VERSION 5.8 ;
BUSBITCHARS "[]" ;
DIVIDERCHAR "/" ;
UNITS
    DATABASE MICRONS 1000 ;
END UNITS

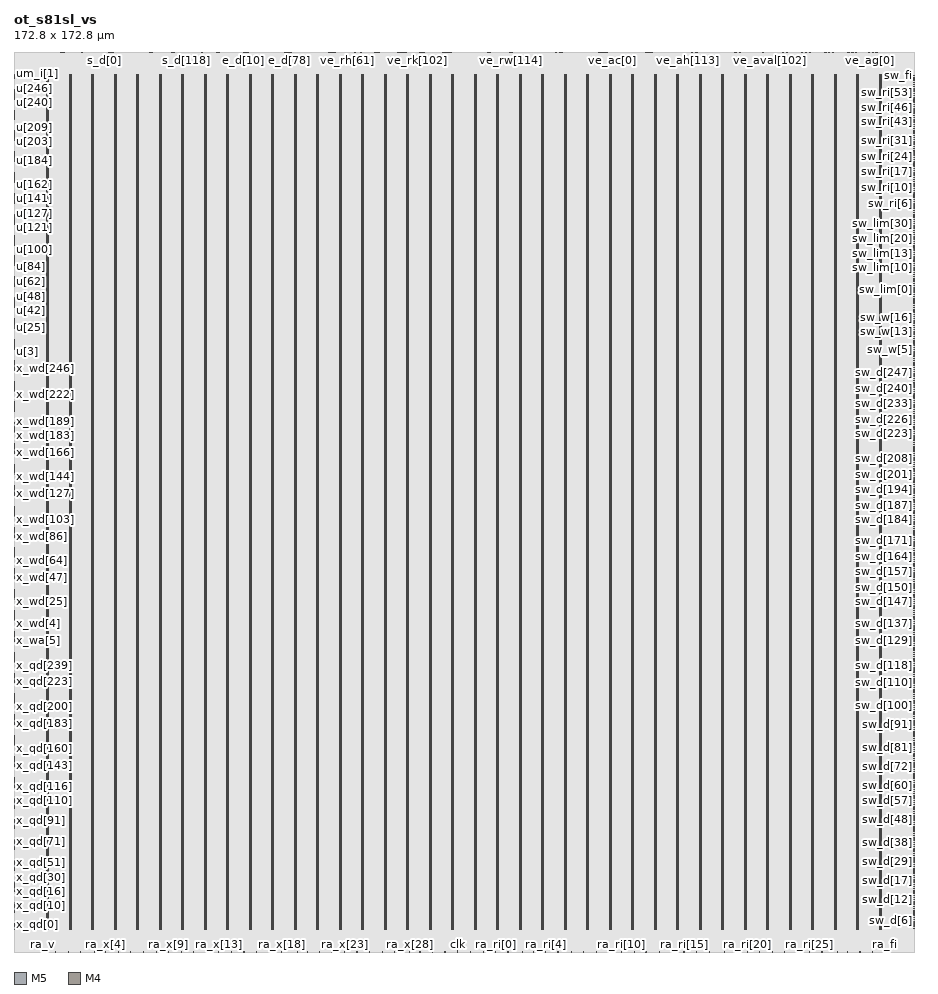
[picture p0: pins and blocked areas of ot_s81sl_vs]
MACRO ot_s81sl_vs
  FOREIGN ot_s81sl_vs 0 0 ;
  CLASS BLOCK ;
  SIZE 172.8 BY 172.8 ;
  PIN clk
    DIRECTION INPUT ;
    USE SIGNAL ;
    PORT
      LAYER M5 ;
        RECT  85.14 0 85.188 0.48 ;
    END
  END clk
  PIN e_c[0]
    DIRECTION OUTPUT ;
    USE SIGNAL ;
    PORT
      LAYER M5 ;
        RECT  42.672 172.716 42.696 172.8 ;
    END
  END e_c[0]
  PIN e_c[1]
    DIRECTION OUTPUT ;
    USE SIGNAL ;
    PORT
      LAYER M5 ;
        RECT  42.768 172.716 42.792 172.8 ;
    END
  END e_c[1]
  PIN e_d[0]
    DIRECTION OUTPUT ;
    USE SIGNAL ;
    PORT
      LAYER M5 ;
        RECT  42.864 172.716 42.888 172.8 ;
    END
  END e_d[0]
  PIN e_d[10]
    DIRECTION OUTPUT ;
    USE SIGNAL ;
    PORT
      LAYER M5 ;
        RECT  43.968 172.716 43.992 172.8 ;
    END
  END e_d[10]
  PIN e_d[11]
    DIRECTION OUTPUT ;
    USE SIGNAL ;
    PORT
      LAYER M5 ;
        RECT  44.16 172.716 44.184 172.8 ;
    END
  END e_d[11]
  PIN e_d[12]
    DIRECTION OUTPUT ;
    USE SIGNAL ;
    PORT
      LAYER M5 ;
        RECT  44.256 172.716 44.28 172.8 ;
    END
  END e_d[12]
  PIN e_d[13]
    DIRECTION OUTPUT ;
    USE SIGNAL ;
    PORT
      LAYER M5 ;
        RECT  44.448 172.716 44.472 172.8 ;
    END
  END e_d[13]
  PIN e_d[14]
    DIRECTION OUTPUT ;
    USE SIGNAL ;
    PORT
      LAYER M5 ;
        RECT  44.544 172.716 44.568 172.8 ;
    END
  END e_d[14]
  PIN e_d[15]
    DIRECTION OUTPUT ;
    USE SIGNAL ;
    PORT
      LAYER M5 ;
        RECT  44.64 172.716 44.664 172.8 ;
    END
  END e_d[15]
  PIN e_d[16]
    DIRECTION OUTPUT ;
    USE SIGNAL ;
    PORT
      LAYER M5 ;
        RECT  44.736 172.716 44.76 172.8 ;
    END
  END e_d[16]
  PIN e_d[17]
    DIRECTION OUTPUT ;
    USE SIGNAL ;
    PORT
      LAYER M5 ;
        RECT  44.928 172.716 44.952 172.8 ;
    END
  END e_d[17]
  PIN e_d[18]
    DIRECTION OUTPUT ;
    USE SIGNAL ;
    PORT
      LAYER M5 ;
        RECT  45.024 172.716 45.048 172.8 ;
    END
  END e_d[18]
  PIN e_d[19]
    DIRECTION OUTPUT ;
    USE SIGNAL ;
    PORT
      LAYER M5 ;
        RECT  45.744 172.716 45.768 172.8 ;
    END
  END e_d[19]
  PIN e_d[1]
    DIRECTION OUTPUT ;
    USE SIGNAL ;
    PORT
      LAYER M5 ;
        RECT  42.96 172.716 42.984 172.8 ;
    END
  END e_d[1]
  PIN e_d[20]
    DIRECTION OUTPUT ;
    USE SIGNAL ;
    PORT
      LAYER M5 ;
        RECT  45.84 172.716 45.864 172.8 ;
    END
  END e_d[20]
  PIN e_d[21]
    DIRECTION OUTPUT ;
    USE SIGNAL ;
    PORT
      LAYER M5 ;
        RECT  45.936 172.716 45.96 172.8 ;
    END
  END e_d[21]
  PIN e_d[22]
    DIRECTION OUTPUT ;
    USE SIGNAL ;
    PORT
      LAYER M5 ;
        RECT  46.032 172.716 46.056 172.8 ;
    END
  END e_d[22]
  PIN e_d[23]
    DIRECTION OUTPUT ;
    USE SIGNAL ;
    PORT
      LAYER M5 ;
        RECT  46.128 172.716 46.152 172.8 ;
    END
  END e_d[23]
  PIN e_d[24]
    DIRECTION OUTPUT ;
    USE SIGNAL ;
    PORT
      LAYER M5 ;
        RECT  46.224 172.716 46.248 172.8 ;
    END
  END e_d[24]
  PIN e_d[25]
    DIRECTION OUTPUT ;
    USE SIGNAL ;
    PORT
      LAYER M5 ;
        RECT  46.32 172.716 46.344 172.8 ;
    END
  END e_d[25]
  PIN e_d[26]
    DIRECTION OUTPUT ;
    USE SIGNAL ;
    PORT
      LAYER M5 ;
        RECT  46.416 172.716 46.44 172.8 ;
    END
  END e_d[26]
  PIN e_d[27]
    DIRECTION OUTPUT ;
    USE SIGNAL ;
    PORT
      LAYER M5 ;
        RECT  46.512 172.716 46.536 172.8 ;
    END
  END e_d[27]
  PIN e_d[28]
    DIRECTION OUTPUT ;
    USE SIGNAL ;
    PORT
      LAYER M5 ;
        RECT  46.608 172.716 46.632 172.8 ;
    END
  END e_d[28]
  PIN e_d[29]
    DIRECTION OUTPUT ;
    USE SIGNAL ;
    PORT
      LAYER M5 ;
        RECT  46.704 172.716 46.728 172.8 ;
    END
  END e_d[29]
  PIN e_d[2]
    DIRECTION OUTPUT ;
    USE SIGNAL ;
    PORT
      LAYER M5 ;
        RECT  43.056 172.716 43.08 172.8 ;
    END
  END e_d[2]
  PIN e_d[30]
    DIRECTION OUTPUT ;
    USE SIGNAL ;
    PORT
      LAYER M5 ;
        RECT  46.8 172.716 46.824 172.8 ;
    END
  END e_d[30]
  PIN e_d[31]
    DIRECTION OUTPUT ;
    USE SIGNAL ;
    PORT
      LAYER M5 ;
        RECT  46.896 172.716 46.92 172.8 ;
    END
  END e_d[31]
  PIN e_d[32]
    DIRECTION OUTPUT ;
    USE SIGNAL ;
    PORT
      LAYER M5 ;
        RECT  46.992 172.716 47.016 172.8 ;
    END
  END e_d[32]
  PIN e_d[33]
    DIRECTION OUTPUT ;
    USE SIGNAL ;
    PORT
      LAYER M5 ;
        RECT  47.088 172.716 47.112 172.8 ;
    END
  END e_d[33]
  PIN e_d[34]
    DIRECTION OUTPUT ;
    USE SIGNAL ;
    PORT
      LAYER M5 ;
        RECT  47.184 172.716 47.208 172.8 ;
    END
  END e_d[34]
  PIN e_d[35]
    DIRECTION OUTPUT ;
    USE SIGNAL ;
    PORT
      LAYER M5 ;
        RECT  47.28 172.716 47.304 172.8 ;
    END
  END e_d[35]
  PIN e_d[36]
    DIRECTION OUTPUT ;
    USE SIGNAL ;
    PORT
      LAYER M5 ;
        RECT  47.376 172.716 47.4 172.8 ;
    END
  END e_d[36]
  PIN e_d[37]
    DIRECTION OUTPUT ;
    USE SIGNAL ;
    PORT
      LAYER M5 ;
        RECT  47.52 172.716 47.544 172.8 ;
    END
  END e_d[37]
  PIN e_d[38]
    DIRECTION OUTPUT ;
    USE SIGNAL ;
    PORT
      LAYER M5 ;
        RECT  47.616 172.716 47.64 172.8 ;
    END
  END e_d[38]
  PIN e_d[39]
    DIRECTION OUTPUT ;
    USE SIGNAL ;
    PORT
      LAYER M5 ;
        RECT  47.808 172.716 47.832 172.8 ;
    END
  END e_d[39]
  PIN e_d[3]
    DIRECTION OUTPUT ;
    USE SIGNAL ;
    PORT
      LAYER M5 ;
        RECT  43.152 172.716 43.176 172.8 ;
    END
  END e_d[3]
  PIN e_d[40]
    DIRECTION OUTPUT ;
    USE SIGNAL ;
    PORT
      LAYER M5 ;
        RECT  47.904 172.716 47.928 172.8 ;
    END
  END e_d[40]
  PIN e_d[41]
    DIRECTION OUTPUT ;
    USE SIGNAL ;
    PORT
      LAYER M5 ;
        RECT  48 172.716 48.024 172.8 ;
    END
  END e_d[41]
  PIN e_d[42]
    DIRECTION OUTPUT ;
    USE SIGNAL ;
    PORT
      LAYER M5 ;
        RECT  48.192 172.716 48.216 172.8 ;
    END
  END e_d[42]
  PIN e_d[43]
    DIRECTION OUTPUT ;
    USE SIGNAL ;
    PORT
      LAYER M5 ;
        RECT  48.288 172.716 48.312 172.8 ;
    END
  END e_d[43]
  PIN e_d[44]
    DIRECTION OUTPUT ;
    USE SIGNAL ;
    PORT
      LAYER M5 ;
        RECT  48.48 172.716 48.504 172.8 ;
    END
  END e_d[44]
  PIN e_d[45]
    DIRECTION OUTPUT ;
    USE SIGNAL ;
    PORT
      LAYER M5 ;
        RECT  48.576 172.716 48.6 172.8 ;
    END
  END e_d[45]
  PIN e_d[46]
    DIRECTION OUTPUT ;
    USE SIGNAL ;
    PORT
      LAYER M5 ;
        RECT  48.672 172.716 48.696 172.8 ;
    END
  END e_d[46]
  PIN e_d[47]
    DIRECTION OUTPUT ;
    USE SIGNAL ;
    PORT
      LAYER M5 ;
        RECT  48.768 172.716 48.792 172.8 ;
    END
  END e_d[47]
  PIN e_d[48]
    DIRECTION OUTPUT ;
    USE SIGNAL ;
    PORT
      LAYER M5 ;
        RECT  48.96 172.716 48.984 172.8 ;
    END
  END e_d[48]
  PIN e_d[49]
    DIRECTION OUTPUT ;
    USE SIGNAL ;
    PORT
      LAYER M5 ;
        RECT  49.056 172.716 49.08 172.8 ;
    END
  END e_d[49]
  PIN e_d[4]
    DIRECTION OUTPUT ;
    USE SIGNAL ;
    PORT
      LAYER M5 ;
        RECT  43.296 172.716 43.32 172.8 ;
    END
  END e_d[4]
  PIN e_d[50]
    DIRECTION OUTPUT ;
    USE SIGNAL ;
    PORT
      LAYER M5 ;
        RECT  49.152 172.716 49.176 172.8 ;
    END
  END e_d[50]
  PIN e_d[51]
    DIRECTION OUTPUT ;
    USE SIGNAL ;
    PORT
      LAYER M5 ;
        RECT  49.344 172.716 49.368 172.8 ;
    END
  END e_d[51]
  PIN e_d[52]
    DIRECTION OUTPUT ;
    USE SIGNAL ;
    PORT
      LAYER M5 ;
        RECT  50.064 172.716 50.088 172.8 ;
    END
  END e_d[52]
  PIN e_d[53]
    DIRECTION OUTPUT ;
    USE SIGNAL ;
    PORT
      LAYER M5 ;
        RECT  50.16 172.716 50.184 172.8 ;
    END
  END e_d[53]
  PIN e_d[54]
    DIRECTION OUTPUT ;
    USE SIGNAL ;
    PORT
      LAYER M5 ;
        RECT  50.256 172.716 50.28 172.8 ;
    END
  END e_d[54]
  PIN e_d[55]
    DIRECTION OUTPUT ;
    USE SIGNAL ;
    PORT
      LAYER M5 ;
        RECT  50.352 172.716 50.376 172.8 ;
    END
  END e_d[55]
  PIN e_d[56]
    DIRECTION OUTPUT ;
    USE SIGNAL ;
    PORT
      LAYER M5 ;
        RECT  50.448 172.716 50.472 172.8 ;
    END
  END e_d[56]
  PIN e_d[57]
    DIRECTION OUTPUT ;
    USE SIGNAL ;
    PORT
      LAYER M5 ;
        RECT  50.544 172.716 50.568 172.8 ;
    END
  END e_d[57]
  PIN e_d[58]
    DIRECTION OUTPUT ;
    USE SIGNAL ;
    PORT
      LAYER M5 ;
        RECT  50.64 172.716 50.664 172.8 ;
    END
  END e_d[58]
  PIN e_d[59]
    DIRECTION OUTPUT ;
    USE SIGNAL ;
    PORT
      LAYER M5 ;
        RECT  50.736 172.716 50.76 172.8 ;
    END
  END e_d[59]
  PIN e_d[5]
    DIRECTION OUTPUT ;
    USE SIGNAL ;
    PORT
      LAYER M5 ;
        RECT  43.392 172.716 43.416 172.8 ;
    END
  END e_d[5]
  PIN e_d[60]
    DIRECTION OUTPUT ;
    USE SIGNAL ;
    PORT
      LAYER M5 ;
        RECT  50.832 172.716 50.856 172.8 ;
    END
  END e_d[60]
  PIN e_d[61]
    DIRECTION OUTPUT ;
    USE SIGNAL ;
    PORT
      LAYER M5 ;
        RECT  50.928 172.716 50.952 172.8 ;
    END
  END e_d[61]
  PIN e_d[62]
    DIRECTION OUTPUT ;
    USE SIGNAL ;
    PORT
      LAYER M5 ;
        RECT  51.024 172.716 51.048 172.8 ;
    END
  END e_d[62]
  PIN e_d[63]
    DIRECTION OUTPUT ;
    USE SIGNAL ;
    PORT
      LAYER M5 ;
        RECT  51.12 172.716 51.144 172.8 ;
    END
  END e_d[63]
  PIN e_d[64]
    DIRECTION OUTPUT ;
    USE SIGNAL ;
    PORT
      LAYER M5 ;
        RECT  51.216 172.716 51.24 172.8 ;
    END
  END e_d[64]
  PIN e_d[65]
    DIRECTION OUTPUT ;
    USE SIGNAL ;
    PORT
      LAYER M5 ;
        RECT  51.312 172.716 51.336 172.8 ;
    END
  END e_d[65]
  PIN e_d[66]
    DIRECTION OUTPUT ;
    USE SIGNAL ;
    PORT
      LAYER M5 ;
        RECT  51.408 172.716 51.432 172.8 ;
    END
  END e_d[66]
  PIN e_d[67]
    DIRECTION OUTPUT ;
    USE SIGNAL ;
    PORT
      LAYER M5 ;
        RECT  51.504 172.716 51.528 172.8 ;
    END
  END e_d[67]
  PIN e_d[68]
    DIRECTION OUTPUT ;
    USE SIGNAL ;
    PORT
      LAYER M5 ;
        RECT  51.6 172.716 51.624 172.8 ;
    END
  END e_d[68]
  PIN e_d[69]
    DIRECTION OUTPUT ;
    USE SIGNAL ;
    PORT
      LAYER M5 ;
        RECT  51.696 172.716 51.72 172.8 ;
    END
  END e_d[69]
  PIN e_d[6]
    DIRECTION OUTPUT ;
    USE SIGNAL ;
    PORT
      LAYER M5 ;
        RECT  43.488 172.716 43.512 172.8 ;
    END
  END e_d[6]
  PIN e_d[70]
    DIRECTION OUTPUT ;
    USE SIGNAL ;
    PORT
      LAYER M5 ;
        RECT  51.792 172.716 51.816 172.8 ;
    END
  END e_d[70]
  PIN e_d[71]
    DIRECTION OUTPUT ;
    USE SIGNAL ;
    PORT
      LAYER M5 ;
        RECT  51.936 172.716 51.96 172.8 ;
    END
  END e_d[71]
  PIN e_d[72]
    DIRECTION OUTPUT ;
    USE SIGNAL ;
    PORT
      LAYER M5 ;
        RECT  52.032 172.716 52.056 172.8 ;
    END
  END e_d[72]
  PIN e_d[73]
    DIRECTION OUTPUT ;
    USE SIGNAL ;
    PORT
      LAYER M5 ;
        RECT  52.224 172.716 52.248 172.8 ;
    END
  END e_d[73]
  PIN e_d[74]
    DIRECTION OUTPUT ;
    USE SIGNAL ;
    PORT
      LAYER M5 ;
        RECT  52.32 172.716 52.344 172.8 ;
    END
  END e_d[74]
  PIN e_d[75]
    DIRECTION OUTPUT ;
    USE SIGNAL ;
    PORT
      LAYER M5 ;
        RECT  52.416 172.716 52.44 172.8 ;
    END
  END e_d[75]
  PIN e_d[76]
    DIRECTION OUTPUT ;
    USE SIGNAL ;
    PORT
      LAYER M5 ;
        RECT  52.512 172.716 52.536 172.8 ;
    END
  END e_d[76]
  PIN e_d[77]
    DIRECTION OUTPUT ;
    USE SIGNAL ;
    PORT
      LAYER M5 ;
        RECT  52.704 172.716 52.728 172.8 ;
    END
  END e_d[77]
  PIN e_d[78]
    DIRECTION OUTPUT ;
    USE SIGNAL ;
    PORT
      LAYER M5 ;
        RECT  52.8 172.716 52.824 172.8 ;
    END
  END e_d[78]
  PIN e_d[79]
    DIRECTION OUTPUT ;
    USE SIGNAL ;
    PORT
      LAYER M5 ;
        RECT  52.992 172.716 53.016 172.8 ;
    END
  END e_d[79]
  PIN e_d[7]
    DIRECTION OUTPUT ;
    USE SIGNAL ;
    PORT
      LAYER M5 ;
        RECT  43.584 172.716 43.608 172.8 ;
    END
  END e_d[7]
  PIN e_d[80]
    DIRECTION OUTPUT ;
    USE SIGNAL ;
    PORT
      LAYER M5 ;
        RECT  53.088 172.716 53.112 172.8 ;
    END
  END e_d[80]
  PIN e_d[81]
    DIRECTION OUTPUT ;
    USE SIGNAL ;
    PORT
      LAYER M5 ;
        RECT  53.184 172.716 53.208 172.8 ;
    END
  END e_d[81]
  PIN e_d[82]
    DIRECTION OUTPUT ;
    USE SIGNAL ;
    PORT
      LAYER M5 ;
        RECT  53.376 172.716 53.4 172.8 ;
    END
  END e_d[82]
  PIN e_d[83]
    DIRECTION OUTPUT ;
    USE SIGNAL ;
    PORT
      LAYER M5 ;
        RECT  53.472 172.716 53.496 172.8 ;
    END
  END e_d[83]
  PIN e_d[84]
    DIRECTION OUTPUT ;
    USE SIGNAL ;
    PORT
      LAYER M5 ;
        RECT  53.664 172.716 53.688 172.8 ;
    END
  END e_d[84]
  PIN e_d[85]
    DIRECTION OUTPUT ;
    USE SIGNAL ;
    PORT
      LAYER M5 ;
        RECT  54.384 172.716 54.408 172.8 ;
    END
  END e_d[85]
  PIN e_d[86]
    DIRECTION OUTPUT ;
    USE SIGNAL ;
    PORT
      LAYER M5 ;
        RECT  54.48 172.716 54.504 172.8 ;
    END
  END e_d[86]
  PIN e_d[87]
    DIRECTION OUTPUT ;
    USE SIGNAL ;
    PORT
      LAYER M5 ;
        RECT  54.576 172.716 54.6 172.8 ;
    END
  END e_d[87]
  PIN e_d[88]
    DIRECTION OUTPUT ;
    USE SIGNAL ;
    PORT
      LAYER M5 ;
        RECT  54.672 172.716 54.696 172.8 ;
    END
  END e_d[88]
  PIN e_d[89]
    DIRECTION OUTPUT ;
    USE SIGNAL ;
    PORT
      LAYER M5 ;
        RECT  54.768 172.716 54.792 172.8 ;
    END
  END e_d[89]
  PIN e_d[8]
    DIRECTION OUTPUT ;
    USE SIGNAL ;
    PORT
      LAYER M5 ;
        RECT  43.776 172.716 43.8 172.8 ;
    END
  END e_d[8]
  PIN e_d[90]
    DIRECTION OUTPUT ;
    USE SIGNAL ;
    PORT
      LAYER M5 ;
        RECT  54.864 172.716 54.888 172.8 ;
    END
  END e_d[90]
  PIN e_d[91]
    DIRECTION OUTPUT ;
    USE SIGNAL ;
    PORT
      LAYER M5 ;
        RECT  54.96 172.716 54.984 172.8 ;
    END
  END e_d[91]
  PIN e_d[92]
    DIRECTION OUTPUT ;
    USE SIGNAL ;
    PORT
      LAYER M5 ;
        RECT  55.056 172.716 55.08 172.8 ;
    END
  END e_d[92]
  PIN e_d[93]
    DIRECTION OUTPUT ;
    USE SIGNAL ;
    PORT
      LAYER M5 ;
        RECT  55.152 172.716 55.176 172.8 ;
    END
  END e_d[93]
  PIN e_d[94]
    DIRECTION OUTPUT ;
    USE SIGNAL ;
    PORT
      LAYER M5 ;
        RECT  55.248 172.716 55.272 172.8 ;
    END
  END e_d[94]
  PIN e_d[95]
    DIRECTION OUTPUT ;
    USE SIGNAL ;
    PORT
      LAYER M5 ;
        RECT  55.344 172.716 55.368 172.8 ;
    END
  END e_d[95]
  PIN e_d[9]
    DIRECTION OUTPUT ;
    USE SIGNAL ;
    PORT
      LAYER M5 ;
        RECT  43.872 172.716 43.896 172.8 ;
    END
  END e_d[9]
  PIN e_v
    DIRECTION OUTPUT ;
    USE SIGNAL ;
    PORT
      LAYER M5 ;
        RECT  42.576 172.716 42.6 172.8 ;
    END
  END e_v
  PIN fault
    DIRECTION OUTPUT ;
    USE SIGNAL ;
    PORT
      LAYER M5 ;
        RECT  55.44 172.716 55.464 172.8 ;
    END
  END fault
  PIN g_c[0]
    DIRECTION INPUT ;
    USE SIGNAL ;
    PORT
      LAYER M5 ;
        RECT  38.16 172.716 38.184 172.8 ;
    END
  END g_c[0]
  PIN g_c[1]
    DIRECTION INPUT ;
    USE SIGNAL ;
    PORT
      LAYER M5 ;
        RECT  38.256 172.716 38.28 172.8 ;
    END
  END g_c[1]
  PIN g_d[0]
    DIRECTION INPUT ;
    USE SIGNAL ;
    PORT
      LAYER M5 ;
        RECT  38.352 172.716 38.376 172.8 ;
    END
  END g_d[0]
  PIN g_d[10]
    DIRECTION INPUT ;
    USE SIGNAL ;
    PORT
      LAYER M5 ;
        RECT  39.456 172.716 39.48 172.8 ;
    END
  END g_d[10]
  PIN g_d[11]
    DIRECTION INPUT ;
    USE SIGNAL ;
    PORT
      LAYER M5 ;
        RECT  39.552 172.716 39.576 172.8 ;
    END
  END g_d[11]
  PIN g_d[12]
    DIRECTION INPUT ;
    USE SIGNAL ;
    PORT
      LAYER M5 ;
        RECT  39.744 172.716 39.768 172.8 ;
    END
  END g_d[12]
  PIN g_d[13]
    DIRECTION INPUT ;
    USE SIGNAL ;
    PORT
      LAYER M5 ;
        RECT  39.84 172.716 39.864 172.8 ;
    END
  END g_d[13]
  PIN g_d[14]
    DIRECTION INPUT ;
    USE SIGNAL ;
    PORT
      LAYER M5 ;
        RECT  40.032 172.716 40.056 172.8 ;
    END
  END g_d[14]
  PIN g_d[15]
    DIRECTION INPUT ;
    USE SIGNAL ;
    PORT
      LAYER M5 ;
        RECT  40.128 172.716 40.152 172.8 ;
    END
  END g_d[15]
  PIN g_d[16]
    DIRECTION INPUT ;
    USE SIGNAL ;
    PORT
      LAYER M5 ;
        RECT  40.224 172.716 40.248 172.8 ;
    END
  END g_d[16]
  PIN g_d[17]
    DIRECTION INPUT ;
    USE SIGNAL ;
    PORT
      LAYER M5 ;
        RECT  40.416 172.716 40.44 172.8 ;
    END
  END g_d[17]
  PIN g_d[18]
    DIRECTION INPUT ;
    USE SIGNAL ;
    PORT
      LAYER M5 ;
        RECT  40.512 172.716 40.536 172.8 ;
    END
  END g_d[18]
  PIN g_d[19]
    DIRECTION INPUT ;
    USE SIGNAL ;
    PORT
      LAYER M5 ;
        RECT  40.704 172.716 40.728 172.8 ;
    END
  END g_d[19]
  PIN g_d[1]
    DIRECTION INPUT ;
    USE SIGNAL ;
    PORT
      LAYER M5 ;
        RECT  38.448 172.716 38.472 172.8 ;
    END
  END g_d[1]
  PIN g_d[20]
    DIRECTION INPUT ;
    USE SIGNAL ;
    PORT
      LAYER M5 ;
        RECT  41.424 172.716 41.448 172.8 ;
    END
  END g_d[20]
  PIN g_d[21]
    DIRECTION INPUT ;
    USE SIGNAL ;
    PORT
      LAYER M5 ;
        RECT  41.52 172.716 41.544 172.8 ;
    END
  END g_d[21]
  PIN g_d[22]
    DIRECTION INPUT ;
    USE SIGNAL ;
    PORT
      LAYER M5 ;
        RECT  41.616 172.716 41.64 172.8 ;
    END
  END g_d[22]
  PIN g_d[23]
    DIRECTION INPUT ;
    USE SIGNAL ;
    PORT
      LAYER M5 ;
        RECT  41.712 172.716 41.736 172.8 ;
    END
  END g_d[23]
  PIN g_d[24]
    DIRECTION INPUT ;
    USE SIGNAL ;
    PORT
      LAYER M5 ;
        RECT  41.808 172.716 41.832 172.8 ;
    END
  END g_d[24]
  PIN g_d[25]
    DIRECTION INPUT ;
    USE SIGNAL ;
    PORT
      LAYER M5 ;
        RECT  41.904 172.716 41.928 172.8 ;
    END
  END g_d[25]
  PIN g_d[26]
    DIRECTION INPUT ;
    USE SIGNAL ;
    PORT
      LAYER M5 ;
        RECT  42 172.716 42.024 172.8 ;
    END
  END g_d[26]
  PIN g_d[27]
    DIRECTION INPUT ;
    USE SIGNAL ;
    PORT
      LAYER M5 ;
        RECT  42.096 172.716 42.12 172.8 ;
    END
  END g_d[27]
  PIN g_d[28]
    DIRECTION INPUT ;
    USE SIGNAL ;
    PORT
      LAYER M5 ;
        RECT  42.192 172.716 42.216 172.8 ;
    END
  END g_d[28]
  PIN g_d[29]
    DIRECTION INPUT ;
    USE SIGNAL ;
    PORT
      LAYER M5 ;
        RECT  42.288 172.716 42.312 172.8 ;
    END
  END g_d[29]
  PIN g_d[2]
    DIRECTION INPUT ;
    USE SIGNAL ;
    PORT
      LAYER M5 ;
        RECT  38.544 172.716 38.568 172.8 ;
    END
  END g_d[2]
  PIN g_d[30]
    DIRECTION INPUT ;
    USE SIGNAL ;
    PORT
      LAYER M5 ;
        RECT  42.384 172.716 42.408 172.8 ;
    END
  END g_d[30]
  PIN g_d[31]
    DIRECTION INPUT ;
    USE SIGNAL ;
    PORT
      LAYER M5 ;
        RECT  42.48 172.716 42.504 172.8 ;
    END
  END g_d[31]
  PIN g_d[3]
    DIRECTION INPUT ;
    USE SIGNAL ;
    PORT
      LAYER M5 ;
        RECT  38.64 172.716 38.664 172.8 ;
    END
  END g_d[3]
  PIN g_d[4]
    DIRECTION INPUT ;
    USE SIGNAL ;
    PORT
      LAYER M5 ;
        RECT  38.736 172.716 38.76 172.8 ;
    END
  END g_d[4]
  PIN g_d[5]
    DIRECTION INPUT ;
    USE SIGNAL ;
    PORT
      LAYER M5 ;
        RECT  38.832 172.716 38.856 172.8 ;
    END
  END g_d[5]
  PIN g_d[6]
    DIRECTION INPUT ;
    USE SIGNAL ;
    PORT
      LAYER M5 ;
        RECT  38.976 172.716 39 172.8 ;
    END
  END g_d[6]
  PIN g_d[7]
    DIRECTION INPUT ;
    USE SIGNAL ;
    PORT
      LAYER M5 ;
        RECT  39.072 172.716 39.096 172.8 ;
    END
  END g_d[7]
  PIN g_d[8]
    DIRECTION INPUT ;
    USE SIGNAL ;
    PORT
      LAYER M5 ;
        RECT  39.264 172.716 39.288 172.8 ;
    END
  END g_d[8]
  PIN g_d[9]
    DIRECTION INPUT ;
    USE SIGNAL ;
    PORT
      LAYER M5 ;
        RECT  39.36 172.716 39.384 172.8 ;
    END
  END g_d[9]
  PIN g_v
    DIRECTION INPUT ;
    USE SIGNAL ;
    PORT
      LAYER M5 ;
        RECT  38.064 172.716 38.088 172.8 ;
    END
  END g_v
  PIN ra_fi
    DIRECTION INPUT ;
    USE SIGNAL ;
    PORT
      LAYER M5 ;
        RECT  167.232 0 167.256 0.084 ;
    END
  END ra_fi
  PIN ra_ri[0]
    DIRECTION INPUT ;
    USE SIGNAL ;
    PORT
      LAYER M5 ;
        RECT  92.448 0 92.472 0.084 ;
    END
  END ra_ri[0]
  PIN ra_ri[10]
    DIRECTION INPUT ;
    USE SIGNAL ;
    PORT
      LAYER M5 ;
        RECT  116.544 0 116.568 0.084 ;
    END
  END ra_ri[10]
  PIN ra_ri[11]
    DIRECTION INPUT ;
    USE SIGNAL ;
    PORT
      LAYER M5 ;
        RECT  119.184 0 119.208 0.084 ;
    END
  END ra_ri[11]
  PIN ra_ri[12]
    DIRECTION INPUT ;
    USE SIGNAL ;
    PORT
      LAYER M5 ;
        RECT  121.344 0 121.368 0.084 ;
    END
  END ra_ri[12]
  PIN ra_ri[13]
    DIRECTION INPUT ;
    USE SIGNAL ;
    PORT
      LAYER M5 ;
        RECT  123.84 0 123.864 0.084 ;
    END
  END ra_ri[13]
  PIN ra_ri[14]
    DIRECTION INPUT ;
    USE SIGNAL ;
    PORT
      LAYER M5 ;
        RECT  126.24 0 126.264 0.084 ;
    END
  END ra_ri[14]
  PIN ra_ri[15]
    DIRECTION INPUT ;
    USE SIGNAL ;
    PORT
      LAYER M5 ;
        RECT  128.64 0 128.664 0.084 ;
    END
  END ra_ri[15]
  PIN ra_ri[16]
    DIRECTION INPUT ;
    USE SIGNAL ;
    PORT
      LAYER M5 ;
        RECT  131.04 0 131.064 0.084 ;
    END
  END ra_ri[16]
  PIN ra_ri[17]
    DIRECTION INPUT ;
    USE SIGNAL ;
    PORT
      LAYER M5 ;
        RECT  133.44 0 133.464 0.084 ;
    END
  END ra_ri[17]
  PIN ra_ri[18]
    DIRECTION INPUT ;
    USE SIGNAL ;
    PORT
      LAYER M5 ;
        RECT  136.464 0 136.488 0.084 ;
    END
  END ra_ri[18]
  PIN ra_ri[19]
    DIRECTION INPUT ;
    USE SIGNAL ;
    PORT
      LAYER M5 ;
        RECT  138.336 0 138.36 0.084 ;
    END
  END ra_ri[19]
  PIN ra_ri[1]
    DIRECTION INPUT ;
    USE SIGNAL ;
    PORT
      LAYER M5 ;
        RECT  94.848 0 94.872 0.084 ;
    END
  END ra_ri[1]
  PIN ra_ri[20]
    DIRECTION INPUT ;
    USE SIGNAL ;
    PORT
      LAYER M5 ;
        RECT  140.784 0 140.808 0.084 ;
    END
  END ra_ri[20]
  PIN ra_ri[21]
    DIRECTION INPUT ;
    USE SIGNAL ;
    PORT
      LAYER M5 ;
        RECT  143.136 0 143.16 0.084 ;
    END
  END ra_ri[21]
  PIN ra_ri[22]
    DIRECTION INPUT ;
    USE SIGNAL ;
    PORT
      LAYER M5 ;
        RECT  145.536 0 145.56 0.084 ;
    END
  END ra_ri[22]
  PIN ra_ri[23]
    DIRECTION INPUT ;
    USE SIGNAL ;
    PORT
      LAYER M5 ;
        RECT  147.936 0 147.96 0.084 ;
    END
  END ra_ri[23]
  PIN ra_ri[24]
    DIRECTION INPUT ;
    USE SIGNAL ;
    PORT
      LAYER M5 ;
        RECT  150.336 0 150.36 0.084 ;
    END
  END ra_ri[24]
  PIN ra_ri[25]
    DIRECTION INPUT ;
    USE SIGNAL ;
    PORT
      LAYER M5 ;
        RECT  152.736 0 152.76 0.084 ;
    END
  END ra_ri[25]
  PIN ra_ri[26]
    DIRECTION INPUT ;
    USE SIGNAL ;
    PORT
      LAYER M5 ;
        RECT  155.136 0 155.16 0.084 ;
    END
  END ra_ri[26]
  PIN ra_ri[27]
    DIRECTION INPUT ;
    USE SIGNAL ;
    PORT
      LAYER M5 ;
        RECT  158.064 0 158.088 0.084 ;
    END
  END ra_ri[27]
  PIN ra_ri[28]
    DIRECTION INPUT ;
    USE SIGNAL ;
    PORT
      LAYER M5 ;
        RECT  160.032 0 160.056 0.084 ;
    END
  END ra_ri[28]
  PIN ra_ri[29]
    DIRECTION INPUT ;
    USE SIGNAL ;
    PORT
      LAYER M5 ;
        RECT  162.432 0 162.456 0.084 ;
    END
  END ra_ri[29]
  PIN ra_ri[2]
    DIRECTION INPUT ;
    USE SIGNAL ;
    PORT
      LAYER M5 ;
        RECT  97.584 0 97.608 0.084 ;
    END
  END ra_ri[2]
  PIN ra_ri[30]
    DIRECTION INPUT ;
    USE SIGNAL ;
    PORT
      LAYER M5 ;
        RECT  164.832 0 164.856 0.084 ;
    END
  END ra_ri[30]
  PIN ra_ri[3]
    DIRECTION INPUT ;
    USE SIGNAL ;
    PORT
      LAYER M5 ;
        RECT  99.648 0 99.672 0.084 ;
    END
  END ra_ri[3]
  PIN ra_ri[4]
    DIRECTION INPUT ;
    USE SIGNAL ;
    PORT
      LAYER M5 ;
        RECT  102.048 0 102.072 0.084 ;
    END
  END ra_ri[4]
  PIN ra_ri[5]
    DIRECTION INPUT ;
    USE SIGNAL ;
    PORT
      LAYER M5 ;
        RECT  104.448 0 104.472 0.084 ;
    END
  END ra_ri[5]
  PIN ra_ri[6]
    DIRECTION INPUT ;
    USE SIGNAL ;
    PORT
      LAYER M5 ;
        RECT  106.944 0 106.968 0.084 ;
    END
  END ra_ri[6]
  PIN ra_ri[7]
    DIRECTION INPUT ;
    USE SIGNAL ;
    PORT
      LAYER M5 ;
        RECT  109.344 0 109.368 0.084 ;
    END
  END ra_ri[7]
  PIN ra_ri[8]
    DIRECTION INPUT ;
    USE SIGNAL ;
    PORT
      LAYER M5 ;
        RECT  111.744 0 111.768 0.084 ;
    END
  END ra_ri[8]
  PIN ra_ri[9]
    DIRECTION INPUT ;
    USE SIGNAL ;
    PORT
      LAYER M5 ;
        RECT  114.144 0 114.168 0.084 ;
    END
  END ra_ri[9]
  PIN ra_v
    DIRECTION OUTPUT ;
    USE SIGNAL ;
    PORT
      LAYER M5 ;
        RECT  5.568 0 5.592 0.084 ;
    END
  END ra_v
  PIN ra_vi
    DIRECTION INPUT ;
    USE SIGNAL ;
    PORT
      LAYER M5 ;
        RECT  90.048 0 90.072 0.084 ;
    END
  END ra_vi
  PIN ra_x[0]
    DIRECTION OUTPUT ;
    USE SIGNAL ;
    PORT
      LAYER M5 ;
        RECT  7.968 0 7.992 0.084 ;
    END
  END ra_x[0]
  PIN ra_x[10]
    DIRECTION OUTPUT ;
    USE SIGNAL ;
    PORT
      LAYER M5 ;
        RECT  32.064 0 32.088 0.084 ;
    END
  END ra_x[10]
  PIN ra_x[11]
    DIRECTION OUTPUT ;
    USE SIGNAL ;
    PORT
      LAYER M5 ;
        RECT  34.464 0 34.488 0.084 ;
    END
  END ra_x[11]
  PIN ra_x[12]
    DIRECTION OUTPUT ;
    USE SIGNAL ;
    PORT
      LAYER M5 ;
        RECT  37.104 0 37.128 0.084 ;
    END
  END ra_x[12]
  PIN ra_x[13]
    DIRECTION OUTPUT ;
    USE SIGNAL ;
    PORT
      LAYER M5 ;
        RECT  39.264 0 39.288 0.084 ;
    END
  END ra_x[13]
  PIN ra_x[14]
    DIRECTION OUTPUT ;
    USE SIGNAL ;
    PORT
      LAYER M5 ;
        RECT  41.76 0 41.784 0.084 ;
    END
  END ra_x[14]
  PIN ra_x[15]
    DIRECTION OUTPUT ;
    USE SIGNAL ;
    PORT
      LAYER M5 ;
        RECT  44.16 0 44.184 0.084 ;
    END
  END ra_x[15]
  PIN ra_x[16]
    DIRECTION OUTPUT ;
    USE SIGNAL ;
    PORT
      LAYER M5 ;
        RECT  46.56 0 46.584 0.084 ;
    END
  END ra_x[16]
  PIN ra_x[17]
    DIRECTION OUTPUT ;
    USE SIGNAL ;
    PORT
      LAYER M5 ;
        RECT  48.96 0 48.984 0.084 ;
    END
  END ra_x[17]
  PIN ra_x[18]
    DIRECTION OUTPUT ;
    USE SIGNAL ;
    PORT
      LAYER M5 ;
        RECT  51.36 0 51.384 0.084 ;
    END
  END ra_x[18]
  PIN ra_x[19]
    DIRECTION OUTPUT ;
    USE SIGNAL ;
    PORT
      LAYER M5 ;
        RECT  54.384 0 54.408 0.084 ;
    END
  END ra_x[19]
  PIN ra_x[1]
    DIRECTION OUTPUT ;
    USE SIGNAL ;
    PORT
      LAYER M5 ;
        RECT  10.368 0 10.392 0.084 ;
    END
  END ra_x[1]
  PIN ra_x[20]
    DIRECTION OUTPUT ;
    USE SIGNAL ;
    PORT
      LAYER M5 ;
        RECT  56.256 0 56.28 0.084 ;
    END
  END ra_x[20]
  PIN ra_x[21]
    DIRECTION OUTPUT ;
    USE SIGNAL ;
    PORT
      LAYER M5 ;
        RECT  58.704 0 58.728 0.084 ;
    END
  END ra_x[21]
  PIN ra_x[22]
    DIRECTION OUTPUT ;
    USE SIGNAL ;
    PORT
      LAYER M5 ;
        RECT  61.056 0 61.08 0.084 ;
    END
  END ra_x[22]
  PIN ra_x[23]
    DIRECTION OUTPUT ;
    USE SIGNAL ;
    PORT
      LAYER M5 ;
        RECT  63.456 0 63.48 0.084 ;
    END
  END ra_x[23]
  PIN ra_x[24]
    DIRECTION OUTPUT ;
    USE SIGNAL ;
    PORT
      LAYER M5 ;
        RECT  65.856 0 65.88 0.084 ;
    END
  END ra_x[24]
  PIN ra_x[25]
    DIRECTION OUTPUT ;
    USE SIGNAL ;
    PORT
      LAYER M5 ;
        RECT  68.256 0 68.28 0.084 ;
    END
  END ra_x[25]
  PIN ra_x[26]
    DIRECTION OUTPUT ;
    USE SIGNAL ;
    PORT
      LAYER M5 ;
        RECT  70.656 0 70.68 0.084 ;
    END
  END ra_x[26]
  PIN ra_x[27]
    DIRECTION OUTPUT ;
    USE SIGNAL ;
    PORT
      LAYER M5 ;
        RECT  73.056 0 73.08 0.084 ;
    END
  END ra_x[27]
  PIN ra_x[28]
    DIRECTION OUTPUT ;
    USE SIGNAL ;
    PORT
      LAYER M5 ;
        RECT  75.984 0 76.008 0.084 ;
    END
  END ra_x[28]
  PIN ra_x[29]
    DIRECTION OUTPUT ;
    USE SIGNAL ;
    PORT
      LAYER M5 ;
        RECT  77.952 0 77.976 0.084 ;
    END
  END ra_x[29]
  PIN ra_x[2]
    DIRECTION OUTPUT ;
    USE SIGNAL ;
    PORT
      LAYER M5 ;
        RECT  12.768 0 12.792 0.084 ;
    END
  END ra_x[2]
  PIN ra_x[30]
    DIRECTION OUTPUT ;
    USE SIGNAL ;
    PORT
      LAYER M5 ;
        RECT  80.352 0 80.376 0.084 ;
    END
  END ra_x[30]
  PIN ra_x[31]
    DIRECTION OUTPUT ;
    USE SIGNAL ;
    PORT
      LAYER M5 ;
        RECT  82.752 0 82.776 0.084 ;
    END
  END ra_x[31]
  PIN ra_x[3]
    DIRECTION OUTPUT ;
    USE SIGNAL ;
    PORT
      LAYER M5 ;
        RECT  15.504 0 15.528 0.084 ;
    END
  END ra_x[3]
  PIN ra_x[4]
    DIRECTION OUTPUT ;
    USE SIGNAL ;
    PORT
      LAYER M5 ;
        RECT  17.568 0 17.592 0.084 ;
    END
  END ra_x[4]
  PIN ra_x[5]
    DIRECTION OUTPUT ;
    USE SIGNAL ;
    PORT
      LAYER M5 ;
        RECT  19.968 0 19.992 0.084 ;
    END
  END ra_x[5]
  PIN ra_x[6]
    DIRECTION OUTPUT ;
    USE SIGNAL ;
    PORT
      LAYER M5 ;
        RECT  22.368 0 22.392 0.084 ;
    END
  END ra_x[6]
  PIN ra_x[7]
    DIRECTION OUTPUT ;
    USE SIGNAL ;
    PORT
      LAYER M5 ;
        RECT  24.864 0 24.888 0.084 ;
    END
  END ra_x[7]
  PIN ra_x[8]
    DIRECTION OUTPUT ;
    USE SIGNAL ;
    PORT
      LAYER M5 ;
        RECT  27.264 0 27.288 0.084 ;
    END
  END ra_x[8]
  PIN ra_x[9]
    DIRECTION OUTPUT ;
    USE SIGNAL ;
    PORT
      LAYER M5 ;
        RECT  29.664 0 29.688 0.084 ;
    END
  END ra_x[9]
  PIN rst_n
    DIRECTION INPUT ;
    USE SIGNAL ;
    PORT
      LAYER M5 ;
        RECT  87.648 0 87.672 0.084 ;
    END
  END rst_n
  PIN s_d[0]
    DIRECTION INPUT ;
    USE SIGNAL ;
    PORT
      LAYER M5 ;
        RECT  17.376 172.716 17.4 172.8 ;
    END
  END s_d[0]
  PIN s_d[100]
    DIRECTION INPUT ;
    USE SIGNAL ;
    PORT
      LAYER M5 ;
        RECT  30.336 172.716 30.36 172.8 ;
    END
  END s_d[100]
  PIN s_d[101]
    DIRECTION INPUT ;
    USE SIGNAL ;
    PORT
      LAYER M5 ;
        RECT  30.432 172.716 30.456 172.8 ;
    END
  END s_d[101]
  PIN s_d[102]
    DIRECTION INPUT ;
    USE SIGNAL ;
    PORT
      LAYER M5 ;
        RECT  30.528 172.716 30.552 172.8 ;
    END
  END s_d[102]
  PIN s_d[103]
    DIRECTION INPUT ;
    USE SIGNAL ;
    PORT
      LAYER M5 ;
        RECT  30.72 172.716 30.744 172.8 ;
    END
  END s_d[103]
  PIN s_d[104]
    DIRECTION INPUT ;
    USE SIGNAL ;
    PORT
      LAYER M5 ;
        RECT  30.816 172.716 30.84 172.8 ;
    END
  END s_d[104]
  PIN s_d[105]
    DIRECTION INPUT ;
    USE SIGNAL ;
    PORT
      LAYER M5 ;
        RECT  30.912 172.716 30.936 172.8 ;
    END
  END s_d[105]
  PIN s_d[106]
    DIRECTION INPUT ;
    USE SIGNAL ;
    PORT
      LAYER M5 ;
        RECT  31.008 172.716 31.032 172.8 ;
    END
  END s_d[106]
  PIN s_d[107]
    DIRECTION INPUT ;
    USE SIGNAL ;
    PORT
      LAYER M5 ;
        RECT  31.2 172.716 31.224 172.8 ;
    END
  END s_d[107]
  PIN s_d[108]
    DIRECTION INPUT ;
    USE SIGNAL ;
    PORT
      LAYER M5 ;
        RECT  31.296 172.716 31.32 172.8 ;
    END
  END s_d[108]
  PIN s_d[109]
    DIRECTION INPUT ;
    USE SIGNAL ;
    PORT
      LAYER M5 ;
        RECT  31.488 172.716 31.512 172.8 ;
    END
  END s_d[109]
  PIN s_d[10]
    DIRECTION INPUT ;
    USE SIGNAL ;
    PORT
      LAYER M5 ;
        RECT  18.624 172.716 18.648 172.8 ;
    END
  END s_d[10]
  PIN s_d[110]
    DIRECTION INPUT ;
    USE SIGNAL ;
    PORT
      LAYER M5 ;
        RECT  31.584 172.716 31.608 172.8 ;
    END
  END s_d[110]
  PIN s_d[111]
    DIRECTION INPUT ;
    USE SIGNAL ;
    PORT
      LAYER M5 ;
        RECT  31.68 172.716 31.704 172.8 ;
    END
  END s_d[111]
  PIN s_d[112]
    DIRECTION INPUT ;
    USE SIGNAL ;
    PORT
      LAYER M5 ;
        RECT  31.776 172.716 31.8 172.8 ;
    END
  END s_d[112]
  PIN s_d[113]
    DIRECTION INPUT ;
    USE SIGNAL ;
    PORT
      LAYER M5 ;
        RECT  31.968 172.716 31.992 172.8 ;
    END
  END s_d[113]
  PIN s_d[114]
    DIRECTION INPUT ;
    USE SIGNAL ;
    PORT
      LAYER M5 ;
        RECT  32.064 172.716 32.088 172.8 ;
    END
  END s_d[114]
  PIN s_d[115]
    DIRECTION INPUT ;
    USE SIGNAL ;
    PORT
      LAYER M5 ;
        RECT  32.784 172.716 32.808 172.8 ;
    END
  END s_d[115]
  PIN s_d[116]
    DIRECTION INPUT ;
    USE SIGNAL ;
    PORT
      LAYER M5 ;
        RECT  32.88 172.716 32.904 172.8 ;
    END
  END s_d[116]
  PIN s_d[117]
    DIRECTION INPUT ;
    USE SIGNAL ;
    PORT
      LAYER M5 ;
        RECT  32.976 172.716 33 172.8 ;
    END
  END s_d[117]
  PIN s_d[118]
    DIRECTION INPUT ;
    USE SIGNAL ;
    PORT
      LAYER M5 ;
        RECT  33.072 172.716 33.096 172.8 ;
    END
  END s_d[118]
  PIN s_d[119]
    DIRECTION INPUT ;
    USE SIGNAL ;
    PORT
      LAYER M5 ;
        RECT  33.168 172.716 33.192 172.8 ;
    END
  END s_d[119]
  PIN s_d[11]
    DIRECTION INPUT ;
    USE SIGNAL ;
    PORT
      LAYER M5 ;
        RECT  18.72 172.716 18.744 172.8 ;
    END
  END s_d[11]
  PIN s_d[120]
    DIRECTION INPUT ;
    USE SIGNAL ;
    PORT
      LAYER M5 ;
        RECT  33.264 172.716 33.288 172.8 ;
    END
  END s_d[120]
  PIN s_d[121]
    DIRECTION INPUT ;
    USE SIGNAL ;
    PORT
      LAYER M5 ;
        RECT  33.36 172.716 33.384 172.8 ;
    END
  END s_d[121]
  PIN s_d[122]
    DIRECTION INPUT ;
    USE SIGNAL ;
    PORT
      LAYER M5 ;
        RECT  33.456 172.716 33.48 172.8 ;
    END
  END s_d[122]
  PIN s_d[123]
    DIRECTION INPUT ;
    USE SIGNAL ;
    PORT
      LAYER M5 ;
        RECT  33.552 172.716 33.576 172.8 ;
    END
  END s_d[123]
  PIN s_d[124]
    DIRECTION INPUT ;
    USE SIGNAL ;
    PORT
      LAYER M5 ;
        RECT  33.648 172.716 33.672 172.8 ;
    END
  END s_d[124]
  PIN s_d[125]
    DIRECTION INPUT ;
    USE SIGNAL ;
    PORT
      LAYER M5 ;
        RECT  33.744 172.716 33.768 172.8 ;
    END
  END s_d[125]
  PIN s_d[126]
    DIRECTION INPUT ;
    USE SIGNAL ;
    PORT
      LAYER M5 ;
        RECT  33.84 172.716 33.864 172.8 ;
    END
  END s_d[126]
  PIN s_d[127]
    DIRECTION INPUT ;
    USE SIGNAL ;
    PORT
      LAYER M5 ;
        RECT  33.936 172.716 33.96 172.8 ;
    END
  END s_d[127]
  PIN s_d[128]
    DIRECTION INPUT ;
    USE SIGNAL ;
    PORT
      LAYER M5 ;
        RECT  34.032 172.716 34.056 172.8 ;
    END
  END s_d[128]
  PIN s_d[129]
    DIRECTION INPUT ;
    USE SIGNAL ;
    PORT
      LAYER M5 ;
        RECT  34.128 172.716 34.152 172.8 ;
    END
  END s_d[129]
  PIN s_d[12]
    DIRECTION INPUT ;
    USE SIGNAL ;
    PORT
      LAYER M5 ;
        RECT  18.816 172.716 18.84 172.8 ;
    END
  END s_d[12]
  PIN s_d[130]
    DIRECTION INPUT ;
    USE SIGNAL ;
    PORT
      LAYER M5 ;
        RECT  34.224 172.716 34.248 172.8 ;
    END
  END s_d[130]
  PIN s_d[131]
    DIRECTION INPUT ;
    USE SIGNAL ;
    PORT
      LAYER M5 ;
        RECT  34.32 172.716 34.344 172.8 ;
    END
  END s_d[131]
  PIN s_d[132]
    DIRECTION INPUT ;
    USE SIGNAL ;
    PORT
      LAYER M5 ;
        RECT  34.416 172.716 34.44 172.8 ;
    END
  END s_d[132]
  PIN s_d[133]
    DIRECTION INPUT ;
    USE SIGNAL ;
    PORT
      LAYER M5 ;
        RECT  34.56 172.716 34.584 172.8 ;
    END
  END s_d[133]
  PIN s_d[134]
    DIRECTION INPUT ;
    USE SIGNAL ;
    PORT
      LAYER M5 ;
        RECT  34.656 172.716 34.68 172.8 ;
    END
  END s_d[134]
  PIN s_d[135]
    DIRECTION INPUT ;
    USE SIGNAL ;
    PORT
      LAYER M5 ;
        RECT  34.848 172.716 34.872 172.8 ;
    END
  END s_d[135]
  PIN s_d[136]
    DIRECTION INPUT ;
    USE SIGNAL ;
    PORT
      LAYER M5 ;
        RECT  34.944 172.716 34.968 172.8 ;
    END
  END s_d[136]
  PIN s_d[137]
    DIRECTION INPUT ;
    USE SIGNAL ;
    PORT
      LAYER M5 ;
        RECT  35.04 172.716 35.064 172.8 ;
    END
  END s_d[137]
  PIN s_d[138]
    DIRECTION INPUT ;
    USE SIGNAL ;
    PORT
      LAYER M5 ;
        RECT  35.232 172.716 35.256 172.8 ;
    END
  END s_d[138]
  PIN s_d[139]
    DIRECTION INPUT ;
    USE SIGNAL ;
    PORT
      LAYER M5 ;
        RECT  35.328 172.716 35.352 172.8 ;
    END
  END s_d[139]
  PIN s_d[13]
    DIRECTION INPUT ;
    USE SIGNAL ;
    PORT
      LAYER M5 ;
        RECT  19.008 172.716 19.032 172.8 ;
    END
  END s_d[13]
  PIN s_d[140]
    DIRECTION INPUT ;
    USE SIGNAL ;
    PORT
      LAYER M5 ;
        RECT  35.52 172.716 35.544 172.8 ;
    END
  END s_d[140]
  PIN s_d[141]
    DIRECTION INPUT ;
    USE SIGNAL ;
    PORT
      LAYER M5 ;
        RECT  35.616 172.716 35.64 172.8 ;
    END
  END s_d[141]
  PIN s_d[142]
    DIRECTION INPUT ;
    USE SIGNAL ;
    PORT
      LAYER M5 ;
        RECT  35.712 172.716 35.736 172.8 ;
    END
  END s_d[142]
  PIN s_d[143]
    DIRECTION INPUT ;
    USE SIGNAL ;
    PORT
      LAYER M5 ;
        RECT  35.904 172.716 35.928 172.8 ;
    END
  END s_d[143]
  PIN s_d[144]
    DIRECTION INPUT ;
    USE SIGNAL ;
    PORT
      LAYER M5 ;
        RECT  36 172.716 36.024 172.8 ;
    END
  END s_d[144]
  PIN s_d[145]
    DIRECTION INPUT ;
    USE SIGNAL ;
    PORT
      LAYER M5 ;
        RECT  36.096 172.716 36.12 172.8 ;
    END
  END s_d[145]
  PIN s_d[146]
    DIRECTION INPUT ;
    USE SIGNAL ;
    PORT
      LAYER M5 ;
        RECT  36.192 172.716 36.216 172.8 ;
    END
  END s_d[146]
  PIN s_d[147]
    DIRECTION INPUT ;
    USE SIGNAL ;
    PORT
      LAYER M5 ;
        RECT  36.384 172.716 36.408 172.8 ;
    END
  END s_d[147]
  PIN s_d[148]
    DIRECTION INPUT ;
    USE SIGNAL ;
    PORT
      LAYER M5 ;
        RECT  37.104 172.716 37.128 172.8 ;
    END
  END s_d[148]
  PIN s_d[149]
    DIRECTION INPUT ;
    USE SIGNAL ;
    PORT
      LAYER M5 ;
        RECT  37.2 172.716 37.224 172.8 ;
    END
  END s_d[149]
  PIN s_d[14]
    DIRECTION INPUT ;
    USE SIGNAL ;
    PORT
      LAYER M5 ;
        RECT  19.104 172.716 19.128 172.8 ;
    END
  END s_d[14]
  PIN s_d[150]
    DIRECTION INPUT ;
    USE SIGNAL ;
    PORT
      LAYER M5 ;
        RECT  37.296 172.716 37.32 172.8 ;
    END
  END s_d[150]
  PIN s_d[151]
    DIRECTION INPUT ;
    USE SIGNAL ;
    PORT
      LAYER M5 ;
        RECT  37.392 172.716 37.416 172.8 ;
    END
  END s_d[151]
  PIN s_d[152]
    DIRECTION INPUT ;
    USE SIGNAL ;
    PORT
      LAYER M5 ;
        RECT  37.488 172.716 37.512 172.8 ;
    END
  END s_d[152]
  PIN s_d[153]
    DIRECTION INPUT ;
    USE SIGNAL ;
    PORT
      LAYER M5 ;
        RECT  37.584 172.716 37.608 172.8 ;
    END
  END s_d[153]
  PIN s_d[154]
    DIRECTION INPUT ;
    USE SIGNAL ;
    PORT
      LAYER M5 ;
        RECT  37.68 172.716 37.704 172.8 ;
    END
  END s_d[154]
  PIN s_d[155]
    DIRECTION INPUT ;
    USE SIGNAL ;
    PORT
      LAYER M5 ;
        RECT  37.776 172.716 37.8 172.8 ;
    END
  END s_d[155]
  PIN s_d[156]
    DIRECTION INPUT ;
    USE SIGNAL ;
    PORT
      LAYER M5 ;
        RECT  37.872 172.716 37.896 172.8 ;
    END
  END s_d[156]
  PIN s_d[157]
    DIRECTION INPUT ;
    USE SIGNAL ;
    PORT
      LAYER M5 ;
        RECT  37.968 172.716 37.992 172.8 ;
    END
  END s_d[157]
  PIN s_d[15]
    DIRECTION INPUT ;
    USE SIGNAL ;
    PORT
      LAYER M5 ;
        RECT  19.824 172.716 19.848 172.8 ;
    END
  END s_d[15]
  PIN s_d[16]
    DIRECTION INPUT ;
    USE SIGNAL ;
    PORT
      LAYER M5 ;
        RECT  19.92 172.716 19.944 172.8 ;
    END
  END s_d[16]
  PIN s_d[17]
    DIRECTION INPUT ;
    USE SIGNAL ;
    PORT
      LAYER M5 ;
        RECT  20.016 172.716 20.04 172.8 ;
    END
  END s_d[17]
  PIN s_d[18]
    DIRECTION INPUT ;
    USE SIGNAL ;
    PORT
      LAYER M5 ;
        RECT  20.112 172.716 20.136 172.8 ;
    END
  END s_d[18]
  PIN s_d[19]
    DIRECTION INPUT ;
    USE SIGNAL ;
    PORT
      LAYER M5 ;
        RECT  20.208 172.716 20.232 172.8 ;
    END
  END s_d[19]
  PIN s_d[1]
    DIRECTION INPUT ;
    USE SIGNAL ;
    PORT
      LAYER M5 ;
        RECT  17.472 172.716 17.496 172.8 ;
    END
  END s_d[1]
  PIN s_d[20]
    DIRECTION INPUT ;
    USE SIGNAL ;
    PORT
      LAYER M5 ;
        RECT  20.304 172.716 20.328 172.8 ;
    END
  END s_d[20]
  PIN s_d[21]
    DIRECTION INPUT ;
    USE SIGNAL ;
    PORT
      LAYER M5 ;
        RECT  20.4 172.716 20.424 172.8 ;
    END
  END s_d[21]
  PIN s_d[22]
    DIRECTION INPUT ;
    USE SIGNAL ;
    PORT
      LAYER M5 ;
        RECT  20.496 172.716 20.52 172.8 ;
    END
  END s_d[22]
  PIN s_d[23]
    DIRECTION INPUT ;
    USE SIGNAL ;
    PORT
      LAYER M5 ;
        RECT  20.592 172.716 20.616 172.8 ;
    END
  END s_d[23]
  PIN s_d[24]
    DIRECTION INPUT ;
    USE SIGNAL ;
    PORT
      LAYER M5 ;
        RECT  20.688 172.716 20.712 172.8 ;
    END
  END s_d[24]
  PIN s_d[25]
    DIRECTION INPUT ;
    USE SIGNAL ;
    PORT
      LAYER M5 ;
        RECT  20.784 172.716 20.808 172.8 ;
    END
  END s_d[25]
  PIN s_d[26]
    DIRECTION INPUT ;
    USE SIGNAL ;
    PORT
      LAYER M5 ;
        RECT  20.88 172.716 20.904 172.8 ;
    END
  END s_d[26]
  PIN s_d[27]
    DIRECTION INPUT ;
    USE SIGNAL ;
    PORT
      LAYER M5 ;
        RECT  20.976 172.716 21 172.8 ;
    END
  END s_d[27]
  PIN s_d[28]
    DIRECTION INPUT ;
    USE SIGNAL ;
    PORT
      LAYER M5 ;
        RECT  21.072 172.716 21.096 172.8 ;
    END
  END s_d[28]
  PIN s_d[29]
    DIRECTION INPUT ;
    USE SIGNAL ;
    PORT
      LAYER M5 ;
        RECT  21.168 172.716 21.192 172.8 ;
    END
  END s_d[29]
  PIN s_d[2]
    DIRECTION INPUT ;
    USE SIGNAL ;
    PORT
      LAYER M5 ;
        RECT  17.568 172.716 17.592 172.8 ;
    END
  END s_d[2]
  PIN s_d[30]
    DIRECTION INPUT ;
    USE SIGNAL ;
    PORT
      LAYER M5 ;
        RECT  21.264 172.716 21.288 172.8 ;
    END
  END s_d[30]
  PIN s_d[31]
    DIRECTION INPUT ;
    USE SIGNAL ;
    PORT
      LAYER M5 ;
        RECT  21.36 172.716 21.384 172.8 ;
    END
  END s_d[31]
  PIN s_d[32]
    DIRECTION INPUT ;
    USE SIGNAL ;
    PORT
      LAYER M5 ;
        RECT  21.456 172.716 21.48 172.8 ;
    END
  END s_d[32]
  PIN s_d[33]
    DIRECTION INPUT ;
    USE SIGNAL ;
    PORT
      LAYER M5 ;
        RECT  21.6 172.716 21.624 172.8 ;
    END
  END s_d[33]
  PIN s_d[34]
    DIRECTION INPUT ;
    USE SIGNAL ;
    PORT
      LAYER M5 ;
        RECT  21.696 172.716 21.72 172.8 ;
    END
  END s_d[34]
  PIN s_d[35]
    DIRECTION INPUT ;
    USE SIGNAL ;
    PORT
      LAYER M5 ;
        RECT  21.888 172.716 21.912 172.8 ;
    END
  END s_d[35]
  PIN s_d[36]
    DIRECTION INPUT ;
    USE SIGNAL ;
    PORT
      LAYER M5 ;
        RECT  21.984 172.716 22.008 172.8 ;
    END
  END s_d[36]
  PIN s_d[37]
    DIRECTION INPUT ;
    USE SIGNAL ;
    PORT
      LAYER M5 ;
        RECT  22.08 172.716 22.104 172.8 ;
    END
  END s_d[37]
  PIN s_d[38]
    DIRECTION INPUT ;
    USE SIGNAL ;
    PORT
      LAYER M5 ;
        RECT  22.272 172.716 22.296 172.8 ;
    END
  END s_d[38]
  PIN s_d[39]
    DIRECTION INPUT ;
    USE SIGNAL ;
    PORT
      LAYER M5 ;
        RECT  22.368 172.716 22.392 172.8 ;
    END
  END s_d[39]
  PIN s_d[3]
    DIRECTION INPUT ;
    USE SIGNAL ;
    PORT
      LAYER M5 ;
        RECT  17.76 172.716 17.784 172.8 ;
    END
  END s_d[3]
  PIN s_d[40]
    DIRECTION INPUT ;
    USE SIGNAL ;
    PORT
      LAYER M5 ;
        RECT  22.56 172.716 22.584 172.8 ;
    END
  END s_d[40]
  PIN s_d[41]
    DIRECTION INPUT ;
    USE SIGNAL ;
    PORT
      LAYER M5 ;
        RECT  22.656 172.716 22.68 172.8 ;
    END
  END s_d[41]
  PIN s_d[42]
    DIRECTION INPUT ;
    USE SIGNAL ;
    PORT
      LAYER M5 ;
        RECT  22.752 172.716 22.776 172.8 ;
    END
  END s_d[42]
  PIN s_d[43]
    DIRECTION INPUT ;
    USE SIGNAL ;
    PORT
      LAYER M5 ;
        RECT  22.944 172.716 22.968 172.8 ;
    END
  END s_d[43]
  PIN s_d[44]
    DIRECTION INPUT ;
    USE SIGNAL ;
    PORT
      LAYER M5 ;
        RECT  23.04 172.716 23.064 172.8 ;
    END
  END s_d[44]
  PIN s_d[45]
    DIRECTION INPUT ;
    USE SIGNAL ;
    PORT
      LAYER M5 ;
        RECT  23.136 172.716 23.16 172.8 ;
    END
  END s_d[45]
  PIN s_d[46]
    DIRECTION INPUT ;
    USE SIGNAL ;
    PORT
      LAYER M5 ;
        RECT  23.328 172.716 23.352 172.8 ;
    END
  END s_d[46]
  PIN s_d[47]
    DIRECTION INPUT ;
    USE SIGNAL ;
    PORT
      LAYER M5 ;
        RECT  23.424 172.716 23.448 172.8 ;
    END
  END s_d[47]
  PIN s_d[48]
    DIRECTION INPUT ;
    USE SIGNAL ;
    PORT
      LAYER M5 ;
        RECT  24.144 172.716 24.168 172.8 ;
    END
  END s_d[48]
  PIN s_d[49]
    DIRECTION INPUT ;
    USE SIGNAL ;
    PORT
      LAYER M5 ;
        RECT  24.24 172.716 24.264 172.8 ;
    END
  END s_d[49]
  PIN s_d[4]
    DIRECTION INPUT ;
    USE SIGNAL ;
    PORT
      LAYER M5 ;
        RECT  17.856 172.716 17.88 172.8 ;
    END
  END s_d[4]
  PIN s_d[50]
    DIRECTION INPUT ;
    USE SIGNAL ;
    PORT
      LAYER M5 ;
        RECT  24.336 172.716 24.36 172.8 ;
    END
  END s_d[50]
  PIN s_d[51]
    DIRECTION INPUT ;
    USE SIGNAL ;
    PORT
      LAYER M5 ;
        RECT  24.432 172.716 24.456 172.8 ;
    END
  END s_d[51]
  PIN s_d[52]
    DIRECTION INPUT ;
    USE SIGNAL ;
    PORT
      LAYER M5 ;
        RECT  24.528 172.716 24.552 172.8 ;
    END
  END s_d[52]
  PIN s_d[53]
    DIRECTION INPUT ;
    USE SIGNAL ;
    PORT
      LAYER M5 ;
        RECT  24.624 172.716 24.648 172.8 ;
    END
  END s_d[53]
  PIN s_d[54]
    DIRECTION INPUT ;
    USE SIGNAL ;
    PORT
      LAYER M5 ;
        RECT  24.72 172.716 24.744 172.8 ;
    END
  END s_d[54]
  PIN s_d[55]
    DIRECTION INPUT ;
    USE SIGNAL ;
    PORT
      LAYER M5 ;
        RECT  24.816 172.716 24.84 172.8 ;
    END
  END s_d[55]
  PIN s_d[56]
    DIRECTION INPUT ;
    USE SIGNAL ;
    PORT
      LAYER M5 ;
        RECT  24.912 172.716 24.936 172.8 ;
    END
  END s_d[56]
  PIN s_d[57]
    DIRECTION INPUT ;
    USE SIGNAL ;
    PORT
      LAYER M5 ;
        RECT  25.008 172.716 25.032 172.8 ;
    END
  END s_d[57]
  PIN s_d[58]
    DIRECTION INPUT ;
    USE SIGNAL ;
    PORT
      LAYER M5 ;
        RECT  25.104 172.716 25.128 172.8 ;
    END
  END s_d[58]
  PIN s_d[59]
    DIRECTION INPUT ;
    USE SIGNAL ;
    PORT
      LAYER M5 ;
        RECT  25.2 172.716 25.224 172.8 ;
    END
  END s_d[59]
  PIN s_d[5]
    DIRECTION INPUT ;
    USE SIGNAL ;
    PORT
      LAYER M5 ;
        RECT  17.952 172.716 17.976 172.8 ;
    END
  END s_d[5]
  PIN s_d[60]
    DIRECTION INPUT ;
    USE SIGNAL ;
    PORT
      LAYER M5 ;
        RECT  25.296 172.716 25.32 172.8 ;
    END
  END s_d[60]
  PIN s_d[61]
    DIRECTION INPUT ;
    USE SIGNAL ;
    PORT
      LAYER M5 ;
        RECT  25.392 172.716 25.416 172.8 ;
    END
  END s_d[61]
  PIN s_d[62]
    DIRECTION INPUT ;
    USE SIGNAL ;
    PORT
      LAYER M5 ;
        RECT  25.488 172.716 25.512 172.8 ;
    END
  END s_d[62]
  PIN s_d[63]
    DIRECTION INPUT ;
    USE SIGNAL ;
    PORT
      LAYER M5 ;
        RECT  25.584 172.716 25.608 172.8 ;
    END
  END s_d[63]
  PIN s_d[64]
    DIRECTION INPUT ;
    USE SIGNAL ;
    PORT
      LAYER M5 ;
        RECT  25.68 172.716 25.704 172.8 ;
    END
  END s_d[64]
  PIN s_d[65]
    DIRECTION INPUT ;
    USE SIGNAL ;
    PORT
      LAYER M5 ;
        RECT  25.776 172.716 25.8 172.8 ;
    END
  END s_d[65]
  PIN s_d[66]
    DIRECTION INPUT ;
    USE SIGNAL ;
    PORT
      LAYER M5 ;
        RECT  25.872 172.716 25.896 172.8 ;
    END
  END s_d[66]
  PIN s_d[67]
    DIRECTION INPUT ;
    USE SIGNAL ;
    PORT
      LAYER M5 ;
        RECT  26.016 172.716 26.04 172.8 ;
    END
  END s_d[67]
  PIN s_d[68]
    DIRECTION INPUT ;
    USE SIGNAL ;
    PORT
      LAYER M5 ;
        RECT  26.112 172.716 26.136 172.8 ;
    END
  END s_d[68]
  PIN s_d[69]
    DIRECTION INPUT ;
    USE SIGNAL ;
    PORT
      LAYER M5 ;
        RECT  26.304 172.716 26.328 172.8 ;
    END
  END s_d[69]
  PIN s_d[6]
    DIRECTION INPUT ;
    USE SIGNAL ;
    PORT
      LAYER M5 ;
        RECT  18.144 172.716 18.168 172.8 ;
    END
  END s_d[6]
  PIN s_d[70]
    DIRECTION INPUT ;
    USE SIGNAL ;
    PORT
      LAYER M5 ;
        RECT  26.4 172.716 26.424 172.8 ;
    END
  END s_d[70]
  PIN s_d[71]
    DIRECTION INPUT ;
    USE SIGNAL ;
    PORT
      LAYER M5 ;
        RECT  26.496 172.716 26.52 172.8 ;
    END
  END s_d[71]
  PIN s_d[72]
    DIRECTION INPUT ;
    USE SIGNAL ;
    PORT
      LAYER M5 ;
        RECT  26.592 172.716 26.616 172.8 ;
    END
  END s_d[72]
  PIN s_d[73]
    DIRECTION INPUT ;
    USE SIGNAL ;
    PORT
      LAYER M5 ;
        RECT  26.784 172.716 26.808 172.8 ;
    END
  END s_d[73]
  PIN s_d[74]
    DIRECTION INPUT ;
    USE SIGNAL ;
    PORT
      LAYER M5 ;
        RECT  26.88 172.716 26.904 172.8 ;
    END
  END s_d[74]
  PIN s_d[75]
    DIRECTION INPUT ;
    USE SIGNAL ;
    PORT
      LAYER M5 ;
        RECT  27.072 172.716 27.096 172.8 ;
    END
  END s_d[75]
  PIN s_d[76]
    DIRECTION INPUT ;
    USE SIGNAL ;
    PORT
      LAYER M5 ;
        RECT  27.168 172.716 27.192 172.8 ;
    END
  END s_d[76]
  PIN s_d[77]
    DIRECTION INPUT ;
    USE SIGNAL ;
    PORT
      LAYER M5 ;
        RECT  27.264 172.716 27.288 172.8 ;
    END
  END s_d[77]
  PIN s_d[78]
    DIRECTION INPUT ;
    USE SIGNAL ;
    PORT
      LAYER M5 ;
        RECT  27.456 172.716 27.48 172.8 ;
    END
  END s_d[78]
  PIN s_d[79]
    DIRECTION INPUT ;
    USE SIGNAL ;
    PORT
      LAYER M5 ;
        RECT  27.552 172.716 27.576 172.8 ;
    END
  END s_d[79]
  PIN s_d[7]
    DIRECTION INPUT ;
    USE SIGNAL ;
    PORT
      LAYER M5 ;
        RECT  18.24 172.716 18.264 172.8 ;
    END
  END s_d[7]
  PIN s_d[80]
    DIRECTION INPUT ;
    USE SIGNAL ;
    PORT
      LAYER M5 ;
        RECT  27.744 172.716 27.768 172.8 ;
    END
  END s_d[80]
  PIN s_d[81]
    DIRECTION INPUT ;
    USE SIGNAL ;
    PORT
      LAYER M5 ;
        RECT  28.464 172.716 28.488 172.8 ;
    END
  END s_d[81]
  PIN s_d[82]
    DIRECTION INPUT ;
    USE SIGNAL ;
    PORT
      LAYER M5 ;
        RECT  28.56 172.716 28.584 172.8 ;
    END
  END s_d[82]
  PIN s_d[83]
    DIRECTION INPUT ;
    USE SIGNAL ;
    PORT
      LAYER M5 ;
        RECT  28.656 172.716 28.68 172.8 ;
    END
  END s_d[83]
  PIN s_d[84]
    DIRECTION INPUT ;
    USE SIGNAL ;
    PORT
      LAYER M5 ;
        RECT  28.752 172.716 28.776 172.8 ;
    END
  END s_d[84]
  PIN s_d[85]
    DIRECTION INPUT ;
    USE SIGNAL ;
    PORT
      LAYER M5 ;
        RECT  28.848 172.716 28.872 172.8 ;
    END
  END s_d[85]
  PIN s_d[86]
    DIRECTION INPUT ;
    USE SIGNAL ;
    PORT
      LAYER M5 ;
        RECT  28.944 172.716 28.968 172.8 ;
    END
  END s_d[86]
  PIN s_d[87]
    DIRECTION INPUT ;
    USE SIGNAL ;
    PORT
      LAYER M5 ;
        RECT  29.04 172.716 29.064 172.8 ;
    END
  END s_d[87]
  PIN s_d[88]
    DIRECTION INPUT ;
    USE SIGNAL ;
    PORT
      LAYER M5 ;
        RECT  29.136 172.716 29.16 172.8 ;
    END
  END s_d[88]
  PIN s_d[89]
    DIRECTION INPUT ;
    USE SIGNAL ;
    PORT
      LAYER M5 ;
        RECT  29.232 172.716 29.256 172.8 ;
    END
  END s_d[89]
  PIN s_d[8]
    DIRECTION INPUT ;
    USE SIGNAL ;
    PORT
      LAYER M5 ;
        RECT  18.336 172.716 18.36 172.8 ;
    END
  END s_d[8]
  PIN s_d[90]
    DIRECTION INPUT ;
    USE SIGNAL ;
    PORT
      LAYER M5 ;
        RECT  29.328 172.716 29.352 172.8 ;
    END
  END s_d[90]
  PIN s_d[91]
    DIRECTION INPUT ;
    USE SIGNAL ;
    PORT
      LAYER M5 ;
        RECT  29.424 172.716 29.448 172.8 ;
    END
  END s_d[91]
  PIN s_d[92]
    DIRECTION INPUT ;
    USE SIGNAL ;
    PORT
      LAYER M5 ;
        RECT  29.52 172.716 29.544 172.8 ;
    END
  END s_d[92]
  PIN s_d[93]
    DIRECTION INPUT ;
    USE SIGNAL ;
    PORT
      LAYER M5 ;
        RECT  29.616 172.716 29.64 172.8 ;
    END
  END s_d[93]
  PIN s_d[94]
    DIRECTION INPUT ;
    USE SIGNAL ;
    PORT
      LAYER M5 ;
        RECT  29.712 172.716 29.736 172.8 ;
    END
  END s_d[94]
  PIN s_d[95]
    DIRECTION INPUT ;
    USE SIGNAL ;
    PORT
      LAYER M5 ;
        RECT  29.808 172.716 29.832 172.8 ;
    END
  END s_d[95]
  PIN s_d[96]
    DIRECTION INPUT ;
    USE SIGNAL ;
    PORT
      LAYER M5 ;
        RECT  29.904 172.716 29.928 172.8 ;
    END
  END s_d[96]
  PIN s_d[97]
    DIRECTION INPUT ;
    USE SIGNAL ;
    PORT
      LAYER M5 ;
        RECT  30 172.716 30.024 172.8 ;
    END
  END s_d[97]
  PIN s_d[98]
    DIRECTION INPUT ;
    USE SIGNAL ;
    PORT
      LAYER M5 ;
        RECT  30.096 172.716 30.12 172.8 ;
    END
  END s_d[98]
  PIN s_d[99]
    DIRECTION INPUT ;
    USE SIGNAL ;
    PORT
      LAYER M5 ;
        RECT  30.192 172.716 30.216 172.8 ;
    END
  END s_d[99]
  PIN s_d[9]
    DIRECTION INPUT ;
    USE SIGNAL ;
    PORT
      LAYER M5 ;
        RECT  18.528 172.716 18.552 172.8 ;
    END
  END s_d[9]
  PIN s_v
    DIRECTION INPUT ;
    USE SIGNAL ;
    PORT
      LAYER M5 ;
        RECT  17.232 172.716 17.256 172.8 ;
    END
  END s_v
  PIN sw_d[0]
    DIRECTION OUTPUT ;
    USE SIGNAL ;
    PORT
      LAYER M4 ;
        RECT  172.716 4.992 172.8 5.016 ;
    END
  END sw_d[0]
  PIN sw_d[100]
    DIRECTION OUTPUT ;
    USE SIGNAL ;
    PORT
      LAYER M4 ;
        RECT  172.716 47.328 172.8 47.352 ;
    END
  END sw_d[100]
  PIN sw_d[101]
    DIRECTION OUTPUT ;
    USE SIGNAL ;
    PORT
      LAYER M4 ;
        RECT  172.716 47.808 172.8 47.832 ;
    END
  END sw_d[101]
  PIN sw_d[102]
    DIRECTION OUTPUT ;
    USE SIGNAL ;
    PORT
      LAYER M4 ;
        RECT  172.716 48.192 172.8 48.216 ;
    END
  END sw_d[102]
  PIN sw_d[103]
    DIRECTION OUTPUT ;
    USE SIGNAL ;
    PORT
      LAYER M4 ;
        RECT  172.716 48.672 172.8 48.696 ;
    END
  END sw_d[103]
  PIN sw_d[104]
    DIRECTION OUTPUT ;
    USE SIGNAL ;
    PORT
      LAYER M4 ;
        RECT  172.716 49.056 172.8 49.08 ;
    END
  END sw_d[104]
  PIN sw_d[105]
    DIRECTION OUTPUT ;
    USE SIGNAL ;
    PORT
      LAYER M4 ;
        RECT  172.716 49.44 172.8 49.464 ;
    END
  END sw_d[105]
  PIN sw_d[106]
    DIRECTION OUTPUT ;
    USE SIGNAL ;
    PORT
      LAYER M4 ;
        RECT  172.716 49.92 172.8 49.944 ;
    END
  END sw_d[106]
  PIN sw_d[107]
    DIRECTION OUTPUT ;
    USE SIGNAL ;
    PORT
      LAYER M4 ;
        RECT  172.716 50.304 172.8 50.328 ;
    END
  END sw_d[107]
  PIN sw_d[108]
    DIRECTION OUTPUT ;
    USE SIGNAL ;
    PORT
      LAYER M4 ;
        RECT  172.716 50.784 172.8 50.808 ;
    END
  END sw_d[108]
  PIN sw_d[109]
    DIRECTION OUTPUT ;
    USE SIGNAL ;
    PORT
      LAYER M4 ;
        RECT  172.716 51.168 172.8 51.192 ;
    END
  END sw_d[109]
  PIN sw_d[10]
    DIRECTION OUTPUT ;
    USE SIGNAL ;
    PORT
      LAYER M4 ;
        RECT  172.716 9.216 172.8 9.24 ;
    END
  END sw_d[10]
  PIN sw_d[110]
    DIRECTION OUTPUT ;
    USE SIGNAL ;
    PORT
      LAYER M4 ;
        RECT  172.716 51.648 172.8 51.672 ;
    END
  END sw_d[110]
  PIN sw_d[111]
    DIRECTION OUTPUT ;
    USE SIGNAL ;
    PORT
      LAYER M4 ;
        RECT  172.716 52.032 172.8 52.056 ;
    END
  END sw_d[111]
  PIN sw_d[112]
    DIRECTION OUTPUT ;
    USE SIGNAL ;
    PORT
      LAYER M4 ;
        RECT  172.716 52.416 172.8 52.44 ;
    END
  END sw_d[112]
  PIN sw_d[113]
    DIRECTION OUTPUT ;
    USE SIGNAL ;
    PORT
      LAYER M4 ;
        RECT  172.716 52.896 172.8 52.92 ;
    END
  END sw_d[113]
  PIN sw_d[114]
    DIRECTION OUTPUT ;
    USE SIGNAL ;
    PORT
      LAYER M4 ;
        RECT  172.716 53.28 172.8 53.304 ;
    END
  END sw_d[114]
  PIN sw_d[115]
    DIRECTION OUTPUT ;
    USE SIGNAL ;
    PORT
      LAYER M4 ;
        RECT  172.716 53.76 172.8 53.784 ;
    END
  END sw_d[115]
  PIN sw_d[116]
    DIRECTION OUTPUT ;
    USE SIGNAL ;
    PORT
      LAYER M4 ;
        RECT  172.716 54.144 172.8 54.168 ;
    END
  END sw_d[116]
  PIN sw_d[117]
    DIRECTION OUTPUT ;
    USE SIGNAL ;
    PORT
      LAYER M4 ;
        RECT  172.716 54.528 172.8 54.552 ;
    END
  END sw_d[117]
  PIN sw_d[118]
    DIRECTION OUTPUT ;
    USE SIGNAL ;
    PORT
      LAYER M4 ;
        RECT  172.716 55.008 172.8 55.032 ;
    END
  END sw_d[118]
  PIN sw_d[119]
    DIRECTION OUTPUT ;
    USE SIGNAL ;
    PORT
      LAYER M4 ;
        RECT  172.716 55.392 172.8 55.416 ;
    END
  END sw_d[119]
  PIN sw_d[11]
    DIRECTION OUTPUT ;
    USE SIGNAL ;
    PORT
      LAYER M4 ;
        RECT  172.716 9.6 172.8 9.624 ;
    END
  END sw_d[11]
  PIN sw_d[120]
    DIRECTION OUTPUT ;
    USE SIGNAL ;
    PORT
      LAYER M4 ;
        RECT  172.716 55.872 172.8 55.896 ;
    END
  END sw_d[120]
  PIN sw_d[121]
    DIRECTION OUTPUT ;
    USE SIGNAL ;
    PORT
      LAYER M4 ;
        RECT  172.716 56.256 172.8 56.28 ;
    END
  END sw_d[121]
  PIN sw_d[122]
    DIRECTION OUTPUT ;
    USE SIGNAL ;
    PORT
      LAYER M4 ;
        RECT  172.716 56.736 172.8 56.76 ;
    END
  END sw_d[122]
  PIN sw_d[123]
    DIRECTION OUTPUT ;
    USE SIGNAL ;
    PORT
      LAYER M4 ;
        RECT  172.716 57.12 172.8 57.144 ;
    END
  END sw_d[123]
  PIN sw_d[124]
    DIRECTION OUTPUT ;
    USE SIGNAL ;
    PORT
      LAYER M4 ;
        RECT  172.716 57.504 172.8 57.528 ;
    END
  END sw_d[124]
  PIN sw_d[125]
    DIRECTION OUTPUT ;
    USE SIGNAL ;
    PORT
      LAYER M4 ;
        RECT  172.716 57.984 172.8 58.008 ;
    END
  END sw_d[125]
  PIN sw_d[126]
    DIRECTION OUTPUT ;
    USE SIGNAL ;
    PORT
      LAYER M4 ;
        RECT  172.716 58.368 172.8 58.392 ;
    END
  END sw_d[126]
  PIN sw_d[127]
    DIRECTION OUTPUT ;
    USE SIGNAL ;
    PORT
      LAYER M4 ;
        RECT  172.716 58.848 172.8 58.872 ;
    END
  END sw_d[127]
  PIN sw_d[128]
    DIRECTION OUTPUT ;
    USE SIGNAL ;
    PORT
      LAYER M4 ;
        RECT  172.716 59.232 172.8 59.256 ;
    END
  END sw_d[128]
  PIN sw_d[129]
    DIRECTION OUTPUT ;
    USE SIGNAL ;
    PORT
      LAYER M4 ;
        RECT  172.716 59.712 172.8 59.736 ;
    END
  END sw_d[129]
  PIN sw_d[12]
    DIRECTION OUTPUT ;
    USE SIGNAL ;
    PORT
      LAYER M4 ;
        RECT  172.716 10.08 172.8 10.104 ;
    END
  END sw_d[12]
  PIN sw_d[130]
    DIRECTION OUTPUT ;
    USE SIGNAL ;
    PORT
      LAYER M4 ;
        RECT  172.716 60.096 172.8 60.12 ;
    END
  END sw_d[130]
  PIN sw_d[131]
    DIRECTION OUTPUT ;
    USE SIGNAL ;
    PORT
      LAYER M4 ;
        RECT  172.716 60.48 172.8 60.504 ;
    END
  END sw_d[131]
  PIN sw_d[132]
    DIRECTION OUTPUT ;
    USE SIGNAL ;
    PORT
      LAYER M4 ;
        RECT  172.716 60.96 172.8 60.984 ;
    END
  END sw_d[132]
  PIN sw_d[133]
    DIRECTION OUTPUT ;
    USE SIGNAL ;
    PORT
      LAYER M4 ;
        RECT  172.716 61.344 172.8 61.368 ;
    END
  END sw_d[133]
  PIN sw_d[134]
    DIRECTION OUTPUT ;
    USE SIGNAL ;
    PORT
      LAYER M4 ;
        RECT  172.716 61.824 172.8 61.848 ;
    END
  END sw_d[134]
  PIN sw_d[135]
    DIRECTION OUTPUT ;
    USE SIGNAL ;
    PORT
      LAYER M4 ;
        RECT  172.716 62.208 172.8 62.232 ;
    END
  END sw_d[135]
  PIN sw_d[136]
    DIRECTION OUTPUT ;
    USE SIGNAL ;
    PORT
      LAYER M4 ;
        RECT  172.716 62.592 172.8 62.616 ;
    END
  END sw_d[136]
  PIN sw_d[137]
    DIRECTION OUTPUT ;
    USE SIGNAL ;
    PORT
      LAYER M4 ;
        RECT  172.716 63.072 172.8 63.096 ;
    END
  END sw_d[137]
  PIN sw_d[138]
    DIRECTION OUTPUT ;
    USE SIGNAL ;
    PORT
      LAYER M4 ;
        RECT  172.716 63.456 172.8 63.48 ;
    END
  END sw_d[138]
  PIN sw_d[139]
    DIRECTION OUTPUT ;
    USE SIGNAL ;
    PORT
      LAYER M4 ;
        RECT  172.716 63.936 172.8 63.96 ;
    END
  END sw_d[139]
  PIN sw_d[13]
    DIRECTION OUTPUT ;
    USE SIGNAL ;
    PORT
      LAYER M4 ;
        RECT  172.716 10.464 172.8 10.488 ;
    END
  END sw_d[13]
  PIN sw_d[140]
    DIRECTION OUTPUT ;
    USE SIGNAL ;
    PORT
      LAYER M4 ;
        RECT  172.716 64.32 172.8 64.344 ;
    END
  END sw_d[140]
  PIN sw_d[141]
    DIRECTION OUTPUT ;
    USE SIGNAL ;
    PORT
      LAYER M4 ;
        RECT  172.716 64.8 172.8 64.824 ;
    END
  END sw_d[141]
  PIN sw_d[142]
    DIRECTION OUTPUT ;
    USE SIGNAL ;
    PORT
      LAYER M4 ;
        RECT  172.716 65.184 172.8 65.208 ;
    END
  END sw_d[142]
  PIN sw_d[143]
    DIRECTION OUTPUT ;
    USE SIGNAL ;
    PORT
      LAYER M4 ;
        RECT  172.716 65.568 172.8 65.592 ;
    END
  END sw_d[143]
  PIN sw_d[144]
    DIRECTION OUTPUT ;
    USE SIGNAL ;
    PORT
      LAYER M4 ;
        RECT  172.716 66.048 172.8 66.072 ;
    END
  END sw_d[144]
  PIN sw_d[145]
    DIRECTION OUTPUT ;
    USE SIGNAL ;
    PORT
      LAYER M4 ;
        RECT  172.716 66.432 172.8 66.456 ;
    END
  END sw_d[145]
  PIN sw_d[146]
    DIRECTION OUTPUT ;
    USE SIGNAL ;
    PORT
      LAYER M4 ;
        RECT  172.716 66.912 172.8 66.936 ;
    END
  END sw_d[146]
  PIN sw_d[147]
    DIRECTION OUTPUT ;
    USE SIGNAL ;
    PORT
      LAYER M4 ;
        RECT  172.716 67.296 172.8 67.32 ;
    END
  END sw_d[147]
  PIN sw_d[148]
    DIRECTION OUTPUT ;
    USE SIGNAL ;
    PORT
      LAYER M4 ;
        RECT  172.716 67.68 172.8 67.704 ;
    END
  END sw_d[148]
  PIN sw_d[149]
    DIRECTION OUTPUT ;
    USE SIGNAL ;
    PORT
      LAYER M4 ;
        RECT  172.716 68.16 172.8 68.184 ;
    END
  END sw_d[149]
  PIN sw_d[14]
    DIRECTION OUTPUT ;
    USE SIGNAL ;
    PORT
      LAYER M4 ;
        RECT  172.716 10.848 172.8 10.872 ;
    END
  END sw_d[14]
  PIN sw_d[150]
    DIRECTION OUTPUT ;
    USE SIGNAL ;
    PORT
      LAYER M4 ;
        RECT  172.716 68.544 172.8 68.568 ;
    END
  END sw_d[150]
  PIN sw_d[151]
    DIRECTION OUTPUT ;
    USE SIGNAL ;
    PORT
      LAYER M4 ;
        RECT  172.716 69.024 172.8 69.048 ;
    END
  END sw_d[151]
  PIN sw_d[152]
    DIRECTION OUTPUT ;
    USE SIGNAL ;
    PORT
      LAYER M4 ;
        RECT  172.716 69.408 172.8 69.432 ;
    END
  END sw_d[152]
  PIN sw_d[153]
    DIRECTION OUTPUT ;
    USE SIGNAL ;
    PORT
      LAYER M4 ;
        RECT  172.716 69.888 172.8 69.912 ;
    END
  END sw_d[153]
  PIN sw_d[154]
    DIRECTION OUTPUT ;
    USE SIGNAL ;
    PORT
      LAYER M4 ;
        RECT  172.716 70.272 172.8 70.296 ;
    END
  END sw_d[154]
  PIN sw_d[155]
    DIRECTION OUTPUT ;
    USE SIGNAL ;
    PORT
      LAYER M4 ;
        RECT  172.716 70.656 172.8 70.68 ;
    END
  END sw_d[155]
  PIN sw_d[156]
    DIRECTION OUTPUT ;
    USE SIGNAL ;
    PORT
      LAYER M4 ;
        RECT  172.716 71.136 172.8 71.16 ;
    END
  END sw_d[156]
  PIN sw_d[157]
    DIRECTION OUTPUT ;
    USE SIGNAL ;
    PORT
      LAYER M4 ;
        RECT  172.716 71.52 172.8 71.544 ;
    END
  END sw_d[157]
  PIN sw_d[158]
    DIRECTION OUTPUT ;
    USE SIGNAL ;
    PORT
      LAYER M4 ;
        RECT  172.716 72 172.8 72.024 ;
    END
  END sw_d[158]
  PIN sw_d[159]
    DIRECTION OUTPUT ;
    USE SIGNAL ;
    PORT
      LAYER M4 ;
        RECT  172.716 72.384 172.8 72.408 ;
    END
  END sw_d[159]
  PIN sw_d[15]
    DIRECTION OUTPUT ;
    USE SIGNAL ;
    PORT
      LAYER M4 ;
        RECT  172.716 11.328 172.8 11.352 ;
    END
  END sw_d[15]
  PIN sw_d[160]
    DIRECTION OUTPUT ;
    USE SIGNAL ;
    PORT
      LAYER M4 ;
        RECT  172.716 72.768 172.8 72.792 ;
    END
  END sw_d[160]
  PIN sw_d[161]
    DIRECTION OUTPUT ;
    USE SIGNAL ;
    PORT
      LAYER M4 ;
        RECT  172.716 73.248 172.8 73.272 ;
    END
  END sw_d[161]
  PIN sw_d[162]
    DIRECTION OUTPUT ;
    USE SIGNAL ;
    PORT
      LAYER M4 ;
        RECT  172.716 73.632 172.8 73.656 ;
    END
  END sw_d[162]
  PIN sw_d[163]
    DIRECTION OUTPUT ;
    USE SIGNAL ;
    PORT
      LAYER M4 ;
        RECT  172.716 74.112 172.8 74.136 ;
    END
  END sw_d[163]
  PIN sw_d[164]
    DIRECTION OUTPUT ;
    USE SIGNAL ;
    PORT
      LAYER M4 ;
        RECT  172.716 74.496 172.8 74.52 ;
    END
  END sw_d[164]
  PIN sw_d[165]
    DIRECTION OUTPUT ;
    USE SIGNAL ;
    PORT
      LAYER M4 ;
        RECT  172.716 74.976 172.8 75 ;
    END
  END sw_d[165]
  PIN sw_d[166]
    DIRECTION OUTPUT ;
    USE SIGNAL ;
    PORT
      LAYER M4 ;
        RECT  172.716 75.36 172.8 75.384 ;
    END
  END sw_d[166]
  PIN sw_d[167]
    DIRECTION OUTPUT ;
    USE SIGNAL ;
    PORT
      LAYER M4 ;
        RECT  172.716 75.744 172.8 75.768 ;
    END
  END sw_d[167]
  PIN sw_d[168]
    DIRECTION OUTPUT ;
    USE SIGNAL ;
    PORT
      LAYER M4 ;
        RECT  172.716 76.224 172.8 76.248 ;
    END
  END sw_d[168]
  PIN sw_d[169]
    DIRECTION OUTPUT ;
    USE SIGNAL ;
    PORT
      LAYER M4 ;
        RECT  172.716 76.608 172.8 76.632 ;
    END
  END sw_d[169]
  PIN sw_d[16]
    DIRECTION OUTPUT ;
    USE SIGNAL ;
    PORT
      LAYER M4 ;
        RECT  172.716 11.712 172.8 11.736 ;
    END
  END sw_d[16]
  PIN sw_d[170]
    DIRECTION OUTPUT ;
    USE SIGNAL ;
    PORT
      LAYER M4 ;
        RECT  172.716 77.088 172.8 77.112 ;
    END
  END sw_d[170]
  PIN sw_d[171]
    DIRECTION OUTPUT ;
    USE SIGNAL ;
    PORT
      LAYER M4 ;
        RECT  172.716 77.472 172.8 77.496 ;
    END
  END sw_d[171]
  PIN sw_d[172]
    DIRECTION OUTPUT ;
    USE SIGNAL ;
    PORT
      LAYER M4 ;
        RECT  172.716 77.952 172.8 77.976 ;
    END
  END sw_d[172]
  PIN sw_d[173]
    DIRECTION OUTPUT ;
    USE SIGNAL ;
    PORT
      LAYER M4 ;
        RECT  172.716 78.336 172.8 78.36 ;
    END
  END sw_d[173]
  PIN sw_d[174]
    DIRECTION OUTPUT ;
    USE SIGNAL ;
    PORT
      LAYER M4 ;
        RECT  172.716 78.72 172.8 78.744 ;
    END
  END sw_d[174]
  PIN sw_d[175]
    DIRECTION OUTPUT ;
    USE SIGNAL ;
    PORT
      LAYER M4 ;
        RECT  172.716 79.2 172.8 79.224 ;
    END
  END sw_d[175]
  PIN sw_d[176]
    DIRECTION OUTPUT ;
    USE SIGNAL ;
    PORT
      LAYER M4 ;
        RECT  172.716 79.584 172.8 79.608 ;
    END
  END sw_d[176]
  PIN sw_d[177]
    DIRECTION OUTPUT ;
    USE SIGNAL ;
    PORT
      LAYER M4 ;
        RECT  172.716 80.064 172.8 80.088 ;
    END
  END sw_d[177]
  PIN sw_d[178]
    DIRECTION OUTPUT ;
    USE SIGNAL ;
    PORT
      LAYER M4 ;
        RECT  172.716 80.448 172.8 80.472 ;
    END
  END sw_d[178]
  PIN sw_d[179]
    DIRECTION OUTPUT ;
    USE SIGNAL ;
    PORT
      LAYER M4 ;
        RECT  172.716 80.832 172.8 80.856 ;
    END
  END sw_d[179]
  PIN sw_d[17]
    DIRECTION OUTPUT ;
    USE SIGNAL ;
    PORT
      LAYER M4 ;
        RECT  172.716 12.192 172.8 12.216 ;
    END
  END sw_d[17]
  PIN sw_d[180]
    DIRECTION OUTPUT ;
    USE SIGNAL ;
    PORT
      LAYER M4 ;
        RECT  172.716 81.312 172.8 81.336 ;
    END
  END sw_d[180]
  PIN sw_d[181]
    DIRECTION OUTPUT ;
    USE SIGNAL ;
    PORT
      LAYER M4 ;
        RECT  172.716 81.696 172.8 81.72 ;
    END
  END sw_d[181]
  PIN sw_d[182]
    DIRECTION OUTPUT ;
    USE SIGNAL ;
    PORT
      LAYER M4 ;
        RECT  172.716 82.176 172.8 82.2 ;
    END
  END sw_d[182]
  PIN sw_d[183]
    DIRECTION OUTPUT ;
    USE SIGNAL ;
    PORT
      LAYER M4 ;
        RECT  172.716 82.56 172.8 82.584 ;
    END
  END sw_d[183]
  PIN sw_d[184]
    DIRECTION OUTPUT ;
    USE SIGNAL ;
    PORT
      LAYER M4 ;
        RECT  172.716 83.04 172.8 83.064 ;
    END
  END sw_d[184]
  PIN sw_d[185]
    DIRECTION OUTPUT ;
    USE SIGNAL ;
    PORT
      LAYER M4 ;
        RECT  172.716 83.424 172.8 83.448 ;
    END
  END sw_d[185]
  PIN sw_d[186]
    DIRECTION OUTPUT ;
    USE SIGNAL ;
    PORT
      LAYER M4 ;
        RECT  172.716 83.808 172.8 83.832 ;
    END
  END sw_d[186]
  PIN sw_d[187]
    DIRECTION OUTPUT ;
    USE SIGNAL ;
    PORT
      LAYER M4 ;
        RECT  172.716 84.288 172.8 84.312 ;
    END
  END sw_d[187]
  PIN sw_d[188]
    DIRECTION OUTPUT ;
    USE SIGNAL ;
    PORT
      LAYER M4 ;
        RECT  172.716 84.672 172.8 84.696 ;
    END
  END sw_d[188]
  PIN sw_d[189]
    DIRECTION OUTPUT ;
    USE SIGNAL ;
    PORT
      LAYER M4 ;
        RECT  172.716 85.152 172.8 85.176 ;
    END
  END sw_d[189]
  PIN sw_d[18]
    DIRECTION OUTPUT ;
    USE SIGNAL ;
    PORT
      LAYER M4 ;
        RECT  172.716 12.576 172.8 12.6 ;
    END
  END sw_d[18]
  PIN sw_d[190]
    DIRECTION OUTPUT ;
    USE SIGNAL ;
    PORT
      LAYER M4 ;
        RECT  172.716 85.536 172.8 85.56 ;
    END
  END sw_d[190]
  PIN sw_d[191]
    DIRECTION OUTPUT ;
    USE SIGNAL ;
    PORT
      LAYER M4 ;
        RECT  172.716 85.92 172.8 85.944 ;
    END
  END sw_d[191]
  PIN sw_d[192]
    DIRECTION OUTPUT ;
    USE SIGNAL ;
    PORT
      LAYER M4 ;
        RECT  172.716 86.4 172.8 86.424 ;
    END
  END sw_d[192]
  PIN sw_d[193]
    DIRECTION OUTPUT ;
    USE SIGNAL ;
    PORT
      LAYER M4 ;
        RECT  172.716 86.784 172.8 86.808 ;
    END
  END sw_d[193]
  PIN sw_d[194]
    DIRECTION OUTPUT ;
    USE SIGNAL ;
    PORT
      LAYER M4 ;
        RECT  172.716 87.264 172.8 87.288 ;
    END
  END sw_d[194]
  PIN sw_d[195]
    DIRECTION OUTPUT ;
    USE SIGNAL ;
    PORT
      LAYER M4 ;
        RECT  172.716 87.648 172.8 87.672 ;
    END
  END sw_d[195]
  PIN sw_d[196]
    DIRECTION OUTPUT ;
    USE SIGNAL ;
    PORT
      LAYER M4 ;
        RECT  172.716 88.128 172.8 88.152 ;
    END
  END sw_d[196]
  PIN sw_d[197]
    DIRECTION OUTPUT ;
    USE SIGNAL ;
    PORT
      LAYER M4 ;
        RECT  172.716 88.512 172.8 88.536 ;
    END
  END sw_d[197]
  PIN sw_d[198]
    DIRECTION OUTPUT ;
    USE SIGNAL ;
    PORT
      LAYER M4 ;
        RECT  172.716 88.896 172.8 88.92 ;
    END
  END sw_d[198]
  PIN sw_d[199]
    DIRECTION OUTPUT ;
    USE SIGNAL ;
    PORT
      LAYER M4 ;
        RECT  172.716 89.376 172.8 89.4 ;
    END
  END sw_d[199]
  PIN sw_d[19]
    DIRECTION OUTPUT ;
    USE SIGNAL ;
    PORT
      LAYER M4 ;
        RECT  172.716 12.96 172.8 12.984 ;
    END
  END sw_d[19]
  PIN sw_d[1]
    DIRECTION OUTPUT ;
    USE SIGNAL ;
    PORT
      LAYER M4 ;
        RECT  172.716 5.376 172.8 5.4 ;
    END
  END sw_d[1]
  PIN sw_d[200]
    DIRECTION OUTPUT ;
    USE SIGNAL ;
    PORT
      LAYER M4 ;
        RECT  172.716 89.76 172.8 89.784 ;
    END
  END sw_d[200]
  PIN sw_d[201]
    DIRECTION OUTPUT ;
    USE SIGNAL ;
    PORT
      LAYER M4 ;
        RECT  172.716 90.24 172.8 90.264 ;
    END
  END sw_d[201]
  PIN sw_d[202]
    DIRECTION OUTPUT ;
    USE SIGNAL ;
    PORT
      LAYER M4 ;
        RECT  172.716 90.624 172.8 90.648 ;
    END
  END sw_d[202]
  PIN sw_d[203]
    DIRECTION OUTPUT ;
    USE SIGNAL ;
    PORT
      LAYER M4 ;
        RECT  172.716 91.008 172.8 91.032 ;
    END
  END sw_d[203]
  PIN sw_d[204]
    DIRECTION OUTPUT ;
    USE SIGNAL ;
    PORT
      LAYER M4 ;
        RECT  172.716 91.488 172.8 91.512 ;
    END
  END sw_d[204]
  PIN sw_d[205]
    DIRECTION OUTPUT ;
    USE SIGNAL ;
    PORT
      LAYER M4 ;
        RECT  172.716 91.872 172.8 91.896 ;
    END
  END sw_d[205]
  PIN sw_d[206]
    DIRECTION OUTPUT ;
    USE SIGNAL ;
    PORT
      LAYER M4 ;
        RECT  172.716 92.352 172.8 92.376 ;
    END
  END sw_d[206]
  PIN sw_d[207]
    DIRECTION OUTPUT ;
    USE SIGNAL ;
    PORT
      LAYER M4 ;
        RECT  172.716 92.736 172.8 92.76 ;
    END
  END sw_d[207]
  PIN sw_d[208]
    DIRECTION OUTPUT ;
    USE SIGNAL ;
    PORT
      LAYER M4 ;
        RECT  172.716 93.216 172.8 93.24 ;
    END
  END sw_d[208]
  PIN sw_d[209]
    DIRECTION OUTPUT ;
    USE SIGNAL ;
    PORT
      LAYER M4 ;
        RECT  172.716 93.6 172.8 93.624 ;
    END
  END sw_d[209]
  PIN sw_d[20]
    DIRECTION OUTPUT ;
    USE SIGNAL ;
    PORT
      LAYER M4 ;
        RECT  172.716 13.44 172.8 13.464 ;
    END
  END sw_d[20]
  PIN sw_d[210]
    DIRECTION OUTPUT ;
    USE SIGNAL ;
    PORT
      LAYER M4 ;
        RECT  172.716 93.984 172.8 94.008 ;
    END
  END sw_d[210]
  PIN sw_d[211]
    DIRECTION OUTPUT ;
    USE SIGNAL ;
    PORT
      LAYER M4 ;
        RECT  172.716 94.464 172.8 94.488 ;
    END
  END sw_d[211]
  PIN sw_d[212]
    DIRECTION OUTPUT ;
    USE SIGNAL ;
    PORT
      LAYER M4 ;
        RECT  172.716 94.848 172.8 94.872 ;
    END
  END sw_d[212]
  PIN sw_d[213]
    DIRECTION OUTPUT ;
    USE SIGNAL ;
    PORT
      LAYER M4 ;
        RECT  172.716 95.328 172.8 95.352 ;
    END
  END sw_d[213]
  PIN sw_d[214]
    DIRECTION OUTPUT ;
    USE SIGNAL ;
    PORT
      LAYER M4 ;
        RECT  172.716 95.712 172.8 95.736 ;
    END
  END sw_d[214]
  PIN sw_d[215]
    DIRECTION OUTPUT ;
    USE SIGNAL ;
    PORT
      LAYER M4 ;
        RECT  172.716 96.192 172.8 96.216 ;
    END
  END sw_d[215]
  PIN sw_d[216]
    DIRECTION OUTPUT ;
    USE SIGNAL ;
    PORT
      LAYER M4 ;
        RECT  172.716 96.576 172.8 96.6 ;
    END
  END sw_d[216]
  PIN sw_d[217]
    DIRECTION OUTPUT ;
    USE SIGNAL ;
    PORT
      LAYER M4 ;
        RECT  172.716 96.96 172.8 96.984 ;
    END
  END sw_d[217]
  PIN sw_d[218]
    DIRECTION OUTPUT ;
    USE SIGNAL ;
    PORT
      LAYER M4 ;
        RECT  172.716 97.44 172.8 97.464 ;
    END
  END sw_d[218]
  PIN sw_d[219]
    DIRECTION OUTPUT ;
    USE SIGNAL ;
    PORT
      LAYER M4 ;
        RECT  172.716 97.824 172.8 97.848 ;
    END
  END sw_d[219]
  PIN sw_d[21]
    DIRECTION OUTPUT ;
    USE SIGNAL ;
    PORT
      LAYER M4 ;
        RECT  172.716 13.824 172.8 13.848 ;
    END
  END sw_d[21]
  PIN sw_d[220]
    DIRECTION OUTPUT ;
    USE SIGNAL ;
    PORT
      LAYER M4 ;
        RECT  172.716 98.304 172.8 98.328 ;
    END
  END sw_d[220]
  PIN sw_d[221]
    DIRECTION OUTPUT ;
    USE SIGNAL ;
    PORT
      LAYER M4 ;
        RECT  172.716 98.688 172.8 98.712 ;
    END
  END sw_d[221]
  PIN sw_d[222]
    DIRECTION OUTPUT ;
    USE SIGNAL ;
    PORT
      LAYER M4 ;
        RECT  172.716 99.072 172.8 99.096 ;
    END
  END sw_d[222]
  PIN sw_d[223]
    DIRECTION OUTPUT ;
    USE SIGNAL ;
    PORT
      LAYER M4 ;
        RECT  172.716 99.552 172.8 99.576 ;
    END
  END sw_d[223]
  PIN sw_d[224]
    DIRECTION OUTPUT ;
    USE SIGNAL ;
    PORT
      LAYER M4 ;
        RECT  172.716 99.936 172.8 99.96 ;
    END
  END sw_d[224]
  PIN sw_d[225]
    DIRECTION OUTPUT ;
    USE SIGNAL ;
    PORT
      LAYER M4 ;
        RECT  172.716 100.416 172.8 100.44 ;
    END
  END sw_d[225]
  PIN sw_d[226]
    DIRECTION OUTPUT ;
    USE SIGNAL ;
    PORT
      LAYER M4 ;
        RECT  172.716 100.8 172.8 100.824 ;
    END
  END sw_d[226]
  PIN sw_d[227]
    DIRECTION OUTPUT ;
    USE SIGNAL ;
    PORT
      LAYER M4 ;
        RECT  172.716 101.28 172.8 101.304 ;
    END
  END sw_d[227]
  PIN sw_d[228]
    DIRECTION OUTPUT ;
    USE SIGNAL ;
    PORT
      LAYER M4 ;
        RECT  172.716 101.664 172.8 101.688 ;
    END
  END sw_d[228]
  PIN sw_d[229]
    DIRECTION OUTPUT ;
    USE SIGNAL ;
    PORT
      LAYER M4 ;
        RECT  172.716 102.048 172.8 102.072 ;
    END
  END sw_d[229]
  PIN sw_d[22]
    DIRECTION OUTPUT ;
    USE SIGNAL ;
    PORT
      LAYER M4 ;
        RECT  172.716 14.304 172.8 14.328 ;
    END
  END sw_d[22]
  PIN sw_d[230]
    DIRECTION OUTPUT ;
    USE SIGNAL ;
    PORT
      LAYER M4 ;
        RECT  172.716 102.528 172.8 102.552 ;
    END
  END sw_d[230]
  PIN sw_d[231]
    DIRECTION OUTPUT ;
    USE SIGNAL ;
    PORT
      LAYER M4 ;
        RECT  172.716 102.912 172.8 102.936 ;
    END
  END sw_d[231]
  PIN sw_d[232]
    DIRECTION OUTPUT ;
    USE SIGNAL ;
    PORT
      LAYER M4 ;
        RECT  172.716 103.392 172.8 103.416 ;
    END
  END sw_d[232]
  PIN sw_d[233]
    DIRECTION OUTPUT ;
    USE SIGNAL ;
    PORT
      LAYER M4 ;
        RECT  172.716 103.776 172.8 103.8 ;
    END
  END sw_d[233]
  PIN sw_d[234]
    DIRECTION OUTPUT ;
    USE SIGNAL ;
    PORT
      LAYER M4 ;
        RECT  172.716 104.16 172.8 104.184 ;
    END
  END sw_d[234]
  PIN sw_d[235]
    DIRECTION OUTPUT ;
    USE SIGNAL ;
    PORT
      LAYER M4 ;
        RECT  172.716 104.64 172.8 104.664 ;
    END
  END sw_d[235]
  PIN sw_d[236]
    DIRECTION OUTPUT ;
    USE SIGNAL ;
    PORT
      LAYER M4 ;
        RECT  172.716 105.024 172.8 105.048 ;
    END
  END sw_d[236]
  PIN sw_d[237]
    DIRECTION OUTPUT ;
    USE SIGNAL ;
    PORT
      LAYER M4 ;
        RECT  172.716 105.504 172.8 105.528 ;
    END
  END sw_d[237]
  PIN sw_d[238]
    DIRECTION OUTPUT ;
    USE SIGNAL ;
    PORT
      LAYER M4 ;
        RECT  172.716 105.888 172.8 105.912 ;
    END
  END sw_d[238]
  PIN sw_d[239]
    DIRECTION OUTPUT ;
    USE SIGNAL ;
    PORT
      LAYER M4 ;
        RECT  172.716 106.368 172.8 106.392 ;
    END
  END sw_d[239]
  PIN sw_d[23]
    DIRECTION OUTPUT ;
    USE SIGNAL ;
    PORT
      LAYER M4 ;
        RECT  172.716 14.688 172.8 14.712 ;
    END
  END sw_d[23]
  PIN sw_d[240]
    DIRECTION OUTPUT ;
    USE SIGNAL ;
    PORT
      LAYER M4 ;
        RECT  172.716 106.752 172.8 106.776 ;
    END
  END sw_d[240]
  PIN sw_d[241]
    DIRECTION OUTPUT ;
    USE SIGNAL ;
    PORT
      LAYER M4 ;
        RECT  172.716 107.136 172.8 107.16 ;
    END
  END sw_d[241]
  PIN sw_d[242]
    DIRECTION OUTPUT ;
    USE SIGNAL ;
    PORT
      LAYER M4 ;
        RECT  172.716 107.616 172.8 107.64 ;
    END
  END sw_d[242]
  PIN sw_d[243]
    DIRECTION OUTPUT ;
    USE SIGNAL ;
    PORT
      LAYER M4 ;
        RECT  172.716 108 172.8 108.024 ;
    END
  END sw_d[243]
  PIN sw_d[244]
    DIRECTION OUTPUT ;
    USE SIGNAL ;
    PORT
      LAYER M4 ;
        RECT  172.716 108.48 172.8 108.504 ;
    END
  END sw_d[244]
  PIN sw_d[245]
    DIRECTION OUTPUT ;
    USE SIGNAL ;
    PORT
      LAYER M4 ;
        RECT  172.716 108.864 172.8 108.888 ;
    END
  END sw_d[245]
  PIN sw_d[246]
    DIRECTION OUTPUT ;
    USE SIGNAL ;
    PORT
      LAYER M4 ;
        RECT  172.716 109.248 172.8 109.272 ;
    END
  END sw_d[246]
  PIN sw_d[247]
    DIRECTION OUTPUT ;
    USE SIGNAL ;
    PORT
      LAYER M4 ;
        RECT  172.716 109.728 172.8 109.752 ;
    END
  END sw_d[247]
  PIN sw_d[248]
    DIRECTION OUTPUT ;
    USE SIGNAL ;
    PORT
      LAYER M4 ;
        RECT  172.716 110.112 172.8 110.136 ;
    END
  END sw_d[248]
  PIN sw_d[249]
    DIRECTION OUTPUT ;
    USE SIGNAL ;
    PORT
      LAYER M4 ;
        RECT  172.716 110.592 172.8 110.616 ;
    END
  END sw_d[249]
  PIN sw_d[24]
    DIRECTION OUTPUT ;
    USE SIGNAL ;
    PORT
      LAYER M4 ;
        RECT  172.716 15.168 172.8 15.192 ;
    END
  END sw_d[24]
  PIN sw_d[250]
    DIRECTION OUTPUT ;
    USE SIGNAL ;
    PORT
      LAYER M4 ;
        RECT  172.716 110.976 172.8 111 ;
    END
  END sw_d[250]
  PIN sw_d[251]
    DIRECTION OUTPUT ;
    USE SIGNAL ;
    PORT
      LAYER M4 ;
        RECT  172.716 111.456 172.8 111.48 ;
    END
  END sw_d[251]
  PIN sw_d[252]
    DIRECTION OUTPUT ;
    USE SIGNAL ;
    PORT
      LAYER M4 ;
        RECT  172.716 111.84 172.8 111.864 ;
    END
  END sw_d[252]
  PIN sw_d[253]
    DIRECTION OUTPUT ;
    USE SIGNAL ;
    PORT
      LAYER M4 ;
        RECT  172.716 112.224 172.8 112.248 ;
    END
  END sw_d[253]
  PIN sw_d[254]
    DIRECTION OUTPUT ;
    USE SIGNAL ;
    PORT
      LAYER M4 ;
        RECT  172.716 112.704 172.8 112.728 ;
    END
  END sw_d[254]
  PIN sw_d[255]
    DIRECTION OUTPUT ;
    USE SIGNAL ;
    PORT
      LAYER M4 ;
        RECT  172.716 113.088 172.8 113.112 ;
    END
  END sw_d[255]
  PIN sw_d[25]
    DIRECTION OUTPUT ;
    USE SIGNAL ;
    PORT
      LAYER M4 ;
        RECT  172.716 15.552 172.8 15.576 ;
    END
  END sw_d[25]
  PIN sw_d[26]
    DIRECTION OUTPUT ;
    USE SIGNAL ;
    PORT
      LAYER M4 ;
        RECT  172.716 15.936 172.8 15.96 ;
    END
  END sw_d[26]
  PIN sw_d[27]
    DIRECTION OUTPUT ;
    USE SIGNAL ;
    PORT
      LAYER M4 ;
        RECT  172.716 16.416 172.8 16.44 ;
    END
  END sw_d[27]
  PIN sw_d[28]
    DIRECTION OUTPUT ;
    USE SIGNAL ;
    PORT
      LAYER M4 ;
        RECT  172.716 16.8 172.8 16.824 ;
    END
  END sw_d[28]
  PIN sw_d[29]
    DIRECTION OUTPUT ;
    USE SIGNAL ;
    PORT
      LAYER M4 ;
        RECT  172.716 17.28 172.8 17.304 ;
    END
  END sw_d[29]
  PIN sw_d[2]
    DIRECTION OUTPUT ;
    USE SIGNAL ;
    PORT
      LAYER M4 ;
        RECT  172.716 5.76 172.8 5.784 ;
    END
  END sw_d[2]
  PIN sw_d[30]
    DIRECTION OUTPUT ;
    USE SIGNAL ;
    PORT
      LAYER M4 ;
        RECT  172.716 17.664 172.8 17.688 ;
    END
  END sw_d[30]
  PIN sw_d[31]
    DIRECTION OUTPUT ;
    USE SIGNAL ;
    PORT
      LAYER M4 ;
        RECT  172.716 18.048 172.8 18.072 ;
    END
  END sw_d[31]
  PIN sw_d[32]
    DIRECTION OUTPUT ;
    USE SIGNAL ;
    PORT
      LAYER M4 ;
        RECT  172.716 18.528 172.8 18.552 ;
    END
  END sw_d[32]
  PIN sw_d[33]
    DIRECTION OUTPUT ;
    USE SIGNAL ;
    PORT
      LAYER M4 ;
        RECT  172.716 18.912 172.8 18.936 ;
    END
  END sw_d[33]
  PIN sw_d[34]
    DIRECTION OUTPUT ;
    USE SIGNAL ;
    PORT
      LAYER M4 ;
        RECT  172.716 19.392 172.8 19.416 ;
    END
  END sw_d[34]
  PIN sw_d[35]
    DIRECTION OUTPUT ;
    USE SIGNAL ;
    PORT
      LAYER M4 ;
        RECT  172.716 19.776 172.8 19.8 ;
    END
  END sw_d[35]
  PIN sw_d[36]
    DIRECTION OUTPUT ;
    USE SIGNAL ;
    PORT
      LAYER M4 ;
        RECT  172.716 20.256 172.8 20.28 ;
    END
  END sw_d[36]
  PIN sw_d[37]
    DIRECTION OUTPUT ;
    USE SIGNAL ;
    PORT
      LAYER M4 ;
        RECT  172.716 20.64 172.8 20.664 ;
    END
  END sw_d[37]
  PIN sw_d[38]
    DIRECTION OUTPUT ;
    USE SIGNAL ;
    PORT
      LAYER M4 ;
        RECT  172.716 21.024 172.8 21.048 ;
    END
  END sw_d[38]
  PIN sw_d[39]
    DIRECTION OUTPUT ;
    USE SIGNAL ;
    PORT
      LAYER M4 ;
        RECT  172.716 21.504 172.8 21.528 ;
    END
  END sw_d[39]
  PIN sw_d[3]
    DIRECTION OUTPUT ;
    USE SIGNAL ;
    PORT
      LAYER M4 ;
        RECT  172.716 6.24 172.8 6.264 ;
    END
  END sw_d[3]
  PIN sw_d[40]
    DIRECTION OUTPUT ;
    USE SIGNAL ;
    PORT
      LAYER M4 ;
        RECT  172.716 21.888 172.8 21.912 ;
    END
  END sw_d[40]
  PIN sw_d[41]
    DIRECTION OUTPUT ;
    USE SIGNAL ;
    PORT
      LAYER M4 ;
        RECT  172.716 22.368 172.8 22.392 ;
    END
  END sw_d[41]
  PIN sw_d[42]
    DIRECTION OUTPUT ;
    USE SIGNAL ;
    PORT
      LAYER M4 ;
        RECT  172.716 22.752 172.8 22.776 ;
    END
  END sw_d[42]
  PIN sw_d[43]
    DIRECTION OUTPUT ;
    USE SIGNAL ;
    PORT
      LAYER M4 ;
        RECT  172.716 23.232 172.8 23.256 ;
    END
  END sw_d[43]
  PIN sw_d[44]
    DIRECTION OUTPUT ;
    USE SIGNAL ;
    PORT
      LAYER M4 ;
        RECT  172.716 23.616 172.8 23.64 ;
    END
  END sw_d[44]
  PIN sw_d[45]
    DIRECTION OUTPUT ;
    USE SIGNAL ;
    PORT
      LAYER M4 ;
        RECT  172.716 24 172.8 24.024 ;
    END
  END sw_d[45]
  PIN sw_d[46]
    DIRECTION OUTPUT ;
    USE SIGNAL ;
    PORT
      LAYER M4 ;
        RECT  172.716 24.48 172.8 24.504 ;
    END
  END sw_d[46]
  PIN sw_d[47]
    DIRECTION OUTPUT ;
    USE SIGNAL ;
    PORT
      LAYER M4 ;
        RECT  172.716 24.864 172.8 24.888 ;
    END
  END sw_d[47]
  PIN sw_d[48]
    DIRECTION OUTPUT ;
    USE SIGNAL ;
    PORT
      LAYER M4 ;
        RECT  172.716 25.344 172.8 25.368 ;
    END
  END sw_d[48]
  PIN sw_d[49]
    DIRECTION OUTPUT ;
    USE SIGNAL ;
    PORT
      LAYER M4 ;
        RECT  172.716 25.728 172.8 25.752 ;
    END
  END sw_d[49]
  PIN sw_d[4]
    DIRECTION OUTPUT ;
    USE SIGNAL ;
    PORT
      LAYER M4 ;
        RECT  172.716 6.624 172.8 6.648 ;
    END
  END sw_d[4]
  PIN sw_d[50]
    DIRECTION OUTPUT ;
    USE SIGNAL ;
    PORT
      LAYER M4 ;
        RECT  172.716 26.112 172.8 26.136 ;
    END
  END sw_d[50]
  PIN sw_d[51]
    DIRECTION OUTPUT ;
    USE SIGNAL ;
    PORT
      LAYER M4 ;
        RECT  172.716 26.592 172.8 26.616 ;
    END
  END sw_d[51]
  PIN sw_d[52]
    DIRECTION OUTPUT ;
    USE SIGNAL ;
    PORT
      LAYER M4 ;
        RECT  172.716 26.976 172.8 27 ;
    END
  END sw_d[52]
  PIN sw_d[53]
    DIRECTION OUTPUT ;
    USE SIGNAL ;
    PORT
      LAYER M4 ;
        RECT  172.716 27.456 172.8 27.48 ;
    END
  END sw_d[53]
  PIN sw_d[54]
    DIRECTION OUTPUT ;
    USE SIGNAL ;
    PORT
      LAYER M4 ;
        RECT  172.716 27.84 172.8 27.864 ;
    END
  END sw_d[54]
  PIN sw_d[55]
    DIRECTION OUTPUT ;
    USE SIGNAL ;
    PORT
      LAYER M4 ;
        RECT  172.716 28.32 172.8 28.344 ;
    END
  END sw_d[55]
  PIN sw_d[56]
    DIRECTION OUTPUT ;
    USE SIGNAL ;
    PORT
      LAYER M4 ;
        RECT  172.716 28.704 172.8 28.728 ;
    END
  END sw_d[56]
  PIN sw_d[57]
    DIRECTION OUTPUT ;
    USE SIGNAL ;
    PORT
      LAYER M4 ;
        RECT  172.716 29.088 172.8 29.112 ;
    END
  END sw_d[57]
  PIN sw_d[58]
    DIRECTION OUTPUT ;
    USE SIGNAL ;
    PORT
      LAYER M4 ;
        RECT  172.716 29.568 172.8 29.592 ;
    END
  END sw_d[58]
  PIN sw_d[59]
    DIRECTION OUTPUT ;
    USE SIGNAL ;
    PORT
      LAYER M4 ;
        RECT  172.716 29.952 172.8 29.976 ;
    END
  END sw_d[59]
  PIN sw_d[5]
    DIRECTION OUTPUT ;
    USE SIGNAL ;
    PORT
      LAYER M4 ;
        RECT  172.716 7.104 172.8 7.128 ;
    END
  END sw_d[5]
  PIN sw_d[60]
    DIRECTION OUTPUT ;
    USE SIGNAL ;
    PORT
      LAYER M4 ;
        RECT  172.716 30.432 172.8 30.456 ;
    END
  END sw_d[60]
  PIN sw_d[61]
    DIRECTION OUTPUT ;
    USE SIGNAL ;
    PORT
      LAYER M4 ;
        RECT  172.716 30.816 172.8 30.84 ;
    END
  END sw_d[61]
  PIN sw_d[62]
    DIRECTION OUTPUT ;
    USE SIGNAL ;
    PORT
      LAYER M4 ;
        RECT  172.716 31.2 172.8 31.224 ;
    END
  END sw_d[62]
  PIN sw_d[63]
    DIRECTION OUTPUT ;
    USE SIGNAL ;
    PORT
      LAYER M4 ;
        RECT  172.716 31.68 172.8 31.704 ;
    END
  END sw_d[63]
  PIN sw_d[64]
    DIRECTION OUTPUT ;
    USE SIGNAL ;
    PORT
      LAYER M4 ;
        RECT  172.716 32.064 172.8 32.088 ;
    END
  END sw_d[64]
  PIN sw_d[65]
    DIRECTION OUTPUT ;
    USE SIGNAL ;
    PORT
      LAYER M4 ;
        RECT  172.716 32.544 172.8 32.568 ;
    END
  END sw_d[65]
  PIN sw_d[66]
    DIRECTION OUTPUT ;
    USE SIGNAL ;
    PORT
      LAYER M4 ;
        RECT  172.716 32.928 172.8 32.952 ;
    END
  END sw_d[66]
  PIN sw_d[67]
    DIRECTION OUTPUT ;
    USE SIGNAL ;
    PORT
      LAYER M4 ;
        RECT  172.716 33.408 172.8 33.432 ;
    END
  END sw_d[67]
  PIN sw_d[68]
    DIRECTION OUTPUT ;
    USE SIGNAL ;
    PORT
      LAYER M4 ;
        RECT  172.716 33.792 172.8 33.816 ;
    END
  END sw_d[68]
  PIN sw_d[69]
    DIRECTION OUTPUT ;
    USE SIGNAL ;
    PORT
      LAYER M4 ;
        RECT  172.716 34.176 172.8 34.2 ;
    END
  END sw_d[69]
  PIN sw_d[6]
    DIRECTION OUTPUT ;
    USE SIGNAL ;
    PORT
      LAYER M4 ;
        RECT  172.716 7.488 172.8 7.512 ;
    END
  END sw_d[6]
  PIN sw_d[70]
    DIRECTION OUTPUT ;
    USE SIGNAL ;
    PORT
      LAYER M4 ;
        RECT  172.716 34.656 172.8 34.68 ;
    END
  END sw_d[70]
  PIN sw_d[71]
    DIRECTION OUTPUT ;
    USE SIGNAL ;
    PORT
      LAYER M4 ;
        RECT  172.716 35.04 172.8 35.064 ;
    END
  END sw_d[71]
  PIN sw_d[72]
    DIRECTION OUTPUT ;
    USE SIGNAL ;
    PORT
      LAYER M4 ;
        RECT  172.716 35.52 172.8 35.544 ;
    END
  END sw_d[72]
  PIN sw_d[73]
    DIRECTION OUTPUT ;
    USE SIGNAL ;
    PORT
      LAYER M4 ;
        RECT  172.716 35.904 172.8 35.928 ;
    END
  END sw_d[73]
  PIN sw_d[74]
    DIRECTION OUTPUT ;
    USE SIGNAL ;
    PORT
      LAYER M4 ;
        RECT  172.716 36.288 172.8 36.312 ;
    END
  END sw_d[74]
  PIN sw_d[75]
    DIRECTION OUTPUT ;
    USE SIGNAL ;
    PORT
      LAYER M4 ;
        RECT  172.716 36.768 172.8 36.792 ;
    END
  END sw_d[75]
  PIN sw_d[76]
    DIRECTION OUTPUT ;
    USE SIGNAL ;
    PORT
      LAYER M4 ;
        RECT  172.716 37.152 172.8 37.176 ;
    END
  END sw_d[76]
  PIN sw_d[77]
    DIRECTION OUTPUT ;
    USE SIGNAL ;
    PORT
      LAYER M4 ;
        RECT  172.716 37.632 172.8 37.656 ;
    END
  END sw_d[77]
  PIN sw_d[78]
    DIRECTION OUTPUT ;
    USE SIGNAL ;
    PORT
      LAYER M4 ;
        RECT  172.716 38.016 172.8 38.04 ;
    END
  END sw_d[78]
  PIN sw_d[79]
    DIRECTION OUTPUT ;
    USE SIGNAL ;
    PORT
      LAYER M4 ;
        RECT  172.716 38.496 172.8 38.52 ;
    END
  END sw_d[79]
  PIN sw_d[7]
    DIRECTION OUTPUT ;
    USE SIGNAL ;
    PORT
      LAYER M4 ;
        RECT  172.716 7.872 172.8 7.896 ;
    END
  END sw_d[7]
  PIN sw_d[80]
    DIRECTION OUTPUT ;
    USE SIGNAL ;
    PORT
      LAYER M4 ;
        RECT  172.716 38.88 172.8 38.904 ;
    END
  END sw_d[80]
  PIN sw_d[81]
    DIRECTION OUTPUT ;
    USE SIGNAL ;
    PORT
      LAYER M4 ;
        RECT  172.716 39.264 172.8 39.288 ;
    END
  END sw_d[81]
  PIN sw_d[82]
    DIRECTION OUTPUT ;
    USE SIGNAL ;
    PORT
      LAYER M4 ;
        RECT  172.716 39.744 172.8 39.768 ;
    END
  END sw_d[82]
  PIN sw_d[83]
    DIRECTION OUTPUT ;
    USE SIGNAL ;
    PORT
      LAYER M4 ;
        RECT  172.716 40.128 172.8 40.152 ;
    END
  END sw_d[83]
  PIN sw_d[84]
    DIRECTION OUTPUT ;
    USE SIGNAL ;
    PORT
      LAYER M4 ;
        RECT  172.716 40.608 172.8 40.632 ;
    END
  END sw_d[84]
  PIN sw_d[85]
    DIRECTION OUTPUT ;
    USE SIGNAL ;
    PORT
      LAYER M4 ;
        RECT  172.716 40.992 172.8 41.016 ;
    END
  END sw_d[85]
  PIN sw_d[86]
    DIRECTION OUTPUT ;
    USE SIGNAL ;
    PORT
      LAYER M4 ;
        RECT  172.716 41.472 172.8 41.496 ;
    END
  END sw_d[86]
  PIN sw_d[87]
    DIRECTION OUTPUT ;
    USE SIGNAL ;
    PORT
      LAYER M4 ;
        RECT  172.716 41.856 172.8 41.88 ;
    END
  END sw_d[87]
  PIN sw_d[88]
    DIRECTION OUTPUT ;
    USE SIGNAL ;
    PORT
      LAYER M4 ;
        RECT  172.716 42.24 172.8 42.264 ;
    END
  END sw_d[88]
  PIN sw_d[89]
    DIRECTION OUTPUT ;
    USE SIGNAL ;
    PORT
      LAYER M4 ;
        RECT  172.716 42.72 172.8 42.744 ;
    END
  END sw_d[89]
  PIN sw_d[8]
    DIRECTION OUTPUT ;
    USE SIGNAL ;
    PORT
      LAYER M4 ;
        RECT  172.716 8.352 172.8 8.376 ;
    END
  END sw_d[8]
  PIN sw_d[90]
    DIRECTION OUTPUT ;
    USE SIGNAL ;
    PORT
      LAYER M4 ;
        RECT  172.716 43.104 172.8 43.128 ;
    END
  END sw_d[90]
  PIN sw_d[91]
    DIRECTION OUTPUT ;
    USE SIGNAL ;
    PORT
      LAYER M4 ;
        RECT  172.716 43.584 172.8 43.608 ;
    END
  END sw_d[91]
  PIN sw_d[92]
    DIRECTION OUTPUT ;
    USE SIGNAL ;
    PORT
      LAYER M4 ;
        RECT  172.716 43.968 172.8 43.992 ;
    END
  END sw_d[92]
  PIN sw_d[93]
    DIRECTION OUTPUT ;
    USE SIGNAL ;
    PORT
      LAYER M4 ;
        RECT  172.716 44.352 172.8 44.376 ;
    END
  END sw_d[93]
  PIN sw_d[94]
    DIRECTION OUTPUT ;
    USE SIGNAL ;
    PORT
      LAYER M4 ;
        RECT  172.716 44.832 172.8 44.856 ;
    END
  END sw_d[94]
  PIN sw_d[95]
    DIRECTION OUTPUT ;
    USE SIGNAL ;
    PORT
      LAYER M4 ;
        RECT  172.716 45.216 172.8 45.24 ;
    END
  END sw_d[95]
  PIN sw_d[96]
    DIRECTION OUTPUT ;
    USE SIGNAL ;
    PORT
      LAYER M4 ;
        RECT  172.716 45.696 172.8 45.72 ;
    END
  END sw_d[96]
  PIN sw_d[97]
    DIRECTION OUTPUT ;
    USE SIGNAL ;
    PORT
      LAYER M4 ;
        RECT  172.716 46.08 172.8 46.104 ;
    END
  END sw_d[97]
  PIN sw_d[98]
    DIRECTION OUTPUT ;
    USE SIGNAL ;
    PORT
      LAYER M4 ;
        RECT  172.716 46.56 172.8 46.584 ;
    END
  END sw_d[98]
  PIN sw_d[99]
    DIRECTION OUTPUT ;
    USE SIGNAL ;
    PORT
      LAYER M4 ;
        RECT  172.716 46.944 172.8 46.968 ;
    END
  END sw_d[99]
  PIN sw_d[9]
    DIRECTION OUTPUT ;
    USE SIGNAL ;
    PORT
      LAYER M4 ;
        RECT  172.716 8.736 172.8 8.76 ;
    END
  END sw_d[9]
  PIN sw_fi
    DIRECTION INPUT ;
    USE SIGNAL ;
    PORT
      LAYER M4 ;
        RECT  172.716 168.288 172.8 168.312 ;
    END
  END sw_fi
  PIN sw_lim[0]
    DIRECTION OUTPUT ;
    USE SIGNAL ;
    PORT
      LAYER M4 ;
        RECT  172.716 127.104 172.8 127.128 ;
    END
  END sw_lim[0]
  PIN sw_lim[10]
    DIRECTION OUTPUT ;
    USE SIGNAL ;
    PORT
      LAYER M4 ;
        RECT  172.716 131.328 172.8 131.352 ;
    END
  END sw_lim[10]
  PIN sw_lim[11]
    DIRECTION OUTPUT ;
    USE SIGNAL ;
    PORT
      LAYER M4 ;
        RECT  172.716 131.808 172.8 131.832 ;
    END
  END sw_lim[11]
  PIN sw_lim[12]
    DIRECTION OUTPUT ;
    USE SIGNAL ;
    PORT
      LAYER M4 ;
        RECT  172.716 132.192 172.8 132.216 ;
    END
  END sw_lim[12]
  PIN sw_lim[13]
    DIRECTION OUTPUT ;
    USE SIGNAL ;
    PORT
      LAYER M4 ;
        RECT  172.716 132.672 172.8 132.696 ;
    END
  END sw_lim[13]
  PIN sw_lim[14]
    DIRECTION OUTPUT ;
    USE SIGNAL ;
    PORT
      LAYER M4 ;
        RECT  172.716 133.056 172.8 133.08 ;
    END
  END sw_lim[14]
  PIN sw_lim[15]
    DIRECTION OUTPUT ;
    USE SIGNAL ;
    PORT
      LAYER M4 ;
        RECT  172.716 133.44 172.8 133.464 ;
    END
  END sw_lim[15]
  PIN sw_lim[16]
    DIRECTION OUTPUT ;
    USE SIGNAL ;
    PORT
      LAYER M4 ;
        RECT  172.716 133.92 172.8 133.944 ;
    END
  END sw_lim[16]
  PIN sw_lim[17]
    DIRECTION OUTPUT ;
    USE SIGNAL ;
    PORT
      LAYER M4 ;
        RECT  172.716 134.304 172.8 134.328 ;
    END
  END sw_lim[17]
  PIN sw_lim[18]
    DIRECTION OUTPUT ;
    USE SIGNAL ;
    PORT
      LAYER M4 ;
        RECT  172.716 134.784 172.8 134.808 ;
    END
  END sw_lim[18]
  PIN sw_lim[19]
    DIRECTION OUTPUT ;
    USE SIGNAL ;
    PORT
      LAYER M4 ;
        RECT  172.716 135.168 172.8 135.192 ;
    END
  END sw_lim[19]
  PIN sw_lim[1]
    DIRECTION OUTPUT ;
    USE SIGNAL ;
    PORT
      LAYER M4 ;
        RECT  172.716 127.488 172.8 127.512 ;
    END
  END sw_lim[1]
  PIN sw_lim[20]
    DIRECTION OUTPUT ;
    USE SIGNAL ;
    PORT
      LAYER M4 ;
        RECT  172.716 135.552 172.8 135.576 ;
    END
  END sw_lim[20]
  PIN sw_lim[21]
    DIRECTION OUTPUT ;
    USE SIGNAL ;
    PORT
      LAYER M4 ;
        RECT  172.716 136.032 172.8 136.056 ;
    END
  END sw_lim[21]
  PIN sw_lim[22]
    DIRECTION OUTPUT ;
    USE SIGNAL ;
    PORT
      LAYER M4 ;
        RECT  172.716 136.416 172.8 136.44 ;
    END
  END sw_lim[22]
  PIN sw_lim[23]
    DIRECTION OUTPUT ;
    USE SIGNAL ;
    PORT
      LAYER M4 ;
        RECT  172.716 136.896 172.8 136.92 ;
    END
  END sw_lim[23]
  PIN sw_lim[24]
    DIRECTION OUTPUT ;
    USE SIGNAL ;
    PORT
      LAYER M4 ;
        RECT  172.716 137.28 172.8 137.304 ;
    END
  END sw_lim[24]
  PIN sw_lim[25]
    DIRECTION OUTPUT ;
    USE SIGNAL ;
    PORT
      LAYER M4 ;
        RECT  172.716 137.76 172.8 137.784 ;
    END
  END sw_lim[25]
  PIN sw_lim[26]
    DIRECTION OUTPUT ;
    USE SIGNAL ;
    PORT
      LAYER M4 ;
        RECT  172.716 138.144 172.8 138.168 ;
    END
  END sw_lim[26]
  PIN sw_lim[27]
    DIRECTION OUTPUT ;
    USE SIGNAL ;
    PORT
      LAYER M4 ;
        RECT  172.716 138.528 172.8 138.552 ;
    END
  END sw_lim[27]
  PIN sw_lim[28]
    DIRECTION OUTPUT ;
    USE SIGNAL ;
    PORT
      LAYER M4 ;
        RECT  172.716 139.008 172.8 139.032 ;
    END
  END sw_lim[28]
  PIN sw_lim[29]
    DIRECTION OUTPUT ;
    USE SIGNAL ;
    PORT
      LAYER M4 ;
        RECT  172.716 139.392 172.8 139.416 ;
    END
  END sw_lim[29]
  PIN sw_lim[2]
    DIRECTION OUTPUT ;
    USE SIGNAL ;
    PORT
      LAYER M4 ;
        RECT  172.716 127.968 172.8 127.992 ;
    END
  END sw_lim[2]
  PIN sw_lim[30]
    DIRECTION OUTPUT ;
    USE SIGNAL ;
    PORT
      LAYER M4 ;
        RECT  172.716 139.872 172.8 139.896 ;
    END
  END sw_lim[30]
  PIN sw_lim[31]
    DIRECTION OUTPUT ;
    USE SIGNAL ;
    PORT
      LAYER M4 ;
        RECT  172.716 140.256 172.8 140.28 ;
    END
  END sw_lim[31]
  PIN sw_lim[3]
    DIRECTION OUTPUT ;
    USE SIGNAL ;
    PORT
      LAYER M4 ;
        RECT  172.716 128.352 172.8 128.376 ;
    END
  END sw_lim[3]
  PIN sw_lim[4]
    DIRECTION OUTPUT ;
    USE SIGNAL ;
    PORT
      LAYER M4 ;
        RECT  172.716 128.832 172.8 128.856 ;
    END
  END sw_lim[4]
  PIN sw_lim[5]
    DIRECTION OUTPUT ;
    USE SIGNAL ;
    PORT
      LAYER M4 ;
        RECT  172.716 129.216 172.8 129.24 ;
    END
  END sw_lim[5]
  PIN sw_lim[6]
    DIRECTION OUTPUT ;
    USE SIGNAL ;
    PORT
      LAYER M4 ;
        RECT  172.716 129.696 172.8 129.72 ;
    END
  END sw_lim[6]
  PIN sw_lim[7]
    DIRECTION OUTPUT ;
    USE SIGNAL ;
    PORT
      LAYER M4 ;
        RECT  172.716 130.08 172.8 130.104 ;
    END
  END sw_lim[7]
  PIN sw_lim[8]
    DIRECTION OUTPUT ;
    USE SIGNAL ;
    PORT
      LAYER M4 ;
        RECT  172.716 130.464 172.8 130.488 ;
    END
  END sw_lim[8]
  PIN sw_lim[9]
    DIRECTION OUTPUT ;
    USE SIGNAL ;
    PORT
      LAYER M4 ;
        RECT  172.716 130.944 172.8 130.968 ;
    END
  END sw_lim[9]
  PIN sw_ri[0]
    DIRECTION INPUT ;
    USE SIGNAL ;
    PORT
      LAYER M4 ;
        RECT  172.716 141.12 172.8 141.144 ;
    END
  END sw_ri[0]
  PIN sw_ri[10]
    DIRECTION INPUT ;
    USE SIGNAL ;
    PORT
      LAYER M4 ;
        RECT  172.716 145.344 172.8 145.368 ;
    END
  END sw_ri[10]
  PIN sw_ri[11]
    DIRECTION INPUT ;
    USE SIGNAL ;
    PORT
      LAYER M4 ;
        RECT  172.716 145.728 172.8 145.752 ;
    END
  END sw_ri[11]
  PIN sw_ri[12]
    DIRECTION INPUT ;
    USE SIGNAL ;
    PORT
      LAYER M4 ;
        RECT  172.716 146.208 172.8 146.232 ;
    END
  END sw_ri[12]
  PIN sw_ri[13]
    DIRECTION INPUT ;
    USE SIGNAL ;
    PORT
      LAYER M4 ;
        RECT  172.716 146.592 172.8 146.616 ;
    END
  END sw_ri[13]
  PIN sw_ri[14]
    DIRECTION INPUT ;
    USE SIGNAL ;
    PORT
      LAYER M4 ;
        RECT  172.716 147.072 172.8 147.096 ;
    END
  END sw_ri[14]
  PIN sw_ri[15]
    DIRECTION INPUT ;
    USE SIGNAL ;
    PORT
      LAYER M4 ;
        RECT  172.716 147.456 172.8 147.48 ;
    END
  END sw_ri[15]
  PIN sw_ri[16]
    DIRECTION INPUT ;
    USE SIGNAL ;
    PORT
      LAYER M4 ;
        RECT  172.716 147.936 172.8 147.96 ;
    END
  END sw_ri[16]
  PIN sw_ri[17]
    DIRECTION INPUT ;
    USE SIGNAL ;
    PORT
      LAYER M4 ;
        RECT  172.716 148.32 172.8 148.344 ;
    END
  END sw_ri[17]
  PIN sw_ri[18]
    DIRECTION INPUT ;
    USE SIGNAL ;
    PORT
      LAYER M4 ;
        RECT  172.716 148.704 172.8 148.728 ;
    END
  END sw_ri[18]
  PIN sw_ri[19]
    DIRECTION INPUT ;
    USE SIGNAL ;
    PORT
      LAYER M4 ;
        RECT  172.716 149.184 172.8 149.208 ;
    END
  END sw_ri[19]
  PIN sw_ri[1]
    DIRECTION INPUT ;
    USE SIGNAL ;
    PORT
      LAYER M4 ;
        RECT  172.716 141.504 172.8 141.528 ;
    END
  END sw_ri[1]
  PIN sw_ri[20]
    DIRECTION INPUT ;
    USE SIGNAL ;
    PORT
      LAYER M4 ;
        RECT  172.716 149.568 172.8 149.592 ;
    END
  END sw_ri[20]
  PIN sw_ri[21]
    DIRECTION INPUT ;
    USE SIGNAL ;
    PORT
      LAYER M4 ;
        RECT  172.716 150.048 172.8 150.072 ;
    END
  END sw_ri[21]
  PIN sw_ri[22]
    DIRECTION INPUT ;
    USE SIGNAL ;
    PORT
      LAYER M4 ;
        RECT  172.716 150.432 172.8 150.456 ;
    END
  END sw_ri[22]
  PIN sw_ri[23]
    DIRECTION INPUT ;
    USE SIGNAL ;
    PORT
      LAYER M4 ;
        RECT  172.716 150.912 172.8 150.936 ;
    END
  END sw_ri[23]
  PIN sw_ri[24]
    DIRECTION INPUT ;
    USE SIGNAL ;
    PORT
      LAYER M4 ;
        RECT  172.716 151.296 172.8 151.32 ;
    END
  END sw_ri[24]
  PIN sw_ri[25]
    DIRECTION INPUT ;
    USE SIGNAL ;
    PORT
      LAYER M4 ;
        RECT  172.716 151.68 172.8 151.704 ;
    END
  END sw_ri[25]
  PIN sw_ri[26]
    DIRECTION INPUT ;
    USE SIGNAL ;
    PORT
      LAYER M4 ;
        RECT  172.716 152.16 172.8 152.184 ;
    END
  END sw_ri[26]
  PIN sw_ri[27]
    DIRECTION INPUT ;
    USE SIGNAL ;
    PORT
      LAYER M4 ;
        RECT  172.716 152.544 172.8 152.568 ;
    END
  END sw_ri[27]
  PIN sw_ri[28]
    DIRECTION INPUT ;
    USE SIGNAL ;
    PORT
      LAYER M4 ;
        RECT  172.716 153.024 172.8 153.048 ;
    END
  END sw_ri[28]
  PIN sw_ri[29]
    DIRECTION INPUT ;
    USE SIGNAL ;
    PORT
      LAYER M4 ;
        RECT  172.716 153.408 172.8 153.432 ;
    END
  END sw_ri[29]
  PIN sw_ri[2]
    DIRECTION INPUT ;
    USE SIGNAL ;
    PORT
      LAYER M4 ;
        RECT  172.716 141.984 172.8 142.008 ;
    END
  END sw_ri[2]
  PIN sw_ri[30]
    DIRECTION INPUT ;
    USE SIGNAL ;
    PORT
      LAYER M4 ;
        RECT  172.716 153.792 172.8 153.816 ;
    END
  END sw_ri[30]
  PIN sw_ri[31]
    DIRECTION INPUT ;
    USE SIGNAL ;
    PORT
      LAYER M4 ;
        RECT  172.716 154.272 172.8 154.296 ;
    END
  END sw_ri[31]
  PIN sw_ri[32]
    DIRECTION INPUT ;
    USE SIGNAL ;
    PORT
      LAYER M4 ;
        RECT  172.716 154.656 172.8 154.68 ;
    END
  END sw_ri[32]
  PIN sw_ri[33]
    DIRECTION INPUT ;
    USE SIGNAL ;
    PORT
      LAYER M4 ;
        RECT  172.716 155.136 172.8 155.16 ;
    END
  END sw_ri[33]
  PIN sw_ri[34]
    DIRECTION INPUT ;
    USE SIGNAL ;
    PORT
      LAYER M4 ;
        RECT  172.716 155.52 172.8 155.544 ;
    END
  END sw_ri[34]
  PIN sw_ri[35]
    DIRECTION INPUT ;
    USE SIGNAL ;
    PORT
      LAYER M4 ;
        RECT  172.716 156 172.8 156.024 ;
    END
  END sw_ri[35]
  PIN sw_ri[36]
    DIRECTION INPUT ;
    USE SIGNAL ;
    PORT
      LAYER M4 ;
        RECT  172.716 156.384 172.8 156.408 ;
    END
  END sw_ri[36]
  PIN sw_ri[37]
    DIRECTION INPUT ;
    USE SIGNAL ;
    PORT
      LAYER M4 ;
        RECT  172.716 156.768 172.8 156.792 ;
    END
  END sw_ri[37]
  PIN sw_ri[38]
    DIRECTION INPUT ;
    USE SIGNAL ;
    PORT
      LAYER M4 ;
        RECT  172.716 157.248 172.8 157.272 ;
    END
  END sw_ri[38]
  PIN sw_ri[39]
    DIRECTION INPUT ;
    USE SIGNAL ;
    PORT
      LAYER M4 ;
        RECT  172.716 157.632 172.8 157.656 ;
    END
  END sw_ri[39]
  PIN sw_ri[3]
    DIRECTION INPUT ;
    USE SIGNAL ;
    PORT
      LAYER M4 ;
        RECT  172.716 142.368 172.8 142.392 ;
    END
  END sw_ri[3]
  PIN sw_ri[40]
    DIRECTION INPUT ;
    USE SIGNAL ;
    PORT
      LAYER M4 ;
        RECT  172.716 158.112 172.8 158.136 ;
    END
  END sw_ri[40]
  PIN sw_ri[41]
    DIRECTION INPUT ;
    USE SIGNAL ;
    PORT
      LAYER M4 ;
        RECT  172.716 158.496 172.8 158.52 ;
    END
  END sw_ri[41]
  PIN sw_ri[42]
    DIRECTION INPUT ;
    USE SIGNAL ;
    PORT
      LAYER M4 ;
        RECT  172.716 158.88 172.8 158.904 ;
    END
  END sw_ri[42]
  PIN sw_ri[43]
    DIRECTION INPUT ;
    USE SIGNAL ;
    PORT
      LAYER M4 ;
        RECT  172.716 159.36 172.8 159.384 ;
    END
  END sw_ri[43]
  PIN sw_ri[44]
    DIRECTION INPUT ;
    USE SIGNAL ;
    PORT
      LAYER M4 ;
        RECT  172.716 159.744 172.8 159.768 ;
    END
  END sw_ri[44]
  PIN sw_ri[45]
    DIRECTION INPUT ;
    USE SIGNAL ;
    PORT
      LAYER M4 ;
        RECT  172.716 160.224 172.8 160.248 ;
    END
  END sw_ri[45]
  PIN sw_ri[46]
    DIRECTION INPUT ;
    USE SIGNAL ;
    PORT
      LAYER M4 ;
        RECT  172.716 160.608 172.8 160.632 ;
    END
  END sw_ri[46]
  PIN sw_ri[47]
    DIRECTION INPUT ;
    USE SIGNAL ;
    PORT
      LAYER M4 ;
        RECT  172.716 161.088 172.8 161.112 ;
    END
  END sw_ri[47]
  PIN sw_ri[48]
    DIRECTION INPUT ;
    USE SIGNAL ;
    PORT
      LAYER M4 ;
        RECT  172.716 161.472 172.8 161.496 ;
    END
  END sw_ri[48]
  PIN sw_ri[49]
    DIRECTION INPUT ;
    USE SIGNAL ;
    PORT
      LAYER M4 ;
        RECT  172.716 161.856 172.8 161.88 ;
    END
  END sw_ri[49]
  PIN sw_ri[4]
    DIRECTION INPUT ;
    USE SIGNAL ;
    PORT
      LAYER M4 ;
        RECT  172.716 142.848 172.8 142.872 ;
    END
  END sw_ri[4]
  PIN sw_ri[50]
    DIRECTION INPUT ;
    USE SIGNAL ;
    PORT
      LAYER M4 ;
        RECT  172.716 162.336 172.8 162.36 ;
    END
  END sw_ri[50]
  PIN sw_ri[51]
    DIRECTION INPUT ;
    USE SIGNAL ;
    PORT
      LAYER M4 ;
        RECT  172.716 162.72 172.8 162.744 ;
    END
  END sw_ri[51]
  PIN sw_ri[52]
    DIRECTION INPUT ;
    USE SIGNAL ;
    PORT
      LAYER M4 ;
        RECT  172.716 163.2 172.8 163.224 ;
    END
  END sw_ri[52]
  PIN sw_ri[53]
    DIRECTION INPUT ;
    USE SIGNAL ;
    PORT
      LAYER M4 ;
        RECT  172.716 163.584 172.8 163.608 ;
    END
  END sw_ri[53]
  PIN sw_ri[54]
    DIRECTION INPUT ;
    USE SIGNAL ;
    PORT
      LAYER M4 ;
        RECT  172.716 163.968 172.8 163.992 ;
    END
  END sw_ri[54]
  PIN sw_ri[55]
    DIRECTION INPUT ;
    USE SIGNAL ;
    PORT
      LAYER M4 ;
        RECT  172.716 164.448 172.8 164.472 ;
    END
  END sw_ri[55]
  PIN sw_ri[56]
    DIRECTION INPUT ;
    USE SIGNAL ;
    PORT
      LAYER M4 ;
        RECT  172.716 164.832 172.8 164.856 ;
    END
  END sw_ri[56]
  PIN sw_ri[57]
    DIRECTION INPUT ;
    USE SIGNAL ;
    PORT
      LAYER M4 ;
        RECT  172.716 165.312 172.8 165.336 ;
    END
  END sw_ri[57]
  PIN sw_ri[58]
    DIRECTION INPUT ;
    USE SIGNAL ;
    PORT
      LAYER M4 ;
        RECT  172.716 165.696 172.8 165.72 ;
    END
  END sw_ri[58]
  PIN sw_ri[59]
    DIRECTION INPUT ;
    USE SIGNAL ;
    PORT
      LAYER M4 ;
        RECT  172.716 166.176 172.8 166.2 ;
    END
  END sw_ri[59]
  PIN sw_ri[5]
    DIRECTION INPUT ;
    USE SIGNAL ;
    PORT
      LAYER M4 ;
        RECT  172.716 143.232 172.8 143.256 ;
    END
  END sw_ri[5]
  PIN sw_ri[60]
    DIRECTION INPUT ;
    USE SIGNAL ;
    PORT
      LAYER M4 ;
        RECT  172.716 166.56 172.8 166.584 ;
    END
  END sw_ri[60]
  PIN sw_ri[61]
    DIRECTION INPUT ;
    USE SIGNAL ;
    PORT
      LAYER M4 ;
        RECT  172.716 166.944 172.8 166.968 ;
    END
  END sw_ri[61]
  PIN sw_ri[62]
    DIRECTION INPUT ;
    USE SIGNAL ;
    PORT
      LAYER M4 ;
        RECT  172.716 167.424 172.8 167.448 ;
    END
  END sw_ri[62]
  PIN sw_ri[63]
    DIRECTION INPUT ;
    USE SIGNAL ;
    PORT
      LAYER M4 ;
        RECT  172.716 167.808 172.8 167.832 ;
    END
  END sw_ri[63]
  PIN sw_ri[6]
    DIRECTION INPUT ;
    USE SIGNAL ;
    PORT
      LAYER M4 ;
        RECT  172.716 143.616 172.8 143.64 ;
    END
  END sw_ri[6]
  PIN sw_ri[7]
    DIRECTION INPUT ;
    USE SIGNAL ;
    PORT
      LAYER M4 ;
        RECT  172.716 144.096 172.8 144.12 ;
    END
  END sw_ri[7]
  PIN sw_ri[8]
    DIRECTION INPUT ;
    USE SIGNAL ;
    PORT
      LAYER M4 ;
        RECT  172.716 144.48 172.8 144.504 ;
    END
  END sw_ri[8]
  PIN sw_ri[9]
    DIRECTION INPUT ;
    USE SIGNAL ;
    PORT
      LAYER M4 ;
        RECT  172.716 144.96 172.8 144.984 ;
    END
  END sw_ri[9]
  PIN sw_v
    DIRECTION OUTPUT ;
    USE SIGNAL ;
    PORT
      LAYER M4 ;
        RECT  172.716 4.512 172.8 4.536 ;
    END
  END sw_v
  PIN sw_vi
    DIRECTION INPUT ;
    USE SIGNAL ;
    PORT
      LAYER M4 ;
        RECT  172.716 140.64 172.8 140.664 ;
    END
  END sw_vi
  PIN sw_w[0]
    DIRECTION OUTPUT ;
    USE SIGNAL ;
    PORT
      LAYER M4 ;
        RECT  172.716 113.568 172.8 113.592 ;
    END
  END sw_w[0]
  PIN sw_w[10]
    DIRECTION OUTPUT ;
    USE SIGNAL ;
    PORT
      LAYER M4 ;
        RECT  172.716 117.792 172.8 117.816 ;
    END
  END sw_w[10]
  PIN sw_w[11]
    DIRECTION OUTPUT ;
    USE SIGNAL ;
    PORT
      LAYER M4 ;
        RECT  172.716 118.176 172.8 118.2 ;
    END
  END sw_w[11]
  PIN sw_w[12]
    DIRECTION OUTPUT ;
    USE SIGNAL ;
    PORT
      LAYER M4 ;
        RECT  172.716 118.656 172.8 118.68 ;
    END
  END sw_w[12]
  PIN sw_w[13]
    DIRECTION OUTPUT ;
    USE SIGNAL ;
    PORT
      LAYER M4 ;
        RECT  172.716 119.04 172.8 119.064 ;
    END
  END sw_w[13]
  PIN sw_w[14]
    DIRECTION OUTPUT ;
    USE SIGNAL ;
    PORT
      LAYER M4 ;
        RECT  172.716 119.52 172.8 119.544 ;
    END
  END sw_w[14]
  PIN sw_w[15]
    DIRECTION OUTPUT ;
    USE SIGNAL ;
    PORT
      LAYER M4 ;
        RECT  172.716 119.904 172.8 119.928 ;
    END
  END sw_w[15]
  PIN sw_w[16]
    DIRECTION OUTPUT ;
    USE SIGNAL ;
    PORT
      LAYER M4 ;
        RECT  172.716 120.288 172.8 120.312 ;
    END
  END sw_w[16]
  PIN sw_w[17]
    DIRECTION OUTPUT ;
    USE SIGNAL ;
    PORT
      LAYER M4 ;
        RECT  172.716 120.768 172.8 120.792 ;
    END
  END sw_w[17]
  PIN sw_w[18]
    DIRECTION OUTPUT ;
    USE SIGNAL ;
    PORT
      LAYER M4 ;
        RECT  172.716 121.152 172.8 121.176 ;
    END
  END sw_w[18]
  PIN sw_w[19]
    DIRECTION OUTPUT ;
    USE SIGNAL ;
    PORT
      LAYER M4 ;
        RECT  172.716 121.632 172.8 121.656 ;
    END
  END sw_w[19]
  PIN sw_w[1]
    DIRECTION OUTPUT ;
    USE SIGNAL ;
    PORT
      LAYER M4 ;
        RECT  172.716 113.952 172.8 113.976 ;
    END
  END sw_w[1]
  PIN sw_w[20]
    DIRECTION OUTPUT ;
    USE SIGNAL ;
    PORT
      LAYER M4 ;
        RECT  172.716 122.016 172.8 122.04 ;
    END
  END sw_w[20]
  PIN sw_w[21]
    DIRECTION OUTPUT ;
    USE SIGNAL ;
    PORT
      LAYER M4 ;
        RECT  172.716 122.4 172.8 122.424 ;
    END
  END sw_w[21]
  PIN sw_w[22]
    DIRECTION OUTPUT ;
    USE SIGNAL ;
    PORT
      LAYER M4 ;
        RECT  172.716 122.88 172.8 122.904 ;
    END
  END sw_w[22]
  PIN sw_w[23]
    DIRECTION OUTPUT ;
    USE SIGNAL ;
    PORT
      LAYER M4 ;
        RECT  172.716 123.264 172.8 123.288 ;
    END
  END sw_w[23]
  PIN sw_w[24]
    DIRECTION OUTPUT ;
    USE SIGNAL ;
    PORT
      LAYER M4 ;
        RECT  172.716 123.744 172.8 123.768 ;
    END
  END sw_w[24]
  PIN sw_w[25]
    DIRECTION OUTPUT ;
    USE SIGNAL ;
    PORT
      LAYER M4 ;
        RECT  172.716 124.128 172.8 124.152 ;
    END
  END sw_w[25]
  PIN sw_w[26]
    DIRECTION OUTPUT ;
    USE SIGNAL ;
    PORT
      LAYER M4 ;
        RECT  172.716 124.608 172.8 124.632 ;
    END
  END sw_w[26]
  PIN sw_w[27]
    DIRECTION OUTPUT ;
    USE SIGNAL ;
    PORT
      LAYER M4 ;
        RECT  172.716 124.992 172.8 125.016 ;
    END
  END sw_w[27]
  PIN sw_w[28]
    DIRECTION OUTPUT ;
    USE SIGNAL ;
    PORT
      LAYER M4 ;
        RECT  172.716 125.376 172.8 125.4 ;
    END
  END sw_w[28]
  PIN sw_w[29]
    DIRECTION OUTPUT ;
    USE SIGNAL ;
    PORT
      LAYER M4 ;
        RECT  172.716 125.856 172.8 125.88 ;
    END
  END sw_w[29]
  PIN sw_w[2]
    DIRECTION OUTPUT ;
    USE SIGNAL ;
    PORT
      LAYER M4 ;
        RECT  172.716 114.432 172.8 114.456 ;
    END
  END sw_w[2]
  PIN sw_w[30]
    DIRECTION OUTPUT ;
    USE SIGNAL ;
    PORT
      LAYER M4 ;
        RECT  172.716 126.24 172.8 126.264 ;
    END
  END sw_w[30]
  PIN sw_w[31]
    DIRECTION OUTPUT ;
    USE SIGNAL ;
    PORT
      LAYER M4 ;
        RECT  172.716 126.72 172.8 126.744 ;
    END
  END sw_w[31]
  PIN sw_w[3]
    DIRECTION OUTPUT ;
    USE SIGNAL ;
    PORT
      LAYER M4 ;
        RECT  172.716 114.816 172.8 114.84 ;
    END
  END sw_w[3]
  PIN sw_w[4]
    DIRECTION OUTPUT ;
    USE SIGNAL ;
    PORT
      LAYER M4 ;
        RECT  172.716 115.2 172.8 115.224 ;
    END
  END sw_w[4]
  PIN sw_w[5]
    DIRECTION OUTPUT ;
    USE SIGNAL ;
    PORT
      LAYER M4 ;
        RECT  172.716 115.68 172.8 115.704 ;
    END
  END sw_w[5]
  PIN sw_w[6]
    DIRECTION OUTPUT ;
    USE SIGNAL ;
    PORT
      LAYER M4 ;
        RECT  172.716 116.064 172.8 116.088 ;
    END
  END sw_w[6]
  PIN sw_w[7]
    DIRECTION OUTPUT ;
    USE SIGNAL ;
    PORT
      LAYER M4 ;
        RECT  172.716 116.544 172.8 116.568 ;
    END
  END sw_w[7]
  PIN sw_w[8]
    DIRECTION OUTPUT ;
    USE SIGNAL ;
    PORT
      LAYER M4 ;
        RECT  172.716 116.928 172.8 116.952 ;
    END
  END sw_w[8]
  PIN sw_w[9]
    DIRECTION OUTPUT ;
    USE SIGNAL ;
    PORT
      LAYER M4 ;
        RECT  172.716 117.312 172.8 117.336 ;
    END
  END sw_w[9]
  PIN u[0]
    DIRECTION OUTPUT ;
    USE SIGNAL ;
    PORT
      LAYER M4 ;
        RECT  0 114.72 0.084 114.744 ;
    END
  END u[0]
  PIN u[100]
    DIRECTION OUTPUT ;
    USE SIGNAL ;
    PORT
      LAYER M4 ;
        RECT  0 134.88 0.084 134.904 ;
    END
  END u[100]
  PIN u[101]
    DIRECTION OUTPUT ;
    USE SIGNAL ;
    PORT
      LAYER M4 ;
        RECT  0 135.072 0.084 135.096 ;
    END
  END u[101]
  PIN u[102]
    DIRECTION OUTPUT ;
    USE SIGNAL ;
    PORT
      LAYER M4 ;
        RECT  0 135.264 0.084 135.288 ;
    END
  END u[102]
  PIN u[103]
    DIRECTION OUTPUT ;
    USE SIGNAL ;
    PORT
      LAYER M4 ;
        RECT  0 135.456 0.084 135.48 ;
    END
  END u[103]
  PIN u[104]
    DIRECTION OUTPUT ;
    USE SIGNAL ;
    PORT
      LAYER M4 ;
        RECT  0 135.744 0.084 135.768 ;
    END
  END u[104]
  PIN u[105]
    DIRECTION OUTPUT ;
    USE SIGNAL ;
    PORT
      LAYER M4 ;
        RECT  0 135.936 0.084 135.96 ;
    END
  END u[105]
  PIN u[106]
    DIRECTION OUTPUT ;
    USE SIGNAL ;
    PORT
      LAYER M4 ;
        RECT  0 136.128 0.084 136.152 ;
    END
  END u[106]
  PIN u[107]
    DIRECTION OUTPUT ;
    USE SIGNAL ;
    PORT
      LAYER M4 ;
        RECT  0 136.32 0.084 136.344 ;
    END
  END u[107]
  PIN u[108]
    DIRECTION OUTPUT ;
    USE SIGNAL ;
    PORT
      LAYER M4 ;
        RECT  0 136.512 0.084 136.536 ;
    END
  END u[108]
  PIN u[109]
    DIRECTION OUTPUT ;
    USE SIGNAL ;
    PORT
      LAYER M4 ;
        RECT  0 136.704 0.084 136.728 ;
    END
  END u[109]
  PIN u[10]
    DIRECTION OUTPUT ;
    USE SIGNAL ;
    PORT
      LAYER M4 ;
        RECT  0 116.736 0.084 116.76 ;
    END
  END u[10]
  PIN u[110]
    DIRECTION OUTPUT ;
    USE SIGNAL ;
    PORT
      LAYER M4 ;
        RECT  0 136.896 0.084 136.92 ;
    END
  END u[110]
  PIN u[111]
    DIRECTION OUTPUT ;
    USE SIGNAL ;
    PORT
      LAYER M4 ;
        RECT  0 137.088 0.084 137.112 ;
    END
  END u[111]
  PIN u[112]
    DIRECTION OUTPUT ;
    USE SIGNAL ;
    PORT
      LAYER M4 ;
        RECT  0 137.28 0.084 137.304 ;
    END
  END u[112]
  PIN u[113]
    DIRECTION OUTPUT ;
    USE SIGNAL ;
    PORT
      LAYER M4 ;
        RECT  0 137.472 0.084 137.496 ;
    END
  END u[113]
  PIN u[114]
    DIRECTION OUTPUT ;
    USE SIGNAL ;
    PORT
      LAYER M4 ;
        RECT  0 137.76 0.084 137.784 ;
    END
  END u[114]
  PIN u[115]
    DIRECTION OUTPUT ;
    USE SIGNAL ;
    PORT
      LAYER M4 ;
        RECT  0 137.952 0.084 137.976 ;
    END
  END u[115]
  PIN u[116]
    DIRECTION OUTPUT ;
    USE SIGNAL ;
    PORT
      LAYER M4 ;
        RECT  0 138.144 0.084 138.168 ;
    END
  END u[116]
  PIN u[117]
    DIRECTION OUTPUT ;
    USE SIGNAL ;
    PORT
      LAYER M4 ;
        RECT  0 138.336 0.084 138.36 ;
    END
  END u[117]
  PIN u[118]
    DIRECTION OUTPUT ;
    USE SIGNAL ;
    PORT
      LAYER M4 ;
        RECT  0 138.528 0.084 138.552 ;
    END
  END u[118]
  PIN u[119]
    DIRECTION OUTPUT ;
    USE SIGNAL ;
    PORT
      LAYER M4 ;
        RECT  0 138.72 0.084 138.744 ;
    END
  END u[119]
  PIN u[11]
    DIRECTION OUTPUT ;
    USE SIGNAL ;
    PORT
      LAYER M4 ;
        RECT  0 116.928 0.084 116.952 ;
    END
  END u[11]
  PIN u[120]
    DIRECTION OUTPUT ;
    USE SIGNAL ;
    PORT
      LAYER M4 ;
        RECT  0 138.912 0.084 138.936 ;
    END
  END u[120]
  PIN u[121]
    DIRECTION OUTPUT ;
    USE SIGNAL ;
    PORT
      LAYER M4 ;
        RECT  0 139.104 0.084 139.128 ;
    END
  END u[121]
  PIN u[122]
    DIRECTION OUTPUT ;
    USE SIGNAL ;
    PORT
      LAYER M4 ;
        RECT  0 139.296 0.084 139.32 ;
    END
  END u[122]
  PIN u[123]
    DIRECTION OUTPUT ;
    USE SIGNAL ;
    PORT
      LAYER M4 ;
        RECT  0 139.488 0.084 139.512 ;
    END
  END u[123]
  PIN u[124]
    DIRECTION OUTPUT ;
    USE SIGNAL ;
    PORT
      LAYER M4 ;
        RECT  0 139.776 0.084 139.8 ;
    END
  END u[124]
  PIN u[125]
    DIRECTION OUTPUT ;
    USE SIGNAL ;
    PORT
      LAYER M4 ;
        RECT  0 139.968 0.084 139.992 ;
    END
  END u[125]
  PIN u[126]
    DIRECTION OUTPUT ;
    USE SIGNAL ;
    PORT
      LAYER M4 ;
        RECT  0 140.16 0.084 140.184 ;
    END
  END u[126]
  PIN u[127]
    DIRECTION OUTPUT ;
    USE SIGNAL ;
    PORT
      LAYER M4 ;
        RECT  0 140.352 0.084 140.376 ;
    END
  END u[127]
  PIN u[128]
    DIRECTION OUTPUT ;
    USE SIGNAL ;
    PORT
      LAYER M4 ;
        RECT  0 140.544 0.084 140.568 ;
    END
  END u[128]
  PIN u[129]
    DIRECTION OUTPUT ;
    USE SIGNAL ;
    PORT
      LAYER M4 ;
        RECT  0 140.736 0.084 140.76 ;
    END
  END u[129]
  PIN u[12]
    DIRECTION OUTPUT ;
    USE SIGNAL ;
    PORT
      LAYER M4 ;
        RECT  0 117.12 0.084 117.144 ;
    END
  END u[12]
  PIN u[130]
    DIRECTION OUTPUT ;
    USE SIGNAL ;
    PORT
      LAYER M4 ;
        RECT  0 140.928 0.084 140.952 ;
    END
  END u[130]
  PIN u[131]
    DIRECTION OUTPUT ;
    USE SIGNAL ;
    PORT
      LAYER M4 ;
        RECT  0 141.12 0.084 141.144 ;
    END
  END u[131]
  PIN u[132]
    DIRECTION OUTPUT ;
    USE SIGNAL ;
    PORT
      LAYER M4 ;
        RECT  0 141.312 0.084 141.336 ;
    END
  END u[132]
  PIN u[133]
    DIRECTION OUTPUT ;
    USE SIGNAL ;
    PORT
      LAYER M4 ;
        RECT  0 141.504 0.084 141.528 ;
    END
  END u[133]
  PIN u[134]
    DIRECTION OUTPUT ;
    USE SIGNAL ;
    PORT
      LAYER M4 ;
        RECT  0 141.792 0.084 141.816 ;
    END
  END u[134]
  PIN u[135]
    DIRECTION OUTPUT ;
    USE SIGNAL ;
    PORT
      LAYER M4 ;
        RECT  0 141.984 0.084 142.008 ;
    END
  END u[135]
  PIN u[136]
    DIRECTION OUTPUT ;
    USE SIGNAL ;
    PORT
      LAYER M4 ;
        RECT  0 142.176 0.084 142.2 ;
    END
  END u[136]
  PIN u[137]
    DIRECTION OUTPUT ;
    USE SIGNAL ;
    PORT
      LAYER M4 ;
        RECT  0 142.368 0.084 142.392 ;
    END
  END u[137]
  PIN u[138]
    DIRECTION OUTPUT ;
    USE SIGNAL ;
    PORT
      LAYER M4 ;
        RECT  0 142.56 0.084 142.584 ;
    END
  END u[138]
  PIN u[139]
    DIRECTION OUTPUT ;
    USE SIGNAL ;
    PORT
      LAYER M4 ;
        RECT  0 142.752 0.084 142.776 ;
    END
  END u[139]
  PIN u[13]
    DIRECTION OUTPUT ;
    USE SIGNAL ;
    PORT
      LAYER M4 ;
        RECT  0 117.312 0.084 117.336 ;
    END
  END u[13]
  PIN u[140]
    DIRECTION OUTPUT ;
    USE SIGNAL ;
    PORT
      LAYER M4 ;
        RECT  0 142.944 0.084 142.968 ;
    END
  END u[140]
  PIN u[141]
    DIRECTION OUTPUT ;
    USE SIGNAL ;
    PORT
      LAYER M4 ;
        RECT  0 143.136 0.084 143.16 ;
    END
  END u[141]
  PIN u[142]
    DIRECTION OUTPUT ;
    USE SIGNAL ;
    PORT
      LAYER M4 ;
        RECT  0 143.328 0.084 143.352 ;
    END
  END u[142]
  PIN u[143]
    DIRECTION OUTPUT ;
    USE SIGNAL ;
    PORT
      LAYER M4 ;
        RECT  0 143.52 0.084 143.544 ;
    END
  END u[143]
  PIN u[144]
    DIRECTION OUTPUT ;
    USE SIGNAL ;
    PORT
      LAYER M4 ;
        RECT  0 143.808 0.084 143.832 ;
    END
  END u[144]
  PIN u[145]
    DIRECTION OUTPUT ;
    USE SIGNAL ;
    PORT
      LAYER M4 ;
        RECT  0 144 0.084 144.024 ;
    END
  END u[145]
  PIN u[146]
    DIRECTION OUTPUT ;
    USE SIGNAL ;
    PORT
      LAYER M4 ;
        RECT  0 144.192 0.084 144.216 ;
    END
  END u[146]
  PIN u[147]
    DIRECTION OUTPUT ;
    USE SIGNAL ;
    PORT
      LAYER M4 ;
        RECT  0 144.384 0.084 144.408 ;
    END
  END u[147]
  PIN u[148]
    DIRECTION OUTPUT ;
    USE SIGNAL ;
    PORT
      LAYER M4 ;
        RECT  0 144.576 0.084 144.6 ;
    END
  END u[148]
  PIN u[149]
    DIRECTION OUTPUT ;
    USE SIGNAL ;
    PORT
      LAYER M4 ;
        RECT  0 144.768 0.084 144.792 ;
    END
  END u[149]
  PIN u[14]
    DIRECTION OUTPUT ;
    USE SIGNAL ;
    PORT
      LAYER M4 ;
        RECT  0 117.504 0.084 117.528 ;
    END
  END u[14]
  PIN u[150]
    DIRECTION OUTPUT ;
    USE SIGNAL ;
    PORT
      LAYER M4 ;
        RECT  0 144.96 0.084 144.984 ;
    END
  END u[150]
  PIN u[151]
    DIRECTION OUTPUT ;
    USE SIGNAL ;
    PORT
      LAYER M4 ;
        RECT  0 145.152 0.084 145.176 ;
    END
  END u[151]
  PIN u[152]
    DIRECTION OUTPUT ;
    USE SIGNAL ;
    PORT
      LAYER M4 ;
        RECT  0 145.344 0.084 145.368 ;
    END
  END u[152]
  PIN u[153]
    DIRECTION OUTPUT ;
    USE SIGNAL ;
    PORT
      LAYER M4 ;
        RECT  0 145.536 0.084 145.56 ;
    END
  END u[153]
  PIN u[154]
    DIRECTION OUTPUT ;
    USE SIGNAL ;
    PORT
      LAYER M4 ;
        RECT  0 145.824 0.084 145.848 ;
    END
  END u[154]
  PIN u[155]
    DIRECTION OUTPUT ;
    USE SIGNAL ;
    PORT
      LAYER M4 ;
        RECT  0 146.016 0.084 146.04 ;
    END
  END u[155]
  PIN u[156]
    DIRECTION OUTPUT ;
    USE SIGNAL ;
    PORT
      LAYER M4 ;
        RECT  0 146.208 0.084 146.232 ;
    END
  END u[156]
  PIN u[157]
    DIRECTION OUTPUT ;
    USE SIGNAL ;
    PORT
      LAYER M4 ;
        RECT  0 146.4 0.084 146.424 ;
    END
  END u[157]
  PIN u[158]
    DIRECTION OUTPUT ;
    USE SIGNAL ;
    PORT
      LAYER M4 ;
        RECT  0 146.592 0.084 146.616 ;
    END
  END u[158]
  PIN u[159]
    DIRECTION OUTPUT ;
    USE SIGNAL ;
    PORT
      LAYER M4 ;
        RECT  0 146.784 0.084 146.808 ;
    END
  END u[159]
  PIN u[15]
    DIRECTION OUTPUT ;
    USE SIGNAL ;
    PORT
      LAYER M4 ;
        RECT  0 117.792 0.084 117.816 ;
    END
  END u[15]
  PIN u[160]
    DIRECTION OUTPUT ;
    USE SIGNAL ;
    PORT
      LAYER M4 ;
        RECT  0 146.976 0.084 147 ;
    END
  END u[160]
  PIN u[161]
    DIRECTION OUTPUT ;
    USE SIGNAL ;
    PORT
      LAYER M4 ;
        RECT  0 147.168 0.084 147.192 ;
    END
  END u[161]
  PIN u[162]
    DIRECTION OUTPUT ;
    USE SIGNAL ;
    PORT
      LAYER M4 ;
        RECT  0 147.36 0.084 147.384 ;
    END
  END u[162]
  PIN u[163]
    DIRECTION OUTPUT ;
    USE SIGNAL ;
    PORT
      LAYER M4 ;
        RECT  0 147.552 0.084 147.576 ;
    END
  END u[163]
  PIN u[164]
    DIRECTION OUTPUT ;
    USE SIGNAL ;
    PORT
      LAYER M4 ;
        RECT  0 147.84 0.084 147.864 ;
    END
  END u[164]
  PIN u[165]
    DIRECTION OUTPUT ;
    USE SIGNAL ;
    PORT
      LAYER M4 ;
        RECT  0 148.032 0.084 148.056 ;
    END
  END u[165]
  PIN u[166]
    DIRECTION OUTPUT ;
    USE SIGNAL ;
    PORT
      LAYER M4 ;
        RECT  0 148.224 0.084 148.248 ;
    END
  END u[166]
  PIN u[167]
    DIRECTION OUTPUT ;
    USE SIGNAL ;
    PORT
      LAYER M4 ;
        RECT  0 148.416 0.084 148.44 ;
    END
  END u[167]
  PIN u[168]
    DIRECTION OUTPUT ;
    USE SIGNAL ;
    PORT
      LAYER M4 ;
        RECT  0 148.608 0.084 148.632 ;
    END
  END u[168]
  PIN u[169]
    DIRECTION OUTPUT ;
    USE SIGNAL ;
    PORT
      LAYER M4 ;
        RECT  0 148.8 0.084 148.824 ;
    END
  END u[169]
  PIN u[16]
    DIRECTION OUTPUT ;
    USE SIGNAL ;
    PORT
      LAYER M4 ;
        RECT  0 117.984 0.084 118.008 ;
    END
  END u[16]
  PIN u[170]
    DIRECTION OUTPUT ;
    USE SIGNAL ;
    PORT
      LAYER M4 ;
        RECT  0 148.992 0.084 149.016 ;
    END
  END u[170]
  PIN u[171]
    DIRECTION OUTPUT ;
    USE SIGNAL ;
    PORT
      LAYER M4 ;
        RECT  0 149.184 0.084 149.208 ;
    END
  END u[171]
  PIN u[172]
    DIRECTION OUTPUT ;
    USE SIGNAL ;
    PORT
      LAYER M4 ;
        RECT  0 149.376 0.084 149.4 ;
    END
  END u[172]
  PIN u[173]
    DIRECTION OUTPUT ;
    USE SIGNAL ;
    PORT
      LAYER M4 ;
        RECT  0 149.568 0.084 149.592 ;
    END
  END u[173]
  PIN u[174]
    DIRECTION OUTPUT ;
    USE SIGNAL ;
    PORT
      LAYER M4 ;
        RECT  0 149.856 0.084 149.88 ;
    END
  END u[174]
  PIN u[175]
    DIRECTION OUTPUT ;
    USE SIGNAL ;
    PORT
      LAYER M4 ;
        RECT  0 150.048 0.084 150.072 ;
    END
  END u[175]
  PIN u[176]
    DIRECTION OUTPUT ;
    USE SIGNAL ;
    PORT
      LAYER M4 ;
        RECT  0 150.24 0.084 150.264 ;
    END
  END u[176]
  PIN u[177]
    DIRECTION OUTPUT ;
    USE SIGNAL ;
    PORT
      LAYER M4 ;
        RECT  0 150.432 0.084 150.456 ;
    END
  END u[177]
  PIN u[178]
    DIRECTION OUTPUT ;
    USE SIGNAL ;
    PORT
      LAYER M4 ;
        RECT  0 150.624 0.084 150.648 ;
    END
  END u[178]
  PIN u[179]
    DIRECTION OUTPUT ;
    USE SIGNAL ;
    PORT
      LAYER M4 ;
        RECT  0 150.816 0.084 150.84 ;
    END
  END u[179]
  PIN u[17]
    DIRECTION OUTPUT ;
    USE SIGNAL ;
    PORT
      LAYER M4 ;
        RECT  0 118.176 0.084 118.2 ;
    END
  END u[17]
  PIN u[180]
    DIRECTION OUTPUT ;
    USE SIGNAL ;
    PORT
      LAYER M4 ;
        RECT  0 151.008 0.084 151.032 ;
    END
  END u[180]
  PIN u[181]
    DIRECTION OUTPUT ;
    USE SIGNAL ;
    PORT
      LAYER M4 ;
        RECT  0 151.2 0.084 151.224 ;
    END
  END u[181]
  PIN u[182]
    DIRECTION OUTPUT ;
    USE SIGNAL ;
    PORT
      LAYER M4 ;
        RECT  0 151.392 0.084 151.416 ;
    END
  END u[182]
  PIN u[183]
    DIRECTION OUTPUT ;
    USE SIGNAL ;
    PORT
      LAYER M4 ;
        RECT  0 151.584 0.084 151.608 ;
    END
  END u[183]
  PIN u[184]
    DIRECTION OUTPUT ;
    USE SIGNAL ;
    PORT
      LAYER M4 ;
        RECT  0 151.872 0.084 151.896 ;
    END
  END u[184]
  PIN u[185]
    DIRECTION OUTPUT ;
    USE SIGNAL ;
    PORT
      LAYER M4 ;
        RECT  0 152.064 0.084 152.088 ;
    END
  END u[185]
  PIN u[186]
    DIRECTION OUTPUT ;
    USE SIGNAL ;
    PORT
      LAYER M4 ;
        RECT  0 152.256 0.084 152.28 ;
    END
  END u[186]
  PIN u[187]
    DIRECTION OUTPUT ;
    USE SIGNAL ;
    PORT
      LAYER M4 ;
        RECT  0 152.448 0.084 152.472 ;
    END
  END u[187]
  PIN u[188]
    DIRECTION OUTPUT ;
    USE SIGNAL ;
    PORT
      LAYER M4 ;
        RECT  0 152.64 0.084 152.664 ;
    END
  END u[188]
  PIN u[189]
    DIRECTION OUTPUT ;
    USE SIGNAL ;
    PORT
      LAYER M4 ;
        RECT  0 152.832 0.084 152.856 ;
    END
  END u[189]
  PIN u[18]
    DIRECTION OUTPUT ;
    USE SIGNAL ;
    PORT
      LAYER M4 ;
        RECT  0 118.368 0.084 118.392 ;
    END
  END u[18]
  PIN u[190]
    DIRECTION OUTPUT ;
    USE SIGNAL ;
    PORT
      LAYER M4 ;
        RECT  0 153.024 0.084 153.048 ;
    END
  END u[190]
  PIN u[191]
    DIRECTION OUTPUT ;
    USE SIGNAL ;
    PORT
      LAYER M4 ;
        RECT  0 153.216 0.084 153.24 ;
    END
  END u[191]
  PIN u[192]
    DIRECTION OUTPUT ;
    USE SIGNAL ;
    PORT
      LAYER M4 ;
        RECT  0 153.408 0.084 153.432 ;
    END
  END u[192]
  PIN u[193]
    DIRECTION OUTPUT ;
    USE SIGNAL ;
    PORT
      LAYER M4 ;
        RECT  0 153.6 0.084 153.624 ;
    END
  END u[193]
  PIN u[194]
    DIRECTION OUTPUT ;
    USE SIGNAL ;
    PORT
      LAYER M4 ;
        RECT  0 153.888 0.084 153.912 ;
    END
  END u[194]
  PIN u[195]
    DIRECTION OUTPUT ;
    USE SIGNAL ;
    PORT
      LAYER M4 ;
        RECT  0 154.08 0.084 154.104 ;
    END
  END u[195]
  PIN u[196]
    DIRECTION OUTPUT ;
    USE SIGNAL ;
    PORT
      LAYER M4 ;
        RECT  0 154.272 0.084 154.296 ;
    END
  END u[196]
  PIN u[197]
    DIRECTION OUTPUT ;
    USE SIGNAL ;
    PORT
      LAYER M4 ;
        RECT  0 154.464 0.084 154.488 ;
    END
  END u[197]
  PIN u[198]
    DIRECTION OUTPUT ;
    USE SIGNAL ;
    PORT
      LAYER M4 ;
        RECT  0 154.656 0.084 154.68 ;
    END
  END u[198]
  PIN u[199]
    DIRECTION OUTPUT ;
    USE SIGNAL ;
    PORT
      LAYER M4 ;
        RECT  0 154.848 0.084 154.872 ;
    END
  END u[199]
  PIN u[19]
    DIRECTION OUTPUT ;
    USE SIGNAL ;
    PORT
      LAYER M4 ;
        RECT  0 118.56 0.084 118.584 ;
    END
  END u[19]
  PIN u[1]
    DIRECTION OUTPUT ;
    USE SIGNAL ;
    PORT
      LAYER M4 ;
        RECT  0 114.912 0.084 114.936 ;
    END
  END u[1]
  PIN u[200]
    DIRECTION OUTPUT ;
    USE SIGNAL ;
    PORT
      LAYER M4 ;
        RECT  0 155.04 0.084 155.064 ;
    END
  END u[200]
  PIN u[201]
    DIRECTION OUTPUT ;
    USE SIGNAL ;
    PORT
      LAYER M4 ;
        RECT  0 155.232 0.084 155.256 ;
    END
  END u[201]
  PIN u[202]
    DIRECTION OUTPUT ;
    USE SIGNAL ;
    PORT
      LAYER M4 ;
        RECT  0 155.424 0.084 155.448 ;
    END
  END u[202]
  PIN u[203]
    DIRECTION OUTPUT ;
    USE SIGNAL ;
    PORT
      LAYER M4 ;
        RECT  0 155.616 0.084 155.64 ;
    END
  END u[203]
  PIN u[204]
    DIRECTION OUTPUT ;
    USE SIGNAL ;
    PORT
      LAYER M4 ;
        RECT  0 155.904 0.084 155.928 ;
    END
  END u[204]
  PIN u[205]
    DIRECTION OUTPUT ;
    USE SIGNAL ;
    PORT
      LAYER M4 ;
        RECT  0 156.096 0.084 156.12 ;
    END
  END u[205]
  PIN u[206]
    DIRECTION OUTPUT ;
    USE SIGNAL ;
    PORT
      LAYER M4 ;
        RECT  0 156.288 0.084 156.312 ;
    END
  END u[206]
  PIN u[207]
    DIRECTION OUTPUT ;
    USE SIGNAL ;
    PORT
      LAYER M4 ;
        RECT  0 156.48 0.084 156.504 ;
    END
  END u[207]
  PIN u[208]
    DIRECTION OUTPUT ;
    USE SIGNAL ;
    PORT
      LAYER M4 ;
        RECT  0 156.672 0.084 156.696 ;
    END
  END u[208]
  PIN u[209]
    DIRECTION OUTPUT ;
    USE SIGNAL ;
    PORT
      LAYER M4 ;
        RECT  0 156.864 0.084 156.888 ;
    END
  END u[209]
  PIN u[20]
    DIRECTION OUTPUT ;
    USE SIGNAL ;
    PORT
      LAYER M4 ;
        RECT  0 118.752 0.084 118.776 ;
    END
  END u[20]
  PIN u[210]
    DIRECTION OUTPUT ;
    USE SIGNAL ;
    PORT
      LAYER M4 ;
        RECT  0 157.056 0.084 157.08 ;
    END
  END u[210]
  PIN u[211]
    DIRECTION OUTPUT ;
    USE SIGNAL ;
    PORT
      LAYER M4 ;
        RECT  0 157.248 0.084 157.272 ;
    END
  END u[211]
  PIN u[212]
    DIRECTION OUTPUT ;
    USE SIGNAL ;
    PORT
      LAYER M4 ;
        RECT  0 157.44 0.084 157.464 ;
    END
  END u[212]
  PIN u[213]
    DIRECTION OUTPUT ;
    USE SIGNAL ;
    PORT
      LAYER M4 ;
        RECT  0 157.632 0.084 157.656 ;
    END
  END u[213]
  PIN u[214]
    DIRECTION OUTPUT ;
    USE SIGNAL ;
    PORT
      LAYER M4 ;
        RECT  0 157.92 0.084 157.944 ;
    END
  END u[214]
  PIN u[215]
    DIRECTION OUTPUT ;
    USE SIGNAL ;
    PORT
      LAYER M4 ;
        RECT  0 158.112 0.084 158.136 ;
    END
  END u[215]
  PIN u[216]
    DIRECTION OUTPUT ;
    USE SIGNAL ;
    PORT
      LAYER M4 ;
        RECT  0 158.304 0.084 158.328 ;
    END
  END u[216]
  PIN u[217]
    DIRECTION OUTPUT ;
    USE SIGNAL ;
    PORT
      LAYER M4 ;
        RECT  0 158.496 0.084 158.52 ;
    END
  END u[217]
  PIN u[218]
    DIRECTION OUTPUT ;
    USE SIGNAL ;
    PORT
      LAYER M4 ;
        RECT  0 158.688 0.084 158.712 ;
    END
  END u[218]
  PIN u[219]
    DIRECTION OUTPUT ;
    USE SIGNAL ;
    PORT
      LAYER M4 ;
        RECT  0 158.88 0.084 158.904 ;
    END
  END u[219]
  PIN u[21]
    DIRECTION OUTPUT ;
    USE SIGNAL ;
    PORT
      LAYER M4 ;
        RECT  0 118.944 0.084 118.968 ;
    END
  END u[21]
  PIN u[220]
    DIRECTION OUTPUT ;
    USE SIGNAL ;
    PORT
      LAYER M4 ;
        RECT  0 159.072 0.084 159.096 ;
    END
  END u[220]
  PIN u[221]
    DIRECTION OUTPUT ;
    USE SIGNAL ;
    PORT
      LAYER M4 ;
        RECT  0 159.264 0.084 159.288 ;
    END
  END u[221]
  PIN u[222]
    DIRECTION OUTPUT ;
    USE SIGNAL ;
    PORT
      LAYER M4 ;
        RECT  0 159.456 0.084 159.48 ;
    END
  END u[222]
  PIN u[223]
    DIRECTION OUTPUT ;
    USE SIGNAL ;
    PORT
      LAYER M4 ;
        RECT  0 159.648 0.084 159.672 ;
    END
  END u[223]
  PIN u[224]
    DIRECTION OUTPUT ;
    USE SIGNAL ;
    PORT
      LAYER M4 ;
        RECT  0 159.936 0.084 159.96 ;
    END
  END u[224]
  PIN u[225]
    DIRECTION OUTPUT ;
    USE SIGNAL ;
    PORT
      LAYER M4 ;
        RECT  0 160.128 0.084 160.152 ;
    END
  END u[225]
  PIN u[226]
    DIRECTION OUTPUT ;
    USE SIGNAL ;
    PORT
      LAYER M4 ;
        RECT  0 160.32 0.084 160.344 ;
    END
  END u[226]
  PIN u[227]
    DIRECTION OUTPUT ;
    USE SIGNAL ;
    PORT
      LAYER M4 ;
        RECT  0 160.512 0.084 160.536 ;
    END
  END u[227]
  PIN u[228]
    DIRECTION OUTPUT ;
    USE SIGNAL ;
    PORT
      LAYER M4 ;
        RECT  0 160.704 0.084 160.728 ;
    END
  END u[228]
  PIN u[229]
    DIRECTION OUTPUT ;
    USE SIGNAL ;
    PORT
      LAYER M4 ;
        RECT  0 160.896 0.084 160.92 ;
    END
  END u[229]
  PIN u[22]
    DIRECTION OUTPUT ;
    USE SIGNAL ;
    PORT
      LAYER M4 ;
        RECT  0 119.136 0.084 119.16 ;
    END
  END u[22]
  PIN u[230]
    DIRECTION OUTPUT ;
    USE SIGNAL ;
    PORT
      LAYER M4 ;
        RECT  0 161.088 0.084 161.112 ;
    END
  END u[230]
  PIN u[231]
    DIRECTION OUTPUT ;
    USE SIGNAL ;
    PORT
      LAYER M4 ;
        RECT  0 161.28 0.084 161.304 ;
    END
  END u[231]
  PIN u[232]
    DIRECTION OUTPUT ;
    USE SIGNAL ;
    PORT
      LAYER M4 ;
        RECT  0 161.472 0.084 161.496 ;
    END
  END u[232]
  PIN u[233]
    DIRECTION OUTPUT ;
    USE SIGNAL ;
    PORT
      LAYER M4 ;
        RECT  0 161.76 0.084 161.784 ;
    END
  END u[233]
  PIN u[234]
    DIRECTION OUTPUT ;
    USE SIGNAL ;
    PORT
      LAYER M4 ;
        RECT  0 161.952 0.084 161.976 ;
    END
  END u[234]
  PIN u[235]
    DIRECTION OUTPUT ;
    USE SIGNAL ;
    PORT
      LAYER M4 ;
        RECT  0 162.144 0.084 162.168 ;
    END
  END u[235]
  PIN u[236]
    DIRECTION OUTPUT ;
    USE SIGNAL ;
    PORT
      LAYER M4 ;
        RECT  0 162.336 0.084 162.36 ;
    END
  END u[236]
  PIN u[237]
    DIRECTION OUTPUT ;
    USE SIGNAL ;
    PORT
      LAYER M4 ;
        RECT  0 162.528 0.084 162.552 ;
    END
  END u[237]
  PIN u[238]
    DIRECTION OUTPUT ;
    USE SIGNAL ;
    PORT
      LAYER M4 ;
        RECT  0 162.72 0.084 162.744 ;
    END
  END u[238]
  PIN u[239]
    DIRECTION OUTPUT ;
    USE SIGNAL ;
    PORT
      LAYER M4 ;
        RECT  0 162.912 0.084 162.936 ;
    END
  END u[239]
  PIN u[23]
    DIRECTION OUTPUT ;
    USE SIGNAL ;
    PORT
      LAYER M4 ;
        RECT  0 119.328 0.084 119.352 ;
    END
  END u[23]
  PIN u[240]
    DIRECTION OUTPUT ;
    USE SIGNAL ;
    PORT
      LAYER M4 ;
        RECT  0 163.104 0.084 163.128 ;
    END
  END u[240]
  PIN u[241]
    DIRECTION OUTPUT ;
    USE SIGNAL ;
    PORT
      LAYER M4 ;
        RECT  0 163.296 0.084 163.32 ;
    END
  END u[241]
  PIN u[242]
    DIRECTION OUTPUT ;
    USE SIGNAL ;
    PORT
      LAYER M4 ;
        RECT  0 163.488 0.084 163.512 ;
    END
  END u[242]
  PIN u[243]
    DIRECTION OUTPUT ;
    USE SIGNAL ;
    PORT
      LAYER M4 ;
        RECT  0 163.776 0.084 163.8 ;
    END
  END u[243]
  PIN u[244]
    DIRECTION OUTPUT ;
    USE SIGNAL ;
    PORT
      LAYER M4 ;
        RECT  0 163.968 0.084 163.992 ;
    END
  END u[244]
  PIN u[245]
    DIRECTION OUTPUT ;
    USE SIGNAL ;
    PORT
      LAYER M4 ;
        RECT  0 164.16 0.084 164.184 ;
    END
  END u[245]
  PIN u[246]
    DIRECTION OUTPUT ;
    USE SIGNAL ;
    PORT
      LAYER M4 ;
        RECT  0 164.352 0.084 164.376 ;
    END
  END u[246]
  PIN u[247]
    DIRECTION OUTPUT ;
    USE SIGNAL ;
    PORT
      LAYER M4 ;
        RECT  0 164.544 0.084 164.568 ;
    END
  END u[247]
  PIN u[248]
    DIRECTION OUTPUT ;
    USE SIGNAL ;
    PORT
      LAYER M4 ;
        RECT  0 164.736 0.084 164.76 ;
    END
  END u[248]
  PIN u[249]
    DIRECTION OUTPUT ;
    USE SIGNAL ;
    PORT
      LAYER M4 ;
        RECT  0 164.928 0.084 164.952 ;
    END
  END u[249]
  PIN u[24]
    DIRECTION OUTPUT ;
    USE SIGNAL ;
    PORT
      LAYER M4 ;
        RECT  0 119.52 0.084 119.544 ;
    END
  END u[24]
  PIN u[250]
    DIRECTION OUTPUT ;
    USE SIGNAL ;
    PORT
      LAYER M4 ;
        RECT  0 165.12 0.084 165.144 ;
    END
  END u[250]
  PIN u[251]
    DIRECTION OUTPUT ;
    USE SIGNAL ;
    PORT
      LAYER M4 ;
        RECT  0 165.312 0.084 165.336 ;
    END
  END u[251]
  PIN u[252]
    DIRECTION OUTPUT ;
    USE SIGNAL ;
    PORT
      LAYER M4 ;
        RECT  0 165.504 0.084 165.528 ;
    END
  END u[252]
  PIN u[253]
    DIRECTION OUTPUT ;
    USE SIGNAL ;
    PORT
      LAYER M4 ;
        RECT  0 165.792 0.084 165.816 ;
    END
  END u[253]
  PIN u[254]
    DIRECTION OUTPUT ;
    USE SIGNAL ;
    PORT
      LAYER M4 ;
        RECT  0 165.984 0.084 166.008 ;
    END
  END u[254]
  PIN u[255]
    DIRECTION OUTPUT ;
    USE SIGNAL ;
    PORT
      LAYER M4 ;
        RECT  0 166.176 0.084 166.2 ;
    END
  END u[255]
  PIN u[25]
    DIRECTION OUTPUT ;
    USE SIGNAL ;
    PORT
      LAYER M4 ;
        RECT  0 119.808 0.084 119.832 ;
    END
  END u[25]
  PIN u[26]
    DIRECTION OUTPUT ;
    USE SIGNAL ;
    PORT
      LAYER M4 ;
        RECT  0 120 0.084 120.024 ;
    END
  END u[26]
  PIN u[27]
    DIRECTION OUTPUT ;
    USE SIGNAL ;
    PORT
      LAYER M4 ;
        RECT  0 120.192 0.084 120.216 ;
    END
  END u[27]
  PIN u[28]
    DIRECTION OUTPUT ;
    USE SIGNAL ;
    PORT
      LAYER M4 ;
        RECT  0 120.384 0.084 120.408 ;
    END
  END u[28]
  PIN u[29]
    DIRECTION OUTPUT ;
    USE SIGNAL ;
    PORT
      LAYER M4 ;
        RECT  0 120.576 0.084 120.6 ;
    END
  END u[29]
  PIN u[2]
    DIRECTION OUTPUT ;
    USE SIGNAL ;
    PORT
      LAYER M4 ;
        RECT  0 115.104 0.084 115.128 ;
    END
  END u[2]
  PIN u[30]
    DIRECTION OUTPUT ;
    USE SIGNAL ;
    PORT
      LAYER M4 ;
        RECT  0 120.768 0.084 120.792 ;
    END
  END u[30]
  PIN u[31]
    DIRECTION OUTPUT ;
    USE SIGNAL ;
    PORT
      LAYER M4 ;
        RECT  0 120.96 0.084 120.984 ;
    END
  END u[31]
  PIN u[32]
    DIRECTION OUTPUT ;
    USE SIGNAL ;
    PORT
      LAYER M4 ;
        RECT  0 121.152 0.084 121.176 ;
    END
  END u[32]
  PIN u[33]
    DIRECTION OUTPUT ;
    USE SIGNAL ;
    PORT
      LAYER M4 ;
        RECT  0 121.344 0.084 121.368 ;
    END
  END u[33]
  PIN u[34]
    DIRECTION OUTPUT ;
    USE SIGNAL ;
    PORT
      LAYER M4 ;
        RECT  0 121.536 0.084 121.56 ;
    END
  END u[34]
  PIN u[35]
    DIRECTION OUTPUT ;
    USE SIGNAL ;
    PORT
      LAYER M4 ;
        RECT  0 121.824 0.084 121.848 ;
    END
  END u[35]
  PIN u[36]
    DIRECTION OUTPUT ;
    USE SIGNAL ;
    PORT
      LAYER M4 ;
        RECT  0 122.016 0.084 122.04 ;
    END
  END u[36]
  PIN u[37]
    DIRECTION OUTPUT ;
    USE SIGNAL ;
    PORT
      LAYER M4 ;
        RECT  0 122.208 0.084 122.232 ;
    END
  END u[37]
  PIN u[38]
    DIRECTION OUTPUT ;
    USE SIGNAL ;
    PORT
      LAYER M4 ;
        RECT  0 122.4 0.084 122.424 ;
    END
  END u[38]
  PIN u[39]
    DIRECTION OUTPUT ;
    USE SIGNAL ;
    PORT
      LAYER M4 ;
        RECT  0 122.592 0.084 122.616 ;
    END
  END u[39]
  PIN u[3]
    DIRECTION OUTPUT ;
    USE SIGNAL ;
    PORT
      LAYER M4 ;
        RECT  0 115.296 0.084 115.32 ;
    END
  END u[3]
  PIN u[40]
    DIRECTION OUTPUT ;
    USE SIGNAL ;
    PORT
      LAYER M4 ;
        RECT  0 122.784 0.084 122.808 ;
    END
  END u[40]
  PIN u[41]
    DIRECTION OUTPUT ;
    USE SIGNAL ;
    PORT
      LAYER M4 ;
        RECT  0 122.976 0.084 123 ;
    END
  END u[41]
  PIN u[42]
    DIRECTION OUTPUT ;
    USE SIGNAL ;
    PORT
      LAYER M4 ;
        RECT  0 123.168 0.084 123.192 ;
    END
  END u[42]
  PIN u[43]
    DIRECTION OUTPUT ;
    USE SIGNAL ;
    PORT
      LAYER M4 ;
        RECT  0 123.36 0.084 123.384 ;
    END
  END u[43]
  PIN u[44]
    DIRECTION OUTPUT ;
    USE SIGNAL ;
    PORT
      LAYER M4 ;
        RECT  0 123.552 0.084 123.576 ;
    END
  END u[44]
  PIN u[45]
    DIRECTION OUTPUT ;
    USE SIGNAL ;
    PORT
      LAYER M4 ;
        RECT  0 123.84 0.084 123.864 ;
    END
  END u[45]
  PIN u[46]
    DIRECTION OUTPUT ;
    USE SIGNAL ;
    PORT
      LAYER M4 ;
        RECT  0 124.032 0.084 124.056 ;
    END
  END u[46]
  PIN u[47]
    DIRECTION OUTPUT ;
    USE SIGNAL ;
    PORT
      LAYER M4 ;
        RECT  0 124.224 0.084 124.248 ;
    END
  END u[47]
  PIN u[48]
    DIRECTION OUTPUT ;
    USE SIGNAL ;
    PORT
      LAYER M4 ;
        RECT  0 124.416 0.084 124.44 ;
    END
  END u[48]
  PIN u[49]
    DIRECTION OUTPUT ;
    USE SIGNAL ;
    PORT
      LAYER M4 ;
        RECT  0 124.608 0.084 124.632 ;
    END
  END u[49]
  PIN u[4]
    DIRECTION OUTPUT ;
    USE SIGNAL ;
    PORT
      LAYER M4 ;
        RECT  0 115.488 0.084 115.512 ;
    END
  END u[4]
  PIN u[50]
    DIRECTION OUTPUT ;
    USE SIGNAL ;
    PORT
      LAYER M4 ;
        RECT  0 124.8 0.084 124.824 ;
    END
  END u[50]
  PIN u[51]
    DIRECTION OUTPUT ;
    USE SIGNAL ;
    PORT
      LAYER M4 ;
        RECT  0 124.992 0.084 125.016 ;
    END
  END u[51]
  PIN u[52]
    DIRECTION OUTPUT ;
    USE SIGNAL ;
    PORT
      LAYER M4 ;
        RECT  0 125.184 0.084 125.208 ;
    END
  END u[52]
  PIN u[53]
    DIRECTION OUTPUT ;
    USE SIGNAL ;
    PORT
      LAYER M4 ;
        RECT  0 125.376 0.084 125.4 ;
    END
  END u[53]
  PIN u[54]
    DIRECTION OUTPUT ;
    USE SIGNAL ;
    PORT
      LAYER M4 ;
        RECT  0 125.568 0.084 125.592 ;
    END
  END u[54]
  PIN u[55]
    DIRECTION OUTPUT ;
    USE SIGNAL ;
    PORT
      LAYER M4 ;
        RECT  0 125.856 0.084 125.88 ;
    END
  END u[55]
  PIN u[56]
    DIRECTION OUTPUT ;
    USE SIGNAL ;
    PORT
      LAYER M4 ;
        RECT  0 126.048 0.084 126.072 ;
    END
  END u[56]
  PIN u[57]
    DIRECTION OUTPUT ;
    USE SIGNAL ;
    PORT
      LAYER M4 ;
        RECT  0 126.24 0.084 126.264 ;
    END
  END u[57]
  PIN u[58]
    DIRECTION OUTPUT ;
    USE SIGNAL ;
    PORT
      LAYER M4 ;
        RECT  0 126.432 0.084 126.456 ;
    END
  END u[58]
  PIN u[59]
    DIRECTION OUTPUT ;
    USE SIGNAL ;
    PORT
      LAYER M4 ;
        RECT  0 126.624 0.084 126.648 ;
    END
  END u[59]
  PIN u[5]
    DIRECTION OUTPUT ;
    USE SIGNAL ;
    PORT
      LAYER M4 ;
        RECT  0 115.776 0.084 115.8 ;
    END
  END u[5]
  PIN u[60]
    DIRECTION OUTPUT ;
    USE SIGNAL ;
    PORT
      LAYER M4 ;
        RECT  0 126.816 0.084 126.84 ;
    END
  END u[60]
  PIN u[61]
    DIRECTION OUTPUT ;
    USE SIGNAL ;
    PORT
      LAYER M4 ;
        RECT  0 127.008 0.084 127.032 ;
    END
  END u[61]
  PIN u[62]
    DIRECTION OUTPUT ;
    USE SIGNAL ;
    PORT
      LAYER M4 ;
        RECT  0 127.2 0.084 127.224 ;
    END
  END u[62]
  PIN u[63]
    DIRECTION OUTPUT ;
    USE SIGNAL ;
    PORT
      LAYER M4 ;
        RECT  0 127.392 0.084 127.416 ;
    END
  END u[63]
  PIN u[64]
    DIRECTION OUTPUT ;
    USE SIGNAL ;
    PORT
      LAYER M4 ;
        RECT  0 127.584 0.084 127.608 ;
    END
  END u[64]
  PIN u[65]
    DIRECTION OUTPUT ;
    USE SIGNAL ;
    PORT
      LAYER M4 ;
        RECT  0 127.872 0.084 127.896 ;
    END
  END u[65]
  PIN u[66]
    DIRECTION OUTPUT ;
    USE SIGNAL ;
    PORT
      LAYER M4 ;
        RECT  0 128.064 0.084 128.088 ;
    END
  END u[66]
  PIN u[67]
    DIRECTION OUTPUT ;
    USE SIGNAL ;
    PORT
      LAYER M4 ;
        RECT  0 128.256 0.084 128.28 ;
    END
  END u[67]
  PIN u[68]
    DIRECTION OUTPUT ;
    USE SIGNAL ;
    PORT
      LAYER M4 ;
        RECT  0 128.448 0.084 128.472 ;
    END
  END u[68]
  PIN u[69]
    DIRECTION OUTPUT ;
    USE SIGNAL ;
    PORT
      LAYER M4 ;
        RECT  0 128.64 0.084 128.664 ;
    END
  END u[69]
  PIN u[6]
    DIRECTION OUTPUT ;
    USE SIGNAL ;
    PORT
      LAYER M4 ;
        RECT  0 115.968 0.084 115.992 ;
    END
  END u[6]
  PIN u[70]
    DIRECTION OUTPUT ;
    USE SIGNAL ;
    PORT
      LAYER M4 ;
        RECT  0 128.832 0.084 128.856 ;
    END
  END u[70]
  PIN u[71]
    DIRECTION OUTPUT ;
    USE SIGNAL ;
    PORT
      LAYER M4 ;
        RECT  0 129.024 0.084 129.048 ;
    END
  END u[71]
  PIN u[72]
    DIRECTION OUTPUT ;
    USE SIGNAL ;
    PORT
      LAYER M4 ;
        RECT  0 129.216 0.084 129.24 ;
    END
  END u[72]
  PIN u[73]
    DIRECTION OUTPUT ;
    USE SIGNAL ;
    PORT
      LAYER M4 ;
        RECT  0 129.408 0.084 129.432 ;
    END
  END u[73]
  PIN u[74]
    DIRECTION OUTPUT ;
    USE SIGNAL ;
    PORT
      LAYER M4 ;
        RECT  0 129.6 0.084 129.624 ;
    END
  END u[74]
  PIN u[75]
    DIRECTION OUTPUT ;
    USE SIGNAL ;
    PORT
      LAYER M4 ;
        RECT  0 129.888 0.084 129.912 ;
    END
  END u[75]
  PIN u[76]
    DIRECTION OUTPUT ;
    USE SIGNAL ;
    PORT
      LAYER M4 ;
        RECT  0 130.08 0.084 130.104 ;
    END
  END u[76]
  PIN u[77]
    DIRECTION OUTPUT ;
    USE SIGNAL ;
    PORT
      LAYER M4 ;
        RECT  0 130.272 0.084 130.296 ;
    END
  END u[77]
  PIN u[78]
    DIRECTION OUTPUT ;
    USE SIGNAL ;
    PORT
      LAYER M4 ;
        RECT  0 130.464 0.084 130.488 ;
    END
  END u[78]
  PIN u[79]
    DIRECTION OUTPUT ;
    USE SIGNAL ;
    PORT
      LAYER M4 ;
        RECT  0 130.656 0.084 130.68 ;
    END
  END u[79]
  PIN u[7]
    DIRECTION OUTPUT ;
    USE SIGNAL ;
    PORT
      LAYER M4 ;
        RECT  0 116.16 0.084 116.184 ;
    END
  END u[7]
  PIN u[80]
    DIRECTION OUTPUT ;
    USE SIGNAL ;
    PORT
      LAYER M4 ;
        RECT  0 130.848 0.084 130.872 ;
    END
  END u[80]
  PIN u[81]
    DIRECTION OUTPUT ;
    USE SIGNAL ;
    PORT
      LAYER M4 ;
        RECT  0 131.04 0.084 131.064 ;
    END
  END u[81]
  PIN u[82]
    DIRECTION OUTPUT ;
    USE SIGNAL ;
    PORT
      LAYER M4 ;
        RECT  0 131.232 0.084 131.256 ;
    END
  END u[82]
  PIN u[83]
    DIRECTION OUTPUT ;
    USE SIGNAL ;
    PORT
      LAYER M4 ;
        RECT  0 131.424 0.084 131.448 ;
    END
  END u[83]
  PIN u[84]
    DIRECTION OUTPUT ;
    USE SIGNAL ;
    PORT
      LAYER M4 ;
        RECT  0 131.616 0.084 131.64 ;
    END
  END u[84]
  PIN u[85]
    DIRECTION OUTPUT ;
    USE SIGNAL ;
    PORT
      LAYER M4 ;
        RECT  0 131.904 0.084 131.928 ;
    END
  END u[85]
  PIN u[86]
    DIRECTION OUTPUT ;
    USE SIGNAL ;
    PORT
      LAYER M4 ;
        RECT  0 132.096 0.084 132.12 ;
    END
  END u[86]
  PIN u[87]
    DIRECTION OUTPUT ;
    USE SIGNAL ;
    PORT
      LAYER M4 ;
        RECT  0 132.288 0.084 132.312 ;
    END
  END u[87]
  PIN u[88]
    DIRECTION OUTPUT ;
    USE SIGNAL ;
    PORT
      LAYER M4 ;
        RECT  0 132.48 0.084 132.504 ;
    END
  END u[88]
  PIN u[89]
    DIRECTION OUTPUT ;
    USE SIGNAL ;
    PORT
      LAYER M4 ;
        RECT  0 132.672 0.084 132.696 ;
    END
  END u[89]
  PIN u[8]
    DIRECTION OUTPUT ;
    USE SIGNAL ;
    PORT
      LAYER M4 ;
        RECT  0 116.352 0.084 116.376 ;
    END
  END u[8]
  PIN u[90]
    DIRECTION OUTPUT ;
    USE SIGNAL ;
    PORT
      LAYER M4 ;
        RECT  0 132.864 0.084 132.888 ;
    END
  END u[90]
  PIN u[91]
    DIRECTION OUTPUT ;
    USE SIGNAL ;
    PORT
      LAYER M4 ;
        RECT  0 133.056 0.084 133.08 ;
    END
  END u[91]
  PIN u[92]
    DIRECTION OUTPUT ;
    USE SIGNAL ;
    PORT
      LAYER M4 ;
        RECT  0 133.248 0.084 133.272 ;
    END
  END u[92]
  PIN u[93]
    DIRECTION OUTPUT ;
    USE SIGNAL ;
    PORT
      LAYER M4 ;
        RECT  0 133.44 0.084 133.464 ;
    END
  END u[93]
  PIN u[94]
    DIRECTION OUTPUT ;
    USE SIGNAL ;
    PORT
      LAYER M4 ;
        RECT  0 133.632 0.084 133.656 ;
    END
  END u[94]
  PIN u[95]
    DIRECTION OUTPUT ;
    USE SIGNAL ;
    PORT
      LAYER M4 ;
        RECT  0 133.92 0.084 133.944 ;
    END
  END u[95]
  PIN u[96]
    DIRECTION OUTPUT ;
    USE SIGNAL ;
    PORT
      LAYER M4 ;
        RECT  0 134.112 0.084 134.136 ;
    END
  END u[96]
  PIN u[97]
    DIRECTION OUTPUT ;
    USE SIGNAL ;
    PORT
      LAYER M4 ;
        RECT  0 134.304 0.084 134.328 ;
    END
  END u[97]
  PIN u[98]
    DIRECTION OUTPUT ;
    USE SIGNAL ;
    PORT
      LAYER M4 ;
        RECT  0 134.496 0.084 134.52 ;
    END
  END u[98]
  PIN u[99]
    DIRECTION OUTPUT ;
    USE SIGNAL ;
    PORT
      LAYER M4 ;
        RECT  0 134.688 0.084 134.712 ;
    END
  END u[99]
  PIN u[9]
    DIRECTION OUTPUT ;
    USE SIGNAL ;
    PORT
      LAYER M4 ;
        RECT  0 116.544 0.084 116.568 ;
    END
  END u[9]
  PIN u_i[0]
    DIRECTION OUTPUT ;
    USE SIGNAL ;
    PORT
      LAYER M4 ;
        RECT  0 114.144 0.084 114.168 ;
    END
  END u_i[0]
  PIN u_i[1]
    DIRECTION OUTPUT ;
    USE SIGNAL ;
    PORT
      LAYER M4 ;
        RECT  0 114.336 0.084 114.36 ;
    END
  END u_i[1]
  PIN u_i[2]
    DIRECTION OUTPUT ;
    USE SIGNAL ;
    PORT
      LAYER M4 ;
        RECT  0 114.528 0.084 114.552 ;
    END
  END u_i[2]
  PIN u_v
    DIRECTION OUTPUT ;
    USE SIGNAL ;
    PORT
      LAYER M4 ;
        RECT  0 113.952 0.084 113.976 ;
    END
  END u_v
  PIN um_b
    DIRECTION OUTPUT ;
    USE SIGNAL ;
    PORT
      LAYER M4 ;
        RECT  0 166.752 0.084 166.776 ;
    END
  END um_b
  PIN um_i[0]
    DIRECTION OUTPUT ;
    USE SIGNAL ;
    PORT
      LAYER M4 ;
        RECT  0 166.944 0.084 166.968 ;
    END
  END um_i[0]
  PIN um_i[1]
    DIRECTION OUTPUT ;
    USE SIGNAL ;
    PORT
      LAYER M4 ;
        RECT  0 167.136 0.084 167.16 ;
    END
  END um_i[1]
  PIN um_i[2]
    DIRECTION OUTPUT ;
    USE SIGNAL ;
    PORT
      LAYER M4 ;
        RECT  0 167.328 0.084 167.352 ;
    END
  END um_i[2]
  PIN um_i[3]
    DIRECTION OUTPUT ;
    USE SIGNAL ;
    PORT
      LAYER M4 ;
        RECT  0 167.52 0.084 167.544 ;
    END
  END um_i[3]
  PIN um_i[4]
    DIRECTION OUTPUT ;
    USE SIGNAL ;
    PORT
      LAYER M4 ;
        RECT  0 167.808 0.084 167.832 ;
    END
  END um_i[4]
  PIN um_i[5]
    DIRECTION OUTPUT ;
    USE SIGNAL ;
    PORT
      LAYER M4 ;
        RECT  0 168 0.084 168.024 ;
    END
  END um_i[5]
  PIN um_i[6]
    DIRECTION OUTPUT ;
    USE SIGNAL ;
    PORT
      LAYER M4 ;
        RECT  0 168.192 0.084 168.216 ;
    END
  END um_i[6]
  PIN um_i[7]
    DIRECTION OUTPUT ;
    USE SIGNAL ;
    PORT
      LAYER M4 ;
        RECT  0 168.384 0.084 168.408 ;
    END
  END um_i[7]
  PIN um_q
    DIRECTION OUTPUT ;
    USE SIGNAL ;
    PORT
      LAYER M4 ;
        RECT  0 166.56 0.084 166.584 ;
    END
  END um_q
  PIN um_v
    DIRECTION OUTPUT ;
    USE SIGNAL ;
    PORT
      LAYER M4 ;
        RECT  0 166.368 0.084 166.392 ;
    END
  END um_v
  PIN ve_ac[0]
    DIRECTION OUTPUT ;
    USE SIGNAL ;
    PORT
      LAYER M5 ;
        RECT  114.96 172.716 114.984 172.8 ;
    END
  END ve_ac[0]
  PIN ve_ac[1]
    DIRECTION OUTPUT ;
    USE SIGNAL ;
    PORT
      LAYER M5 ;
        RECT  115.056 172.716 115.08 172.8 ;
    END
  END ve_ac[1]
  PIN ve_ag[0]
    DIRECTION OUTPUT ;
    USE SIGNAL ;
    PORT
      LAYER M5 ;
        RECT  164.352 172.716 164.376 172.8 ;
    END
  END ve_ag[0]
  PIN ve_ag[10]
    DIRECTION OUTPUT ;
    USE SIGNAL ;
    PORT
      LAYER M5 ;
        RECT  165.696 172.716 165.72 172.8 ;
    END
  END ve_ag[10]
  PIN ve_ag[11]
    DIRECTION OUTPUT ;
    USE SIGNAL ;
    PORT
      LAYER M5 ;
        RECT  165.792 172.716 165.816 172.8 ;
    END
  END ve_ag[11]
  PIN ve_ag[12]
    DIRECTION OUTPUT ;
    USE SIGNAL ;
    PORT
      LAYER M5 ;
        RECT  165.984 172.716 166.008 172.8 ;
    END
  END ve_ag[12]
  PIN ve_ag[13]
    DIRECTION OUTPUT ;
    USE SIGNAL ;
    PORT
      LAYER M5 ;
        RECT  166.704 172.716 166.728 172.8 ;
    END
  END ve_ag[13]
  PIN ve_ag[14]
    DIRECTION OUTPUT ;
    USE SIGNAL ;
    PORT
      LAYER M5 ;
        RECT  166.8 172.716 166.824 172.8 ;
    END
  END ve_ag[14]
  PIN ve_ag[15]
    DIRECTION OUTPUT ;
    USE SIGNAL ;
    PORT
      LAYER M5 ;
        RECT  166.896 172.716 166.92 172.8 ;
    END
  END ve_ag[15]
  PIN ve_ag[16]
    DIRECTION OUTPUT ;
    USE SIGNAL ;
    PORT
      LAYER M5 ;
        RECT  166.992 172.716 167.016 172.8 ;
    END
  END ve_ag[16]
  PIN ve_ag[17]
    DIRECTION OUTPUT ;
    USE SIGNAL ;
    PORT
      LAYER M5 ;
        RECT  167.088 172.716 167.112 172.8 ;
    END
  END ve_ag[17]
  PIN ve_ag[18]
    DIRECTION OUTPUT ;
    USE SIGNAL ;
    PORT
      LAYER M5 ;
        RECT  167.184 172.716 167.208 172.8 ;
    END
  END ve_ag[18]
  PIN ve_ag[19]
    DIRECTION OUTPUT ;
    USE SIGNAL ;
    PORT
      LAYER M5 ;
        RECT  167.28 172.716 167.304 172.8 ;
    END
  END ve_ag[19]
  PIN ve_ag[1]
    DIRECTION OUTPUT ;
    USE SIGNAL ;
    PORT
      LAYER M5 ;
        RECT  164.544 172.716 164.568 172.8 ;
    END
  END ve_ag[1]
  PIN ve_ag[20]
    DIRECTION OUTPUT ;
    USE SIGNAL ;
    PORT
      LAYER M5 ;
        RECT  167.376 172.716 167.4 172.8 ;
    END
  END ve_ag[20]
  PIN ve_ag[21]
    DIRECTION OUTPUT ;
    USE SIGNAL ;
    PORT
      LAYER M5 ;
        RECT  167.472 172.716 167.496 172.8 ;
    END
  END ve_ag[21]
  PIN ve_ag[22]
    DIRECTION OUTPUT ;
    USE SIGNAL ;
    PORT
      LAYER M5 ;
        RECT  167.568 172.716 167.592 172.8 ;
    END
  END ve_ag[22]
  PIN ve_ag[23]
    DIRECTION OUTPUT ;
    USE SIGNAL ;
    PORT
      LAYER M5 ;
        RECT  167.664 172.716 167.688 172.8 ;
    END
  END ve_ag[23]
  PIN ve_ag[24]
    DIRECTION OUTPUT ;
    USE SIGNAL ;
    PORT
      LAYER M5 ;
        RECT  167.76 172.716 167.784 172.8 ;
    END
  END ve_ag[24]
  PIN ve_ag[25]
    DIRECTION OUTPUT ;
    USE SIGNAL ;
    PORT
      LAYER M5 ;
        RECT  167.856 172.716 167.88 172.8 ;
    END
  END ve_ag[25]
  PIN ve_ag[26]
    DIRECTION OUTPUT ;
    USE SIGNAL ;
    PORT
      LAYER M5 ;
        RECT  167.952 172.716 167.976 172.8 ;
    END
  END ve_ag[26]
  PIN ve_ag[27]
    DIRECTION OUTPUT ;
    USE SIGNAL ;
    PORT
      LAYER M5 ;
        RECT  168.048 172.716 168.072 172.8 ;
    END
  END ve_ag[27]
  PIN ve_ag[28]
    DIRECTION OUTPUT ;
    USE SIGNAL ;
    PORT
      LAYER M5 ;
        RECT  168.144 172.716 168.168 172.8 ;
    END
  END ve_ag[28]
  PIN ve_ag[29]
    DIRECTION OUTPUT ;
    USE SIGNAL ;
    PORT
      LAYER M5 ;
        RECT  168.24 172.716 168.264 172.8 ;
    END
  END ve_ag[29]
  PIN ve_ag[2]
    DIRECTION OUTPUT ;
    USE SIGNAL ;
    PORT
      LAYER M5 ;
        RECT  164.64 172.716 164.664 172.8 ;
    END
  END ve_ag[2]
  PIN ve_ag[30]
    DIRECTION OUTPUT ;
    USE SIGNAL ;
    PORT
      LAYER M5 ;
        RECT  168.336 172.716 168.36 172.8 ;
    END
  END ve_ag[30]
  PIN ve_ag[31]
    DIRECTION OUTPUT ;
    USE SIGNAL ;
    PORT
      LAYER M5 ;
        RECT  168.432 172.716 168.456 172.8 ;
    END
  END ve_ag[31]
  PIN ve_ag[3]
    DIRECTION OUTPUT ;
    USE SIGNAL ;
    PORT
      LAYER M5 ;
        RECT  164.832 172.716 164.856 172.8 ;
    END
  END ve_ag[3]
  PIN ve_ag[4]
    DIRECTION OUTPUT ;
    USE SIGNAL ;
    PORT
      LAYER M5 ;
        RECT  164.928 172.716 164.952 172.8 ;
    END
  END ve_ag[4]
  PIN ve_ag[5]
    DIRECTION OUTPUT ;
    USE SIGNAL ;
    PORT
      LAYER M5 ;
        RECT  165.024 172.716 165.048 172.8 ;
    END
  END ve_ag[5]
  PIN ve_ag[6]
    DIRECTION OUTPUT ;
    USE SIGNAL ;
    PORT
      LAYER M5 ;
        RECT  165.12 172.716 165.144 172.8 ;
    END
  END ve_ag[6]
  PIN ve_ag[7]
    DIRECTION OUTPUT ;
    USE SIGNAL ;
    PORT
      LAYER M5 ;
        RECT  165.312 172.716 165.336 172.8 ;
    END
  END ve_ag[7]
  PIN ve_ag[8]
    DIRECTION OUTPUT ;
    USE SIGNAL ;
    PORT
      LAYER M5 ;
        RECT  165.408 172.716 165.432 172.8 ;
    END
  END ve_ag[8]
  PIN ve_ag[9]
    DIRECTION OUTPUT ;
    USE SIGNAL ;
    PORT
      LAYER M5 ;
        RECT  165.504 172.716 165.528 172.8 ;
    END
  END ve_ag[9]
  PIN ve_ah[0]
    DIRECTION OUTPUT ;
    USE SIGNAL ;
    PORT
      LAYER M5 ;
        RECT  115.152 172.716 115.176 172.8 ;
    END
  END ve_ah[0]
  PIN ve_ah[100]
    DIRECTION OUTPUT ;
    USE SIGNAL ;
    PORT
      LAYER M5 ;
        RECT  128.112 172.716 128.136 172.8 ;
    END
  END ve_ah[100]
  PIN ve_ah[101]
    DIRECTION OUTPUT ;
    USE SIGNAL ;
    PORT
      LAYER M5 ;
        RECT  128.208 172.716 128.232 172.8 ;
    END
  END ve_ah[101]
  PIN ve_ah[102]
    DIRECTION OUTPUT ;
    USE SIGNAL ;
    PORT
      LAYER M5 ;
        RECT  128.304 172.716 128.328 172.8 ;
    END
  END ve_ah[102]
  PIN ve_ah[103]
    DIRECTION OUTPUT ;
    USE SIGNAL ;
    PORT
      LAYER M5 ;
        RECT  128.4 172.716 128.424 172.8 ;
    END
  END ve_ah[103]
  PIN ve_ah[104]
    DIRECTION OUTPUT ;
    USE SIGNAL ;
    PORT
      LAYER M5 ;
        RECT  128.496 172.716 128.52 172.8 ;
    END
  END ve_ah[104]
  PIN ve_ah[105]
    DIRECTION OUTPUT ;
    USE SIGNAL ;
    PORT
      LAYER M5 ;
        RECT  128.592 172.716 128.616 172.8 ;
    END
  END ve_ah[105]
  PIN ve_ah[106]
    DIRECTION OUTPUT ;
    USE SIGNAL ;
    PORT
      LAYER M5 ;
        RECT  128.688 172.716 128.712 172.8 ;
    END
  END ve_ah[106]
  PIN ve_ah[107]
    DIRECTION OUTPUT ;
    USE SIGNAL ;
    PORT
      LAYER M5 ;
        RECT  128.784 172.716 128.808 172.8 ;
    END
  END ve_ah[107]
  PIN ve_ah[108]
    DIRECTION OUTPUT ;
    USE SIGNAL ;
    PORT
      LAYER M5 ;
        RECT  128.88 172.716 128.904 172.8 ;
    END
  END ve_ah[108]
  PIN ve_ah[109]
    DIRECTION OUTPUT ;
    USE SIGNAL ;
    PORT
      LAYER M5 ;
        RECT  128.976 172.716 129 172.8 ;
    END
  END ve_ah[109]
  PIN ve_ah[10]
    DIRECTION OUTPUT ;
    USE SIGNAL ;
    PORT
      LAYER M5 ;
        RECT  116.112 172.716 116.136 172.8 ;
    END
  END ve_ah[10]
  PIN ve_ah[110]
    DIRECTION OUTPUT ;
    USE SIGNAL ;
    PORT
      LAYER M5 ;
        RECT  129.072 172.716 129.096 172.8 ;
    END
  END ve_ah[110]
  PIN ve_ah[111]
    DIRECTION OUTPUT ;
    USE SIGNAL ;
    PORT
      LAYER M5 ;
        RECT  129.168 172.716 129.192 172.8 ;
    END
  END ve_ah[111]
  PIN ve_ah[112]
    DIRECTION OUTPUT ;
    USE SIGNAL ;
    PORT
      LAYER M5 ;
        RECT  129.264 172.716 129.288 172.8 ;
    END
  END ve_ah[112]
  PIN ve_ah[113]
    DIRECTION OUTPUT ;
    USE SIGNAL ;
    PORT
      LAYER M5 ;
        RECT  129.36 172.716 129.384 172.8 ;
    END
  END ve_ah[113]
  PIN ve_ah[114]
    DIRECTION OUTPUT ;
    USE SIGNAL ;
    PORT
      LAYER M5 ;
        RECT  129.456 172.716 129.48 172.8 ;
    END
  END ve_ah[114]
  PIN ve_ah[115]
    DIRECTION OUTPUT ;
    USE SIGNAL ;
    PORT
      LAYER M5 ;
        RECT  129.552 172.716 129.576 172.8 ;
    END
  END ve_ah[115]
  PIN ve_ah[116]
    DIRECTION OUTPUT ;
    USE SIGNAL ;
    PORT
      LAYER M5 ;
        RECT  129.696 172.716 129.72 172.8 ;
    END
  END ve_ah[116]
  PIN ve_ah[117]
    DIRECTION OUTPUT ;
    USE SIGNAL ;
    PORT
      LAYER M5 ;
        RECT  129.792 172.716 129.816 172.8 ;
    END
  END ve_ah[117]
  PIN ve_ah[118]
    DIRECTION OUTPUT ;
    USE SIGNAL ;
    PORT
      LAYER M5 ;
        RECT  129.888 172.716 129.912 172.8 ;
    END
  END ve_ah[118]
  PIN ve_ah[119]
    DIRECTION OUTPUT ;
    USE SIGNAL ;
    PORT
      LAYER M5 ;
        RECT  129.984 172.716 130.008 172.8 ;
    END
  END ve_ah[119]
  PIN ve_ah[11]
    DIRECTION OUTPUT ;
    USE SIGNAL ;
    PORT
      LAYER M5 ;
        RECT  116.208 172.716 116.232 172.8 ;
    END
  END ve_ah[11]
  PIN ve_ah[120]
    DIRECTION OUTPUT ;
    USE SIGNAL ;
    PORT
      LAYER M5 ;
        RECT  130.176 172.716 130.2 172.8 ;
    END
  END ve_ah[120]
  PIN ve_ah[121]
    DIRECTION OUTPUT ;
    USE SIGNAL ;
    PORT
      LAYER M5 ;
        RECT  130.272 172.716 130.296 172.8 ;
    END
  END ve_ah[121]
  PIN ve_ah[122]
    DIRECTION OUTPUT ;
    USE SIGNAL ;
    PORT
      LAYER M5 ;
        RECT  130.464 172.716 130.488 172.8 ;
    END
  END ve_ah[122]
  PIN ve_ah[123]
    DIRECTION OUTPUT ;
    USE SIGNAL ;
    PORT
      LAYER M5 ;
        RECT  130.56 172.716 130.584 172.8 ;
    END
  END ve_ah[123]
  PIN ve_ah[124]
    DIRECTION OUTPUT ;
    USE SIGNAL ;
    PORT
      LAYER M5 ;
        RECT  130.656 172.716 130.68 172.8 ;
    END
  END ve_ah[124]
  PIN ve_ah[125]
    DIRECTION OUTPUT ;
    USE SIGNAL ;
    PORT
      LAYER M5 ;
        RECT  130.848 172.716 130.872 172.8 ;
    END
  END ve_ah[125]
  PIN ve_ah[126]
    DIRECTION OUTPUT ;
    USE SIGNAL ;
    PORT
      LAYER M5 ;
        RECT  130.944 172.716 130.968 172.8 ;
    END
  END ve_ah[126]
  PIN ve_ah[127]
    DIRECTION OUTPUT ;
    USE SIGNAL ;
    PORT
      LAYER M5 ;
        RECT  131.136 172.716 131.16 172.8 ;
    END
  END ve_ah[127]
  PIN ve_ah[12]
    DIRECTION OUTPUT ;
    USE SIGNAL ;
    PORT
      LAYER M5 ;
        RECT  116.304 172.716 116.328 172.8 ;
    END
  END ve_ah[12]
  PIN ve_ah[13]
    DIRECTION OUTPUT ;
    USE SIGNAL ;
    PORT
      LAYER M5 ;
        RECT  116.4 172.716 116.424 172.8 ;
    END
  END ve_ah[13]
  PIN ve_ah[14]
    DIRECTION OUTPUT ;
    USE SIGNAL ;
    PORT
      LAYER M5 ;
        RECT  116.496 172.716 116.52 172.8 ;
    END
  END ve_ah[14]
  PIN ve_ah[15]
    DIRECTION OUTPUT ;
    USE SIGNAL ;
    PORT
      LAYER M5 ;
        RECT  116.592 172.716 116.616 172.8 ;
    END
  END ve_ah[15]
  PIN ve_ah[16]
    DIRECTION OUTPUT ;
    USE SIGNAL ;
    PORT
      LAYER M5 ;
        RECT  116.736 172.716 116.76 172.8 ;
    END
  END ve_ah[16]
  PIN ve_ah[17]
    DIRECTION OUTPUT ;
    USE SIGNAL ;
    PORT
      LAYER M5 ;
        RECT  116.832 172.716 116.856 172.8 ;
    END
  END ve_ah[17]
  PIN ve_ah[18]
    DIRECTION OUTPUT ;
    USE SIGNAL ;
    PORT
      LAYER M5 ;
        RECT  116.928 172.716 116.952 172.8 ;
    END
  END ve_ah[18]
  PIN ve_ah[19]
    DIRECTION OUTPUT ;
    USE SIGNAL ;
    PORT
      LAYER M5 ;
        RECT  117.024 172.716 117.048 172.8 ;
    END
  END ve_ah[19]
  PIN ve_ah[1]
    DIRECTION OUTPUT ;
    USE SIGNAL ;
    PORT
      LAYER M5 ;
        RECT  115.248 172.716 115.272 172.8 ;
    END
  END ve_ah[1]
  PIN ve_ah[20]
    DIRECTION OUTPUT ;
    USE SIGNAL ;
    PORT
      LAYER M5 ;
        RECT  117.216 172.716 117.24 172.8 ;
    END
  END ve_ah[20]
  PIN ve_ah[21]
    DIRECTION OUTPUT ;
    USE SIGNAL ;
    PORT
      LAYER M5 ;
        RECT  117.312 172.716 117.336 172.8 ;
    END
  END ve_ah[21]
  PIN ve_ah[22]
    DIRECTION OUTPUT ;
    USE SIGNAL ;
    PORT
      LAYER M5 ;
        RECT  117.504 172.716 117.528 172.8 ;
    END
  END ve_ah[22]
  PIN ve_ah[23]
    DIRECTION OUTPUT ;
    USE SIGNAL ;
    PORT
      LAYER M5 ;
        RECT  117.6 172.716 117.624 172.8 ;
    END
  END ve_ah[23]
  PIN ve_ah[24]
    DIRECTION OUTPUT ;
    USE SIGNAL ;
    PORT
      LAYER M5 ;
        RECT  117.696 172.716 117.72 172.8 ;
    END
  END ve_ah[24]
  PIN ve_ah[25]
    DIRECTION OUTPUT ;
    USE SIGNAL ;
    PORT
      LAYER M5 ;
        RECT  117.888 172.716 117.912 172.8 ;
    END
  END ve_ah[25]
  PIN ve_ah[26]
    DIRECTION OUTPUT ;
    USE SIGNAL ;
    PORT
      LAYER M5 ;
        RECT  117.984 172.716 118.008 172.8 ;
    END
  END ve_ah[26]
  PIN ve_ah[27]
    DIRECTION OUTPUT ;
    USE SIGNAL ;
    PORT
      LAYER M5 ;
        RECT  118.176 172.716 118.2 172.8 ;
    END
  END ve_ah[27]
  PIN ve_ah[28]
    DIRECTION OUTPUT ;
    USE SIGNAL ;
    PORT
      LAYER M5 ;
        RECT  118.272 172.716 118.296 172.8 ;
    END
  END ve_ah[28]
  PIN ve_ah[29]
    DIRECTION OUTPUT ;
    USE SIGNAL ;
    PORT
      LAYER M5 ;
        RECT  118.368 172.716 118.392 172.8 ;
    END
  END ve_ah[29]
  PIN ve_ah[2]
    DIRECTION OUTPUT ;
    USE SIGNAL ;
    PORT
      LAYER M5 ;
        RECT  115.344 172.716 115.368 172.8 ;
    END
  END ve_ah[2]
  PIN ve_ah[30]
    DIRECTION OUTPUT ;
    USE SIGNAL ;
    PORT
      LAYER M5 ;
        RECT  119.184 172.716 119.208 172.8 ;
    END
  END ve_ah[30]
  PIN ve_ah[31]
    DIRECTION OUTPUT ;
    USE SIGNAL ;
    PORT
      LAYER M5 ;
        RECT  119.28 172.716 119.304 172.8 ;
    END
  END ve_ah[31]
  PIN ve_ah[32]
    DIRECTION OUTPUT ;
    USE SIGNAL ;
    PORT
      LAYER M5 ;
        RECT  119.376 172.716 119.4 172.8 ;
    END
  END ve_ah[32]
  PIN ve_ah[33]
    DIRECTION OUTPUT ;
    USE SIGNAL ;
    PORT
      LAYER M5 ;
        RECT  119.472 172.716 119.496 172.8 ;
    END
  END ve_ah[33]
  PIN ve_ah[34]
    DIRECTION OUTPUT ;
    USE SIGNAL ;
    PORT
      LAYER M5 ;
        RECT  119.568 172.716 119.592 172.8 ;
    END
  END ve_ah[34]
  PIN ve_ah[35]
    DIRECTION OUTPUT ;
    USE SIGNAL ;
    PORT
      LAYER M5 ;
        RECT  119.664 172.716 119.688 172.8 ;
    END
  END ve_ah[35]
  PIN ve_ah[36]
    DIRECTION OUTPUT ;
    USE SIGNAL ;
    PORT
      LAYER M5 ;
        RECT  119.76 172.716 119.784 172.8 ;
    END
  END ve_ah[36]
  PIN ve_ah[37]
    DIRECTION OUTPUT ;
    USE SIGNAL ;
    PORT
      LAYER M5 ;
        RECT  119.856 172.716 119.88 172.8 ;
    END
  END ve_ah[37]
  PIN ve_ah[38]
    DIRECTION OUTPUT ;
    USE SIGNAL ;
    PORT
      LAYER M5 ;
        RECT  119.952 172.716 119.976 172.8 ;
    END
  END ve_ah[38]
  PIN ve_ah[39]
    DIRECTION OUTPUT ;
    USE SIGNAL ;
    PORT
      LAYER M5 ;
        RECT  120.048 172.716 120.072 172.8 ;
    END
  END ve_ah[39]
  PIN ve_ah[3]
    DIRECTION OUTPUT ;
    USE SIGNAL ;
    PORT
      LAYER M5 ;
        RECT  115.44 172.716 115.464 172.8 ;
    END
  END ve_ah[3]
  PIN ve_ah[40]
    DIRECTION OUTPUT ;
    USE SIGNAL ;
    PORT
      LAYER M5 ;
        RECT  120.144 172.716 120.168 172.8 ;
    END
  END ve_ah[40]
  PIN ve_ah[41]
    DIRECTION OUTPUT ;
    USE SIGNAL ;
    PORT
      LAYER M5 ;
        RECT  120.24 172.716 120.264 172.8 ;
    END
  END ve_ah[41]
  PIN ve_ah[42]
    DIRECTION OUTPUT ;
    USE SIGNAL ;
    PORT
      LAYER M5 ;
        RECT  120.336 172.716 120.36 172.8 ;
    END
  END ve_ah[42]
  PIN ve_ah[43]
    DIRECTION OUTPUT ;
    USE SIGNAL ;
    PORT
      LAYER M5 ;
        RECT  120.432 172.716 120.456 172.8 ;
    END
  END ve_ah[43]
  PIN ve_ah[44]
    DIRECTION OUTPUT ;
    USE SIGNAL ;
    PORT
      LAYER M5 ;
        RECT  120.528 172.716 120.552 172.8 ;
    END
  END ve_ah[44]
  PIN ve_ah[45]
    DIRECTION OUTPUT ;
    USE SIGNAL ;
    PORT
      LAYER M5 ;
        RECT  120.624 172.716 120.648 172.8 ;
    END
  END ve_ah[45]
  PIN ve_ah[46]
    DIRECTION OUTPUT ;
    USE SIGNAL ;
    PORT
      LAYER M5 ;
        RECT  120.72 172.716 120.744 172.8 ;
    END
  END ve_ah[46]
  PIN ve_ah[47]
    DIRECTION OUTPUT ;
    USE SIGNAL ;
    PORT
      LAYER M5 ;
        RECT  120.816 172.716 120.84 172.8 ;
    END
  END ve_ah[47]
  PIN ve_ah[48]
    DIRECTION OUTPUT ;
    USE SIGNAL ;
    PORT
      LAYER M5 ;
        RECT  120.912 172.716 120.936 172.8 ;
    END
  END ve_ah[48]
  PIN ve_ah[49]
    DIRECTION OUTPUT ;
    USE SIGNAL ;
    PORT
      LAYER M5 ;
        RECT  121.008 172.716 121.032 172.8 ;
    END
  END ve_ah[49]
  PIN ve_ah[4]
    DIRECTION OUTPUT ;
    USE SIGNAL ;
    PORT
      LAYER M5 ;
        RECT  115.536 172.716 115.56 172.8 ;
    END
  END ve_ah[4]
  PIN ve_ah[50]
    DIRECTION OUTPUT ;
    USE SIGNAL ;
    PORT
      LAYER M5 ;
        RECT  121.152 172.716 121.176 172.8 ;
    END
  END ve_ah[50]
  PIN ve_ah[51]
    DIRECTION OUTPUT ;
    USE SIGNAL ;
    PORT
      LAYER M5 ;
        RECT  121.248 172.716 121.272 172.8 ;
    END
  END ve_ah[51]
  PIN ve_ah[52]
    DIRECTION OUTPUT ;
    USE SIGNAL ;
    PORT
      LAYER M5 ;
        RECT  121.344 172.716 121.368 172.8 ;
    END
  END ve_ah[52]
  PIN ve_ah[53]
    DIRECTION OUTPUT ;
    USE SIGNAL ;
    PORT
      LAYER M5 ;
        RECT  121.536 172.716 121.56 172.8 ;
    END
  END ve_ah[53]
  PIN ve_ah[54]
    DIRECTION OUTPUT ;
    USE SIGNAL ;
    PORT
      LAYER M5 ;
        RECT  121.632 172.716 121.656 172.8 ;
    END
  END ve_ah[54]
  PIN ve_ah[55]
    DIRECTION OUTPUT ;
    USE SIGNAL ;
    PORT
      LAYER M5 ;
        RECT  121.728 172.716 121.752 172.8 ;
    END
  END ve_ah[55]
  PIN ve_ah[56]
    DIRECTION OUTPUT ;
    USE SIGNAL ;
    PORT
      LAYER M5 ;
        RECT  121.92 172.716 121.944 172.8 ;
    END
  END ve_ah[56]
  PIN ve_ah[57]
    DIRECTION OUTPUT ;
    USE SIGNAL ;
    PORT
      LAYER M5 ;
        RECT  122.016 172.716 122.04 172.8 ;
    END
  END ve_ah[57]
  PIN ve_ah[58]
    DIRECTION OUTPUT ;
    USE SIGNAL ;
    PORT
      LAYER M5 ;
        RECT  122.112 172.716 122.136 172.8 ;
    END
  END ve_ah[58]
  PIN ve_ah[59]
    DIRECTION OUTPUT ;
    USE SIGNAL ;
    PORT
      LAYER M5 ;
        RECT  122.208 172.716 122.232 172.8 ;
    END
  END ve_ah[59]
  PIN ve_ah[5]
    DIRECTION OUTPUT ;
    USE SIGNAL ;
    PORT
      LAYER M5 ;
        RECT  115.632 172.716 115.656 172.8 ;
    END
  END ve_ah[5]
  PIN ve_ah[60]
    DIRECTION OUTPUT ;
    USE SIGNAL ;
    PORT
      LAYER M5 ;
        RECT  122.4 172.716 122.424 172.8 ;
    END
  END ve_ah[60]
  PIN ve_ah[61]
    DIRECTION OUTPUT ;
    USE SIGNAL ;
    PORT
      LAYER M5 ;
        RECT  122.496 172.716 122.52 172.8 ;
    END
  END ve_ah[61]
  PIN ve_ah[62]
    DIRECTION OUTPUT ;
    USE SIGNAL ;
    PORT
      LAYER M5 ;
        RECT  122.688 172.716 122.712 172.8 ;
    END
  END ve_ah[62]
  PIN ve_ah[63]
    DIRECTION OUTPUT ;
    USE SIGNAL ;
    PORT
      LAYER M5 ;
        RECT  122.784 172.716 122.808 172.8 ;
    END
  END ve_ah[63]
  PIN ve_ah[64]
    DIRECTION OUTPUT ;
    USE SIGNAL ;
    PORT
      LAYER M5 ;
        RECT  123.504 172.716 123.528 172.8 ;
    END
  END ve_ah[64]
  PIN ve_ah[65]
    DIRECTION OUTPUT ;
    USE SIGNAL ;
    PORT
      LAYER M5 ;
        RECT  123.6 172.716 123.624 172.8 ;
    END
  END ve_ah[65]
  PIN ve_ah[66]
    DIRECTION OUTPUT ;
    USE SIGNAL ;
    PORT
      LAYER M5 ;
        RECT  123.696 172.716 123.72 172.8 ;
    END
  END ve_ah[66]
  PIN ve_ah[67]
    DIRECTION OUTPUT ;
    USE SIGNAL ;
    PORT
      LAYER M5 ;
        RECT  123.792 172.716 123.816 172.8 ;
    END
  END ve_ah[67]
  PIN ve_ah[68]
    DIRECTION OUTPUT ;
    USE SIGNAL ;
    PORT
      LAYER M5 ;
        RECT  123.888 172.716 123.912 172.8 ;
    END
  END ve_ah[68]
  PIN ve_ah[69]
    DIRECTION OUTPUT ;
    USE SIGNAL ;
    PORT
      LAYER M5 ;
        RECT  123.984 172.716 124.008 172.8 ;
    END
  END ve_ah[69]
  PIN ve_ah[6]
    DIRECTION OUTPUT ;
    USE SIGNAL ;
    PORT
      LAYER M5 ;
        RECT  115.728 172.716 115.752 172.8 ;
    END
  END ve_ah[6]
  PIN ve_ah[70]
    DIRECTION OUTPUT ;
    USE SIGNAL ;
    PORT
      LAYER M5 ;
        RECT  124.08 172.716 124.104 172.8 ;
    END
  END ve_ah[70]
  PIN ve_ah[71]
    DIRECTION OUTPUT ;
    USE SIGNAL ;
    PORT
      LAYER M5 ;
        RECT  124.176 172.716 124.2 172.8 ;
    END
  END ve_ah[71]
  PIN ve_ah[72]
    DIRECTION OUTPUT ;
    USE SIGNAL ;
    PORT
      LAYER M5 ;
        RECT  124.272 172.716 124.296 172.8 ;
    END
  END ve_ah[72]
  PIN ve_ah[73]
    DIRECTION OUTPUT ;
    USE SIGNAL ;
    PORT
      LAYER M5 ;
        RECT  124.368 172.716 124.392 172.8 ;
    END
  END ve_ah[73]
  PIN ve_ah[74]
    DIRECTION OUTPUT ;
    USE SIGNAL ;
    PORT
      LAYER M5 ;
        RECT  124.464 172.716 124.488 172.8 ;
    END
  END ve_ah[74]
  PIN ve_ah[75]
    DIRECTION OUTPUT ;
    USE SIGNAL ;
    PORT
      LAYER M5 ;
        RECT  124.56 172.716 124.584 172.8 ;
    END
  END ve_ah[75]
  PIN ve_ah[76]
    DIRECTION OUTPUT ;
    USE SIGNAL ;
    PORT
      LAYER M5 ;
        RECT  124.656 172.716 124.68 172.8 ;
    END
  END ve_ah[76]
  PIN ve_ah[77]
    DIRECTION OUTPUT ;
    USE SIGNAL ;
    PORT
      LAYER M5 ;
        RECT  124.752 172.716 124.776 172.8 ;
    END
  END ve_ah[77]
  PIN ve_ah[78]
    DIRECTION OUTPUT ;
    USE SIGNAL ;
    PORT
      LAYER M5 ;
        RECT  124.848 172.716 124.872 172.8 ;
    END
  END ve_ah[78]
  PIN ve_ah[79]
    DIRECTION OUTPUT ;
    USE SIGNAL ;
    PORT
      LAYER M5 ;
        RECT  124.944 172.716 124.968 172.8 ;
    END
  END ve_ah[79]
  PIN ve_ah[7]
    DIRECTION OUTPUT ;
    USE SIGNAL ;
    PORT
      LAYER M5 ;
        RECT  115.824 172.716 115.848 172.8 ;
    END
  END ve_ah[7]
  PIN ve_ah[80]
    DIRECTION OUTPUT ;
    USE SIGNAL ;
    PORT
      LAYER M5 ;
        RECT  125.04 172.716 125.064 172.8 ;
    END
  END ve_ah[80]
  PIN ve_ah[81]
    DIRECTION OUTPUT ;
    USE SIGNAL ;
    PORT
      LAYER M5 ;
        RECT  125.136 172.716 125.16 172.8 ;
    END
  END ve_ah[81]
  PIN ve_ah[82]
    DIRECTION OUTPUT ;
    USE SIGNAL ;
    PORT
      LAYER M5 ;
        RECT  125.28 172.716 125.304 172.8 ;
    END
  END ve_ah[82]
  PIN ve_ah[83]
    DIRECTION OUTPUT ;
    USE SIGNAL ;
    PORT
      LAYER M5 ;
        RECT  125.376 172.716 125.4 172.8 ;
    END
  END ve_ah[83]
  PIN ve_ah[84]
    DIRECTION OUTPUT ;
    USE SIGNAL ;
    PORT
      LAYER M5 ;
        RECT  125.472 172.716 125.496 172.8 ;
    END
  END ve_ah[84]
  PIN ve_ah[85]
    DIRECTION OUTPUT ;
    USE SIGNAL ;
    PORT
      LAYER M5 ;
        RECT  125.664 172.716 125.688 172.8 ;
    END
  END ve_ah[85]
  PIN ve_ah[86]
    DIRECTION OUTPUT ;
    USE SIGNAL ;
    PORT
      LAYER M5 ;
        RECT  125.76 172.716 125.784 172.8 ;
    END
  END ve_ah[86]
  PIN ve_ah[87]
    DIRECTION OUTPUT ;
    USE SIGNAL ;
    PORT
      LAYER M5 ;
        RECT  125.952 172.716 125.976 172.8 ;
    END
  END ve_ah[87]
  PIN ve_ah[88]
    DIRECTION OUTPUT ;
    USE SIGNAL ;
    PORT
      LAYER M5 ;
        RECT  126.048 172.716 126.072 172.8 ;
    END
  END ve_ah[88]
  PIN ve_ah[89]
    DIRECTION OUTPUT ;
    USE SIGNAL ;
    PORT
      LAYER M5 ;
        RECT  126.144 172.716 126.168 172.8 ;
    END
  END ve_ah[89]
  PIN ve_ah[8]
    DIRECTION OUTPUT ;
    USE SIGNAL ;
    PORT
      LAYER M5 ;
        RECT  115.92 172.716 115.944 172.8 ;
    END
  END ve_ah[8]
  PIN ve_ah[90]
    DIRECTION OUTPUT ;
    USE SIGNAL ;
    PORT
      LAYER M5 ;
        RECT  126.336 172.716 126.36 172.8 ;
    END
  END ve_ah[90]
  PIN ve_ah[91]
    DIRECTION OUTPUT ;
    USE SIGNAL ;
    PORT
      LAYER M5 ;
        RECT  126.432 172.716 126.456 172.8 ;
    END
  END ve_ah[91]
  PIN ve_ah[92]
    DIRECTION OUTPUT ;
    USE SIGNAL ;
    PORT
      LAYER M5 ;
        RECT  126.528 172.716 126.552 172.8 ;
    END
  END ve_ah[92]
  PIN ve_ah[93]
    DIRECTION OUTPUT ;
    USE SIGNAL ;
    PORT
      LAYER M5 ;
        RECT  126.72 172.716 126.744 172.8 ;
    END
  END ve_ah[93]
  PIN ve_ah[94]
    DIRECTION OUTPUT ;
    USE SIGNAL ;
    PORT
      LAYER M5 ;
        RECT  126.816 172.716 126.84 172.8 ;
    END
  END ve_ah[94]
  PIN ve_ah[95]
    DIRECTION OUTPUT ;
    USE SIGNAL ;
    PORT
      LAYER M5 ;
        RECT  126.912 172.716 126.936 172.8 ;
    END
  END ve_ah[95]
  PIN ve_ah[96]
    DIRECTION OUTPUT ;
    USE SIGNAL ;
    PORT
      LAYER M5 ;
        RECT  127.104 172.716 127.128 172.8 ;
    END
  END ve_ah[96]
  PIN ve_ah[97]
    DIRECTION OUTPUT ;
    USE SIGNAL ;
    PORT
      LAYER M5 ;
        RECT  127.824 172.716 127.848 172.8 ;
    END
  END ve_ah[97]
  PIN ve_ah[98]
    DIRECTION OUTPUT ;
    USE SIGNAL ;
    PORT
      LAYER M5 ;
        RECT  127.92 172.716 127.944 172.8 ;
    END
  END ve_ah[98]
  PIN ve_ah[99]
    DIRECTION OUTPUT ;
    USE SIGNAL ;
    PORT
      LAYER M5 ;
        RECT  128.016 172.716 128.04 172.8 ;
    END
  END ve_ah[99]
  PIN ve_ah[9]
    DIRECTION OUTPUT ;
    USE SIGNAL ;
    PORT
      LAYER M5 ;
        RECT  116.016 172.716 116.04 172.8 ;
    END
  END ve_ah[9]
  PIN ve_av
    DIRECTION OUTPUT ;
    USE SIGNAL ;
    PORT
      LAYER M5 ;
        RECT  114.864 172.716 114.888 172.8 ;
    END
  END ve_av
  PIN ve_aval[0]
    DIRECTION OUTPUT ;
    USE SIGNAL ;
    PORT
      LAYER M5 ;
        RECT  131.232 172.716 131.256 172.8 ;
    END
  END ve_aval[0]
  PIN ve_aval[100]
    DIRECTION OUTPUT ;
    USE SIGNAL ;
    PORT
      LAYER M5 ;
        RECT  144.192 172.716 144.216 172.8 ;
    END
  END ve_aval[100]
  PIN ve_aval[101]
    DIRECTION OUTPUT ;
    USE SIGNAL ;
    PORT
      LAYER M5 ;
        RECT  144.288 172.716 144.312 172.8 ;
    END
  END ve_aval[101]
  PIN ve_aval[102]
    DIRECTION OUTPUT ;
    USE SIGNAL ;
    PORT
      LAYER M5 ;
        RECT  145.104 172.716 145.128 172.8 ;
    END
  END ve_aval[102]
  PIN ve_aval[103]
    DIRECTION OUTPUT ;
    USE SIGNAL ;
    PORT
      LAYER M5 ;
        RECT  145.2 172.716 145.224 172.8 ;
    END
  END ve_aval[103]
  PIN ve_aval[104]
    DIRECTION OUTPUT ;
    USE SIGNAL ;
    PORT
      LAYER M5 ;
        RECT  145.296 172.716 145.32 172.8 ;
    END
  END ve_aval[104]
  PIN ve_aval[105]
    DIRECTION OUTPUT ;
    USE SIGNAL ;
    PORT
      LAYER M5 ;
        RECT  145.392 172.716 145.416 172.8 ;
    END
  END ve_aval[105]
  PIN ve_aval[106]
    DIRECTION OUTPUT ;
    USE SIGNAL ;
    PORT
      LAYER M5 ;
        RECT  145.488 172.716 145.512 172.8 ;
    END
  END ve_aval[106]
  PIN ve_aval[107]
    DIRECTION OUTPUT ;
    USE SIGNAL ;
    PORT
      LAYER M5 ;
        RECT  145.584 172.716 145.608 172.8 ;
    END
  END ve_aval[107]
  PIN ve_aval[108]
    DIRECTION OUTPUT ;
    USE SIGNAL ;
    PORT
      LAYER M5 ;
        RECT  145.68 172.716 145.704 172.8 ;
    END
  END ve_aval[108]
  PIN ve_aval[109]
    DIRECTION OUTPUT ;
    USE SIGNAL ;
    PORT
      LAYER M5 ;
        RECT  145.776 172.716 145.8 172.8 ;
    END
  END ve_aval[109]
  PIN ve_aval[10]
    DIRECTION OUTPUT ;
    USE SIGNAL ;
    PORT
      LAYER M5 ;
        RECT  132.912 172.716 132.936 172.8 ;
    END
  END ve_aval[10]
  PIN ve_aval[110]
    DIRECTION OUTPUT ;
    USE SIGNAL ;
    PORT
      LAYER M5 ;
        RECT  145.872 172.716 145.896 172.8 ;
    END
  END ve_aval[110]
  PIN ve_aval[111]
    DIRECTION OUTPUT ;
    USE SIGNAL ;
    PORT
      LAYER M5 ;
        RECT  145.968 172.716 145.992 172.8 ;
    END
  END ve_aval[111]
  PIN ve_aval[112]
    DIRECTION OUTPUT ;
    USE SIGNAL ;
    PORT
      LAYER M5 ;
        RECT  146.064 172.716 146.088 172.8 ;
    END
  END ve_aval[112]
  PIN ve_aval[113]
    DIRECTION OUTPUT ;
    USE SIGNAL ;
    PORT
      LAYER M5 ;
        RECT  146.16 172.716 146.184 172.8 ;
    END
  END ve_aval[113]
  PIN ve_aval[114]
    DIRECTION OUTPUT ;
    USE SIGNAL ;
    PORT
      LAYER M5 ;
        RECT  146.256 172.716 146.28 172.8 ;
    END
  END ve_aval[114]
  PIN ve_aval[115]
    DIRECTION OUTPUT ;
    USE SIGNAL ;
    PORT
      LAYER M5 ;
        RECT  146.352 172.716 146.376 172.8 ;
    END
  END ve_aval[115]
  PIN ve_aval[116]
    DIRECTION OUTPUT ;
    USE SIGNAL ;
    PORT
      LAYER M5 ;
        RECT  146.448 172.716 146.472 172.8 ;
    END
  END ve_aval[116]
  PIN ve_aval[117]
    DIRECTION OUTPUT ;
    USE SIGNAL ;
    PORT
      LAYER M5 ;
        RECT  146.544 172.716 146.568 172.8 ;
    END
  END ve_aval[117]
  PIN ve_aval[118]
    DIRECTION OUTPUT ;
    USE SIGNAL ;
    PORT
      LAYER M5 ;
        RECT  146.64 172.716 146.664 172.8 ;
    END
  END ve_aval[118]
  PIN ve_aval[119]
    DIRECTION OUTPUT ;
    USE SIGNAL ;
    PORT
      LAYER M5 ;
        RECT  146.736 172.716 146.76 172.8 ;
    END
  END ve_aval[119]
  PIN ve_aval[11]
    DIRECTION OUTPUT ;
    USE SIGNAL ;
    PORT
      LAYER M5 ;
        RECT  133.008 172.716 133.032 172.8 ;
    END
  END ve_aval[11]
  PIN ve_aval[120]
    DIRECTION OUTPUT ;
    USE SIGNAL ;
    PORT
      LAYER M5 ;
        RECT  146.832 172.716 146.856 172.8 ;
    END
  END ve_aval[120]
  PIN ve_aval[121]
    DIRECTION OUTPUT ;
    USE SIGNAL ;
    PORT
      LAYER M5 ;
        RECT  146.928 172.716 146.952 172.8 ;
    END
  END ve_aval[121]
  PIN ve_aval[122]
    DIRECTION OUTPUT ;
    USE SIGNAL ;
    PORT
      LAYER M5 ;
        RECT  147.072 172.716 147.096 172.8 ;
    END
  END ve_aval[122]
  PIN ve_aval[123]
    DIRECTION OUTPUT ;
    USE SIGNAL ;
    PORT
      LAYER M5 ;
        RECT  147.168 172.716 147.192 172.8 ;
    END
  END ve_aval[123]
  PIN ve_aval[124]
    DIRECTION OUTPUT ;
    USE SIGNAL ;
    PORT
      LAYER M5 ;
        RECT  147.264 172.716 147.288 172.8 ;
    END
  END ve_aval[124]
  PIN ve_aval[125]
    DIRECTION OUTPUT ;
    USE SIGNAL ;
    PORT
      LAYER M5 ;
        RECT  147.36 172.716 147.384 172.8 ;
    END
  END ve_aval[125]
  PIN ve_aval[126]
    DIRECTION OUTPUT ;
    USE SIGNAL ;
    PORT
      LAYER M5 ;
        RECT  147.552 172.716 147.576 172.8 ;
    END
  END ve_aval[126]
  PIN ve_aval[127]
    DIRECTION OUTPUT ;
    USE SIGNAL ;
    PORT
      LAYER M5 ;
        RECT  147.648 172.716 147.672 172.8 ;
    END
  END ve_aval[127]
  PIN ve_aval[128]
    DIRECTION OUTPUT ;
    USE SIGNAL ;
    PORT
      LAYER M5 ;
        RECT  147.84 172.716 147.864 172.8 ;
    END
  END ve_aval[128]
  PIN ve_aval[129]
    DIRECTION OUTPUT ;
    USE SIGNAL ;
    PORT
      LAYER M5 ;
        RECT  147.936 172.716 147.96 172.8 ;
    END
  END ve_aval[129]
  PIN ve_aval[12]
    DIRECTION OUTPUT ;
    USE SIGNAL ;
    PORT
      LAYER M5 ;
        RECT  133.104 172.716 133.128 172.8 ;
    END
  END ve_aval[12]
  PIN ve_aval[130]
    DIRECTION OUTPUT ;
    USE SIGNAL ;
    PORT
      LAYER M5 ;
        RECT  148.032 172.716 148.056 172.8 ;
    END
  END ve_aval[130]
  PIN ve_aval[131]
    DIRECTION OUTPUT ;
    USE SIGNAL ;
    PORT
      LAYER M5 ;
        RECT  148.128 172.716 148.152 172.8 ;
    END
  END ve_aval[131]
  PIN ve_aval[132]
    DIRECTION OUTPUT ;
    USE SIGNAL ;
    PORT
      LAYER M5 ;
        RECT  148.32 172.716 148.344 172.8 ;
    END
  END ve_aval[132]
  PIN ve_aval[133]
    DIRECTION OUTPUT ;
    USE SIGNAL ;
    PORT
      LAYER M5 ;
        RECT  148.416 172.716 148.44 172.8 ;
    END
  END ve_aval[133]
  PIN ve_aval[134]
    DIRECTION OUTPUT ;
    USE SIGNAL ;
    PORT
      LAYER M5 ;
        RECT  148.608 172.716 148.632 172.8 ;
    END
  END ve_aval[134]
  PIN ve_aval[135]
    DIRECTION OUTPUT ;
    USE SIGNAL ;
    PORT
      LAYER M5 ;
        RECT  148.704 172.716 148.728 172.8 ;
    END
  END ve_aval[135]
  PIN ve_aval[136]
    DIRECTION OUTPUT ;
    USE SIGNAL ;
    PORT
      LAYER M5 ;
        RECT  149.424 172.716 149.448 172.8 ;
    END
  END ve_aval[136]
  PIN ve_aval[137]
    DIRECTION OUTPUT ;
    USE SIGNAL ;
    PORT
      LAYER M5 ;
        RECT  149.52 172.716 149.544 172.8 ;
    END
  END ve_aval[137]
  PIN ve_aval[138]
    DIRECTION OUTPUT ;
    USE SIGNAL ;
    PORT
      LAYER M5 ;
        RECT  149.616 172.716 149.64 172.8 ;
    END
  END ve_aval[138]
  PIN ve_aval[139]
    DIRECTION OUTPUT ;
    USE SIGNAL ;
    PORT
      LAYER M5 ;
        RECT  149.712 172.716 149.736 172.8 ;
    END
  END ve_aval[139]
  PIN ve_aval[13]
    DIRECTION OUTPUT ;
    USE SIGNAL ;
    PORT
      LAYER M5 ;
        RECT  133.2 172.716 133.224 172.8 ;
    END
  END ve_aval[13]
  PIN ve_aval[140]
    DIRECTION OUTPUT ;
    USE SIGNAL ;
    PORT
      LAYER M5 ;
        RECT  149.808 172.716 149.832 172.8 ;
    END
  END ve_aval[140]
  PIN ve_aval[141]
    DIRECTION OUTPUT ;
    USE SIGNAL ;
    PORT
      LAYER M5 ;
        RECT  149.904 172.716 149.928 172.8 ;
    END
  END ve_aval[141]
  PIN ve_aval[142]
    DIRECTION OUTPUT ;
    USE SIGNAL ;
    PORT
      LAYER M5 ;
        RECT  150 172.716 150.024 172.8 ;
    END
  END ve_aval[142]
  PIN ve_aval[143]
    DIRECTION OUTPUT ;
    USE SIGNAL ;
    PORT
      LAYER M5 ;
        RECT  150.096 172.716 150.12 172.8 ;
    END
  END ve_aval[143]
  PIN ve_aval[144]
    DIRECTION OUTPUT ;
    USE SIGNAL ;
    PORT
      LAYER M5 ;
        RECT  150.192 172.716 150.216 172.8 ;
    END
  END ve_aval[144]
  PIN ve_aval[145]
    DIRECTION OUTPUT ;
    USE SIGNAL ;
    PORT
      LAYER M5 ;
        RECT  150.288 172.716 150.312 172.8 ;
    END
  END ve_aval[145]
  PIN ve_aval[146]
    DIRECTION OUTPUT ;
    USE SIGNAL ;
    PORT
      LAYER M5 ;
        RECT  150.384 172.716 150.408 172.8 ;
    END
  END ve_aval[146]
  PIN ve_aval[147]
    DIRECTION OUTPUT ;
    USE SIGNAL ;
    PORT
      LAYER M5 ;
        RECT  150.48 172.716 150.504 172.8 ;
    END
  END ve_aval[147]
  PIN ve_aval[148]
    DIRECTION OUTPUT ;
    USE SIGNAL ;
    PORT
      LAYER M5 ;
        RECT  150.576 172.716 150.6 172.8 ;
    END
  END ve_aval[148]
  PIN ve_aval[149]
    DIRECTION OUTPUT ;
    USE SIGNAL ;
    PORT
      LAYER M5 ;
        RECT  150.672 172.716 150.696 172.8 ;
    END
  END ve_aval[149]
  PIN ve_aval[14]
    DIRECTION OUTPUT ;
    USE SIGNAL ;
    PORT
      LAYER M5 ;
        RECT  133.296 172.716 133.32 172.8 ;
    END
  END ve_aval[14]
  PIN ve_aval[150]
    DIRECTION OUTPUT ;
    USE SIGNAL ;
    PORT
      LAYER M5 ;
        RECT  150.768 172.716 150.792 172.8 ;
    END
  END ve_aval[150]
  PIN ve_aval[151]
    DIRECTION OUTPUT ;
    USE SIGNAL ;
    PORT
      LAYER M5 ;
        RECT  150.864 172.716 150.888 172.8 ;
    END
  END ve_aval[151]
  PIN ve_aval[152]
    DIRECTION OUTPUT ;
    USE SIGNAL ;
    PORT
      LAYER M5 ;
        RECT  150.96 172.716 150.984 172.8 ;
    END
  END ve_aval[152]
  PIN ve_aval[153]
    DIRECTION OUTPUT ;
    USE SIGNAL ;
    PORT
      LAYER M5 ;
        RECT  151.056 172.716 151.08 172.8 ;
    END
  END ve_aval[153]
  PIN ve_aval[154]
    DIRECTION OUTPUT ;
    USE SIGNAL ;
    PORT
      LAYER M5 ;
        RECT  151.2 172.716 151.224 172.8 ;
    END
  END ve_aval[154]
  PIN ve_aval[155]
    DIRECTION OUTPUT ;
    USE SIGNAL ;
    PORT
      LAYER M5 ;
        RECT  151.296 172.716 151.32 172.8 ;
    END
  END ve_aval[155]
  PIN ve_aval[156]
    DIRECTION OUTPUT ;
    USE SIGNAL ;
    PORT
      LAYER M5 ;
        RECT  151.392 172.716 151.416 172.8 ;
    END
  END ve_aval[156]
  PIN ve_aval[157]
    DIRECTION OUTPUT ;
    USE SIGNAL ;
    PORT
      LAYER M5 ;
        RECT  151.584 172.716 151.608 172.8 ;
    END
  END ve_aval[157]
  PIN ve_aval[158]
    DIRECTION OUTPUT ;
    USE SIGNAL ;
    PORT
      LAYER M5 ;
        RECT  151.68 172.716 151.704 172.8 ;
    END
  END ve_aval[158]
  PIN ve_aval[159]
    DIRECTION OUTPUT ;
    USE SIGNAL ;
    PORT
      LAYER M5 ;
        RECT  151.872 172.716 151.896 172.8 ;
    END
  END ve_aval[159]
  PIN ve_aval[15]
    DIRECTION OUTPUT ;
    USE SIGNAL ;
    PORT
      LAYER M5 ;
        RECT  133.392 172.716 133.416 172.8 ;
    END
  END ve_aval[15]
  PIN ve_aval[160]
    DIRECTION OUTPUT ;
    USE SIGNAL ;
    PORT
      LAYER M5 ;
        RECT  151.968 172.716 151.992 172.8 ;
    END
  END ve_aval[160]
  PIN ve_aval[161]
    DIRECTION OUTPUT ;
    USE SIGNAL ;
    PORT
      LAYER M5 ;
        RECT  152.064 172.716 152.088 172.8 ;
    END
  END ve_aval[161]
  PIN ve_aval[162]
    DIRECTION OUTPUT ;
    USE SIGNAL ;
    PORT
      LAYER M5 ;
        RECT  152.16 172.716 152.184 172.8 ;
    END
  END ve_aval[162]
  PIN ve_aval[163]
    DIRECTION OUTPUT ;
    USE SIGNAL ;
    PORT
      LAYER M5 ;
        RECT  152.352 172.716 152.376 172.8 ;
    END
  END ve_aval[163]
  PIN ve_aval[164]
    DIRECTION OUTPUT ;
    USE SIGNAL ;
    PORT
      LAYER M5 ;
        RECT  152.448 172.716 152.472 172.8 ;
    END
  END ve_aval[164]
  PIN ve_aval[165]
    DIRECTION OUTPUT ;
    USE SIGNAL ;
    PORT
      LAYER M5 ;
        RECT  152.544 172.716 152.568 172.8 ;
    END
  END ve_aval[165]
  PIN ve_aval[166]
    DIRECTION OUTPUT ;
    USE SIGNAL ;
    PORT
      LAYER M5 ;
        RECT  152.736 172.716 152.76 172.8 ;
    END
  END ve_aval[166]
  PIN ve_aval[167]
    DIRECTION OUTPUT ;
    USE SIGNAL ;
    PORT
      LAYER M5 ;
        RECT  152.832 172.716 152.856 172.8 ;
    END
  END ve_aval[167]
  PIN ve_aval[168]
    DIRECTION OUTPUT ;
    USE SIGNAL ;
    PORT
      LAYER M5 ;
        RECT  153.024 172.716 153.048 172.8 ;
    END
  END ve_aval[168]
  PIN ve_aval[169]
    DIRECTION OUTPUT ;
    USE SIGNAL ;
    PORT
      LAYER M5 ;
        RECT  153.744 172.716 153.768 172.8 ;
    END
  END ve_aval[169]
  PIN ve_aval[16]
    DIRECTION OUTPUT ;
    USE SIGNAL ;
    PORT
      LAYER M5 ;
        RECT  133.488 172.716 133.512 172.8 ;
    END
  END ve_aval[16]
  PIN ve_aval[170]
    DIRECTION OUTPUT ;
    USE SIGNAL ;
    PORT
      LAYER M5 ;
        RECT  153.84 172.716 153.864 172.8 ;
    END
  END ve_aval[170]
  PIN ve_aval[171]
    DIRECTION OUTPUT ;
    USE SIGNAL ;
    PORT
      LAYER M5 ;
        RECT  153.936 172.716 153.96 172.8 ;
    END
  END ve_aval[171]
  PIN ve_aval[172]
    DIRECTION OUTPUT ;
    USE SIGNAL ;
    PORT
      LAYER M5 ;
        RECT  154.032 172.716 154.056 172.8 ;
    END
  END ve_aval[172]
  PIN ve_aval[173]
    DIRECTION OUTPUT ;
    USE SIGNAL ;
    PORT
      LAYER M5 ;
        RECT  154.128 172.716 154.152 172.8 ;
    END
  END ve_aval[173]
  PIN ve_aval[174]
    DIRECTION OUTPUT ;
    USE SIGNAL ;
    PORT
      LAYER M5 ;
        RECT  154.224 172.716 154.248 172.8 ;
    END
  END ve_aval[174]
  PIN ve_aval[175]
    DIRECTION OUTPUT ;
    USE SIGNAL ;
    PORT
      LAYER M5 ;
        RECT  154.32 172.716 154.344 172.8 ;
    END
  END ve_aval[175]
  PIN ve_aval[176]
    DIRECTION OUTPUT ;
    USE SIGNAL ;
    PORT
      LAYER M5 ;
        RECT  154.416 172.716 154.44 172.8 ;
    END
  END ve_aval[176]
  PIN ve_aval[177]
    DIRECTION OUTPUT ;
    USE SIGNAL ;
    PORT
      LAYER M5 ;
        RECT  154.512 172.716 154.536 172.8 ;
    END
  END ve_aval[177]
  PIN ve_aval[178]
    DIRECTION OUTPUT ;
    USE SIGNAL ;
    PORT
      LAYER M5 ;
        RECT  154.608 172.716 154.632 172.8 ;
    END
  END ve_aval[178]
  PIN ve_aval[179]
    DIRECTION OUTPUT ;
    USE SIGNAL ;
    PORT
      LAYER M5 ;
        RECT  154.704 172.716 154.728 172.8 ;
    END
  END ve_aval[179]
  PIN ve_aval[17]
    DIRECTION OUTPUT ;
    USE SIGNAL ;
    PORT
      LAYER M5 ;
        RECT  133.584 172.716 133.608 172.8 ;
    END
  END ve_aval[17]
  PIN ve_aval[180]
    DIRECTION OUTPUT ;
    USE SIGNAL ;
    PORT
      LAYER M5 ;
        RECT  154.8 172.716 154.824 172.8 ;
    END
  END ve_aval[180]
  PIN ve_aval[181]
    DIRECTION OUTPUT ;
    USE SIGNAL ;
    PORT
      LAYER M5 ;
        RECT  154.896 172.716 154.92 172.8 ;
    END
  END ve_aval[181]
  PIN ve_aval[182]
    DIRECTION OUTPUT ;
    USE SIGNAL ;
    PORT
      LAYER M5 ;
        RECT  154.992 172.716 155.016 172.8 ;
    END
  END ve_aval[182]
  PIN ve_aval[183]
    DIRECTION OUTPUT ;
    USE SIGNAL ;
    PORT
      LAYER M5 ;
        RECT  155.088 172.716 155.112 172.8 ;
    END
  END ve_aval[183]
  PIN ve_aval[184]
    DIRECTION OUTPUT ;
    USE SIGNAL ;
    PORT
      LAYER M5 ;
        RECT  155.184 172.716 155.208 172.8 ;
    END
  END ve_aval[184]
  PIN ve_aval[185]
    DIRECTION OUTPUT ;
    USE SIGNAL ;
    PORT
      LAYER M5 ;
        RECT  155.28 172.716 155.304 172.8 ;
    END
  END ve_aval[185]
  PIN ve_aval[186]
    DIRECTION OUTPUT ;
    USE SIGNAL ;
    PORT
      LAYER M5 ;
        RECT  155.376 172.716 155.4 172.8 ;
    END
  END ve_aval[186]
  PIN ve_aval[187]
    DIRECTION OUTPUT ;
    USE SIGNAL ;
    PORT
      LAYER M5 ;
        RECT  155.472 172.716 155.496 172.8 ;
    END
  END ve_aval[187]
  PIN ve_aval[188]
    DIRECTION OUTPUT ;
    USE SIGNAL ;
    PORT
      LAYER M5 ;
        RECT  155.616 172.716 155.64 172.8 ;
    END
  END ve_aval[188]
  PIN ve_aval[189]
    DIRECTION OUTPUT ;
    USE SIGNAL ;
    PORT
      LAYER M5 ;
        RECT  155.712 172.716 155.736 172.8 ;
    END
  END ve_aval[189]
  PIN ve_aval[18]
    DIRECTION OUTPUT ;
    USE SIGNAL ;
    PORT
      LAYER M5 ;
        RECT  133.68 172.716 133.704 172.8 ;
    END
  END ve_aval[18]
  PIN ve_aval[190]
    DIRECTION OUTPUT ;
    USE SIGNAL ;
    PORT
      LAYER M5 ;
        RECT  155.808 172.716 155.832 172.8 ;
    END
  END ve_aval[190]
  PIN ve_aval[191]
    DIRECTION OUTPUT ;
    USE SIGNAL ;
    PORT
      LAYER M5 ;
        RECT  155.904 172.716 155.928 172.8 ;
    END
  END ve_aval[191]
  PIN ve_aval[192]
    DIRECTION OUTPUT ;
    USE SIGNAL ;
    PORT
      LAYER M5 ;
        RECT  156.096 172.716 156.12 172.8 ;
    END
  END ve_aval[192]
  PIN ve_aval[193]
    DIRECTION OUTPUT ;
    USE SIGNAL ;
    PORT
      LAYER M5 ;
        RECT  156.192 172.716 156.216 172.8 ;
    END
  END ve_aval[193]
  PIN ve_aval[194]
    DIRECTION OUTPUT ;
    USE SIGNAL ;
    PORT
      LAYER M5 ;
        RECT  156.384 172.716 156.408 172.8 ;
    END
  END ve_aval[194]
  PIN ve_aval[195]
    DIRECTION OUTPUT ;
    USE SIGNAL ;
    PORT
      LAYER M5 ;
        RECT  156.48 172.716 156.504 172.8 ;
    END
  END ve_aval[195]
  PIN ve_aval[196]
    DIRECTION OUTPUT ;
    USE SIGNAL ;
    PORT
      LAYER M5 ;
        RECT  156.576 172.716 156.6 172.8 ;
    END
  END ve_aval[196]
  PIN ve_aval[197]
    DIRECTION OUTPUT ;
    USE SIGNAL ;
    PORT
      LAYER M5 ;
        RECT  156.768 172.716 156.792 172.8 ;
    END
  END ve_aval[197]
  PIN ve_aval[198]
    DIRECTION OUTPUT ;
    USE SIGNAL ;
    PORT
      LAYER M5 ;
        RECT  156.864 172.716 156.888 172.8 ;
    END
  END ve_aval[198]
  PIN ve_aval[199]
    DIRECTION OUTPUT ;
    USE SIGNAL ;
    PORT
      LAYER M5 ;
        RECT  157.056 172.716 157.08 172.8 ;
    END
  END ve_aval[199]
  PIN ve_aval[19]
    DIRECTION OUTPUT ;
    USE SIGNAL ;
    PORT
      LAYER M5 ;
        RECT  133.776 172.716 133.8 172.8 ;
    END
  END ve_aval[19]
  PIN ve_aval[1]
    DIRECTION OUTPUT ;
    USE SIGNAL ;
    PORT
      LAYER M5 ;
        RECT  131.328 172.716 131.352 172.8 ;
    END
  END ve_aval[1]
  PIN ve_aval[200]
    DIRECTION OUTPUT ;
    USE SIGNAL ;
    PORT
      LAYER M5 ;
        RECT  157.152 172.716 157.176 172.8 ;
    END
  END ve_aval[200]
  PIN ve_aval[201]
    DIRECTION OUTPUT ;
    USE SIGNAL ;
    PORT
      LAYER M5 ;
        RECT  157.248 172.716 157.272 172.8 ;
    END
  END ve_aval[201]
  PIN ve_aval[202]
    DIRECTION OUTPUT ;
    USE SIGNAL ;
    PORT
      LAYER M5 ;
        RECT  157.344 172.716 157.368 172.8 ;
    END
  END ve_aval[202]
  PIN ve_aval[203]
    DIRECTION OUTPUT ;
    USE SIGNAL ;
    PORT
      LAYER M5 ;
        RECT  158.064 172.716 158.088 172.8 ;
    END
  END ve_aval[203]
  PIN ve_aval[204]
    DIRECTION OUTPUT ;
    USE SIGNAL ;
    PORT
      LAYER M5 ;
        RECT  158.16 172.716 158.184 172.8 ;
    END
  END ve_aval[204]
  PIN ve_aval[205]
    DIRECTION OUTPUT ;
    USE SIGNAL ;
    PORT
      LAYER M5 ;
        RECT  158.256 172.716 158.28 172.8 ;
    END
  END ve_aval[205]
  PIN ve_aval[206]
    DIRECTION OUTPUT ;
    USE SIGNAL ;
    PORT
      LAYER M5 ;
        RECT  158.352 172.716 158.376 172.8 ;
    END
  END ve_aval[206]
  PIN ve_aval[207]
    DIRECTION OUTPUT ;
    USE SIGNAL ;
    PORT
      LAYER M5 ;
        RECT  158.448 172.716 158.472 172.8 ;
    END
  END ve_aval[207]
  PIN ve_aval[208]
    DIRECTION OUTPUT ;
    USE SIGNAL ;
    PORT
      LAYER M5 ;
        RECT  158.544 172.716 158.568 172.8 ;
    END
  END ve_aval[208]
  PIN ve_aval[209]
    DIRECTION OUTPUT ;
    USE SIGNAL ;
    PORT
      LAYER M5 ;
        RECT  158.64 172.716 158.664 172.8 ;
    END
  END ve_aval[209]
  PIN ve_aval[20]
    DIRECTION OUTPUT ;
    USE SIGNAL ;
    PORT
      LAYER M5 ;
        RECT  133.872 172.716 133.896 172.8 ;
    END
  END ve_aval[20]
  PIN ve_aval[210]
    DIRECTION OUTPUT ;
    USE SIGNAL ;
    PORT
      LAYER M5 ;
        RECT  158.736 172.716 158.76 172.8 ;
    END
  END ve_aval[210]
  PIN ve_aval[211]
    DIRECTION OUTPUT ;
    USE SIGNAL ;
    PORT
      LAYER M5 ;
        RECT  158.832 172.716 158.856 172.8 ;
    END
  END ve_aval[211]
  PIN ve_aval[212]
    DIRECTION OUTPUT ;
    USE SIGNAL ;
    PORT
      LAYER M5 ;
        RECT  158.928 172.716 158.952 172.8 ;
    END
  END ve_aval[212]
  PIN ve_aval[213]
    DIRECTION OUTPUT ;
    USE SIGNAL ;
    PORT
      LAYER M5 ;
        RECT  159.024 172.716 159.048 172.8 ;
    END
  END ve_aval[213]
  PIN ve_aval[214]
    DIRECTION OUTPUT ;
    USE SIGNAL ;
    PORT
      LAYER M5 ;
        RECT  159.12 172.716 159.144 172.8 ;
    END
  END ve_aval[214]
  PIN ve_aval[215]
    DIRECTION OUTPUT ;
    USE SIGNAL ;
    PORT
      LAYER M5 ;
        RECT  159.216 172.716 159.24 172.8 ;
    END
  END ve_aval[215]
  PIN ve_aval[216]
    DIRECTION OUTPUT ;
    USE SIGNAL ;
    PORT
      LAYER M5 ;
        RECT  159.312 172.716 159.336 172.8 ;
    END
  END ve_aval[216]
  PIN ve_aval[217]
    DIRECTION OUTPUT ;
    USE SIGNAL ;
    PORT
      LAYER M5 ;
        RECT  159.408 172.716 159.432 172.8 ;
    END
  END ve_aval[217]
  PIN ve_aval[218]
    DIRECTION OUTPUT ;
    USE SIGNAL ;
    PORT
      LAYER M5 ;
        RECT  159.504 172.716 159.528 172.8 ;
    END
  END ve_aval[218]
  PIN ve_aval[219]
    DIRECTION OUTPUT ;
    USE SIGNAL ;
    PORT
      LAYER M5 ;
        RECT  159.648 172.716 159.672 172.8 ;
    END
  END ve_aval[219]
  PIN ve_aval[21]
    DIRECTION OUTPUT ;
    USE SIGNAL ;
    PORT
      LAYER M5 ;
        RECT  133.968 172.716 133.992 172.8 ;
    END
  END ve_aval[21]
  PIN ve_aval[220]
    DIRECTION OUTPUT ;
    USE SIGNAL ;
    PORT
      LAYER M5 ;
        RECT  159.744 172.716 159.768 172.8 ;
    END
  END ve_aval[220]
  PIN ve_aval[221]
    DIRECTION OUTPUT ;
    USE SIGNAL ;
    PORT
      LAYER M5 ;
        RECT  159.84 172.716 159.864 172.8 ;
    END
  END ve_aval[221]
  PIN ve_aval[222]
    DIRECTION OUTPUT ;
    USE SIGNAL ;
    PORT
      LAYER M5 ;
        RECT  159.936 172.716 159.96 172.8 ;
    END
  END ve_aval[222]
  PIN ve_aval[223]
    DIRECTION OUTPUT ;
    USE SIGNAL ;
    PORT
      LAYER M5 ;
        RECT  160.128 172.716 160.152 172.8 ;
    END
  END ve_aval[223]
  PIN ve_aval[224]
    DIRECTION OUTPUT ;
    USE SIGNAL ;
    PORT
      LAYER M5 ;
        RECT  160.224 172.716 160.248 172.8 ;
    END
  END ve_aval[224]
  PIN ve_aval[225]
    DIRECTION OUTPUT ;
    USE SIGNAL ;
    PORT
      LAYER M5 ;
        RECT  160.32 172.716 160.344 172.8 ;
    END
  END ve_aval[225]
  PIN ve_aval[226]
    DIRECTION OUTPUT ;
    USE SIGNAL ;
    PORT
      LAYER M5 ;
        RECT  160.512 172.716 160.536 172.8 ;
    END
  END ve_aval[226]
  PIN ve_aval[227]
    DIRECTION OUTPUT ;
    USE SIGNAL ;
    PORT
      LAYER M5 ;
        RECT  160.608 172.716 160.632 172.8 ;
    END
  END ve_aval[227]
  PIN ve_aval[228]
    DIRECTION OUTPUT ;
    USE SIGNAL ;
    PORT
      LAYER M5 ;
        RECT  160.8 172.716 160.824 172.8 ;
    END
  END ve_aval[228]
  PIN ve_aval[229]
    DIRECTION OUTPUT ;
    USE SIGNAL ;
    PORT
      LAYER M5 ;
        RECT  160.896 172.716 160.92 172.8 ;
    END
  END ve_aval[229]
  PIN ve_aval[22]
    DIRECTION OUTPUT ;
    USE SIGNAL ;
    PORT
      LAYER M5 ;
        RECT  134.112 172.716 134.136 172.8 ;
    END
  END ve_aval[22]
  PIN ve_aval[230]
    DIRECTION OUTPUT ;
    USE SIGNAL ;
    PORT
      LAYER M5 ;
        RECT  160.992 172.716 161.016 172.8 ;
    END
  END ve_aval[230]
  PIN ve_aval[231]
    DIRECTION OUTPUT ;
    USE SIGNAL ;
    PORT
      LAYER M5 ;
        RECT  161.088 172.716 161.112 172.8 ;
    END
  END ve_aval[231]
  PIN ve_aval[232]
    DIRECTION OUTPUT ;
    USE SIGNAL ;
    PORT
      LAYER M5 ;
        RECT  161.28 172.716 161.304 172.8 ;
    END
  END ve_aval[232]
  PIN ve_aval[233]
    DIRECTION OUTPUT ;
    USE SIGNAL ;
    PORT
      LAYER M5 ;
        RECT  161.376 172.716 161.4 172.8 ;
    END
  END ve_aval[233]
  PIN ve_aval[234]
    DIRECTION OUTPUT ;
    USE SIGNAL ;
    PORT
      LAYER M5 ;
        RECT  161.568 172.716 161.592 172.8 ;
    END
  END ve_aval[234]
  PIN ve_aval[235]
    DIRECTION OUTPUT ;
    USE SIGNAL ;
    PORT
      LAYER M5 ;
        RECT  161.664 172.716 161.688 172.8 ;
    END
  END ve_aval[235]
  PIN ve_aval[236]
    DIRECTION OUTPUT ;
    USE SIGNAL ;
    PORT
      LAYER M5 ;
        RECT  162.384 172.716 162.408 172.8 ;
    END
  END ve_aval[236]
  PIN ve_aval[237]
    DIRECTION OUTPUT ;
    USE SIGNAL ;
    PORT
      LAYER M5 ;
        RECT  162.48 172.716 162.504 172.8 ;
    END
  END ve_aval[237]
  PIN ve_aval[238]
    DIRECTION OUTPUT ;
    USE SIGNAL ;
    PORT
      LAYER M5 ;
        RECT  162.576 172.716 162.6 172.8 ;
    END
  END ve_aval[238]
  PIN ve_aval[239]
    DIRECTION OUTPUT ;
    USE SIGNAL ;
    PORT
      LAYER M5 ;
        RECT  162.672 172.716 162.696 172.8 ;
    END
  END ve_aval[239]
  PIN ve_aval[23]
    DIRECTION OUTPUT ;
    USE SIGNAL ;
    PORT
      LAYER M5 ;
        RECT  134.208 172.716 134.232 172.8 ;
    END
  END ve_aval[23]
  PIN ve_aval[240]
    DIRECTION OUTPUT ;
    USE SIGNAL ;
    PORT
      LAYER M5 ;
        RECT  162.768 172.716 162.792 172.8 ;
    END
  END ve_aval[240]
  PIN ve_aval[241]
    DIRECTION OUTPUT ;
    USE SIGNAL ;
    PORT
      LAYER M5 ;
        RECT  162.864 172.716 162.888 172.8 ;
    END
  END ve_aval[241]
  PIN ve_aval[242]
    DIRECTION OUTPUT ;
    USE SIGNAL ;
    PORT
      LAYER M5 ;
        RECT  162.96 172.716 162.984 172.8 ;
    END
  END ve_aval[242]
  PIN ve_aval[243]
    DIRECTION OUTPUT ;
    USE SIGNAL ;
    PORT
      LAYER M5 ;
        RECT  163.056 172.716 163.08 172.8 ;
    END
  END ve_aval[243]
  PIN ve_aval[244]
    DIRECTION OUTPUT ;
    USE SIGNAL ;
    PORT
      LAYER M5 ;
        RECT  163.152 172.716 163.176 172.8 ;
    END
  END ve_aval[244]
  PIN ve_aval[245]
    DIRECTION OUTPUT ;
    USE SIGNAL ;
    PORT
      LAYER M5 ;
        RECT  163.248 172.716 163.272 172.8 ;
    END
  END ve_aval[245]
  PIN ve_aval[246]
    DIRECTION OUTPUT ;
    USE SIGNAL ;
    PORT
      LAYER M5 ;
        RECT  163.344 172.716 163.368 172.8 ;
    END
  END ve_aval[246]
  PIN ve_aval[247]
    DIRECTION OUTPUT ;
    USE SIGNAL ;
    PORT
      LAYER M5 ;
        RECT  163.44 172.716 163.464 172.8 ;
    END
  END ve_aval[247]
  PIN ve_aval[248]
    DIRECTION OUTPUT ;
    USE SIGNAL ;
    PORT
      LAYER M5 ;
        RECT  163.536 172.716 163.56 172.8 ;
    END
  END ve_aval[248]
  PIN ve_aval[249]
    DIRECTION OUTPUT ;
    USE SIGNAL ;
    PORT
      LAYER M5 ;
        RECT  163.632 172.716 163.656 172.8 ;
    END
  END ve_aval[249]
  PIN ve_aval[24]
    DIRECTION OUTPUT ;
    USE SIGNAL ;
    PORT
      LAYER M5 ;
        RECT  134.304 172.716 134.328 172.8 ;
    END
  END ve_aval[24]
  PIN ve_aval[250]
    DIRECTION OUTPUT ;
    USE SIGNAL ;
    PORT
      LAYER M5 ;
        RECT  163.728 172.716 163.752 172.8 ;
    END
  END ve_aval[250]
  PIN ve_aval[251]
    DIRECTION OUTPUT ;
    USE SIGNAL ;
    PORT
      LAYER M5 ;
        RECT  163.824 172.716 163.848 172.8 ;
    END
  END ve_aval[251]
  PIN ve_aval[252]
    DIRECTION OUTPUT ;
    USE SIGNAL ;
    PORT
      LAYER M5 ;
        RECT  163.92 172.716 163.944 172.8 ;
    END
  END ve_aval[252]
  PIN ve_aval[253]
    DIRECTION OUTPUT ;
    USE SIGNAL ;
    PORT
      LAYER M5 ;
        RECT  164.016 172.716 164.04 172.8 ;
    END
  END ve_aval[253]
  PIN ve_aval[254]
    DIRECTION OUTPUT ;
    USE SIGNAL ;
    PORT
      LAYER M5 ;
        RECT  164.16 172.716 164.184 172.8 ;
    END
  END ve_aval[254]
  PIN ve_aval[255]
    DIRECTION OUTPUT ;
    USE SIGNAL ;
    PORT
      LAYER M5 ;
        RECT  164.256 172.716 164.28 172.8 ;
    END
  END ve_aval[255]
  PIN ve_aval[25]
    DIRECTION OUTPUT ;
    USE SIGNAL ;
    PORT
      LAYER M5 ;
        RECT  134.4 172.716 134.424 172.8 ;
    END
  END ve_aval[25]
  PIN ve_aval[26]
    DIRECTION OUTPUT ;
    USE SIGNAL ;
    PORT
      LAYER M5 ;
        RECT  134.592 172.716 134.616 172.8 ;
    END
  END ve_aval[26]
  PIN ve_aval[27]
    DIRECTION OUTPUT ;
    USE SIGNAL ;
    PORT
      LAYER M5 ;
        RECT  134.688 172.716 134.712 172.8 ;
    END
  END ve_aval[27]
  PIN ve_aval[28]
    DIRECTION OUTPUT ;
    USE SIGNAL ;
    PORT
      LAYER M5 ;
        RECT  134.88 172.716 134.904 172.8 ;
    END
  END ve_aval[28]
  PIN ve_aval[29]
    DIRECTION OUTPUT ;
    USE SIGNAL ;
    PORT
      LAYER M5 ;
        RECT  134.976 172.716 135 172.8 ;
    END
  END ve_aval[29]
  PIN ve_aval[2]
    DIRECTION OUTPUT ;
    USE SIGNAL ;
    PORT
      LAYER M5 ;
        RECT  132.144 172.716 132.168 172.8 ;
    END
  END ve_aval[2]
  PIN ve_aval[30]
    DIRECTION OUTPUT ;
    USE SIGNAL ;
    PORT
      LAYER M5 ;
        RECT  135.072 172.716 135.096 172.8 ;
    END
  END ve_aval[30]
  PIN ve_aval[31]
    DIRECTION OUTPUT ;
    USE SIGNAL ;
    PORT
      LAYER M5 ;
        RECT  135.168 172.716 135.192 172.8 ;
    END
  END ve_aval[31]
  PIN ve_aval[32]
    DIRECTION OUTPUT ;
    USE SIGNAL ;
    PORT
      LAYER M5 ;
        RECT  135.36 172.716 135.384 172.8 ;
    END
  END ve_aval[32]
  PIN ve_aval[33]
    DIRECTION OUTPUT ;
    USE SIGNAL ;
    PORT
      LAYER M5 ;
        RECT  135.456 172.716 135.48 172.8 ;
    END
  END ve_aval[33]
  PIN ve_aval[34]
    DIRECTION OUTPUT ;
    USE SIGNAL ;
    PORT
      LAYER M5 ;
        RECT  135.648 172.716 135.672 172.8 ;
    END
  END ve_aval[34]
  PIN ve_aval[35]
    DIRECTION OUTPUT ;
    USE SIGNAL ;
    PORT
      LAYER M5 ;
        RECT  135.744 172.716 135.768 172.8 ;
    END
  END ve_aval[35]
  PIN ve_aval[36]
    DIRECTION OUTPUT ;
    USE SIGNAL ;
    PORT
      LAYER M5 ;
        RECT  136.464 172.716 136.488 172.8 ;
    END
  END ve_aval[36]
  PIN ve_aval[37]
    DIRECTION OUTPUT ;
    USE SIGNAL ;
    PORT
      LAYER M5 ;
        RECT  136.56 172.716 136.584 172.8 ;
    END
  END ve_aval[37]
  PIN ve_aval[38]
    DIRECTION OUTPUT ;
    USE SIGNAL ;
    PORT
      LAYER M5 ;
        RECT  136.656 172.716 136.68 172.8 ;
    END
  END ve_aval[38]
  PIN ve_aval[39]
    DIRECTION OUTPUT ;
    USE SIGNAL ;
    PORT
      LAYER M5 ;
        RECT  136.752 172.716 136.776 172.8 ;
    END
  END ve_aval[39]
  PIN ve_aval[3]
    DIRECTION OUTPUT ;
    USE SIGNAL ;
    PORT
      LAYER M5 ;
        RECT  132.24 172.716 132.264 172.8 ;
    END
  END ve_aval[3]
  PIN ve_aval[40]
    DIRECTION OUTPUT ;
    USE SIGNAL ;
    PORT
      LAYER M5 ;
        RECT  136.848 172.716 136.872 172.8 ;
    END
  END ve_aval[40]
  PIN ve_aval[41]
    DIRECTION OUTPUT ;
    USE SIGNAL ;
    PORT
      LAYER M5 ;
        RECT  136.944 172.716 136.968 172.8 ;
    END
  END ve_aval[41]
  PIN ve_aval[42]
    DIRECTION OUTPUT ;
    USE SIGNAL ;
    PORT
      LAYER M5 ;
        RECT  137.04 172.716 137.064 172.8 ;
    END
  END ve_aval[42]
  PIN ve_aval[43]
    DIRECTION OUTPUT ;
    USE SIGNAL ;
    PORT
      LAYER M5 ;
        RECT  137.136 172.716 137.16 172.8 ;
    END
  END ve_aval[43]
  PIN ve_aval[44]
    DIRECTION OUTPUT ;
    USE SIGNAL ;
    PORT
      LAYER M5 ;
        RECT  137.232 172.716 137.256 172.8 ;
    END
  END ve_aval[44]
  PIN ve_aval[45]
    DIRECTION OUTPUT ;
    USE SIGNAL ;
    PORT
      LAYER M5 ;
        RECT  137.328 172.716 137.352 172.8 ;
    END
  END ve_aval[45]
  PIN ve_aval[46]
    DIRECTION OUTPUT ;
    USE SIGNAL ;
    PORT
      LAYER M5 ;
        RECT  137.424 172.716 137.448 172.8 ;
    END
  END ve_aval[46]
  PIN ve_aval[47]
    DIRECTION OUTPUT ;
    USE SIGNAL ;
    PORT
      LAYER M5 ;
        RECT  137.52 172.716 137.544 172.8 ;
    END
  END ve_aval[47]
  PIN ve_aval[48]
    DIRECTION OUTPUT ;
    USE SIGNAL ;
    PORT
      LAYER M5 ;
        RECT  137.616 172.716 137.64 172.8 ;
    END
  END ve_aval[48]
  PIN ve_aval[49]
    DIRECTION OUTPUT ;
    USE SIGNAL ;
    PORT
      LAYER M5 ;
        RECT  137.712 172.716 137.736 172.8 ;
    END
  END ve_aval[49]
  PIN ve_aval[4]
    DIRECTION OUTPUT ;
    USE SIGNAL ;
    PORT
      LAYER M5 ;
        RECT  132.336 172.716 132.36 172.8 ;
    END
  END ve_aval[4]
  PIN ve_aval[50]
    DIRECTION OUTPUT ;
    USE SIGNAL ;
    PORT
      LAYER M5 ;
        RECT  137.808 172.716 137.832 172.8 ;
    END
  END ve_aval[50]
  PIN ve_aval[51]
    DIRECTION OUTPUT ;
    USE SIGNAL ;
    PORT
      LAYER M5 ;
        RECT  137.904 172.716 137.928 172.8 ;
    END
  END ve_aval[51]
  PIN ve_aval[52]
    DIRECTION OUTPUT ;
    USE SIGNAL ;
    PORT
      LAYER M5 ;
        RECT  138 172.716 138.024 172.8 ;
    END
  END ve_aval[52]
  PIN ve_aval[53]
    DIRECTION OUTPUT ;
    USE SIGNAL ;
    PORT
      LAYER M5 ;
        RECT  138.096 172.716 138.12 172.8 ;
    END
  END ve_aval[53]
  PIN ve_aval[54]
    DIRECTION OUTPUT ;
    USE SIGNAL ;
    PORT
      LAYER M5 ;
        RECT  138.24 172.716 138.264 172.8 ;
    END
  END ve_aval[54]
  PIN ve_aval[55]
    DIRECTION OUTPUT ;
    USE SIGNAL ;
    PORT
      LAYER M5 ;
        RECT  138.336 172.716 138.36 172.8 ;
    END
  END ve_aval[55]
  PIN ve_aval[56]
    DIRECTION OUTPUT ;
    USE SIGNAL ;
    PORT
      LAYER M5 ;
        RECT  138.432 172.716 138.456 172.8 ;
    END
  END ve_aval[56]
  PIN ve_aval[57]
    DIRECTION OUTPUT ;
    USE SIGNAL ;
    PORT
      LAYER M5 ;
        RECT  138.624 172.716 138.648 172.8 ;
    END
  END ve_aval[57]
  PIN ve_aval[58]
    DIRECTION OUTPUT ;
    USE SIGNAL ;
    PORT
      LAYER M5 ;
        RECT  138.72 172.716 138.744 172.8 ;
    END
  END ve_aval[58]
  PIN ve_aval[59]
    DIRECTION OUTPUT ;
    USE SIGNAL ;
    PORT
      LAYER M5 ;
        RECT  138.912 172.716 138.936 172.8 ;
    END
  END ve_aval[59]
  PIN ve_aval[5]
    DIRECTION OUTPUT ;
    USE SIGNAL ;
    PORT
      LAYER M5 ;
        RECT  132.432 172.716 132.456 172.8 ;
    END
  END ve_aval[5]
  PIN ve_aval[60]
    DIRECTION OUTPUT ;
    USE SIGNAL ;
    PORT
      LAYER M5 ;
        RECT  139.008 172.716 139.032 172.8 ;
    END
  END ve_aval[60]
  PIN ve_aval[61]
    DIRECTION OUTPUT ;
    USE SIGNAL ;
    PORT
      LAYER M5 ;
        RECT  139.104 172.716 139.128 172.8 ;
    END
  END ve_aval[61]
  PIN ve_aval[62]
    DIRECTION OUTPUT ;
    USE SIGNAL ;
    PORT
      LAYER M5 ;
        RECT  139.296 172.716 139.32 172.8 ;
    END
  END ve_aval[62]
  PIN ve_aval[63]
    DIRECTION OUTPUT ;
    USE SIGNAL ;
    PORT
      LAYER M5 ;
        RECT  139.392 172.716 139.416 172.8 ;
    END
  END ve_aval[63]
  PIN ve_aval[64]
    DIRECTION OUTPUT ;
    USE SIGNAL ;
    PORT
      LAYER M5 ;
        RECT  139.488 172.716 139.512 172.8 ;
    END
  END ve_aval[64]
  PIN ve_aval[65]
    DIRECTION OUTPUT ;
    USE SIGNAL ;
    PORT
      LAYER M5 ;
        RECT  139.584 172.716 139.608 172.8 ;
    END
  END ve_aval[65]
  PIN ve_aval[66]
    DIRECTION OUTPUT ;
    USE SIGNAL ;
    PORT
      LAYER M5 ;
        RECT  139.776 172.716 139.8 172.8 ;
    END
  END ve_aval[66]
  PIN ve_aval[67]
    DIRECTION OUTPUT ;
    USE SIGNAL ;
    PORT
      LAYER M5 ;
        RECT  139.872 172.716 139.896 172.8 ;
    END
  END ve_aval[67]
  PIN ve_aval[68]
    DIRECTION OUTPUT ;
    USE SIGNAL ;
    PORT
      LAYER M5 ;
        RECT  140.064 172.716 140.088 172.8 ;
    END
  END ve_aval[68]
  PIN ve_aval[69]
    DIRECTION OUTPUT ;
    USE SIGNAL ;
    PORT
      LAYER M5 ;
        RECT  140.784 172.716 140.808 172.8 ;
    END
  END ve_aval[69]
  PIN ve_aval[6]
    DIRECTION OUTPUT ;
    USE SIGNAL ;
    PORT
      LAYER M5 ;
        RECT  132.528 172.716 132.552 172.8 ;
    END
  END ve_aval[6]
  PIN ve_aval[70]
    DIRECTION OUTPUT ;
    USE SIGNAL ;
    PORT
      LAYER M5 ;
        RECT  140.88 172.716 140.904 172.8 ;
    END
  END ve_aval[70]
  PIN ve_aval[71]
    DIRECTION OUTPUT ;
    USE SIGNAL ;
    PORT
      LAYER M5 ;
        RECT  140.976 172.716 141 172.8 ;
    END
  END ve_aval[71]
  PIN ve_aval[72]
    DIRECTION OUTPUT ;
    USE SIGNAL ;
    PORT
      LAYER M5 ;
        RECT  141.072 172.716 141.096 172.8 ;
    END
  END ve_aval[72]
  PIN ve_aval[73]
    DIRECTION OUTPUT ;
    USE SIGNAL ;
    PORT
      LAYER M5 ;
        RECT  141.168 172.716 141.192 172.8 ;
    END
  END ve_aval[73]
  PIN ve_aval[74]
    DIRECTION OUTPUT ;
    USE SIGNAL ;
    PORT
      LAYER M5 ;
        RECT  141.264 172.716 141.288 172.8 ;
    END
  END ve_aval[74]
  PIN ve_aval[75]
    DIRECTION OUTPUT ;
    USE SIGNAL ;
    PORT
      LAYER M5 ;
        RECT  141.36 172.716 141.384 172.8 ;
    END
  END ve_aval[75]
  PIN ve_aval[76]
    DIRECTION OUTPUT ;
    USE SIGNAL ;
    PORT
      LAYER M5 ;
        RECT  141.456 172.716 141.48 172.8 ;
    END
  END ve_aval[76]
  PIN ve_aval[77]
    DIRECTION OUTPUT ;
    USE SIGNAL ;
    PORT
      LAYER M5 ;
        RECT  141.552 172.716 141.576 172.8 ;
    END
  END ve_aval[77]
  PIN ve_aval[78]
    DIRECTION OUTPUT ;
    USE SIGNAL ;
    PORT
      LAYER M5 ;
        RECT  141.648 172.716 141.672 172.8 ;
    END
  END ve_aval[78]
  PIN ve_aval[79]
    DIRECTION OUTPUT ;
    USE SIGNAL ;
    PORT
      LAYER M5 ;
        RECT  141.744 172.716 141.768 172.8 ;
    END
  END ve_aval[79]
  PIN ve_aval[7]
    DIRECTION OUTPUT ;
    USE SIGNAL ;
    PORT
      LAYER M5 ;
        RECT  132.624 172.716 132.648 172.8 ;
    END
  END ve_aval[7]
  PIN ve_aval[80]
    DIRECTION OUTPUT ;
    USE SIGNAL ;
    PORT
      LAYER M5 ;
        RECT  141.84 172.716 141.864 172.8 ;
    END
  END ve_aval[80]
  PIN ve_aval[81]
    DIRECTION OUTPUT ;
    USE SIGNAL ;
    PORT
      LAYER M5 ;
        RECT  141.936 172.716 141.96 172.8 ;
    END
  END ve_aval[81]
  PIN ve_aval[82]
    DIRECTION OUTPUT ;
    USE SIGNAL ;
    PORT
      LAYER M5 ;
        RECT  142.032 172.716 142.056 172.8 ;
    END
  END ve_aval[82]
  PIN ve_aval[83]
    DIRECTION OUTPUT ;
    USE SIGNAL ;
    PORT
      LAYER M5 ;
        RECT  142.128 172.716 142.152 172.8 ;
    END
  END ve_aval[83]
  PIN ve_aval[84]
    DIRECTION OUTPUT ;
    USE SIGNAL ;
    PORT
      LAYER M5 ;
        RECT  142.224 172.716 142.248 172.8 ;
    END
  END ve_aval[84]
  PIN ve_aval[85]
    DIRECTION OUTPUT ;
    USE SIGNAL ;
    PORT
      LAYER M5 ;
        RECT  142.32 172.716 142.344 172.8 ;
    END
  END ve_aval[85]
  PIN ve_aval[86]
    DIRECTION OUTPUT ;
    USE SIGNAL ;
    PORT
      LAYER M5 ;
        RECT  142.416 172.716 142.44 172.8 ;
    END
  END ve_aval[86]
  PIN ve_aval[87]
    DIRECTION OUTPUT ;
    USE SIGNAL ;
    PORT
      LAYER M5 ;
        RECT  142.512 172.716 142.536 172.8 ;
    END
  END ve_aval[87]
  PIN ve_aval[88]
    DIRECTION OUTPUT ;
    USE SIGNAL ;
    PORT
      LAYER M5 ;
        RECT  142.656 172.716 142.68 172.8 ;
    END
  END ve_aval[88]
  PIN ve_aval[89]
    DIRECTION OUTPUT ;
    USE SIGNAL ;
    PORT
      LAYER M5 ;
        RECT  142.752 172.716 142.776 172.8 ;
    END
  END ve_aval[89]
  PIN ve_aval[8]
    DIRECTION OUTPUT ;
    USE SIGNAL ;
    PORT
      LAYER M5 ;
        RECT  132.72 172.716 132.744 172.8 ;
    END
  END ve_aval[8]
  PIN ve_aval[90]
    DIRECTION OUTPUT ;
    USE SIGNAL ;
    PORT
      LAYER M5 ;
        RECT  142.848 172.716 142.872 172.8 ;
    END
  END ve_aval[90]
  PIN ve_aval[91]
    DIRECTION OUTPUT ;
    USE SIGNAL ;
    PORT
      LAYER M5 ;
        RECT  142.944 172.716 142.968 172.8 ;
    END
  END ve_aval[91]
  PIN ve_aval[92]
    DIRECTION OUTPUT ;
    USE SIGNAL ;
    PORT
      LAYER M5 ;
        RECT  143.136 172.716 143.16 172.8 ;
    END
  END ve_aval[92]
  PIN ve_aval[93]
    DIRECTION OUTPUT ;
    USE SIGNAL ;
    PORT
      LAYER M5 ;
        RECT  143.232 172.716 143.256 172.8 ;
    END
  END ve_aval[93]
  PIN ve_aval[94]
    DIRECTION OUTPUT ;
    USE SIGNAL ;
    PORT
      LAYER M5 ;
        RECT  143.424 172.716 143.448 172.8 ;
    END
  END ve_aval[94]
  PIN ve_aval[95]
    DIRECTION OUTPUT ;
    USE SIGNAL ;
    PORT
      LAYER M5 ;
        RECT  143.52 172.716 143.544 172.8 ;
    END
  END ve_aval[95]
  PIN ve_aval[96]
    DIRECTION OUTPUT ;
    USE SIGNAL ;
    PORT
      LAYER M5 ;
        RECT  143.616 172.716 143.64 172.8 ;
    END
  END ve_aval[96]
  PIN ve_aval[97]
    DIRECTION OUTPUT ;
    USE SIGNAL ;
    PORT
      LAYER M5 ;
        RECT  143.808 172.716 143.832 172.8 ;
    END
  END ve_aval[97]
  PIN ve_aval[98]
    DIRECTION OUTPUT ;
    USE SIGNAL ;
    PORT
      LAYER M5 ;
        RECT  143.904 172.716 143.928 172.8 ;
    END
  END ve_aval[98]
  PIN ve_aval[99]
    DIRECTION OUTPUT ;
    USE SIGNAL ;
    PORT
      LAYER M5 ;
        RECT  144.096 172.716 144.12 172.8 ;
    END
  END ve_aval[99]
  PIN ve_aval[9]
    DIRECTION OUTPUT ;
    USE SIGNAL ;
    PORT
      LAYER M5 ;
        RECT  132.816 172.716 132.84 172.8 ;
    END
  END ve_aval[9]
  PIN ve_fi
    DIRECTION INPUT ;
    USE SIGNAL ;
    PORT
      LAYER M5 ;
        RECT  55.536 172.716 55.56 172.8 ;
    END
  END ve_fi
  PIN ve_oc[0]
    DIRECTION INPUT ;
    USE SIGNAL ;
    PORT
      LAYER M5 ;
        RECT  97.872 172.716 97.896 172.8 ;
    END
  END ve_oc[0]
  PIN ve_oc[1]
    DIRECTION INPUT ;
    USE SIGNAL ;
    PORT
      LAYER M5 ;
        RECT  97.968 172.716 97.992 172.8 ;
    END
  END ve_oc[1]
  PIN ve_ov
    DIRECTION INPUT ;
    USE SIGNAL ;
    PORT
      LAYER M5 ;
        RECT  97.776 172.716 97.8 172.8 ;
    END
  END ve_ov
  PIN ve_oy[0]
    DIRECTION INPUT ;
    USE SIGNAL ;
    PORT
      LAYER M5 ;
        RECT  98.064 172.716 98.088 172.8 ;
    END
  END ve_oy[0]
  PIN ve_oy[100]
    DIRECTION INPUT ;
    USE SIGNAL ;
    PORT
      LAYER M5 ;
        RECT  111.024 172.716 111.048 172.8 ;
    END
  END ve_oy[100]
  PIN ve_oy[101]
    DIRECTION INPUT ;
    USE SIGNAL ;
    PORT
      LAYER M5 ;
        RECT  111.12 172.716 111.144 172.8 ;
    END
  END ve_oy[101]
  PIN ve_oy[102]
    DIRECTION INPUT ;
    USE SIGNAL ;
    PORT
      LAYER M5 ;
        RECT  111.216 172.716 111.24 172.8 ;
    END
  END ve_oy[102]
  PIN ve_oy[103]
    DIRECTION INPUT ;
    USE SIGNAL ;
    PORT
      LAYER M5 ;
        RECT  111.312 172.716 111.336 172.8 ;
    END
  END ve_oy[103]
  PIN ve_oy[104]
    DIRECTION INPUT ;
    USE SIGNAL ;
    PORT
      LAYER M5 ;
        RECT  111.408 172.716 111.432 172.8 ;
    END
  END ve_oy[104]
  PIN ve_oy[105]
    DIRECTION INPUT ;
    USE SIGNAL ;
    PORT
      LAYER M5 ;
        RECT  111.504 172.716 111.528 172.8 ;
    END
  END ve_oy[105]
  PIN ve_oy[106]
    DIRECTION INPUT ;
    USE SIGNAL ;
    PORT
      LAYER M5 ;
        RECT  111.6 172.716 111.624 172.8 ;
    END
  END ve_oy[106]
  PIN ve_oy[107]
    DIRECTION INPUT ;
    USE SIGNAL ;
    PORT
      LAYER M5 ;
        RECT  111.696 172.716 111.72 172.8 ;
    END
  END ve_oy[107]
  PIN ve_oy[108]
    DIRECTION INPUT ;
    USE SIGNAL ;
    PORT
      LAYER M5 ;
        RECT  111.792 172.716 111.816 172.8 ;
    END
  END ve_oy[108]
  PIN ve_oy[109]
    DIRECTION INPUT ;
    USE SIGNAL ;
    PORT
      LAYER M5 ;
        RECT  111.888 172.716 111.912 172.8 ;
    END
  END ve_oy[109]
  PIN ve_oy[10]
    DIRECTION INPUT ;
    USE SIGNAL ;
    PORT
      LAYER M5 ;
        RECT  99.024 172.716 99.048 172.8 ;
    END
  END ve_oy[10]
  PIN ve_oy[110]
    DIRECTION INPUT ;
    USE SIGNAL ;
    PORT
      LAYER M5 ;
        RECT  111.984 172.716 112.008 172.8 ;
    END
  END ve_oy[110]
  PIN ve_oy[111]
    DIRECTION INPUT ;
    USE SIGNAL ;
    PORT
      LAYER M5 ;
        RECT  112.08 172.716 112.104 172.8 ;
    END
  END ve_oy[111]
  PIN ve_oy[112]
    DIRECTION INPUT ;
    USE SIGNAL ;
    PORT
      LAYER M5 ;
        RECT  112.176 172.716 112.2 172.8 ;
    END
  END ve_oy[112]
  PIN ve_oy[113]
    DIRECTION INPUT ;
    USE SIGNAL ;
    PORT
      LAYER M5 ;
        RECT  112.32 172.716 112.344 172.8 ;
    END
  END ve_oy[113]
  PIN ve_oy[114]
    DIRECTION INPUT ;
    USE SIGNAL ;
    PORT
      LAYER M5 ;
        RECT  112.416 172.716 112.44 172.8 ;
    END
  END ve_oy[114]
  PIN ve_oy[115]
    DIRECTION INPUT ;
    USE SIGNAL ;
    PORT
      LAYER M5 ;
        RECT  112.608 172.716 112.632 172.8 ;
    END
  END ve_oy[115]
  PIN ve_oy[116]
    DIRECTION INPUT ;
    USE SIGNAL ;
    PORT
      LAYER M5 ;
        RECT  112.704 172.716 112.728 172.8 ;
    END
  END ve_oy[116]
  PIN ve_oy[117]
    DIRECTION INPUT ;
    USE SIGNAL ;
    PORT
      LAYER M5 ;
        RECT  112.8 172.716 112.824 172.8 ;
    END
  END ve_oy[117]
  PIN ve_oy[118]
    DIRECTION INPUT ;
    USE SIGNAL ;
    PORT
      LAYER M5 ;
        RECT  112.992 172.716 113.016 172.8 ;
    END
  END ve_oy[118]
  PIN ve_oy[119]
    DIRECTION INPUT ;
    USE SIGNAL ;
    PORT
      LAYER M5 ;
        RECT  113.088 172.716 113.112 172.8 ;
    END
  END ve_oy[119]
  PIN ve_oy[11]
    DIRECTION INPUT ;
    USE SIGNAL ;
    PORT
      LAYER M5 ;
        RECT  99.12 172.716 99.144 172.8 ;
    END
  END ve_oy[11]
  PIN ve_oy[120]
    DIRECTION INPUT ;
    USE SIGNAL ;
    PORT
      LAYER M5 ;
        RECT  113.184 172.716 113.208 172.8 ;
    END
  END ve_oy[120]
  PIN ve_oy[121]
    DIRECTION INPUT ;
    USE SIGNAL ;
    PORT
      LAYER M5 ;
        RECT  113.376 172.716 113.4 172.8 ;
    END
  END ve_oy[121]
  PIN ve_oy[122]
    DIRECTION INPUT ;
    USE SIGNAL ;
    PORT
      LAYER M5 ;
        RECT  113.472 172.716 113.496 172.8 ;
    END
  END ve_oy[122]
  PIN ve_oy[123]
    DIRECTION INPUT ;
    USE SIGNAL ;
    PORT
      LAYER M5 ;
        RECT  113.568 172.716 113.592 172.8 ;
    END
  END ve_oy[123]
  PIN ve_oy[124]
    DIRECTION INPUT ;
    USE SIGNAL ;
    PORT
      LAYER M5 ;
        RECT  113.76 172.716 113.784 172.8 ;
    END
  END ve_oy[124]
  PIN ve_oy[125]
    DIRECTION INPUT ;
    USE SIGNAL ;
    PORT
      LAYER M5 ;
        RECT  113.856 172.716 113.88 172.8 ;
    END
  END ve_oy[125]
  PIN ve_oy[126]
    DIRECTION INPUT ;
    USE SIGNAL ;
    PORT
      LAYER M5 ;
        RECT  113.952 172.716 113.976 172.8 ;
    END
  END ve_oy[126]
  PIN ve_oy[127]
    DIRECTION INPUT ;
    USE SIGNAL ;
    PORT
      LAYER M5 ;
        RECT  114.144 172.716 114.168 172.8 ;
    END
  END ve_oy[127]
  PIN ve_oy[12]
    DIRECTION INPUT ;
    USE SIGNAL ;
    PORT
      LAYER M5 ;
        RECT  99.216 172.716 99.24 172.8 ;
    END
  END ve_oy[12]
  PIN ve_oy[13]
    DIRECTION INPUT ;
    USE SIGNAL ;
    PORT
      LAYER M5 ;
        RECT  99.36 172.716 99.384 172.8 ;
    END
  END ve_oy[13]
  PIN ve_oy[14]
    DIRECTION INPUT ;
    USE SIGNAL ;
    PORT
      LAYER M5 ;
        RECT  99.456 172.716 99.48 172.8 ;
    END
  END ve_oy[14]
  PIN ve_oy[15]
    DIRECTION INPUT ;
    USE SIGNAL ;
    PORT
      LAYER M5 ;
        RECT  99.648 172.716 99.672 172.8 ;
    END
  END ve_oy[15]
  PIN ve_oy[16]
    DIRECTION INPUT ;
    USE SIGNAL ;
    PORT
      LAYER M5 ;
        RECT  99.744 172.716 99.768 172.8 ;
    END
  END ve_oy[16]
  PIN ve_oy[17]
    DIRECTION INPUT ;
    USE SIGNAL ;
    PORT
      LAYER M5 ;
        RECT  99.84 172.716 99.864 172.8 ;
    END
  END ve_oy[17]
  PIN ve_oy[18]
    DIRECTION INPUT ;
    USE SIGNAL ;
    PORT
      LAYER M5 ;
        RECT  100.032 172.716 100.056 172.8 ;
    END
  END ve_oy[18]
  PIN ve_oy[19]
    DIRECTION INPUT ;
    USE SIGNAL ;
    PORT
      LAYER M5 ;
        RECT  100.128 172.716 100.152 172.8 ;
    END
  END ve_oy[19]
  PIN ve_oy[1]
    DIRECTION INPUT ;
    USE SIGNAL ;
    PORT
      LAYER M5 ;
        RECT  98.16 172.716 98.184 172.8 ;
    END
  END ve_oy[1]
  PIN ve_oy[20]
    DIRECTION INPUT ;
    USE SIGNAL ;
    PORT
      LAYER M5 ;
        RECT  100.224 172.716 100.248 172.8 ;
    END
  END ve_oy[20]
  PIN ve_oy[21]
    DIRECTION INPUT ;
    USE SIGNAL ;
    PORT
      LAYER M5 ;
        RECT  100.416 172.716 100.44 172.8 ;
    END
  END ve_oy[21]
  PIN ve_oy[22]
    DIRECTION INPUT ;
    USE SIGNAL ;
    PORT
      LAYER M5 ;
        RECT  100.512 172.716 100.536 172.8 ;
    END
  END ve_oy[22]
  PIN ve_oy[23]
    DIRECTION INPUT ;
    USE SIGNAL ;
    PORT
      LAYER M5 ;
        RECT  100.608 172.716 100.632 172.8 ;
    END
  END ve_oy[23]
  PIN ve_oy[24]
    DIRECTION INPUT ;
    USE SIGNAL ;
    PORT
      LAYER M5 ;
        RECT  100.8 172.716 100.824 172.8 ;
    END
  END ve_oy[24]
  PIN ve_oy[25]
    DIRECTION INPUT ;
    USE SIGNAL ;
    PORT
      LAYER M5 ;
        RECT  100.896 172.716 100.92 172.8 ;
    END
  END ve_oy[25]
  PIN ve_oy[26]
    DIRECTION INPUT ;
    USE SIGNAL ;
    PORT
      LAYER M5 ;
        RECT  100.992 172.716 101.016 172.8 ;
    END
  END ve_oy[26]
  PIN ve_oy[27]
    DIRECTION INPUT ;
    USE SIGNAL ;
    PORT
      LAYER M5 ;
        RECT  101.184 172.716 101.208 172.8 ;
    END
  END ve_oy[27]
  PIN ve_oy[28]
    DIRECTION INPUT ;
    USE SIGNAL ;
    PORT
      LAYER M5 ;
        RECT  101.904 172.716 101.928 172.8 ;
    END
  END ve_oy[28]
  PIN ve_oy[29]
    DIRECTION INPUT ;
    USE SIGNAL ;
    PORT
      LAYER M5 ;
        RECT  102 172.716 102.024 172.8 ;
    END
  END ve_oy[29]
  PIN ve_oy[2]
    DIRECTION INPUT ;
    USE SIGNAL ;
    PORT
      LAYER M5 ;
        RECT  98.256 172.716 98.28 172.8 ;
    END
  END ve_oy[2]
  PIN ve_oy[30]
    DIRECTION INPUT ;
    USE SIGNAL ;
    PORT
      LAYER M5 ;
        RECT  102.096 172.716 102.12 172.8 ;
    END
  END ve_oy[30]
  PIN ve_oy[31]
    DIRECTION INPUT ;
    USE SIGNAL ;
    PORT
      LAYER M5 ;
        RECT  102.192 172.716 102.216 172.8 ;
    END
  END ve_oy[31]
  PIN ve_oy[32]
    DIRECTION INPUT ;
    USE SIGNAL ;
    PORT
      LAYER M5 ;
        RECT  102.288 172.716 102.312 172.8 ;
    END
  END ve_oy[32]
  PIN ve_oy[33]
    DIRECTION INPUT ;
    USE SIGNAL ;
    PORT
      LAYER M5 ;
        RECT  102.384 172.716 102.408 172.8 ;
    END
  END ve_oy[33]
  PIN ve_oy[34]
    DIRECTION INPUT ;
    USE SIGNAL ;
    PORT
      LAYER M5 ;
        RECT  102.48 172.716 102.504 172.8 ;
    END
  END ve_oy[34]
  PIN ve_oy[35]
    DIRECTION INPUT ;
    USE SIGNAL ;
    PORT
      LAYER M5 ;
        RECT  102.576 172.716 102.6 172.8 ;
    END
  END ve_oy[35]
  PIN ve_oy[36]
    DIRECTION INPUT ;
    USE SIGNAL ;
    PORT
      LAYER M5 ;
        RECT  102.672 172.716 102.696 172.8 ;
    END
  END ve_oy[36]
  PIN ve_oy[37]
    DIRECTION INPUT ;
    USE SIGNAL ;
    PORT
      LAYER M5 ;
        RECT  102.768 172.716 102.792 172.8 ;
    END
  END ve_oy[37]
  PIN ve_oy[38]
    DIRECTION INPUT ;
    USE SIGNAL ;
    PORT
      LAYER M5 ;
        RECT  102.864 172.716 102.888 172.8 ;
    END
  END ve_oy[38]
  PIN ve_oy[39]
    DIRECTION INPUT ;
    USE SIGNAL ;
    PORT
      LAYER M5 ;
        RECT  102.96 172.716 102.984 172.8 ;
    END
  END ve_oy[39]
  PIN ve_oy[3]
    DIRECTION INPUT ;
    USE SIGNAL ;
    PORT
      LAYER M5 ;
        RECT  98.352 172.716 98.376 172.8 ;
    END
  END ve_oy[3]
  PIN ve_oy[40]
    DIRECTION INPUT ;
    USE SIGNAL ;
    PORT
      LAYER M5 ;
        RECT  103.056 172.716 103.08 172.8 ;
    END
  END ve_oy[40]
  PIN ve_oy[41]
    DIRECTION INPUT ;
    USE SIGNAL ;
    PORT
      LAYER M5 ;
        RECT  103.152 172.716 103.176 172.8 ;
    END
  END ve_oy[41]
  PIN ve_oy[42]
    DIRECTION INPUT ;
    USE SIGNAL ;
    PORT
      LAYER M5 ;
        RECT  103.248 172.716 103.272 172.8 ;
    END
  END ve_oy[42]
  PIN ve_oy[43]
    DIRECTION INPUT ;
    USE SIGNAL ;
    PORT
      LAYER M5 ;
        RECT  103.344 172.716 103.368 172.8 ;
    END
  END ve_oy[43]
  PIN ve_oy[44]
    DIRECTION INPUT ;
    USE SIGNAL ;
    PORT
      LAYER M5 ;
        RECT  103.44 172.716 103.464 172.8 ;
    END
  END ve_oy[44]
  PIN ve_oy[45]
    DIRECTION INPUT ;
    USE SIGNAL ;
    PORT
      LAYER M5 ;
        RECT  103.536 172.716 103.56 172.8 ;
    END
  END ve_oy[45]
  PIN ve_oy[46]
    DIRECTION INPUT ;
    USE SIGNAL ;
    PORT
      LAYER M5 ;
        RECT  103.632 172.716 103.656 172.8 ;
    END
  END ve_oy[46]
  PIN ve_oy[47]
    DIRECTION INPUT ;
    USE SIGNAL ;
    PORT
      LAYER M5 ;
        RECT  103.776 172.716 103.8 172.8 ;
    END
  END ve_oy[47]
  PIN ve_oy[48]
    DIRECTION INPUT ;
    USE SIGNAL ;
    PORT
      LAYER M5 ;
        RECT  103.872 172.716 103.896 172.8 ;
    END
  END ve_oy[48]
  PIN ve_oy[49]
    DIRECTION INPUT ;
    USE SIGNAL ;
    PORT
      LAYER M5 ;
        RECT  103.968 172.716 103.992 172.8 ;
    END
  END ve_oy[49]
  PIN ve_oy[4]
    DIRECTION INPUT ;
    USE SIGNAL ;
    PORT
      LAYER M5 ;
        RECT  98.448 172.716 98.472 172.8 ;
    END
  END ve_oy[4]
  PIN ve_oy[50]
    DIRECTION INPUT ;
    USE SIGNAL ;
    PORT
      LAYER M5 ;
        RECT  104.064 172.716 104.088 172.8 ;
    END
  END ve_oy[50]
  PIN ve_oy[51]
    DIRECTION INPUT ;
    USE SIGNAL ;
    PORT
      LAYER M5 ;
        RECT  104.256 172.716 104.28 172.8 ;
    END
  END ve_oy[51]
  PIN ve_oy[52]
    DIRECTION INPUT ;
    USE SIGNAL ;
    PORT
      LAYER M5 ;
        RECT  104.352 172.716 104.376 172.8 ;
    END
  END ve_oy[52]
  PIN ve_oy[53]
    DIRECTION INPUT ;
    USE SIGNAL ;
    PORT
      LAYER M5 ;
        RECT  104.544 172.716 104.568 172.8 ;
    END
  END ve_oy[53]
  PIN ve_oy[54]
    DIRECTION INPUT ;
    USE SIGNAL ;
    PORT
      LAYER M5 ;
        RECT  104.64 172.716 104.664 172.8 ;
    END
  END ve_oy[54]
  PIN ve_oy[55]
    DIRECTION INPUT ;
    USE SIGNAL ;
    PORT
      LAYER M5 ;
        RECT  104.832 172.716 104.856 172.8 ;
    END
  END ve_oy[55]
  PIN ve_oy[56]
    DIRECTION INPUT ;
    USE SIGNAL ;
    PORT
      LAYER M5 ;
        RECT  104.928 172.716 104.952 172.8 ;
    END
  END ve_oy[56]
  PIN ve_oy[57]
    DIRECTION INPUT ;
    USE SIGNAL ;
    PORT
      LAYER M5 ;
        RECT  105.024 172.716 105.048 172.8 ;
    END
  END ve_oy[57]
  PIN ve_oy[58]
    DIRECTION INPUT ;
    USE SIGNAL ;
    PORT
      LAYER M5 ;
        RECT  105.216 172.716 105.24 172.8 ;
    END
  END ve_oy[58]
  PIN ve_oy[59]
    DIRECTION INPUT ;
    USE SIGNAL ;
    PORT
      LAYER M5 ;
        RECT  105.312 172.716 105.336 172.8 ;
    END
  END ve_oy[59]
  PIN ve_oy[5]
    DIRECTION INPUT ;
    USE SIGNAL ;
    PORT
      LAYER M5 ;
        RECT  98.544 172.716 98.568 172.8 ;
    END
  END ve_oy[5]
  PIN ve_oy[60]
    DIRECTION INPUT ;
    USE SIGNAL ;
    PORT
      LAYER M5 ;
        RECT  105.408 172.716 105.432 172.8 ;
    END
  END ve_oy[60]
  PIN ve_oy[61]
    DIRECTION INPUT ;
    USE SIGNAL ;
    PORT
      LAYER M5 ;
        RECT  106.224 172.716 106.248 172.8 ;
    END
  END ve_oy[61]
  PIN ve_oy[62]
    DIRECTION INPUT ;
    USE SIGNAL ;
    PORT
      LAYER M5 ;
        RECT  106.32 172.716 106.344 172.8 ;
    END
  END ve_oy[62]
  PIN ve_oy[63]
    DIRECTION INPUT ;
    USE SIGNAL ;
    PORT
      LAYER M5 ;
        RECT  106.416 172.716 106.44 172.8 ;
    END
  END ve_oy[63]
  PIN ve_oy[64]
    DIRECTION INPUT ;
    USE SIGNAL ;
    PORT
      LAYER M5 ;
        RECT  106.512 172.716 106.536 172.8 ;
    END
  END ve_oy[64]
  PIN ve_oy[65]
    DIRECTION INPUT ;
    USE SIGNAL ;
    PORT
      LAYER M5 ;
        RECT  106.608 172.716 106.632 172.8 ;
    END
  END ve_oy[65]
  PIN ve_oy[66]
    DIRECTION INPUT ;
    USE SIGNAL ;
    PORT
      LAYER M5 ;
        RECT  106.704 172.716 106.728 172.8 ;
    END
  END ve_oy[66]
  PIN ve_oy[67]
    DIRECTION INPUT ;
    USE SIGNAL ;
    PORT
      LAYER M5 ;
        RECT  106.8 172.716 106.824 172.8 ;
    END
  END ve_oy[67]
  PIN ve_oy[68]
    DIRECTION INPUT ;
    USE SIGNAL ;
    PORT
      LAYER M5 ;
        RECT  106.896 172.716 106.92 172.8 ;
    END
  END ve_oy[68]
  PIN ve_oy[69]
    DIRECTION INPUT ;
    USE SIGNAL ;
    PORT
      LAYER M5 ;
        RECT  106.992 172.716 107.016 172.8 ;
    END
  END ve_oy[69]
  PIN ve_oy[6]
    DIRECTION INPUT ;
    USE SIGNAL ;
    PORT
      LAYER M5 ;
        RECT  98.64 172.716 98.664 172.8 ;
    END
  END ve_oy[6]
  PIN ve_oy[70]
    DIRECTION INPUT ;
    USE SIGNAL ;
    PORT
      LAYER M5 ;
        RECT  107.088 172.716 107.112 172.8 ;
    END
  END ve_oy[70]
  PIN ve_oy[71]
    DIRECTION INPUT ;
    USE SIGNAL ;
    PORT
      LAYER M5 ;
        RECT  107.184 172.716 107.208 172.8 ;
    END
  END ve_oy[71]
  PIN ve_oy[72]
    DIRECTION INPUT ;
    USE SIGNAL ;
    PORT
      LAYER M5 ;
        RECT  107.28 172.716 107.304 172.8 ;
    END
  END ve_oy[72]
  PIN ve_oy[73]
    DIRECTION INPUT ;
    USE SIGNAL ;
    PORT
      LAYER M5 ;
        RECT  107.376 172.716 107.4 172.8 ;
    END
  END ve_oy[73]
  PIN ve_oy[74]
    DIRECTION INPUT ;
    USE SIGNAL ;
    PORT
      LAYER M5 ;
        RECT  107.472 172.716 107.496 172.8 ;
    END
  END ve_oy[74]
  PIN ve_oy[75]
    DIRECTION INPUT ;
    USE SIGNAL ;
    PORT
      LAYER M5 ;
        RECT  107.568 172.716 107.592 172.8 ;
    END
  END ve_oy[75]
  PIN ve_oy[76]
    DIRECTION INPUT ;
    USE SIGNAL ;
    PORT
      LAYER M5 ;
        RECT  107.664 172.716 107.688 172.8 ;
    END
  END ve_oy[76]
  PIN ve_oy[77]
    DIRECTION INPUT ;
    USE SIGNAL ;
    PORT
      LAYER M5 ;
        RECT  107.76 172.716 107.784 172.8 ;
    END
  END ve_oy[77]
  PIN ve_oy[78]
    DIRECTION INPUT ;
    USE SIGNAL ;
    PORT
      LAYER M5 ;
        RECT  107.856 172.716 107.88 172.8 ;
    END
  END ve_oy[78]
  PIN ve_oy[79]
    DIRECTION INPUT ;
    USE SIGNAL ;
    PORT
      LAYER M5 ;
        RECT  107.952 172.716 107.976 172.8 ;
    END
  END ve_oy[79]
  PIN ve_oy[7]
    DIRECTION INPUT ;
    USE SIGNAL ;
    PORT
      LAYER M5 ;
        RECT  98.736 172.716 98.76 172.8 ;
    END
  END ve_oy[7]
  PIN ve_oy[80]
    DIRECTION INPUT ;
    USE SIGNAL ;
    PORT
      LAYER M5 ;
        RECT  108.048 172.716 108.072 172.8 ;
    END
  END ve_oy[80]
  PIN ve_oy[81]
    DIRECTION INPUT ;
    USE SIGNAL ;
    PORT
      LAYER M5 ;
        RECT  108.192 172.716 108.216 172.8 ;
    END
  END ve_oy[81]
  PIN ve_oy[82]
    DIRECTION INPUT ;
    USE SIGNAL ;
    PORT
      LAYER M5 ;
        RECT  108.288 172.716 108.312 172.8 ;
    END
  END ve_oy[82]
  PIN ve_oy[83]
    DIRECTION INPUT ;
    USE SIGNAL ;
    PORT
      LAYER M5 ;
        RECT  108.384 172.716 108.408 172.8 ;
    END
  END ve_oy[83]
  PIN ve_oy[84]
    DIRECTION INPUT ;
    USE SIGNAL ;
    PORT
      LAYER M5 ;
        RECT  108.576 172.716 108.6 172.8 ;
    END
  END ve_oy[84]
  PIN ve_oy[85]
    DIRECTION INPUT ;
    USE SIGNAL ;
    PORT
      LAYER M5 ;
        RECT  108.672 172.716 108.696 172.8 ;
    END
  END ve_oy[85]
  PIN ve_oy[86]
    DIRECTION INPUT ;
    USE SIGNAL ;
    PORT
      LAYER M5 ;
        RECT  108.768 172.716 108.792 172.8 ;
    END
  END ve_oy[86]
  PIN ve_oy[87]
    DIRECTION INPUT ;
    USE SIGNAL ;
    PORT
      LAYER M5 ;
        RECT  108.96 172.716 108.984 172.8 ;
    END
  END ve_oy[87]
  PIN ve_oy[88]
    DIRECTION INPUT ;
    USE SIGNAL ;
    PORT
      LAYER M5 ;
        RECT  109.056 172.716 109.08 172.8 ;
    END
  END ve_oy[88]
  PIN ve_oy[89]
    DIRECTION INPUT ;
    USE SIGNAL ;
    PORT
      LAYER M5 ;
        RECT  109.152 172.716 109.176 172.8 ;
    END
  END ve_oy[89]
  PIN ve_oy[8]
    DIRECTION INPUT ;
    USE SIGNAL ;
    PORT
      LAYER M5 ;
        RECT  98.832 172.716 98.856 172.8 ;
    END
  END ve_oy[8]
  PIN ve_oy[90]
    DIRECTION INPUT ;
    USE SIGNAL ;
    PORT
      LAYER M5 ;
        RECT  109.248 172.716 109.272 172.8 ;
    END
  END ve_oy[90]
  PIN ve_oy[91]
    DIRECTION INPUT ;
    USE SIGNAL ;
    PORT
      LAYER M5 ;
        RECT  109.44 172.716 109.464 172.8 ;
    END
  END ve_oy[91]
  PIN ve_oy[92]
    DIRECTION INPUT ;
    USE SIGNAL ;
    PORT
      LAYER M5 ;
        RECT  109.536 172.716 109.56 172.8 ;
    END
  END ve_oy[92]
  PIN ve_oy[93]
    DIRECTION INPUT ;
    USE SIGNAL ;
    PORT
      LAYER M5 ;
        RECT  109.728 172.716 109.752 172.8 ;
    END
  END ve_oy[93]
  PIN ve_oy[94]
    DIRECTION INPUT ;
    USE SIGNAL ;
    PORT
      LAYER M5 ;
        RECT  109.824 172.716 109.848 172.8 ;
    END
  END ve_oy[94]
  PIN ve_oy[95]
    DIRECTION INPUT ;
    USE SIGNAL ;
    PORT
      LAYER M5 ;
        RECT  110.544 172.716 110.568 172.8 ;
    END
  END ve_oy[95]
  PIN ve_oy[96]
    DIRECTION INPUT ;
    USE SIGNAL ;
    PORT
      LAYER M5 ;
        RECT  110.64 172.716 110.664 172.8 ;
    END
  END ve_oy[96]
  PIN ve_oy[97]
    DIRECTION INPUT ;
    USE SIGNAL ;
    PORT
      LAYER M5 ;
        RECT  110.736 172.716 110.76 172.8 ;
    END
  END ve_oy[97]
  PIN ve_oy[98]
    DIRECTION INPUT ;
    USE SIGNAL ;
    PORT
      LAYER M5 ;
        RECT  110.832 172.716 110.856 172.8 ;
    END
  END ve_oy[98]
  PIN ve_oy[99]
    DIRECTION INPUT ;
    USE SIGNAL ;
    PORT
      LAYER M5 ;
        RECT  110.928 172.716 110.952 172.8 ;
    END
  END ve_oy[99]
  PIN ve_oy[9]
    DIRECTION INPUT ;
    USE SIGNAL ;
    PORT
      LAYER M5 ;
        RECT  98.928 172.716 98.952 172.8 ;
    END
  END ve_oy[9]
  PIN ve_pc[0]
    DIRECTION INPUT ;
    USE SIGNAL ;
    PORT
      LAYER M5 ;
        RECT  4.512 172.716 4.536 172.8 ;
    END
  END ve_pc[0]
  PIN ve_pc[1]
    DIRECTION INPUT ;
    USE SIGNAL ;
    PORT
      LAYER M5 ;
        RECT  4.608 172.716 4.632 172.8 ;
    END
  END ve_pc[1]
  PIN ve_pdd[0]
    DIRECTION INPUT ;
    USE SIGNAL ;
    PORT
      LAYER M5 ;
        RECT  13.056 172.716 13.08 172.8 ;
    END
  END ve_pdd[0]
  PIN ve_pdd[10]
    DIRECTION INPUT ;
    USE SIGNAL ;
    PORT
      LAYER M5 ;
        RECT  14.304 172.716 14.328 172.8 ;
    END
  END ve_pdd[10]
  PIN ve_pdd[11]
    DIRECTION INPUT ;
    USE SIGNAL ;
    PORT
      LAYER M5 ;
        RECT  14.496 172.716 14.52 172.8 ;
    END
  END ve_pdd[11]
  PIN ve_pdd[12]
    DIRECTION INPUT ;
    USE SIGNAL ;
    PORT
      LAYER M5 ;
        RECT  14.592 172.716 14.616 172.8 ;
    END
  END ve_pdd[12]
  PIN ve_pdd[13]
    DIRECTION INPUT ;
    USE SIGNAL ;
    PORT
      LAYER M5 ;
        RECT  14.784 172.716 14.808 172.8 ;
    END
  END ve_pdd[13]
  PIN ve_pdd[14]
    DIRECTION INPUT ;
    USE SIGNAL ;
    PORT
      LAYER M5 ;
        RECT  15.504 172.716 15.528 172.8 ;
    END
  END ve_pdd[14]
  PIN ve_pdd[15]
    DIRECTION INPUT ;
    USE SIGNAL ;
    PORT
      LAYER M5 ;
        RECT  15.6 172.716 15.624 172.8 ;
    END
  END ve_pdd[15]
  PIN ve_pdd[16]
    DIRECTION INPUT ;
    USE SIGNAL ;
    PORT
      LAYER M5 ;
        RECT  15.696 172.716 15.72 172.8 ;
    END
  END ve_pdd[16]
  PIN ve_pdd[17]
    DIRECTION INPUT ;
    USE SIGNAL ;
    PORT
      LAYER M5 ;
        RECT  15.792 172.716 15.816 172.8 ;
    END
  END ve_pdd[17]
  PIN ve_pdd[18]
    DIRECTION INPUT ;
    USE SIGNAL ;
    PORT
      LAYER M5 ;
        RECT  15.888 172.716 15.912 172.8 ;
    END
  END ve_pdd[18]
  PIN ve_pdd[19]
    DIRECTION INPUT ;
    USE SIGNAL ;
    PORT
      LAYER M5 ;
        RECT  15.984 172.716 16.008 172.8 ;
    END
  END ve_pdd[19]
  PIN ve_pdd[1]
    DIRECTION INPUT ;
    USE SIGNAL ;
    PORT
      LAYER M5 ;
        RECT  13.152 172.716 13.176 172.8 ;
    END
  END ve_pdd[1]
  PIN ve_pdd[20]
    DIRECTION INPUT ;
    USE SIGNAL ;
    PORT
      LAYER M5 ;
        RECT  16.08 172.716 16.104 172.8 ;
    END
  END ve_pdd[20]
  PIN ve_pdd[21]
    DIRECTION INPUT ;
    USE SIGNAL ;
    PORT
      LAYER M5 ;
        RECT  16.176 172.716 16.2 172.8 ;
    END
  END ve_pdd[21]
  PIN ve_pdd[22]
    DIRECTION INPUT ;
    USE SIGNAL ;
    PORT
      LAYER M5 ;
        RECT  16.272 172.716 16.296 172.8 ;
    END
  END ve_pdd[22]
  PIN ve_pdd[23]
    DIRECTION INPUT ;
    USE SIGNAL ;
    PORT
      LAYER M5 ;
        RECT  16.368 172.716 16.392 172.8 ;
    END
  END ve_pdd[23]
  PIN ve_pdd[24]
    DIRECTION INPUT ;
    USE SIGNAL ;
    PORT
      LAYER M5 ;
        RECT  16.464 172.716 16.488 172.8 ;
    END
  END ve_pdd[24]
  PIN ve_pdd[25]
    DIRECTION INPUT ;
    USE SIGNAL ;
    PORT
      LAYER M5 ;
        RECT  16.56 172.716 16.584 172.8 ;
    END
  END ve_pdd[25]
  PIN ve_pdd[26]
    DIRECTION INPUT ;
    USE SIGNAL ;
    PORT
      LAYER M5 ;
        RECT  16.656 172.716 16.68 172.8 ;
    END
  END ve_pdd[26]
  PIN ve_pdd[27]
    DIRECTION INPUT ;
    USE SIGNAL ;
    PORT
      LAYER M5 ;
        RECT  16.752 172.716 16.776 172.8 ;
    END
  END ve_pdd[27]
  PIN ve_pdd[28]
    DIRECTION INPUT ;
    USE SIGNAL ;
    PORT
      LAYER M5 ;
        RECT  16.848 172.716 16.872 172.8 ;
    END
  END ve_pdd[28]
  PIN ve_pdd[29]
    DIRECTION INPUT ;
    USE SIGNAL ;
    PORT
      LAYER M5 ;
        RECT  16.944 172.716 16.968 172.8 ;
    END
  END ve_pdd[29]
  PIN ve_pdd[2]
    DIRECTION INPUT ;
    USE SIGNAL ;
    PORT
      LAYER M5 ;
        RECT  13.344 172.716 13.368 172.8 ;
    END
  END ve_pdd[2]
  PIN ve_pdd[30]
    DIRECTION INPUT ;
    USE SIGNAL ;
    PORT
      LAYER M5 ;
        RECT  17.04 172.716 17.064 172.8 ;
    END
  END ve_pdd[30]
  PIN ve_pdd[31]
    DIRECTION INPUT ;
    USE SIGNAL ;
    PORT
      LAYER M5 ;
        RECT  17.136 172.716 17.16 172.8 ;
    END
  END ve_pdd[31]
  PIN ve_pdd[3]
    DIRECTION INPUT ;
    USE SIGNAL ;
    PORT
      LAYER M5 ;
        RECT  13.44 172.716 13.464 172.8 ;
    END
  END ve_pdd[3]
  PIN ve_pdd[4]
    DIRECTION INPUT ;
    USE SIGNAL ;
    PORT
      LAYER M5 ;
        RECT  13.536 172.716 13.56 172.8 ;
    END
  END ve_pdd[4]
  PIN ve_pdd[5]
    DIRECTION INPUT ;
    USE SIGNAL ;
    PORT
      LAYER M5 ;
        RECT  13.632 172.716 13.656 172.8 ;
    END
  END ve_pdd[5]
  PIN ve_pdd[6]
    DIRECTION INPUT ;
    USE SIGNAL ;
    PORT
      LAYER M5 ;
        RECT  13.824 172.716 13.848 172.8 ;
    END
  END ve_pdd[6]
  PIN ve_pdd[7]
    DIRECTION INPUT ;
    USE SIGNAL ;
    PORT
      LAYER M5 ;
        RECT  13.92 172.716 13.944 172.8 ;
    END
  END ve_pdd[7]
  PIN ve_pdd[8]
    DIRECTION INPUT ;
    USE SIGNAL ;
    PORT
      LAYER M5 ;
        RECT  14.112 172.716 14.136 172.8 ;
    END
  END ve_pdd[8]
  PIN ve_pdd[9]
    DIRECTION INPUT ;
    USE SIGNAL ;
    PORT
      LAYER M5 ;
        RECT  14.208 172.716 14.232 172.8 ;
    END
  END ve_pdd[9]
  PIN ve_phh[0]
    DIRECTION INPUT ;
    USE SIGNAL ;
    PORT
      LAYER M5 ;
        RECT  4.8 172.716 4.824 172.8 ;
    END
  END ve_phh[0]
  PIN ve_phh[10]
    DIRECTION INPUT ;
    USE SIGNAL ;
    PORT
      LAYER M5 ;
        RECT  6.048 172.716 6.072 172.8 ;
    END
  END ve_phh[10]
  PIN ve_phh[11]
    DIRECTION INPUT ;
    USE SIGNAL ;
    PORT
      LAYER M5 ;
        RECT  6.144 172.716 6.168 172.8 ;
    END
  END ve_phh[11]
  PIN ve_phh[12]
    DIRECTION INPUT ;
    USE SIGNAL ;
    PORT
      LAYER M5 ;
        RECT  6.864 172.716 6.888 172.8 ;
    END
  END ve_phh[12]
  PIN ve_phh[13]
    DIRECTION INPUT ;
    USE SIGNAL ;
    PORT
      LAYER M5 ;
        RECT  6.96 172.716 6.984 172.8 ;
    END
  END ve_phh[13]
  PIN ve_phh[14]
    DIRECTION INPUT ;
    USE SIGNAL ;
    PORT
      LAYER M5 ;
        RECT  7.056 172.716 7.08 172.8 ;
    END
  END ve_phh[14]
  PIN ve_phh[15]
    DIRECTION INPUT ;
    USE SIGNAL ;
    PORT
      LAYER M5 ;
        RECT  7.152 172.716 7.176 172.8 ;
    END
  END ve_phh[15]
  PIN ve_phh[16]
    DIRECTION INPUT ;
    USE SIGNAL ;
    PORT
      LAYER M5 ;
        RECT  7.248 172.716 7.272 172.8 ;
    END
  END ve_phh[16]
  PIN ve_phh[17]
    DIRECTION INPUT ;
    USE SIGNAL ;
    PORT
      LAYER M5 ;
        RECT  7.344 172.716 7.368 172.8 ;
    END
  END ve_phh[17]
  PIN ve_phh[18]
    DIRECTION INPUT ;
    USE SIGNAL ;
    PORT
      LAYER M5 ;
        RECT  7.44 172.716 7.464 172.8 ;
    END
  END ve_phh[18]
  PIN ve_phh[19]
    DIRECTION INPUT ;
    USE SIGNAL ;
    PORT
      LAYER M5 ;
        RECT  7.536 172.716 7.56 172.8 ;
    END
  END ve_phh[19]
  PIN ve_phh[1]
    DIRECTION INPUT ;
    USE SIGNAL ;
    PORT
      LAYER M5 ;
        RECT  4.896 172.716 4.92 172.8 ;
    END
  END ve_phh[1]
  PIN ve_phh[20]
    DIRECTION INPUT ;
    USE SIGNAL ;
    PORT
      LAYER M5 ;
        RECT  7.632 172.716 7.656 172.8 ;
    END
  END ve_phh[20]
  PIN ve_phh[21]
    DIRECTION INPUT ;
    USE SIGNAL ;
    PORT
      LAYER M5 ;
        RECT  7.728 172.716 7.752 172.8 ;
    END
  END ve_phh[21]
  PIN ve_phh[22]
    DIRECTION INPUT ;
    USE SIGNAL ;
    PORT
      LAYER M5 ;
        RECT  7.824 172.716 7.848 172.8 ;
    END
  END ve_phh[22]
  PIN ve_phh[23]
    DIRECTION INPUT ;
    USE SIGNAL ;
    PORT
      LAYER M5 ;
        RECT  7.92 172.716 7.944 172.8 ;
    END
  END ve_phh[23]
  PIN ve_phh[24]
    DIRECTION INPUT ;
    USE SIGNAL ;
    PORT
      LAYER M5 ;
        RECT  8.016 172.716 8.04 172.8 ;
    END
  END ve_phh[24]
  PIN ve_phh[25]
    DIRECTION INPUT ;
    USE SIGNAL ;
    PORT
      LAYER M5 ;
        RECT  8.112 172.716 8.136 172.8 ;
    END
  END ve_phh[25]
  PIN ve_phh[26]
    DIRECTION INPUT ;
    USE SIGNAL ;
    PORT
      LAYER M5 ;
        RECT  8.208 172.716 8.232 172.8 ;
    END
  END ve_phh[26]
  PIN ve_phh[27]
    DIRECTION INPUT ;
    USE SIGNAL ;
    PORT
      LAYER M5 ;
        RECT  8.304 172.716 8.328 172.8 ;
    END
  END ve_phh[27]
  PIN ve_phh[28]
    DIRECTION INPUT ;
    USE SIGNAL ;
    PORT
      LAYER M5 ;
        RECT  8.4 172.716 8.424 172.8 ;
    END
  END ve_phh[28]
  PIN ve_phh[29]
    DIRECTION INPUT ;
    USE SIGNAL ;
    PORT
      LAYER M5 ;
        RECT  8.496 172.716 8.52 172.8 ;
    END
  END ve_phh[29]
  PIN ve_phh[2]
    DIRECTION INPUT ;
    USE SIGNAL ;
    PORT
      LAYER M5 ;
        RECT  4.992 172.716 5.016 172.8 ;
    END
  END ve_phh[2]
  PIN ve_phh[30]
    DIRECTION INPUT ;
    USE SIGNAL ;
    PORT
      LAYER M5 ;
        RECT  8.64 172.716 8.664 172.8 ;
    END
  END ve_phh[30]
  PIN ve_phh[31]
    DIRECTION INPUT ;
    USE SIGNAL ;
    PORT
      LAYER M5 ;
        RECT  8.736 172.716 8.76 172.8 ;
    END
  END ve_phh[31]
  PIN ve_phh[3]
    DIRECTION INPUT ;
    USE SIGNAL ;
    PORT
      LAYER M5 ;
        RECT  5.184 172.716 5.208 172.8 ;
    END
  END ve_phh[3]
  PIN ve_phh[4]
    DIRECTION INPUT ;
    USE SIGNAL ;
    PORT
      LAYER M5 ;
        RECT  5.28 172.716 5.304 172.8 ;
    END
  END ve_phh[4]
  PIN ve_phh[5]
    DIRECTION INPUT ;
    USE SIGNAL ;
    PORT
      LAYER M5 ;
        RECT  5.376 172.716 5.4 172.8 ;
    END
  END ve_phh[5]
  PIN ve_phh[6]
    DIRECTION INPUT ;
    USE SIGNAL ;
    PORT
      LAYER M5 ;
        RECT  5.568 172.716 5.592 172.8 ;
    END
  END ve_phh[6]
  PIN ve_phh[7]
    DIRECTION INPUT ;
    USE SIGNAL ;
    PORT
      LAYER M5 ;
        RECT  5.664 172.716 5.688 172.8 ;
    END
  END ve_phh[7]
  PIN ve_phh[8]
    DIRECTION INPUT ;
    USE SIGNAL ;
    PORT
      LAYER M5 ;
        RECT  5.76 172.716 5.784 172.8 ;
    END
  END ve_phh[8]
  PIN ve_phh[9]
    DIRECTION INPUT ;
    USE SIGNAL ;
    PORT
      LAYER M5 ;
        RECT  5.856 172.716 5.88 172.8 ;
    END
  END ve_phh[9]
  PIN ve_pkk[0]
    DIRECTION INPUT ;
    USE SIGNAL ;
    PORT
      LAYER M5 ;
        RECT  8.928 172.716 8.952 172.8 ;
    END
  END ve_pkk[0]
  PIN ve_pkk[10]
    DIRECTION INPUT ;
    USE SIGNAL ;
    PORT
      LAYER M5 ;
        RECT  10.176 172.716 10.2 172.8 ;
    END
  END ve_pkk[10]
  PIN ve_pkk[11]
    DIRECTION INPUT ;
    USE SIGNAL ;
    PORT
      LAYER M5 ;
        RECT  10.368 172.716 10.392 172.8 ;
    END
  END ve_pkk[11]
  PIN ve_pkk[12]
    DIRECTION INPUT ;
    USE SIGNAL ;
    PORT
      LAYER M5 ;
        RECT  10.464 172.716 10.488 172.8 ;
    END
  END ve_pkk[12]
  PIN ve_pkk[13]
    DIRECTION INPUT ;
    USE SIGNAL ;
    PORT
      LAYER M5 ;
        RECT  11.184 172.716 11.208 172.8 ;
    END
  END ve_pkk[13]
  PIN ve_pkk[14]
    DIRECTION INPUT ;
    USE SIGNAL ;
    PORT
      LAYER M5 ;
        RECT  11.28 172.716 11.304 172.8 ;
    END
  END ve_pkk[14]
  PIN ve_pkk[15]
    DIRECTION INPUT ;
    USE SIGNAL ;
    PORT
      LAYER M5 ;
        RECT  11.376 172.716 11.4 172.8 ;
    END
  END ve_pkk[15]
  PIN ve_pkk[16]
    DIRECTION INPUT ;
    USE SIGNAL ;
    PORT
      LAYER M5 ;
        RECT  11.472 172.716 11.496 172.8 ;
    END
  END ve_pkk[16]
  PIN ve_pkk[17]
    DIRECTION INPUT ;
    USE SIGNAL ;
    PORT
      LAYER M5 ;
        RECT  11.568 172.716 11.592 172.8 ;
    END
  END ve_pkk[17]
  PIN ve_pkk[18]
    DIRECTION INPUT ;
    USE SIGNAL ;
    PORT
      LAYER M5 ;
        RECT  11.664 172.716 11.688 172.8 ;
    END
  END ve_pkk[18]
  PIN ve_pkk[19]
    DIRECTION INPUT ;
    USE SIGNAL ;
    PORT
      LAYER M5 ;
        RECT  11.76 172.716 11.784 172.8 ;
    END
  END ve_pkk[19]
  PIN ve_pkk[1]
    DIRECTION INPUT ;
    USE SIGNAL ;
    PORT
      LAYER M5 ;
        RECT  9.024 172.716 9.048 172.8 ;
    END
  END ve_pkk[1]
  PIN ve_pkk[20]
    DIRECTION INPUT ;
    USE SIGNAL ;
    PORT
      LAYER M5 ;
        RECT  11.856 172.716 11.88 172.8 ;
    END
  END ve_pkk[20]
  PIN ve_pkk[21]
    DIRECTION INPUT ;
    USE SIGNAL ;
    PORT
      LAYER M5 ;
        RECT  11.952 172.716 11.976 172.8 ;
    END
  END ve_pkk[21]
  PIN ve_pkk[22]
    DIRECTION INPUT ;
    USE SIGNAL ;
    PORT
      LAYER M5 ;
        RECT  12.048 172.716 12.072 172.8 ;
    END
  END ve_pkk[22]
  PIN ve_pkk[23]
    DIRECTION INPUT ;
    USE SIGNAL ;
    PORT
      LAYER M5 ;
        RECT  12.144 172.716 12.168 172.8 ;
    END
  END ve_pkk[23]
  PIN ve_pkk[24]
    DIRECTION INPUT ;
    USE SIGNAL ;
    PORT
      LAYER M5 ;
        RECT  12.24 172.716 12.264 172.8 ;
    END
  END ve_pkk[24]
  PIN ve_pkk[25]
    DIRECTION INPUT ;
    USE SIGNAL ;
    PORT
      LAYER M5 ;
        RECT  12.336 172.716 12.36 172.8 ;
    END
  END ve_pkk[25]
  PIN ve_pkk[26]
    DIRECTION INPUT ;
    USE SIGNAL ;
    PORT
      LAYER M5 ;
        RECT  12.432 172.716 12.456 172.8 ;
    END
  END ve_pkk[26]
  PIN ve_pkk[27]
    DIRECTION INPUT ;
    USE SIGNAL ;
    PORT
      LAYER M5 ;
        RECT  12.528 172.716 12.552 172.8 ;
    END
  END ve_pkk[27]
  PIN ve_pkk[28]
    DIRECTION INPUT ;
    USE SIGNAL ;
    PORT
      LAYER M5 ;
        RECT  12.624 172.716 12.648 172.8 ;
    END
  END ve_pkk[28]
  PIN ve_pkk[29]
    DIRECTION INPUT ;
    USE SIGNAL ;
    PORT
      LAYER M5 ;
        RECT  12.72 172.716 12.744 172.8 ;
    END
  END ve_pkk[29]
  PIN ve_pkk[2]
    DIRECTION INPUT ;
    USE SIGNAL ;
    PORT
      LAYER M5 ;
        RECT  9.12 172.716 9.144 172.8 ;
    END
  END ve_pkk[2]
  PIN ve_pkk[30]
    DIRECTION INPUT ;
    USE SIGNAL ;
    PORT
      LAYER M5 ;
        RECT  12.816 172.716 12.84 172.8 ;
    END
  END ve_pkk[30]
  PIN ve_pkk[31]
    DIRECTION INPUT ;
    USE SIGNAL ;
    PORT
      LAYER M5 ;
        RECT  12.96 172.716 12.984 172.8 ;
    END
  END ve_pkk[31]
  PIN ve_pkk[3]
    DIRECTION INPUT ;
    USE SIGNAL ;
    PORT
      LAYER M5 ;
        RECT  9.312 172.716 9.336 172.8 ;
    END
  END ve_pkk[3]
  PIN ve_pkk[4]
    DIRECTION INPUT ;
    USE SIGNAL ;
    PORT
      LAYER M5 ;
        RECT  9.408 172.716 9.432 172.8 ;
    END
  END ve_pkk[4]
  PIN ve_pkk[5]
    DIRECTION INPUT ;
    USE SIGNAL ;
    PORT
      LAYER M5 ;
        RECT  9.6 172.716 9.624 172.8 ;
    END
  END ve_pkk[5]
  PIN ve_pkk[6]
    DIRECTION INPUT ;
    USE SIGNAL ;
    PORT
      LAYER M5 ;
        RECT  9.696 172.716 9.72 172.8 ;
    END
  END ve_pkk[6]
  PIN ve_pkk[7]
    DIRECTION INPUT ;
    USE SIGNAL ;
    PORT
      LAYER M5 ;
        RECT  9.792 172.716 9.816 172.8 ;
    END
  END ve_pkk[7]
  PIN ve_pkk[8]
    DIRECTION INPUT ;
    USE SIGNAL ;
    PORT
      LAYER M5 ;
        RECT  9.984 172.716 10.008 172.8 ;
    END
  END ve_pkk[8]
  PIN ve_pkk[9]
    DIRECTION INPUT ;
    USE SIGNAL ;
    PORT
      LAYER M5 ;
        RECT  10.08 172.716 10.104 172.8 ;
    END
  END ve_pkk[9]
  PIN ve_pv
    DIRECTION INPUT ;
    USE SIGNAL ;
    PORT
      LAYER M5 ;
        RECT  4.416 172.716 4.44 172.8 ;
    END
  END ve_pv
  PIN ve_rc[0]
    DIRECTION OUTPUT ;
    USE SIGNAL ;
    PORT
      LAYER M5 ;
        RECT  55.728 172.716 55.752 172.8 ;
    END
  END ve_rc[0]
  PIN ve_rc[1]
    DIRECTION OUTPUT ;
    USE SIGNAL ;
    PORT
      LAYER M5 ;
        RECT  55.824 172.716 55.848 172.8 ;
    END
  END ve_rc[1]
  PIN ve_rh[0]
    DIRECTION OUTPUT ;
    USE SIGNAL ;
    PORT
      LAYER M5 ;
        RECT  55.92 172.716 55.944 172.8 ;
    END
  END ve_rh[0]
  PIN ve_rh[10]
    DIRECTION OUTPUT ;
    USE SIGNAL ;
    PORT
      LAYER M5 ;
        RECT  57.12 172.716 57.144 172.8 ;
    END
  END ve_rh[10]
  PIN ve_rh[11]
    DIRECTION OUTPUT ;
    USE SIGNAL ;
    PORT
      LAYER M5 ;
        RECT  57.216 172.716 57.24 172.8 ;
    END
  END ve_rh[11]
  PIN ve_rh[12]
    DIRECTION OUTPUT ;
    USE SIGNAL ;
    PORT
      LAYER M5 ;
        RECT  57.408 172.716 57.432 172.8 ;
    END
  END ve_rh[12]
  PIN ve_rh[13]
    DIRECTION OUTPUT ;
    USE SIGNAL ;
    PORT
      LAYER M5 ;
        RECT  57.504 172.716 57.528 172.8 ;
    END
  END ve_rh[13]
  PIN ve_rh[14]
    DIRECTION OUTPUT ;
    USE SIGNAL ;
    PORT
      LAYER M5 ;
        RECT  57.6 172.716 57.624 172.8 ;
    END
  END ve_rh[14]
  PIN ve_rh[15]
    DIRECTION OUTPUT ;
    USE SIGNAL ;
    PORT
      LAYER M5 ;
        RECT  57.696 172.716 57.72 172.8 ;
    END
  END ve_rh[15]
  PIN ve_rh[16]
    DIRECTION OUTPUT ;
    USE SIGNAL ;
    PORT
      LAYER M5 ;
        RECT  57.888 172.716 57.912 172.8 ;
    END
  END ve_rh[16]
  PIN ve_rh[17]
    DIRECTION OUTPUT ;
    USE SIGNAL ;
    PORT
      LAYER M5 ;
        RECT  57.984 172.716 58.008 172.8 ;
    END
  END ve_rh[17]
  PIN ve_rh[18]
    DIRECTION OUTPUT ;
    USE SIGNAL ;
    PORT
      LAYER M5 ;
        RECT  58.704 172.716 58.728 172.8 ;
    END
  END ve_rh[18]
  PIN ve_rh[19]
    DIRECTION OUTPUT ;
    USE SIGNAL ;
    PORT
      LAYER M5 ;
        RECT  58.8 172.716 58.824 172.8 ;
    END
  END ve_rh[19]
  PIN ve_rh[1]
    DIRECTION OUTPUT ;
    USE SIGNAL ;
    PORT
      LAYER M5 ;
        RECT  56.016 172.716 56.04 172.8 ;
    END
  END ve_rh[1]
  PIN ve_rh[20]
    DIRECTION OUTPUT ;
    USE SIGNAL ;
    PORT
      LAYER M5 ;
        RECT  58.896 172.716 58.92 172.8 ;
    END
  END ve_rh[20]
  PIN ve_rh[21]
    DIRECTION OUTPUT ;
    USE SIGNAL ;
    PORT
      LAYER M5 ;
        RECT  58.992 172.716 59.016 172.8 ;
    END
  END ve_rh[21]
  PIN ve_rh[22]
    DIRECTION OUTPUT ;
    USE SIGNAL ;
    PORT
      LAYER M5 ;
        RECT  59.088 172.716 59.112 172.8 ;
    END
  END ve_rh[22]
  PIN ve_rh[23]
    DIRECTION OUTPUT ;
    USE SIGNAL ;
    PORT
      LAYER M5 ;
        RECT  59.184 172.716 59.208 172.8 ;
    END
  END ve_rh[23]
  PIN ve_rh[24]
    DIRECTION OUTPUT ;
    USE SIGNAL ;
    PORT
      LAYER M5 ;
        RECT  59.28 172.716 59.304 172.8 ;
    END
  END ve_rh[24]
  PIN ve_rh[25]
    DIRECTION OUTPUT ;
    USE SIGNAL ;
    PORT
      LAYER M5 ;
        RECT  59.376 172.716 59.4 172.8 ;
    END
  END ve_rh[25]
  PIN ve_rh[26]
    DIRECTION OUTPUT ;
    USE SIGNAL ;
    PORT
      LAYER M5 ;
        RECT  59.472 172.716 59.496 172.8 ;
    END
  END ve_rh[26]
  PIN ve_rh[27]
    DIRECTION OUTPUT ;
    USE SIGNAL ;
    PORT
      LAYER M5 ;
        RECT  59.568 172.716 59.592 172.8 ;
    END
  END ve_rh[27]
  PIN ve_rh[28]
    DIRECTION OUTPUT ;
    USE SIGNAL ;
    PORT
      LAYER M5 ;
        RECT  59.664 172.716 59.688 172.8 ;
    END
  END ve_rh[28]
  PIN ve_rh[29]
    DIRECTION OUTPUT ;
    USE SIGNAL ;
    PORT
      LAYER M5 ;
        RECT  59.76 172.716 59.784 172.8 ;
    END
  END ve_rh[29]
  PIN ve_rh[2]
    DIRECTION OUTPUT ;
    USE SIGNAL ;
    PORT
      LAYER M5 ;
        RECT  56.112 172.716 56.136 172.8 ;
    END
  END ve_rh[2]
  PIN ve_rh[30]
    DIRECTION OUTPUT ;
    USE SIGNAL ;
    PORT
      LAYER M5 ;
        RECT  59.856 172.716 59.88 172.8 ;
    END
  END ve_rh[30]
  PIN ve_rh[31]
    DIRECTION OUTPUT ;
    USE SIGNAL ;
    PORT
      LAYER M5 ;
        RECT  59.952 172.716 59.976 172.8 ;
    END
  END ve_rh[31]
  PIN ve_rh[32]
    DIRECTION OUTPUT ;
    USE SIGNAL ;
    PORT
      LAYER M5 ;
        RECT  60.048 172.716 60.072 172.8 ;
    END
  END ve_rh[32]
  PIN ve_rh[33]
    DIRECTION OUTPUT ;
    USE SIGNAL ;
    PORT
      LAYER M5 ;
        RECT  60.144 172.716 60.168 172.8 ;
    END
  END ve_rh[33]
  PIN ve_rh[34]
    DIRECTION OUTPUT ;
    USE SIGNAL ;
    PORT
      LAYER M5 ;
        RECT  60.24 172.716 60.264 172.8 ;
    END
  END ve_rh[34]
  PIN ve_rh[35]
    DIRECTION OUTPUT ;
    USE SIGNAL ;
    PORT
      LAYER M5 ;
        RECT  60.336 172.716 60.36 172.8 ;
    END
  END ve_rh[35]
  PIN ve_rh[36]
    DIRECTION OUTPUT ;
    USE SIGNAL ;
    PORT
      LAYER M5 ;
        RECT  60.48 172.716 60.504 172.8 ;
    END
  END ve_rh[36]
  PIN ve_rh[37]
    DIRECTION OUTPUT ;
    USE SIGNAL ;
    PORT
      LAYER M5 ;
        RECT  60.576 172.716 60.6 172.8 ;
    END
  END ve_rh[37]
  PIN ve_rh[38]
    DIRECTION OUTPUT ;
    USE SIGNAL ;
    PORT
      LAYER M5 ;
        RECT  60.768 172.716 60.792 172.8 ;
    END
  END ve_rh[38]
  PIN ve_rh[39]
    DIRECTION OUTPUT ;
    USE SIGNAL ;
    PORT
      LAYER M5 ;
        RECT  60.864 172.716 60.888 172.8 ;
    END
  END ve_rh[39]
  PIN ve_rh[3]
    DIRECTION OUTPUT ;
    USE SIGNAL ;
    PORT
      LAYER M5 ;
        RECT  56.256 172.716 56.28 172.8 ;
    END
  END ve_rh[3]
  PIN ve_rh[40]
    DIRECTION OUTPUT ;
    USE SIGNAL ;
    PORT
      LAYER M5 ;
        RECT  60.96 172.716 60.984 172.8 ;
    END
  END ve_rh[40]
  PIN ve_rh[41]
    DIRECTION OUTPUT ;
    USE SIGNAL ;
    PORT
      LAYER M5 ;
        RECT  61.152 172.716 61.176 172.8 ;
    END
  END ve_rh[41]
  PIN ve_rh[42]
    DIRECTION OUTPUT ;
    USE SIGNAL ;
    PORT
      LAYER M5 ;
        RECT  61.248 172.716 61.272 172.8 ;
    END
  END ve_rh[42]
  PIN ve_rh[43]
    DIRECTION OUTPUT ;
    USE SIGNAL ;
    PORT
      LAYER M5 ;
        RECT  61.44 172.716 61.464 172.8 ;
    END
  END ve_rh[43]
  PIN ve_rh[44]
    DIRECTION OUTPUT ;
    USE SIGNAL ;
    PORT
      LAYER M5 ;
        RECT  61.536 172.716 61.56 172.8 ;
    END
  END ve_rh[44]
  PIN ve_rh[45]
    DIRECTION OUTPUT ;
    USE SIGNAL ;
    PORT
      LAYER M5 ;
        RECT  61.632 172.716 61.656 172.8 ;
    END
  END ve_rh[45]
  PIN ve_rh[46]
    DIRECTION OUTPUT ;
    USE SIGNAL ;
    PORT
      LAYER M5 ;
        RECT  61.728 172.716 61.752 172.8 ;
    END
  END ve_rh[46]
  PIN ve_rh[47]
    DIRECTION OUTPUT ;
    USE SIGNAL ;
    PORT
      LAYER M5 ;
        RECT  61.92 172.716 61.944 172.8 ;
    END
  END ve_rh[47]
  PIN ve_rh[48]
    DIRECTION OUTPUT ;
    USE SIGNAL ;
    PORT
      LAYER M5 ;
        RECT  62.016 172.716 62.04 172.8 ;
    END
  END ve_rh[48]
  PIN ve_rh[49]
    DIRECTION OUTPUT ;
    USE SIGNAL ;
    PORT
      LAYER M5 ;
        RECT  62.112 172.716 62.136 172.8 ;
    END
  END ve_rh[49]
  PIN ve_rh[4]
    DIRECTION OUTPUT ;
    USE SIGNAL ;
    PORT
      LAYER M5 ;
        RECT  56.352 172.716 56.376 172.8 ;
    END
  END ve_rh[4]
  PIN ve_rh[50]
    DIRECTION OUTPUT ;
    USE SIGNAL ;
    PORT
      LAYER M5 ;
        RECT  62.304 172.716 62.328 172.8 ;
    END
  END ve_rh[50]
  PIN ve_rh[51]
    DIRECTION OUTPUT ;
    USE SIGNAL ;
    PORT
      LAYER M5 ;
        RECT  63.024 172.716 63.048 172.8 ;
    END
  END ve_rh[51]
  PIN ve_rh[52]
    DIRECTION OUTPUT ;
    USE SIGNAL ;
    PORT
      LAYER M5 ;
        RECT  63.12 172.716 63.144 172.8 ;
    END
  END ve_rh[52]
  PIN ve_rh[53]
    DIRECTION OUTPUT ;
    USE SIGNAL ;
    PORT
      LAYER M5 ;
        RECT  63.216 172.716 63.24 172.8 ;
    END
  END ve_rh[53]
  PIN ve_rh[54]
    DIRECTION OUTPUT ;
    USE SIGNAL ;
    PORT
      LAYER M5 ;
        RECT  63.312 172.716 63.336 172.8 ;
    END
  END ve_rh[54]
  PIN ve_rh[55]
    DIRECTION OUTPUT ;
    USE SIGNAL ;
    PORT
      LAYER M5 ;
        RECT  63.408 172.716 63.432 172.8 ;
    END
  END ve_rh[55]
  PIN ve_rh[56]
    DIRECTION OUTPUT ;
    USE SIGNAL ;
    PORT
      LAYER M5 ;
        RECT  63.504 172.716 63.528 172.8 ;
    END
  END ve_rh[56]
  PIN ve_rh[57]
    DIRECTION OUTPUT ;
    USE SIGNAL ;
    PORT
      LAYER M5 ;
        RECT  63.6 172.716 63.624 172.8 ;
    END
  END ve_rh[57]
  PIN ve_rh[58]
    DIRECTION OUTPUT ;
    USE SIGNAL ;
    PORT
      LAYER M5 ;
        RECT  63.696 172.716 63.72 172.8 ;
    END
  END ve_rh[58]
  PIN ve_rh[59]
    DIRECTION OUTPUT ;
    USE SIGNAL ;
    PORT
      LAYER M5 ;
        RECT  63.792 172.716 63.816 172.8 ;
    END
  END ve_rh[59]
  PIN ve_rh[5]
    DIRECTION OUTPUT ;
    USE SIGNAL ;
    PORT
      LAYER M5 ;
        RECT  56.448 172.716 56.472 172.8 ;
    END
  END ve_rh[5]
  PIN ve_rh[60]
    DIRECTION OUTPUT ;
    USE SIGNAL ;
    PORT
      LAYER M5 ;
        RECT  63.888 172.716 63.912 172.8 ;
    END
  END ve_rh[60]
  PIN ve_rh[61]
    DIRECTION OUTPUT ;
    USE SIGNAL ;
    PORT
      LAYER M5 ;
        RECT  63.984 172.716 64.008 172.8 ;
    END
  END ve_rh[61]
  PIN ve_rh[62]
    DIRECTION OUTPUT ;
    USE SIGNAL ;
    PORT
      LAYER M5 ;
        RECT  64.08 172.716 64.104 172.8 ;
    END
  END ve_rh[62]
  PIN ve_rh[63]
    DIRECTION OUTPUT ;
    USE SIGNAL ;
    PORT
      LAYER M5 ;
        RECT  64.176 172.716 64.2 172.8 ;
    END
  END ve_rh[63]
  PIN ve_rh[6]
    DIRECTION OUTPUT ;
    USE SIGNAL ;
    PORT
      LAYER M5 ;
        RECT  56.544 172.716 56.568 172.8 ;
    END
  END ve_rh[6]
  PIN ve_rh[7]
    DIRECTION OUTPUT ;
    USE SIGNAL ;
    PORT
      LAYER M5 ;
        RECT  56.736 172.716 56.76 172.8 ;
    END
  END ve_rh[7]
  PIN ve_rh[8]
    DIRECTION OUTPUT ;
    USE SIGNAL ;
    PORT
      LAYER M5 ;
        RECT  56.832 172.716 56.856 172.8 ;
    END
  END ve_rh[8]
  PIN ve_rh[9]
    DIRECTION OUTPUT ;
    USE SIGNAL ;
    PORT
      LAYER M5 ;
        RECT  56.928 172.716 56.952 172.8 ;
    END
  END ve_rh[9]
  PIN ve_rk[0]
    DIRECTION OUTPUT ;
    USE SIGNAL ;
    PORT
      LAYER M5 ;
        RECT  64.272 172.716 64.296 172.8 ;
    END
  END ve_rk[0]
  PIN ve_rk[100]
    DIRECTION OUTPUT ;
    USE SIGNAL ;
    PORT
      LAYER M5 ;
        RECT  77.232 172.716 77.256 172.8 ;
    END
  END ve_rk[100]
  PIN ve_rk[101]
    DIRECTION OUTPUT ;
    USE SIGNAL ;
    PORT
      LAYER M5 ;
        RECT  77.328 172.716 77.352 172.8 ;
    END
  END ve_rk[101]
  PIN ve_rk[102]
    DIRECTION OUTPUT ;
    USE SIGNAL ;
    PORT
      LAYER M5 ;
        RECT  77.424 172.716 77.448 172.8 ;
    END
  END ve_rk[102]
  PIN ve_rk[103]
    DIRECTION OUTPUT ;
    USE SIGNAL ;
    PORT
      LAYER M5 ;
        RECT  77.52 172.716 77.544 172.8 ;
    END
  END ve_rk[103]
  PIN ve_rk[104]
    DIRECTION OUTPUT ;
    USE SIGNAL ;
    PORT
      LAYER M5 ;
        RECT  77.616 172.716 77.64 172.8 ;
    END
  END ve_rk[104]
  PIN ve_rk[105]
    DIRECTION OUTPUT ;
    USE SIGNAL ;
    PORT
      LAYER M5 ;
        RECT  77.712 172.716 77.736 172.8 ;
    END
  END ve_rk[105]
  PIN ve_rk[106]
    DIRECTION OUTPUT ;
    USE SIGNAL ;
    PORT
      LAYER M5 ;
        RECT  77.856 172.716 77.88 172.8 ;
    END
  END ve_rk[106]
  PIN ve_rk[107]
    DIRECTION OUTPUT ;
    USE SIGNAL ;
    PORT
      LAYER M5 ;
        RECT  77.952 172.716 77.976 172.8 ;
    END
  END ve_rk[107]
  PIN ve_rk[108]
    DIRECTION OUTPUT ;
    USE SIGNAL ;
    PORT
      LAYER M5 ;
        RECT  78.048 172.716 78.072 172.8 ;
    END
  END ve_rk[108]
  PIN ve_rk[109]
    DIRECTION OUTPUT ;
    USE SIGNAL ;
    PORT
      LAYER M5 ;
        RECT  78.24 172.716 78.264 172.8 ;
    END
  END ve_rk[109]
  PIN ve_rk[10]
    DIRECTION OUTPUT ;
    USE SIGNAL ;
    PORT
      LAYER M5 ;
        RECT  65.376 172.716 65.4 172.8 ;
    END
  END ve_rk[10]
  PIN ve_rk[110]
    DIRECTION OUTPUT ;
    USE SIGNAL ;
    PORT
      LAYER M5 ;
        RECT  78.336 172.716 78.36 172.8 ;
    END
  END ve_rk[110]
  PIN ve_rk[111]
    DIRECTION OUTPUT ;
    USE SIGNAL ;
    PORT
      LAYER M5 ;
        RECT  78.432 172.716 78.456 172.8 ;
    END
  END ve_rk[111]
  PIN ve_rk[112]
    DIRECTION OUTPUT ;
    USE SIGNAL ;
    PORT
      LAYER M5 ;
        RECT  78.624 172.716 78.648 172.8 ;
    END
  END ve_rk[112]
  PIN ve_rk[113]
    DIRECTION OUTPUT ;
    USE SIGNAL ;
    PORT
      LAYER M5 ;
        RECT  78.72 172.716 78.744 172.8 ;
    END
  END ve_rk[113]
  PIN ve_rk[114]
    DIRECTION OUTPUT ;
    USE SIGNAL ;
    PORT
      LAYER M5 ;
        RECT  78.912 172.716 78.936 172.8 ;
    END
  END ve_rk[114]
  PIN ve_rk[115]
    DIRECTION OUTPUT ;
    USE SIGNAL ;
    PORT
      LAYER M5 ;
        RECT  79.008 172.716 79.032 172.8 ;
    END
  END ve_rk[115]
  PIN ve_rk[116]
    DIRECTION OUTPUT ;
    USE SIGNAL ;
    PORT
      LAYER M5 ;
        RECT  79.104 172.716 79.128 172.8 ;
    END
  END ve_rk[116]
  PIN ve_rk[117]
    DIRECTION OUTPUT ;
    USE SIGNAL ;
    PORT
      LAYER M5 ;
        RECT  79.296 172.716 79.32 172.8 ;
    END
  END ve_rk[117]
  PIN ve_rk[118]
    DIRECTION OUTPUT ;
    USE SIGNAL ;
    PORT
      LAYER M5 ;
        RECT  79.392 172.716 79.416 172.8 ;
    END
  END ve_rk[118]
  PIN ve_rk[119]
    DIRECTION OUTPUT ;
    USE SIGNAL ;
    PORT
      LAYER M5 ;
        RECT  79.584 172.716 79.608 172.8 ;
    END
  END ve_rk[119]
  PIN ve_rk[11]
    DIRECTION OUTPUT ;
    USE SIGNAL ;
    PORT
      LAYER M5 ;
        RECT  65.472 172.716 65.496 172.8 ;
    END
  END ve_rk[11]
  PIN ve_rk[120]
    DIRECTION OUTPUT ;
    USE SIGNAL ;
    PORT
      LAYER M5 ;
        RECT  80.304 172.716 80.328 172.8 ;
    END
  END ve_rk[120]
  PIN ve_rk[121]
    DIRECTION OUTPUT ;
    USE SIGNAL ;
    PORT
      LAYER M5 ;
        RECT  80.4 172.716 80.424 172.8 ;
    END
  END ve_rk[121]
  PIN ve_rk[122]
    DIRECTION OUTPUT ;
    USE SIGNAL ;
    PORT
      LAYER M5 ;
        RECT  80.496 172.716 80.52 172.8 ;
    END
  END ve_rk[122]
  PIN ve_rk[123]
    DIRECTION OUTPUT ;
    USE SIGNAL ;
    PORT
      LAYER M5 ;
        RECT  80.592 172.716 80.616 172.8 ;
    END
  END ve_rk[123]
  PIN ve_rk[124]
    DIRECTION OUTPUT ;
    USE SIGNAL ;
    PORT
      LAYER M5 ;
        RECT  80.688 172.716 80.712 172.8 ;
    END
  END ve_rk[124]
  PIN ve_rk[125]
    DIRECTION OUTPUT ;
    USE SIGNAL ;
    PORT
      LAYER M5 ;
        RECT  80.784 172.716 80.808 172.8 ;
    END
  END ve_rk[125]
  PIN ve_rk[126]
    DIRECTION OUTPUT ;
    USE SIGNAL ;
    PORT
      LAYER M5 ;
        RECT  80.88 172.716 80.904 172.8 ;
    END
  END ve_rk[126]
  PIN ve_rk[127]
    DIRECTION OUTPUT ;
    USE SIGNAL ;
    PORT
      LAYER M5 ;
        RECT  80.976 172.716 81 172.8 ;
    END
  END ve_rk[127]
  PIN ve_rk[12]
    DIRECTION OUTPUT ;
    USE SIGNAL ;
    PORT
      LAYER M5 ;
        RECT  65.664 172.716 65.688 172.8 ;
    END
  END ve_rk[12]
  PIN ve_rk[13]
    DIRECTION OUTPUT ;
    USE SIGNAL ;
    PORT
      LAYER M5 ;
        RECT  65.76 172.716 65.784 172.8 ;
    END
  END ve_rk[13]
  PIN ve_rk[14]
    DIRECTION OUTPUT ;
    USE SIGNAL ;
    PORT
      LAYER M5 ;
        RECT  65.952 172.716 65.976 172.8 ;
    END
  END ve_rk[14]
  PIN ve_rk[15]
    DIRECTION OUTPUT ;
    USE SIGNAL ;
    PORT
      LAYER M5 ;
        RECT  66.048 172.716 66.072 172.8 ;
    END
  END ve_rk[15]
  PIN ve_rk[16]
    DIRECTION OUTPUT ;
    USE SIGNAL ;
    PORT
      LAYER M5 ;
        RECT  66.144 172.716 66.168 172.8 ;
    END
  END ve_rk[16]
  PIN ve_rk[17]
    DIRECTION OUTPUT ;
    USE SIGNAL ;
    PORT
      LAYER M5 ;
        RECT  66.336 172.716 66.36 172.8 ;
    END
  END ve_rk[17]
  PIN ve_rk[18]
    DIRECTION OUTPUT ;
    USE SIGNAL ;
    PORT
      LAYER M5 ;
        RECT  66.432 172.716 66.456 172.8 ;
    END
  END ve_rk[18]
  PIN ve_rk[19]
    DIRECTION OUTPUT ;
    USE SIGNAL ;
    PORT
      LAYER M5 ;
        RECT  66.624 172.716 66.648 172.8 ;
    END
  END ve_rk[19]
  PIN ve_rk[1]
    DIRECTION OUTPUT ;
    USE SIGNAL ;
    PORT
      LAYER M5 ;
        RECT  64.368 172.716 64.392 172.8 ;
    END
  END ve_rk[1]
  PIN ve_rk[20]
    DIRECTION OUTPUT ;
    USE SIGNAL ;
    PORT
      LAYER M5 ;
        RECT  67.344 172.716 67.368 172.8 ;
    END
  END ve_rk[20]
  PIN ve_rk[21]
    DIRECTION OUTPUT ;
    USE SIGNAL ;
    PORT
      LAYER M5 ;
        RECT  67.44 172.716 67.464 172.8 ;
    END
  END ve_rk[21]
  PIN ve_rk[22]
    DIRECTION OUTPUT ;
    USE SIGNAL ;
    PORT
      LAYER M5 ;
        RECT  67.536 172.716 67.56 172.8 ;
    END
  END ve_rk[22]
  PIN ve_rk[23]
    DIRECTION OUTPUT ;
    USE SIGNAL ;
    PORT
      LAYER M5 ;
        RECT  67.632 172.716 67.656 172.8 ;
    END
  END ve_rk[23]
  PIN ve_rk[24]
    DIRECTION OUTPUT ;
    USE SIGNAL ;
    PORT
      LAYER M5 ;
        RECT  67.728 172.716 67.752 172.8 ;
    END
  END ve_rk[24]
  PIN ve_rk[25]
    DIRECTION OUTPUT ;
    USE SIGNAL ;
    PORT
      LAYER M5 ;
        RECT  67.824 172.716 67.848 172.8 ;
    END
  END ve_rk[25]
  PIN ve_rk[26]
    DIRECTION OUTPUT ;
    USE SIGNAL ;
    PORT
      LAYER M5 ;
        RECT  67.92 172.716 67.944 172.8 ;
    END
  END ve_rk[26]
  PIN ve_rk[27]
    DIRECTION OUTPUT ;
    USE SIGNAL ;
    PORT
      LAYER M5 ;
        RECT  68.016 172.716 68.04 172.8 ;
    END
  END ve_rk[27]
  PIN ve_rk[28]
    DIRECTION OUTPUT ;
    USE SIGNAL ;
    PORT
      LAYER M5 ;
        RECT  68.112 172.716 68.136 172.8 ;
    END
  END ve_rk[28]
  PIN ve_rk[29]
    DIRECTION OUTPUT ;
    USE SIGNAL ;
    PORT
      LAYER M5 ;
        RECT  68.208 172.716 68.232 172.8 ;
    END
  END ve_rk[29]
  PIN ve_rk[2]
    DIRECTION OUTPUT ;
    USE SIGNAL ;
    PORT
      LAYER M5 ;
        RECT  64.464 172.716 64.488 172.8 ;
    END
  END ve_rk[2]
  PIN ve_rk[30]
    DIRECTION OUTPUT ;
    USE SIGNAL ;
    PORT
      LAYER M5 ;
        RECT  68.304 172.716 68.328 172.8 ;
    END
  END ve_rk[30]
  PIN ve_rk[31]
    DIRECTION OUTPUT ;
    USE SIGNAL ;
    PORT
      LAYER M5 ;
        RECT  68.4 172.716 68.424 172.8 ;
    END
  END ve_rk[31]
  PIN ve_rk[32]
    DIRECTION OUTPUT ;
    USE SIGNAL ;
    PORT
      LAYER M5 ;
        RECT  68.496 172.716 68.52 172.8 ;
    END
  END ve_rk[32]
  PIN ve_rk[33]
    DIRECTION OUTPUT ;
    USE SIGNAL ;
    PORT
      LAYER M5 ;
        RECT  68.592 172.716 68.616 172.8 ;
    END
  END ve_rk[33]
  PIN ve_rk[34]
    DIRECTION OUTPUT ;
    USE SIGNAL ;
    PORT
      LAYER M5 ;
        RECT  68.688 172.716 68.712 172.8 ;
    END
  END ve_rk[34]
  PIN ve_rk[35]
    DIRECTION OUTPUT ;
    USE SIGNAL ;
    PORT
      LAYER M5 ;
        RECT  68.784 172.716 68.808 172.8 ;
    END
  END ve_rk[35]
  PIN ve_rk[36]
    DIRECTION OUTPUT ;
    USE SIGNAL ;
    PORT
      LAYER M5 ;
        RECT  68.88 172.716 68.904 172.8 ;
    END
  END ve_rk[36]
  PIN ve_rk[37]
    DIRECTION OUTPUT ;
    USE SIGNAL ;
    PORT
      LAYER M5 ;
        RECT  68.976 172.716 69 172.8 ;
    END
  END ve_rk[37]
  PIN ve_rk[38]
    DIRECTION OUTPUT ;
    USE SIGNAL ;
    PORT
      LAYER M5 ;
        RECT  69.072 172.716 69.096 172.8 ;
    END
  END ve_rk[38]
  PIN ve_rk[39]
    DIRECTION OUTPUT ;
    USE SIGNAL ;
    PORT
      LAYER M5 ;
        RECT  69.216 172.716 69.24 172.8 ;
    END
  END ve_rk[39]
  PIN ve_rk[3]
    DIRECTION OUTPUT ;
    USE SIGNAL ;
    PORT
      LAYER M5 ;
        RECT  64.56 172.716 64.584 172.8 ;
    END
  END ve_rk[3]
  PIN ve_rk[40]
    DIRECTION OUTPUT ;
    USE SIGNAL ;
    PORT
      LAYER M5 ;
        RECT  69.312 172.716 69.336 172.8 ;
    END
  END ve_rk[40]
  PIN ve_rk[41]
    DIRECTION OUTPUT ;
    USE SIGNAL ;
    PORT
      LAYER M5 ;
        RECT  69.408 172.716 69.432 172.8 ;
    END
  END ve_rk[41]
  PIN ve_rk[42]
    DIRECTION OUTPUT ;
    USE SIGNAL ;
    PORT
      LAYER M5 ;
        RECT  69.504 172.716 69.528 172.8 ;
    END
  END ve_rk[42]
  PIN ve_rk[43]
    DIRECTION OUTPUT ;
    USE SIGNAL ;
    PORT
      LAYER M5 ;
        RECT  69.696 172.716 69.72 172.8 ;
    END
  END ve_rk[43]
  PIN ve_rk[44]
    DIRECTION OUTPUT ;
    USE SIGNAL ;
    PORT
      LAYER M5 ;
        RECT  69.792 172.716 69.816 172.8 ;
    END
  END ve_rk[44]
  PIN ve_rk[45]
    DIRECTION OUTPUT ;
    USE SIGNAL ;
    PORT
      LAYER M5 ;
        RECT  69.888 172.716 69.912 172.8 ;
    END
  END ve_rk[45]
  PIN ve_rk[46]
    DIRECTION OUTPUT ;
    USE SIGNAL ;
    PORT
      LAYER M5 ;
        RECT  70.08 172.716 70.104 172.8 ;
    END
  END ve_rk[46]
  PIN ve_rk[47]
    DIRECTION OUTPUT ;
    USE SIGNAL ;
    PORT
      LAYER M5 ;
        RECT  70.176 172.716 70.2 172.8 ;
    END
  END ve_rk[47]
  PIN ve_rk[48]
    DIRECTION OUTPUT ;
    USE SIGNAL ;
    PORT
      LAYER M5 ;
        RECT  70.368 172.716 70.392 172.8 ;
    END
  END ve_rk[48]
  PIN ve_rk[49]
    DIRECTION OUTPUT ;
    USE SIGNAL ;
    PORT
      LAYER M5 ;
        RECT  70.464 172.716 70.488 172.8 ;
    END
  END ve_rk[49]
  PIN ve_rk[4]
    DIRECTION OUTPUT ;
    USE SIGNAL ;
    PORT
      LAYER M5 ;
        RECT  64.656 172.716 64.68 172.8 ;
    END
  END ve_rk[4]
  PIN ve_rk[50]
    DIRECTION OUTPUT ;
    USE SIGNAL ;
    PORT
      LAYER M5 ;
        RECT  70.56 172.716 70.584 172.8 ;
    END
  END ve_rk[50]
  PIN ve_rk[51]
    DIRECTION OUTPUT ;
    USE SIGNAL ;
    PORT
      LAYER M5 ;
        RECT  70.656 172.716 70.68 172.8 ;
    END
  END ve_rk[51]
  PIN ve_rk[52]
    DIRECTION OUTPUT ;
    USE SIGNAL ;
    PORT
      LAYER M5 ;
        RECT  70.848 172.716 70.872 172.8 ;
    END
  END ve_rk[52]
  PIN ve_rk[53]
    DIRECTION OUTPUT ;
    USE SIGNAL ;
    PORT
      LAYER M5 ;
        RECT  70.944 172.716 70.968 172.8 ;
    END
  END ve_rk[53]
  PIN ve_rk[54]
    DIRECTION OUTPUT ;
    USE SIGNAL ;
    PORT
      LAYER M5 ;
        RECT  71.664 172.716 71.688 172.8 ;
    END
  END ve_rk[54]
  PIN ve_rk[55]
    DIRECTION OUTPUT ;
    USE SIGNAL ;
    PORT
      LAYER M5 ;
        RECT  71.76 172.716 71.784 172.8 ;
    END
  END ve_rk[55]
  PIN ve_rk[56]
    DIRECTION OUTPUT ;
    USE SIGNAL ;
    PORT
      LAYER M5 ;
        RECT  71.856 172.716 71.88 172.8 ;
    END
  END ve_rk[56]
  PIN ve_rk[57]
    DIRECTION OUTPUT ;
    USE SIGNAL ;
    PORT
      LAYER M5 ;
        RECT  71.952 172.716 71.976 172.8 ;
    END
  END ve_rk[57]
  PIN ve_rk[58]
    DIRECTION OUTPUT ;
    USE SIGNAL ;
    PORT
      LAYER M5 ;
        RECT  72.048 172.716 72.072 172.8 ;
    END
  END ve_rk[58]
  PIN ve_rk[59]
    DIRECTION OUTPUT ;
    USE SIGNAL ;
    PORT
      LAYER M5 ;
        RECT  72.144 172.716 72.168 172.8 ;
    END
  END ve_rk[59]
  PIN ve_rk[5]
    DIRECTION OUTPUT ;
    USE SIGNAL ;
    PORT
      LAYER M5 ;
        RECT  64.752 172.716 64.776 172.8 ;
    END
  END ve_rk[5]
  PIN ve_rk[60]
    DIRECTION OUTPUT ;
    USE SIGNAL ;
    PORT
      LAYER M5 ;
        RECT  72.24 172.716 72.264 172.8 ;
    END
  END ve_rk[60]
  PIN ve_rk[61]
    DIRECTION OUTPUT ;
    USE SIGNAL ;
    PORT
      LAYER M5 ;
        RECT  72.336 172.716 72.36 172.8 ;
    END
  END ve_rk[61]
  PIN ve_rk[62]
    DIRECTION OUTPUT ;
    USE SIGNAL ;
    PORT
      LAYER M5 ;
        RECT  72.432 172.716 72.456 172.8 ;
    END
  END ve_rk[62]
  PIN ve_rk[63]
    DIRECTION OUTPUT ;
    USE SIGNAL ;
    PORT
      LAYER M5 ;
        RECT  72.528 172.716 72.552 172.8 ;
    END
  END ve_rk[63]
  PIN ve_rk[64]
    DIRECTION OUTPUT ;
    USE SIGNAL ;
    PORT
      LAYER M5 ;
        RECT  72.624 172.716 72.648 172.8 ;
    END
  END ve_rk[64]
  PIN ve_rk[65]
    DIRECTION OUTPUT ;
    USE SIGNAL ;
    PORT
      LAYER M5 ;
        RECT  72.72 172.716 72.744 172.8 ;
    END
  END ve_rk[65]
  PIN ve_rk[66]
    DIRECTION OUTPUT ;
    USE SIGNAL ;
    PORT
      LAYER M5 ;
        RECT  72.816 172.716 72.84 172.8 ;
    END
  END ve_rk[66]
  PIN ve_rk[67]
    DIRECTION OUTPUT ;
    USE SIGNAL ;
    PORT
      LAYER M5 ;
        RECT  72.912 172.716 72.936 172.8 ;
    END
  END ve_rk[67]
  PIN ve_rk[68]
    DIRECTION OUTPUT ;
    USE SIGNAL ;
    PORT
      LAYER M5 ;
        RECT  73.008 172.716 73.032 172.8 ;
    END
  END ve_rk[68]
  PIN ve_rk[69]
    DIRECTION OUTPUT ;
    USE SIGNAL ;
    PORT
      LAYER M5 ;
        RECT  73.104 172.716 73.128 172.8 ;
    END
  END ve_rk[69]
  PIN ve_rk[6]
    DIRECTION OUTPUT ;
    USE SIGNAL ;
    PORT
      LAYER M5 ;
        RECT  64.896 172.716 64.92 172.8 ;
    END
  END ve_rk[6]
  PIN ve_rk[70]
    DIRECTION OUTPUT ;
    USE SIGNAL ;
    PORT
      LAYER M5 ;
        RECT  73.2 172.716 73.224 172.8 ;
    END
  END ve_rk[70]
  PIN ve_rk[71]
    DIRECTION OUTPUT ;
    USE SIGNAL ;
    PORT
      LAYER M5 ;
        RECT  73.296 172.716 73.32 172.8 ;
    END
  END ve_rk[71]
  PIN ve_rk[72]
    DIRECTION OUTPUT ;
    USE SIGNAL ;
    PORT
      LAYER M5 ;
        RECT  73.44 172.716 73.464 172.8 ;
    END
  END ve_rk[72]
  PIN ve_rk[73]
    DIRECTION OUTPUT ;
    USE SIGNAL ;
    PORT
      LAYER M5 ;
        RECT  73.536 172.716 73.56 172.8 ;
    END
  END ve_rk[73]
  PIN ve_rk[74]
    DIRECTION OUTPUT ;
    USE SIGNAL ;
    PORT
      LAYER M5 ;
        RECT  73.728 172.716 73.752 172.8 ;
    END
  END ve_rk[74]
  PIN ve_rk[75]
    DIRECTION OUTPUT ;
    USE SIGNAL ;
    PORT
      LAYER M5 ;
        RECT  73.824 172.716 73.848 172.8 ;
    END
  END ve_rk[75]
  PIN ve_rk[76]
    DIRECTION OUTPUT ;
    USE SIGNAL ;
    PORT
      LAYER M5 ;
        RECT  73.92 172.716 73.944 172.8 ;
    END
  END ve_rk[76]
  PIN ve_rk[77]
    DIRECTION OUTPUT ;
    USE SIGNAL ;
    PORT
      LAYER M5 ;
        RECT  74.112 172.716 74.136 172.8 ;
    END
  END ve_rk[77]
  PIN ve_rk[78]
    DIRECTION OUTPUT ;
    USE SIGNAL ;
    PORT
      LAYER M5 ;
        RECT  74.208 172.716 74.232 172.8 ;
    END
  END ve_rk[78]
  PIN ve_rk[79]
    DIRECTION OUTPUT ;
    USE SIGNAL ;
    PORT
      LAYER M5 ;
        RECT  74.4 172.716 74.424 172.8 ;
    END
  END ve_rk[79]
  PIN ve_rk[7]
    DIRECTION OUTPUT ;
    USE SIGNAL ;
    PORT
      LAYER M5 ;
        RECT  64.992 172.716 65.016 172.8 ;
    END
  END ve_rk[7]
  PIN ve_rk[80]
    DIRECTION OUTPUT ;
    USE SIGNAL ;
    PORT
      LAYER M5 ;
        RECT  74.496 172.716 74.52 172.8 ;
    END
  END ve_rk[80]
  PIN ve_rk[81]
    DIRECTION OUTPUT ;
    USE SIGNAL ;
    PORT
      LAYER M5 ;
        RECT  74.592 172.716 74.616 172.8 ;
    END
  END ve_rk[81]
  PIN ve_rk[82]
    DIRECTION OUTPUT ;
    USE SIGNAL ;
    PORT
      LAYER M5 ;
        RECT  74.688 172.716 74.712 172.8 ;
    END
  END ve_rk[82]
  PIN ve_rk[83]
    DIRECTION OUTPUT ;
    USE SIGNAL ;
    PORT
      LAYER M5 ;
        RECT  74.88 172.716 74.904 172.8 ;
    END
  END ve_rk[83]
  PIN ve_rk[84]
    DIRECTION OUTPUT ;
    USE SIGNAL ;
    PORT
      LAYER M5 ;
        RECT  74.976 172.716 75 172.8 ;
    END
  END ve_rk[84]
  PIN ve_rk[85]
    DIRECTION OUTPUT ;
    USE SIGNAL ;
    PORT
      LAYER M5 ;
        RECT  75.072 172.716 75.096 172.8 ;
    END
  END ve_rk[85]
  PIN ve_rk[86]
    DIRECTION OUTPUT ;
    USE SIGNAL ;
    PORT
      LAYER M5 ;
        RECT  75.264 172.716 75.288 172.8 ;
    END
  END ve_rk[86]
  PIN ve_rk[87]
    DIRECTION OUTPUT ;
    USE SIGNAL ;
    PORT
      LAYER M5 ;
        RECT  75.984 172.716 76.008 172.8 ;
    END
  END ve_rk[87]
  PIN ve_rk[88]
    DIRECTION OUTPUT ;
    USE SIGNAL ;
    PORT
      LAYER M5 ;
        RECT  76.08 172.716 76.104 172.8 ;
    END
  END ve_rk[88]
  PIN ve_rk[89]
    DIRECTION OUTPUT ;
    USE SIGNAL ;
    PORT
      LAYER M5 ;
        RECT  76.176 172.716 76.2 172.8 ;
    END
  END ve_rk[89]
  PIN ve_rk[8]
    DIRECTION OUTPUT ;
    USE SIGNAL ;
    PORT
      LAYER M5 ;
        RECT  65.184 172.716 65.208 172.8 ;
    END
  END ve_rk[8]
  PIN ve_rk[90]
    DIRECTION OUTPUT ;
    USE SIGNAL ;
    PORT
      LAYER M5 ;
        RECT  76.272 172.716 76.296 172.8 ;
    END
  END ve_rk[90]
  PIN ve_rk[91]
    DIRECTION OUTPUT ;
    USE SIGNAL ;
    PORT
      LAYER M5 ;
        RECT  76.368 172.716 76.392 172.8 ;
    END
  END ve_rk[91]
  PIN ve_rk[92]
    DIRECTION OUTPUT ;
    USE SIGNAL ;
    PORT
      LAYER M5 ;
        RECT  76.464 172.716 76.488 172.8 ;
    END
  END ve_rk[92]
  PIN ve_rk[93]
    DIRECTION OUTPUT ;
    USE SIGNAL ;
    PORT
      LAYER M5 ;
        RECT  76.56 172.716 76.584 172.8 ;
    END
  END ve_rk[93]
  PIN ve_rk[94]
    DIRECTION OUTPUT ;
    USE SIGNAL ;
    PORT
      LAYER M5 ;
        RECT  76.656 172.716 76.68 172.8 ;
    END
  END ve_rk[94]
  PIN ve_rk[95]
    DIRECTION OUTPUT ;
    USE SIGNAL ;
    PORT
      LAYER M5 ;
        RECT  76.752 172.716 76.776 172.8 ;
    END
  END ve_rk[95]
  PIN ve_rk[96]
    DIRECTION OUTPUT ;
    USE SIGNAL ;
    PORT
      LAYER M5 ;
        RECT  76.848 172.716 76.872 172.8 ;
    END
  END ve_rk[96]
  PIN ve_rk[97]
    DIRECTION OUTPUT ;
    USE SIGNAL ;
    PORT
      LAYER M5 ;
        RECT  76.944 172.716 76.968 172.8 ;
    END
  END ve_rk[97]
  PIN ve_rk[98]
    DIRECTION OUTPUT ;
    USE SIGNAL ;
    PORT
      LAYER M5 ;
        RECT  77.04 172.716 77.064 172.8 ;
    END
  END ve_rk[98]
  PIN ve_rk[99]
    DIRECTION OUTPUT ;
    USE SIGNAL ;
    PORT
      LAYER M5 ;
        RECT  77.136 172.716 77.16 172.8 ;
    END
  END ve_rk[99]
  PIN ve_rk[9]
    DIRECTION OUTPUT ;
    USE SIGNAL ;
    PORT
      LAYER M5 ;
        RECT  65.28 172.716 65.304 172.8 ;
    END
  END ve_rk[9]
  PIN ve_rv
    DIRECTION OUTPUT ;
    USE SIGNAL ;
    PORT
      LAYER M5 ;
        RECT  55.632 172.716 55.656 172.8 ;
    END
  END ve_rv
  PIN ve_rw[0]
    DIRECTION OUTPUT ;
    USE SIGNAL ;
    PORT
      LAYER M5 ;
        RECT  81.072 172.716 81.096 172.8 ;
    END
  END ve_rw[0]
  PIN ve_rw[100]
    DIRECTION OUTPUT ;
    USE SIGNAL ;
    PORT
      LAYER M5 ;
        RECT  94.032 172.716 94.056 172.8 ;
    END
  END ve_rw[100]
  PIN ve_rw[101]
    DIRECTION OUTPUT ;
    USE SIGNAL ;
    PORT
      LAYER M5 ;
        RECT  94.128 172.716 94.152 172.8 ;
    END
  END ve_rw[101]
  PIN ve_rw[102]
    DIRECTION OUTPUT ;
    USE SIGNAL ;
    PORT
      LAYER M5 ;
        RECT  94.224 172.716 94.248 172.8 ;
    END
  END ve_rw[102]
  PIN ve_rw[103]
    DIRECTION OUTPUT ;
    USE SIGNAL ;
    PORT
      LAYER M5 ;
        RECT  94.32 172.716 94.344 172.8 ;
    END
  END ve_rw[103]
  PIN ve_rw[104]
    DIRECTION OUTPUT ;
    USE SIGNAL ;
    PORT
      LAYER M5 ;
        RECT  94.416 172.716 94.44 172.8 ;
    END
  END ve_rw[104]
  PIN ve_rw[105]
    DIRECTION OUTPUT ;
    USE SIGNAL ;
    PORT
      LAYER M5 ;
        RECT  94.512 172.716 94.536 172.8 ;
    END
  END ve_rw[105]
  PIN ve_rw[106]
    DIRECTION OUTPUT ;
    USE SIGNAL ;
    PORT
      LAYER M5 ;
        RECT  94.608 172.716 94.632 172.8 ;
    END
  END ve_rw[106]
  PIN ve_rw[107]
    DIRECTION OUTPUT ;
    USE SIGNAL ;
    PORT
      LAYER M5 ;
        RECT  94.704 172.716 94.728 172.8 ;
    END
  END ve_rw[107]
  PIN ve_rw[108]
    DIRECTION OUTPUT ;
    USE SIGNAL ;
    PORT
      LAYER M5 ;
        RECT  94.8 172.716 94.824 172.8 ;
    END
  END ve_rw[108]
  PIN ve_rw[109]
    DIRECTION OUTPUT ;
    USE SIGNAL ;
    PORT
      LAYER M5 ;
        RECT  94.896 172.716 94.92 172.8 ;
    END
  END ve_rw[109]
  PIN ve_rw[10]
    DIRECTION OUTPUT ;
    USE SIGNAL ;
    PORT
      LAYER M5 ;
        RECT  82.032 172.716 82.056 172.8 ;
    END
  END ve_rw[10]
  PIN ve_rw[110]
    DIRECTION OUTPUT ;
    USE SIGNAL ;
    PORT
      LAYER M5 ;
        RECT  94.992 172.716 95.016 172.8 ;
    END
  END ve_rw[110]
  PIN ve_rw[111]
    DIRECTION OUTPUT ;
    USE SIGNAL ;
    PORT
      LAYER M5 ;
        RECT  95.088 172.716 95.112 172.8 ;
    END
  END ve_rw[111]
  PIN ve_rw[112]
    DIRECTION OUTPUT ;
    USE SIGNAL ;
    PORT
      LAYER M5 ;
        RECT  95.232 172.716 95.256 172.8 ;
    END
  END ve_rw[112]
  PIN ve_rw[113]
    DIRECTION OUTPUT ;
    USE SIGNAL ;
    PORT
      LAYER M5 ;
        RECT  95.328 172.716 95.352 172.8 ;
    END
  END ve_rw[113]
  PIN ve_rw[114]
    DIRECTION OUTPUT ;
    USE SIGNAL ;
    PORT
      LAYER M5 ;
        RECT  95.424 172.716 95.448 172.8 ;
    END
  END ve_rw[114]
  PIN ve_rw[115]
    DIRECTION OUTPUT ;
    USE SIGNAL ;
    PORT
      LAYER M5 ;
        RECT  95.616 172.716 95.64 172.8 ;
    END
  END ve_rw[115]
  PIN ve_rw[116]
    DIRECTION OUTPUT ;
    USE SIGNAL ;
    PORT
      LAYER M5 ;
        RECT  95.712 172.716 95.736 172.8 ;
    END
  END ve_rw[116]
  PIN ve_rw[117]
    DIRECTION OUTPUT ;
    USE SIGNAL ;
    PORT
      LAYER M5 ;
        RECT  95.808 172.716 95.832 172.8 ;
    END
  END ve_rw[117]
  PIN ve_rw[118]
    DIRECTION OUTPUT ;
    USE SIGNAL ;
    PORT
      LAYER M5 ;
        RECT  96 172.716 96.024 172.8 ;
    END
  END ve_rw[118]
  PIN ve_rw[119]
    DIRECTION OUTPUT ;
    USE SIGNAL ;
    PORT
      LAYER M5 ;
        RECT  96.096 172.716 96.12 172.8 ;
    END
  END ve_rw[119]
  PIN ve_rw[11]
    DIRECTION OUTPUT ;
    USE SIGNAL ;
    PORT
      LAYER M5 ;
        RECT  82.128 172.716 82.152 172.8 ;
    END
  END ve_rw[11]
  PIN ve_rw[120]
    DIRECTION OUTPUT ;
    USE SIGNAL ;
    PORT
      LAYER M5 ;
        RECT  96.192 172.716 96.216 172.8 ;
    END
  END ve_rw[120]
  PIN ve_rw[121]
    DIRECTION OUTPUT ;
    USE SIGNAL ;
    PORT
      LAYER M5 ;
        RECT  96.288 172.716 96.312 172.8 ;
    END
  END ve_rw[121]
  PIN ve_rw[122]
    DIRECTION OUTPUT ;
    USE SIGNAL ;
    PORT
      LAYER M5 ;
        RECT  96.48 172.716 96.504 172.8 ;
    END
  END ve_rw[122]
  PIN ve_rw[123]
    DIRECTION OUTPUT ;
    USE SIGNAL ;
    PORT
      LAYER M5 ;
        RECT  96.576 172.716 96.6 172.8 ;
    END
  END ve_rw[123]
  PIN ve_rw[124]
    DIRECTION OUTPUT ;
    USE SIGNAL ;
    PORT
      LAYER M5 ;
        RECT  96.768 172.716 96.792 172.8 ;
    END
  END ve_rw[124]
  PIN ve_rw[125]
    DIRECTION OUTPUT ;
    USE SIGNAL ;
    PORT
      LAYER M5 ;
        RECT  96.864 172.716 96.888 172.8 ;
    END
  END ve_rw[125]
  PIN ve_rw[126]
    DIRECTION OUTPUT ;
    USE SIGNAL ;
    PORT
      LAYER M5 ;
        RECT  97.584 172.716 97.608 172.8 ;
    END
  END ve_rw[126]
  PIN ve_rw[127]
    DIRECTION OUTPUT ;
    USE SIGNAL ;
    PORT
      LAYER M5 ;
        RECT  97.68 172.716 97.704 172.8 ;
    END
  END ve_rw[127]
  PIN ve_rw[12]
    DIRECTION OUTPUT ;
    USE SIGNAL ;
    PORT
      LAYER M5 ;
        RECT  82.272 172.716 82.296 172.8 ;
    END
  END ve_rw[12]
  PIN ve_rw[13]
    DIRECTION OUTPUT ;
    USE SIGNAL ;
    PORT
      LAYER M5 ;
        RECT  82.368 172.716 82.392 172.8 ;
    END
  END ve_rw[13]
  PIN ve_rw[14]
    DIRECTION OUTPUT ;
    USE SIGNAL ;
    PORT
      LAYER M5 ;
        RECT  82.464 172.716 82.488 172.8 ;
    END
  END ve_rw[14]
  PIN ve_rw[15]
    DIRECTION OUTPUT ;
    USE SIGNAL ;
    PORT
      LAYER M5 ;
        RECT  82.656 172.716 82.68 172.8 ;
    END
  END ve_rw[15]
  PIN ve_rw[16]
    DIRECTION OUTPUT ;
    USE SIGNAL ;
    PORT
      LAYER M5 ;
        RECT  82.752 172.716 82.776 172.8 ;
    END
  END ve_rw[16]
  PIN ve_rw[17]
    DIRECTION OUTPUT ;
    USE SIGNAL ;
    PORT
      LAYER M5 ;
        RECT  82.848 172.716 82.872 172.8 ;
    END
  END ve_rw[17]
  PIN ve_rw[18]
    DIRECTION OUTPUT ;
    USE SIGNAL ;
    PORT
      LAYER M5 ;
        RECT  83.04 172.716 83.064 172.8 ;
    END
  END ve_rw[18]
  PIN ve_rw[19]
    DIRECTION OUTPUT ;
    USE SIGNAL ;
    PORT
      LAYER M5 ;
        RECT  83.136 172.716 83.16 172.8 ;
    END
  END ve_rw[19]
  PIN ve_rw[1]
    DIRECTION OUTPUT ;
    USE SIGNAL ;
    PORT
      LAYER M5 ;
        RECT  81.168 172.716 81.192 172.8 ;
    END
  END ve_rw[1]
  PIN ve_rw[20]
    DIRECTION OUTPUT ;
    USE SIGNAL ;
    PORT
      LAYER M5 ;
        RECT  83.232 172.716 83.256 172.8 ;
    END
  END ve_rw[20]
  PIN ve_rw[21]
    DIRECTION OUTPUT ;
    USE SIGNAL ;
    PORT
      LAYER M5 ;
        RECT  83.328 172.716 83.352 172.8 ;
    END
  END ve_rw[21]
  PIN ve_rw[22]
    DIRECTION OUTPUT ;
    USE SIGNAL ;
    PORT
      LAYER M5 ;
        RECT  83.52 172.716 83.544 172.8 ;
    END
  END ve_rw[22]
  PIN ve_rw[23]
    DIRECTION OUTPUT ;
    USE SIGNAL ;
    PORT
      LAYER M5 ;
        RECT  83.616 172.716 83.64 172.8 ;
    END
  END ve_rw[23]
  PIN ve_rw[24]
    DIRECTION OUTPUT ;
    USE SIGNAL ;
    PORT
      LAYER M5 ;
        RECT  83.808 172.716 83.832 172.8 ;
    END
  END ve_rw[24]
  PIN ve_rw[25]
    DIRECTION OUTPUT ;
    USE SIGNAL ;
    PORT
      LAYER M5 ;
        RECT  83.904 172.716 83.928 172.8 ;
    END
  END ve_rw[25]
  PIN ve_rw[26]
    DIRECTION OUTPUT ;
    USE SIGNAL ;
    PORT
      LAYER M5 ;
        RECT  84.624 172.716 84.648 172.8 ;
    END
  END ve_rw[26]
  PIN ve_rw[27]
    DIRECTION OUTPUT ;
    USE SIGNAL ;
    PORT
      LAYER M5 ;
        RECT  84.72 172.716 84.744 172.8 ;
    END
  END ve_rw[27]
  PIN ve_rw[28]
    DIRECTION OUTPUT ;
    USE SIGNAL ;
    PORT
      LAYER M5 ;
        RECT  84.816 172.716 84.84 172.8 ;
    END
  END ve_rw[28]
  PIN ve_rw[29]
    DIRECTION OUTPUT ;
    USE SIGNAL ;
    PORT
      LAYER M5 ;
        RECT  84.912 172.716 84.936 172.8 ;
    END
  END ve_rw[29]
  PIN ve_rw[2]
    DIRECTION OUTPUT ;
    USE SIGNAL ;
    PORT
      LAYER M5 ;
        RECT  81.264 172.716 81.288 172.8 ;
    END
  END ve_rw[2]
  PIN ve_rw[30]
    DIRECTION OUTPUT ;
    USE SIGNAL ;
    PORT
      LAYER M5 ;
        RECT  85.008 172.716 85.032 172.8 ;
    END
  END ve_rw[30]
  PIN ve_rw[31]
    DIRECTION OUTPUT ;
    USE SIGNAL ;
    PORT
      LAYER M5 ;
        RECT  85.104 172.716 85.128 172.8 ;
    END
  END ve_rw[31]
  PIN ve_rw[32]
    DIRECTION OUTPUT ;
    USE SIGNAL ;
    PORT
      LAYER M5 ;
        RECT  85.2 172.716 85.224 172.8 ;
    END
  END ve_rw[32]
  PIN ve_rw[33]
    DIRECTION OUTPUT ;
    USE SIGNAL ;
    PORT
      LAYER M5 ;
        RECT  85.296 172.716 85.32 172.8 ;
    END
  END ve_rw[33]
  PIN ve_rw[34]
    DIRECTION OUTPUT ;
    USE SIGNAL ;
    PORT
      LAYER M5 ;
        RECT  85.392 172.716 85.416 172.8 ;
    END
  END ve_rw[34]
  PIN ve_rw[35]
    DIRECTION OUTPUT ;
    USE SIGNAL ;
    PORT
      LAYER M5 ;
        RECT  85.488 172.716 85.512 172.8 ;
    END
  END ve_rw[35]
  PIN ve_rw[36]
    DIRECTION OUTPUT ;
    USE SIGNAL ;
    PORT
      LAYER M5 ;
        RECT  85.584 172.716 85.608 172.8 ;
    END
  END ve_rw[36]
  PIN ve_rw[37]
    DIRECTION OUTPUT ;
    USE SIGNAL ;
    PORT
      LAYER M5 ;
        RECT  85.68 172.716 85.704 172.8 ;
    END
  END ve_rw[37]
  PIN ve_rw[38]
    DIRECTION OUTPUT ;
    USE SIGNAL ;
    PORT
      LAYER M5 ;
        RECT  85.776 172.716 85.8 172.8 ;
    END
  END ve_rw[38]
  PIN ve_rw[39]
    DIRECTION OUTPUT ;
    USE SIGNAL ;
    PORT
      LAYER M5 ;
        RECT  85.872 172.716 85.896 172.8 ;
    END
  END ve_rw[39]
  PIN ve_rw[3]
    DIRECTION OUTPUT ;
    USE SIGNAL ;
    PORT
      LAYER M5 ;
        RECT  81.36 172.716 81.384 172.8 ;
    END
  END ve_rw[3]
  PIN ve_rw[40]
    DIRECTION OUTPUT ;
    USE SIGNAL ;
    PORT
      LAYER M5 ;
        RECT  85.968 172.716 85.992 172.8 ;
    END
  END ve_rw[40]
  PIN ve_rw[41]
    DIRECTION OUTPUT ;
    USE SIGNAL ;
    PORT
      LAYER M5 ;
        RECT  86.064 172.716 86.088 172.8 ;
    END
  END ve_rw[41]
  PIN ve_rw[42]
    DIRECTION OUTPUT ;
    USE SIGNAL ;
    PORT
      LAYER M5 ;
        RECT  86.16 172.716 86.184 172.8 ;
    END
  END ve_rw[42]
  PIN ve_rw[43]
    DIRECTION OUTPUT ;
    USE SIGNAL ;
    PORT
      LAYER M5 ;
        RECT  86.256 172.716 86.28 172.8 ;
    END
  END ve_rw[43]
  PIN ve_rw[44]
    DIRECTION OUTPUT ;
    USE SIGNAL ;
    PORT
      LAYER M5 ;
        RECT  86.4 172.716 86.424 172.8 ;
    END
  END ve_rw[44]
  PIN ve_rw[45]
    DIRECTION OUTPUT ;
    USE SIGNAL ;
    PORT
      LAYER M5 ;
        RECT  86.496 172.716 86.52 172.8 ;
    END
  END ve_rw[45]
  PIN ve_rw[46]
    DIRECTION OUTPUT ;
    USE SIGNAL ;
    PORT
      LAYER M5 ;
        RECT  86.688 172.716 86.712 172.8 ;
    END
  END ve_rw[46]
  PIN ve_rw[47]
    DIRECTION OUTPUT ;
    USE SIGNAL ;
    PORT
      LAYER M5 ;
        RECT  86.784 172.716 86.808 172.8 ;
    END
  END ve_rw[47]
  PIN ve_rw[48]
    DIRECTION OUTPUT ;
    USE SIGNAL ;
    PORT
      LAYER M5 ;
        RECT  86.88 172.716 86.904 172.8 ;
    END
  END ve_rw[48]
  PIN ve_rw[49]
    DIRECTION OUTPUT ;
    USE SIGNAL ;
    PORT
      LAYER M5 ;
        RECT  87.072 172.716 87.096 172.8 ;
    END
  END ve_rw[49]
  PIN ve_rw[4]
    DIRECTION OUTPUT ;
    USE SIGNAL ;
    PORT
      LAYER M5 ;
        RECT  81.456 172.716 81.48 172.8 ;
    END
  END ve_rw[4]
  PIN ve_rw[50]
    DIRECTION OUTPUT ;
    USE SIGNAL ;
    PORT
      LAYER M5 ;
        RECT  87.168 172.716 87.192 172.8 ;
    END
  END ve_rw[50]
  PIN ve_rw[51]
    DIRECTION OUTPUT ;
    USE SIGNAL ;
    PORT
      LAYER M5 ;
        RECT  87.264 172.716 87.288 172.8 ;
    END
  END ve_rw[51]
  PIN ve_rw[52]
    DIRECTION OUTPUT ;
    USE SIGNAL ;
    PORT
      LAYER M5 ;
        RECT  87.456 172.716 87.48 172.8 ;
    END
  END ve_rw[52]
  PIN ve_rw[53]
    DIRECTION OUTPUT ;
    USE SIGNAL ;
    PORT
      LAYER M5 ;
        RECT  87.552 172.716 87.576 172.8 ;
    END
  END ve_rw[53]
  PIN ve_rw[54]
    DIRECTION OUTPUT ;
    USE SIGNAL ;
    PORT
      LAYER M5 ;
        RECT  87.648 172.716 87.672 172.8 ;
    END
  END ve_rw[54]
  PIN ve_rw[55]
    DIRECTION OUTPUT ;
    USE SIGNAL ;
    PORT
      LAYER M5 ;
        RECT  87.84 172.716 87.864 172.8 ;
    END
  END ve_rw[55]
  PIN ve_rw[56]
    DIRECTION OUTPUT ;
    USE SIGNAL ;
    PORT
      LAYER M5 ;
        RECT  87.936 172.716 87.96 172.8 ;
    END
  END ve_rw[56]
  PIN ve_rw[57]
    DIRECTION OUTPUT ;
    USE SIGNAL ;
    PORT
      LAYER M5 ;
        RECT  88.032 172.716 88.056 172.8 ;
    END
  END ve_rw[57]
  PIN ve_rw[58]
    DIRECTION OUTPUT ;
    USE SIGNAL ;
    PORT
      LAYER M5 ;
        RECT  88.224 172.716 88.248 172.8 ;
    END
  END ve_rw[58]
  PIN ve_rw[59]
    DIRECTION OUTPUT ;
    USE SIGNAL ;
    PORT
      LAYER M5 ;
        RECT  88.944 172.716 88.968 172.8 ;
    END
  END ve_rw[59]
  PIN ve_rw[5]
    DIRECTION OUTPUT ;
    USE SIGNAL ;
    PORT
      LAYER M5 ;
        RECT  81.552 172.716 81.576 172.8 ;
    END
  END ve_rw[5]
  PIN ve_rw[60]
    DIRECTION OUTPUT ;
    USE SIGNAL ;
    PORT
      LAYER M5 ;
        RECT  89.04 172.716 89.064 172.8 ;
    END
  END ve_rw[60]
  PIN ve_rw[61]
    DIRECTION OUTPUT ;
    USE SIGNAL ;
    PORT
      LAYER M5 ;
        RECT  89.136 172.716 89.16 172.8 ;
    END
  END ve_rw[61]
  PIN ve_rw[62]
    DIRECTION OUTPUT ;
    USE SIGNAL ;
    PORT
      LAYER M5 ;
        RECT  89.232 172.716 89.256 172.8 ;
    END
  END ve_rw[62]
  PIN ve_rw[63]
    DIRECTION OUTPUT ;
    USE SIGNAL ;
    PORT
      LAYER M5 ;
        RECT  89.328 172.716 89.352 172.8 ;
    END
  END ve_rw[63]
  PIN ve_rw[64]
    DIRECTION OUTPUT ;
    USE SIGNAL ;
    PORT
      LAYER M5 ;
        RECT  89.424 172.716 89.448 172.8 ;
    END
  END ve_rw[64]
  PIN ve_rw[65]
    DIRECTION OUTPUT ;
    USE SIGNAL ;
    PORT
      LAYER M5 ;
        RECT  89.52 172.716 89.544 172.8 ;
    END
  END ve_rw[65]
  PIN ve_rw[66]
    DIRECTION OUTPUT ;
    USE SIGNAL ;
    PORT
      LAYER M5 ;
        RECT  89.616 172.716 89.64 172.8 ;
    END
  END ve_rw[66]
  PIN ve_rw[67]
    DIRECTION OUTPUT ;
    USE SIGNAL ;
    PORT
      LAYER M5 ;
        RECT  89.712 172.716 89.736 172.8 ;
    END
  END ve_rw[67]
  PIN ve_rw[68]
    DIRECTION OUTPUT ;
    USE SIGNAL ;
    PORT
      LAYER M5 ;
        RECT  89.808 172.716 89.832 172.8 ;
    END
  END ve_rw[68]
  PIN ve_rw[69]
    DIRECTION OUTPUT ;
    USE SIGNAL ;
    PORT
      LAYER M5 ;
        RECT  89.904 172.716 89.928 172.8 ;
    END
  END ve_rw[69]
  PIN ve_rw[6]
    DIRECTION OUTPUT ;
    USE SIGNAL ;
    PORT
      LAYER M5 ;
        RECT  81.648 172.716 81.672 172.8 ;
    END
  END ve_rw[6]
  PIN ve_rw[70]
    DIRECTION OUTPUT ;
    USE SIGNAL ;
    PORT
      LAYER M5 ;
        RECT  90 172.716 90.024 172.8 ;
    END
  END ve_rw[70]
  PIN ve_rw[71]
    DIRECTION OUTPUT ;
    USE SIGNAL ;
    PORT
      LAYER M5 ;
        RECT  90.096 172.716 90.12 172.8 ;
    END
  END ve_rw[71]
  PIN ve_rw[72]
    DIRECTION OUTPUT ;
    USE SIGNAL ;
    PORT
      LAYER M5 ;
        RECT  90.192 172.716 90.216 172.8 ;
    END
  END ve_rw[72]
  PIN ve_rw[73]
    DIRECTION OUTPUT ;
    USE SIGNAL ;
    PORT
      LAYER M5 ;
        RECT  90.288 172.716 90.312 172.8 ;
    END
  END ve_rw[73]
  PIN ve_rw[74]
    DIRECTION OUTPUT ;
    USE SIGNAL ;
    PORT
      LAYER M5 ;
        RECT  90.384 172.716 90.408 172.8 ;
    END
  END ve_rw[74]
  PIN ve_rw[75]
    DIRECTION OUTPUT ;
    USE SIGNAL ;
    PORT
      LAYER M5 ;
        RECT  90.48 172.716 90.504 172.8 ;
    END
  END ve_rw[75]
  PIN ve_rw[76]
    DIRECTION OUTPUT ;
    USE SIGNAL ;
    PORT
      LAYER M5 ;
        RECT  90.576 172.716 90.6 172.8 ;
    END
  END ve_rw[76]
  PIN ve_rw[77]
    DIRECTION OUTPUT ;
    USE SIGNAL ;
    PORT
      LAYER M5 ;
        RECT  90.672 172.716 90.696 172.8 ;
    END
  END ve_rw[77]
  PIN ve_rw[78]
    DIRECTION OUTPUT ;
    USE SIGNAL ;
    PORT
      LAYER M5 ;
        RECT  90.816 172.716 90.84 172.8 ;
    END
  END ve_rw[78]
  PIN ve_rw[79]
    DIRECTION OUTPUT ;
    USE SIGNAL ;
    PORT
      LAYER M5 ;
        RECT  90.912 172.716 90.936 172.8 ;
    END
  END ve_rw[79]
  PIN ve_rw[7]
    DIRECTION OUTPUT ;
    USE SIGNAL ;
    PORT
      LAYER M5 ;
        RECT  81.744 172.716 81.768 172.8 ;
    END
  END ve_rw[7]
  PIN ve_rw[80]
    DIRECTION OUTPUT ;
    USE SIGNAL ;
    PORT
      LAYER M5 ;
        RECT  91.008 172.716 91.032 172.8 ;
    END
  END ve_rw[80]
  PIN ve_rw[81]
    DIRECTION OUTPUT ;
    USE SIGNAL ;
    PORT
      LAYER M5 ;
        RECT  91.104 172.716 91.128 172.8 ;
    END
  END ve_rw[81]
  PIN ve_rw[82]
    DIRECTION OUTPUT ;
    USE SIGNAL ;
    PORT
      LAYER M5 ;
        RECT  91.296 172.716 91.32 172.8 ;
    END
  END ve_rw[82]
  PIN ve_rw[83]
    DIRECTION OUTPUT ;
    USE SIGNAL ;
    PORT
      LAYER M5 ;
        RECT  91.392 172.716 91.416 172.8 ;
    END
  END ve_rw[83]
  PIN ve_rw[84]
    DIRECTION OUTPUT ;
    USE SIGNAL ;
    PORT
      LAYER M5 ;
        RECT  91.584 172.716 91.608 172.8 ;
    END
  END ve_rw[84]
  PIN ve_rw[85]
    DIRECTION OUTPUT ;
    USE SIGNAL ;
    PORT
      LAYER M5 ;
        RECT  91.68 172.716 91.704 172.8 ;
    END
  END ve_rw[85]
  PIN ve_rw[86]
    DIRECTION OUTPUT ;
    USE SIGNAL ;
    PORT
      LAYER M5 ;
        RECT  91.872 172.716 91.896 172.8 ;
    END
  END ve_rw[86]
  PIN ve_rw[87]
    DIRECTION OUTPUT ;
    USE SIGNAL ;
    PORT
      LAYER M5 ;
        RECT  91.968 172.716 91.992 172.8 ;
    END
  END ve_rw[87]
  PIN ve_rw[88]
    DIRECTION OUTPUT ;
    USE SIGNAL ;
    PORT
      LAYER M5 ;
        RECT  92.064 172.716 92.088 172.8 ;
    END
  END ve_rw[88]
  PIN ve_rw[89]
    DIRECTION OUTPUT ;
    USE SIGNAL ;
    PORT
      LAYER M5 ;
        RECT  92.256 172.716 92.28 172.8 ;
    END
  END ve_rw[89]
  PIN ve_rw[8]
    DIRECTION OUTPUT ;
    USE SIGNAL ;
    PORT
      LAYER M5 ;
        RECT  81.84 172.716 81.864 172.8 ;
    END
  END ve_rw[8]
  PIN ve_rw[90]
    DIRECTION OUTPUT ;
    USE SIGNAL ;
    PORT
      LAYER M5 ;
        RECT  92.352 172.716 92.376 172.8 ;
    END
  END ve_rw[90]
  PIN ve_rw[91]
    DIRECTION OUTPUT ;
    USE SIGNAL ;
    PORT
      LAYER M5 ;
        RECT  92.448 172.716 92.472 172.8 ;
    END
  END ve_rw[91]
  PIN ve_rw[92]
    DIRECTION OUTPUT ;
    USE SIGNAL ;
    PORT
      LAYER M5 ;
        RECT  93.264 172.716 93.288 172.8 ;
    END
  END ve_rw[92]
  PIN ve_rw[93]
    DIRECTION OUTPUT ;
    USE SIGNAL ;
    PORT
      LAYER M5 ;
        RECT  93.36 172.716 93.384 172.8 ;
    END
  END ve_rw[93]
  PIN ve_rw[94]
    DIRECTION OUTPUT ;
    USE SIGNAL ;
    PORT
      LAYER M5 ;
        RECT  93.456 172.716 93.48 172.8 ;
    END
  END ve_rw[94]
  PIN ve_rw[95]
    DIRECTION OUTPUT ;
    USE SIGNAL ;
    PORT
      LAYER M5 ;
        RECT  93.552 172.716 93.576 172.8 ;
    END
  END ve_rw[95]
  PIN ve_rw[96]
    DIRECTION OUTPUT ;
    USE SIGNAL ;
    PORT
      LAYER M5 ;
        RECT  93.648 172.716 93.672 172.8 ;
    END
  END ve_rw[96]
  PIN ve_rw[97]
    DIRECTION OUTPUT ;
    USE SIGNAL ;
    PORT
      LAYER M5 ;
        RECT  93.744 172.716 93.768 172.8 ;
    END
  END ve_rw[97]
  PIN ve_rw[98]
    DIRECTION OUTPUT ;
    USE SIGNAL ;
    PORT
      LAYER M5 ;
        RECT  93.84 172.716 93.864 172.8 ;
    END
  END ve_rw[98]
  PIN ve_rw[99]
    DIRECTION OUTPUT ;
    USE SIGNAL ;
    PORT
      LAYER M5 ;
        RECT  93.936 172.716 93.96 172.8 ;
    END
  END ve_rw[99]
  PIN ve_rw[9]
    DIRECTION OUTPUT ;
    USE SIGNAL ;
    PORT
      LAYER M5 ;
        RECT  81.936 172.716 81.96 172.8 ;
    END
  END ve_rw[9]
  PIN x_qd[0]
    DIRECTION INPUT ;
    USE SIGNAL ;
    PORT
      LAYER M4 ;
        RECT  0 6.816 0.084 6.84 ;
    END
  END x_qd[0]
  PIN x_qd[100]
    DIRECTION INPUT ;
    USE SIGNAL ;
    PORT
      LAYER M4 ;
        RECT  0 26.976 0.084 27 ;
    END
  END x_qd[100]
  PIN x_qd[101]
    DIRECTION INPUT ;
    USE SIGNAL ;
    PORT
      LAYER M4 ;
        RECT  0 27.168 0.084 27.192 ;
    END
  END x_qd[101]
  PIN x_qd[102]
    DIRECTION INPUT ;
    USE SIGNAL ;
    PORT
      LAYER M4 ;
        RECT  0 27.36 0.084 27.384 ;
    END
  END x_qd[102]
  PIN x_qd[103]
    DIRECTION INPUT ;
    USE SIGNAL ;
    PORT
      LAYER M4 ;
        RECT  0 27.648 0.084 27.672 ;
    END
  END x_qd[103]
  PIN x_qd[104]
    DIRECTION INPUT ;
    USE SIGNAL ;
    PORT
      LAYER M4 ;
        RECT  0 27.84 0.084 27.864 ;
    END
  END x_qd[104]
  PIN x_qd[105]
    DIRECTION INPUT ;
    USE SIGNAL ;
    PORT
      LAYER M4 ;
        RECT  0 28.032 0.084 28.056 ;
    END
  END x_qd[105]
  PIN x_qd[106]
    DIRECTION INPUT ;
    USE SIGNAL ;
    PORT
      LAYER M4 ;
        RECT  0 28.224 0.084 28.248 ;
    END
  END x_qd[106]
  PIN x_qd[107]
    DIRECTION INPUT ;
    USE SIGNAL ;
    PORT
      LAYER M4 ;
        RECT  0 28.416 0.084 28.44 ;
    END
  END x_qd[107]
  PIN x_qd[108]
    DIRECTION INPUT ;
    USE SIGNAL ;
    PORT
      LAYER M4 ;
        RECT  0 28.608 0.084 28.632 ;
    END
  END x_qd[108]
  PIN x_qd[109]
    DIRECTION INPUT ;
    USE SIGNAL ;
    PORT
      LAYER M4 ;
        RECT  0 28.8 0.084 28.824 ;
    END
  END x_qd[109]
  PIN x_qd[10]
    DIRECTION INPUT ;
    USE SIGNAL ;
    PORT
      LAYER M4 ;
        RECT  0 8.832 0.084 8.856 ;
    END
  END x_qd[10]
  PIN x_qd[110]
    DIRECTION INPUT ;
    USE SIGNAL ;
    PORT
      LAYER M4 ;
        RECT  0 28.992 0.084 29.016 ;
    END
  END x_qd[110]
  PIN x_qd[111]
    DIRECTION INPUT ;
    USE SIGNAL ;
    PORT
      LAYER M4 ;
        RECT  0 29.184 0.084 29.208 ;
    END
  END x_qd[111]
  PIN x_qd[112]
    DIRECTION INPUT ;
    USE SIGNAL ;
    PORT
      LAYER M4 ;
        RECT  0 29.376 0.084 29.4 ;
    END
  END x_qd[112]
  PIN x_qd[113]
    DIRECTION INPUT ;
    USE SIGNAL ;
    PORT
      LAYER M4 ;
        RECT  0 29.664 0.084 29.688 ;
    END
  END x_qd[113]
  PIN x_qd[114]
    DIRECTION INPUT ;
    USE SIGNAL ;
    PORT
      LAYER M4 ;
        RECT  0 29.856 0.084 29.88 ;
    END
  END x_qd[114]
  PIN x_qd[115]
    DIRECTION INPUT ;
    USE SIGNAL ;
    PORT
      LAYER M4 ;
        RECT  0 30.048 0.084 30.072 ;
    END
  END x_qd[115]
  PIN x_qd[116]
    DIRECTION INPUT ;
    USE SIGNAL ;
    PORT
      LAYER M4 ;
        RECT  0 30.24 0.084 30.264 ;
    END
  END x_qd[116]
  PIN x_qd[117]
    DIRECTION INPUT ;
    USE SIGNAL ;
    PORT
      LAYER M4 ;
        RECT  0 30.432 0.084 30.456 ;
    END
  END x_qd[117]
  PIN x_qd[118]
    DIRECTION INPUT ;
    USE SIGNAL ;
    PORT
      LAYER M4 ;
        RECT  0 30.624 0.084 30.648 ;
    END
  END x_qd[118]
  PIN x_qd[119]
    DIRECTION INPUT ;
    USE SIGNAL ;
    PORT
      LAYER M4 ;
        RECT  0 30.816 0.084 30.84 ;
    END
  END x_qd[119]
  PIN x_qd[11]
    DIRECTION INPUT ;
    USE SIGNAL ;
    PORT
      LAYER M4 ;
        RECT  0 9.024 0.084 9.048 ;
    END
  END x_qd[11]
  PIN x_qd[120]
    DIRECTION INPUT ;
    USE SIGNAL ;
    PORT
      LAYER M4 ;
        RECT  0 31.008 0.084 31.032 ;
    END
  END x_qd[120]
  PIN x_qd[121]
    DIRECTION INPUT ;
    USE SIGNAL ;
    PORT
      LAYER M4 ;
        RECT  0 31.2 0.084 31.224 ;
    END
  END x_qd[121]
  PIN x_qd[122]
    DIRECTION INPUT ;
    USE SIGNAL ;
    PORT
      LAYER M4 ;
        RECT  0 31.392 0.084 31.416 ;
    END
  END x_qd[122]
  PIN x_qd[123]
    DIRECTION INPUT ;
    USE SIGNAL ;
    PORT
      LAYER M4 ;
        RECT  0 31.68 0.084 31.704 ;
    END
  END x_qd[123]
  PIN x_qd[124]
    DIRECTION INPUT ;
    USE SIGNAL ;
    PORT
      LAYER M4 ;
        RECT  0 31.872 0.084 31.896 ;
    END
  END x_qd[124]
  PIN x_qd[125]
    DIRECTION INPUT ;
    USE SIGNAL ;
    PORT
      LAYER M4 ;
        RECT  0 32.064 0.084 32.088 ;
    END
  END x_qd[125]
  PIN x_qd[126]
    DIRECTION INPUT ;
    USE SIGNAL ;
    PORT
      LAYER M4 ;
        RECT  0 32.256 0.084 32.28 ;
    END
  END x_qd[126]
  PIN x_qd[127]
    DIRECTION INPUT ;
    USE SIGNAL ;
    PORT
      LAYER M4 ;
        RECT  0 32.448 0.084 32.472 ;
    END
  END x_qd[127]
  PIN x_qd[128]
    DIRECTION INPUT ;
    USE SIGNAL ;
    PORT
      LAYER M4 ;
        RECT  0 32.64 0.084 32.664 ;
    END
  END x_qd[128]
  PIN x_qd[129]
    DIRECTION INPUT ;
    USE SIGNAL ;
    PORT
      LAYER M4 ;
        RECT  0 32.832 0.084 32.856 ;
    END
  END x_qd[129]
  PIN x_qd[12]
    DIRECTION INPUT ;
    USE SIGNAL ;
    PORT
      LAYER M4 ;
        RECT  0 9.216 0.084 9.24 ;
    END
  END x_qd[12]
  PIN x_qd[130]
    DIRECTION INPUT ;
    USE SIGNAL ;
    PORT
      LAYER M4 ;
        RECT  0 33.024 0.084 33.048 ;
    END
  END x_qd[130]
  PIN x_qd[131]
    DIRECTION INPUT ;
    USE SIGNAL ;
    PORT
      LAYER M4 ;
        RECT  0 33.216 0.084 33.24 ;
    END
  END x_qd[131]
  PIN x_qd[132]
    DIRECTION INPUT ;
    USE SIGNAL ;
    PORT
      LAYER M4 ;
        RECT  0 33.408 0.084 33.432 ;
    END
  END x_qd[132]
  PIN x_qd[133]
    DIRECTION INPUT ;
    USE SIGNAL ;
    PORT
      LAYER M4 ;
        RECT  0 33.696 0.084 33.72 ;
    END
  END x_qd[133]
  PIN x_qd[134]
    DIRECTION INPUT ;
    USE SIGNAL ;
    PORT
      LAYER M4 ;
        RECT  0 33.888 0.084 33.912 ;
    END
  END x_qd[134]
  PIN x_qd[135]
    DIRECTION INPUT ;
    USE SIGNAL ;
    PORT
      LAYER M4 ;
        RECT  0 34.08 0.084 34.104 ;
    END
  END x_qd[135]
  PIN x_qd[136]
    DIRECTION INPUT ;
    USE SIGNAL ;
    PORT
      LAYER M4 ;
        RECT  0 34.272 0.084 34.296 ;
    END
  END x_qd[136]
  PIN x_qd[137]
    DIRECTION INPUT ;
    USE SIGNAL ;
    PORT
      LAYER M4 ;
        RECT  0 34.464 0.084 34.488 ;
    END
  END x_qd[137]
  PIN x_qd[138]
    DIRECTION INPUT ;
    USE SIGNAL ;
    PORT
      LAYER M4 ;
        RECT  0 34.656 0.084 34.68 ;
    END
  END x_qd[138]
  PIN x_qd[139]
    DIRECTION INPUT ;
    USE SIGNAL ;
    PORT
      LAYER M4 ;
        RECT  0 34.848 0.084 34.872 ;
    END
  END x_qd[139]
  PIN x_qd[13]
    DIRECTION INPUT ;
    USE SIGNAL ;
    PORT
      LAYER M4 ;
        RECT  0 9.408 0.084 9.432 ;
    END
  END x_qd[13]
  PIN x_qd[140]
    DIRECTION INPUT ;
    USE SIGNAL ;
    PORT
      LAYER M4 ;
        RECT  0 35.04 0.084 35.064 ;
    END
  END x_qd[140]
  PIN x_qd[141]
    DIRECTION INPUT ;
    USE SIGNAL ;
    PORT
      LAYER M4 ;
        RECT  0 35.232 0.084 35.256 ;
    END
  END x_qd[141]
  PIN x_qd[142]
    DIRECTION INPUT ;
    USE SIGNAL ;
    PORT
      LAYER M4 ;
        RECT  0 35.424 0.084 35.448 ;
    END
  END x_qd[142]
  PIN x_qd[143]
    DIRECTION INPUT ;
    USE SIGNAL ;
    PORT
      LAYER M4 ;
        RECT  0 35.712 0.084 35.736 ;
    END
  END x_qd[143]
  PIN x_qd[144]
    DIRECTION INPUT ;
    USE SIGNAL ;
    PORT
      LAYER M4 ;
        RECT  0 35.904 0.084 35.928 ;
    END
  END x_qd[144]
  PIN x_qd[145]
    DIRECTION INPUT ;
    USE SIGNAL ;
    PORT
      LAYER M4 ;
        RECT  0 36.096 0.084 36.12 ;
    END
  END x_qd[145]
  PIN x_qd[146]
    DIRECTION INPUT ;
    USE SIGNAL ;
    PORT
      LAYER M4 ;
        RECT  0 36.288 0.084 36.312 ;
    END
  END x_qd[146]
  PIN x_qd[147]
    DIRECTION INPUT ;
    USE SIGNAL ;
    PORT
      LAYER M4 ;
        RECT  0 36.48 0.084 36.504 ;
    END
  END x_qd[147]
  PIN x_qd[148]
    DIRECTION INPUT ;
    USE SIGNAL ;
    PORT
      LAYER M4 ;
        RECT  0 36.672 0.084 36.696 ;
    END
  END x_qd[148]
  PIN x_qd[149]
    DIRECTION INPUT ;
    USE SIGNAL ;
    PORT
      LAYER M4 ;
        RECT  0 36.864 0.084 36.888 ;
    END
  END x_qd[149]
  PIN x_qd[14]
    DIRECTION INPUT ;
    USE SIGNAL ;
    PORT
      LAYER M4 ;
        RECT  0 9.696 0.084 9.72 ;
    END
  END x_qd[14]
  PIN x_qd[150]
    DIRECTION INPUT ;
    USE SIGNAL ;
    PORT
      LAYER M4 ;
        RECT  0 37.056 0.084 37.08 ;
    END
  END x_qd[150]
  PIN x_qd[151]
    DIRECTION INPUT ;
    USE SIGNAL ;
    PORT
      LAYER M4 ;
        RECT  0 37.248 0.084 37.272 ;
    END
  END x_qd[151]
  PIN x_qd[152]
    DIRECTION INPUT ;
    USE SIGNAL ;
    PORT
      LAYER M4 ;
        RECT  0 37.44 0.084 37.464 ;
    END
  END x_qd[152]
  PIN x_qd[153]
    DIRECTION INPUT ;
    USE SIGNAL ;
    PORT
      LAYER M4 ;
        RECT  0 37.728 0.084 37.752 ;
    END
  END x_qd[153]
  PIN x_qd[154]
    DIRECTION INPUT ;
    USE SIGNAL ;
    PORT
      LAYER M4 ;
        RECT  0 37.92 0.084 37.944 ;
    END
  END x_qd[154]
  PIN x_qd[155]
    DIRECTION INPUT ;
    USE SIGNAL ;
    PORT
      LAYER M4 ;
        RECT  0 38.112 0.084 38.136 ;
    END
  END x_qd[155]
  PIN x_qd[156]
    DIRECTION INPUT ;
    USE SIGNAL ;
    PORT
      LAYER M4 ;
        RECT  0 38.304 0.084 38.328 ;
    END
  END x_qd[156]
  PIN x_qd[157]
    DIRECTION INPUT ;
    USE SIGNAL ;
    PORT
      LAYER M4 ;
        RECT  0 38.496 0.084 38.52 ;
    END
  END x_qd[157]
  PIN x_qd[158]
    DIRECTION INPUT ;
    USE SIGNAL ;
    PORT
      LAYER M4 ;
        RECT  0 38.688 0.084 38.712 ;
    END
  END x_qd[158]
  PIN x_qd[159]
    DIRECTION INPUT ;
    USE SIGNAL ;
    PORT
      LAYER M4 ;
        RECT  0 38.88 0.084 38.904 ;
    END
  END x_qd[159]
  PIN x_qd[15]
    DIRECTION INPUT ;
    USE SIGNAL ;
    PORT
      LAYER M4 ;
        RECT  0 9.888 0.084 9.912 ;
    END
  END x_qd[15]
  PIN x_qd[160]
    DIRECTION INPUT ;
    USE SIGNAL ;
    PORT
      LAYER M4 ;
        RECT  0 39.072 0.084 39.096 ;
    END
  END x_qd[160]
  PIN x_qd[161]
    DIRECTION INPUT ;
    USE SIGNAL ;
    PORT
      LAYER M4 ;
        RECT  0 39.264 0.084 39.288 ;
    END
  END x_qd[161]
  PIN x_qd[162]
    DIRECTION INPUT ;
    USE SIGNAL ;
    PORT
      LAYER M4 ;
        RECT  0 39.456 0.084 39.48 ;
    END
  END x_qd[162]
  PIN x_qd[163]
    DIRECTION INPUT ;
    USE SIGNAL ;
    PORT
      LAYER M4 ;
        RECT  0 39.744 0.084 39.768 ;
    END
  END x_qd[163]
  PIN x_qd[164]
    DIRECTION INPUT ;
    USE SIGNAL ;
    PORT
      LAYER M4 ;
        RECT  0 39.936 0.084 39.96 ;
    END
  END x_qd[164]
  PIN x_qd[165]
    DIRECTION INPUT ;
    USE SIGNAL ;
    PORT
      LAYER M4 ;
        RECT  0 40.128 0.084 40.152 ;
    END
  END x_qd[165]
  PIN x_qd[166]
    DIRECTION INPUT ;
    USE SIGNAL ;
    PORT
      LAYER M4 ;
        RECT  0 40.32 0.084 40.344 ;
    END
  END x_qd[166]
  PIN x_qd[167]
    DIRECTION INPUT ;
    USE SIGNAL ;
    PORT
      LAYER M4 ;
        RECT  0 40.512 0.084 40.536 ;
    END
  END x_qd[167]
  PIN x_qd[168]
    DIRECTION INPUT ;
    USE SIGNAL ;
    PORT
      LAYER M4 ;
        RECT  0 40.704 0.084 40.728 ;
    END
  END x_qd[168]
  PIN x_qd[169]
    DIRECTION INPUT ;
    USE SIGNAL ;
    PORT
      LAYER M4 ;
        RECT  0 40.896 0.084 40.92 ;
    END
  END x_qd[169]
  PIN x_qd[16]
    DIRECTION INPUT ;
    USE SIGNAL ;
    PORT
      LAYER M4 ;
        RECT  0 10.08 0.084 10.104 ;
    END
  END x_qd[16]
  PIN x_qd[170]
    DIRECTION INPUT ;
    USE SIGNAL ;
    PORT
      LAYER M4 ;
        RECT  0 41.088 0.084 41.112 ;
    END
  END x_qd[170]
  PIN x_qd[171]
    DIRECTION INPUT ;
    USE SIGNAL ;
    PORT
      LAYER M4 ;
        RECT  0 41.28 0.084 41.304 ;
    END
  END x_qd[171]
  PIN x_qd[172]
    DIRECTION INPUT ;
    USE SIGNAL ;
    PORT
      LAYER M4 ;
        RECT  0 41.472 0.084 41.496 ;
    END
  END x_qd[172]
  PIN x_qd[173]
    DIRECTION INPUT ;
    USE SIGNAL ;
    PORT
      LAYER M4 ;
        RECT  0 41.76 0.084 41.784 ;
    END
  END x_qd[173]
  PIN x_qd[174]
    DIRECTION INPUT ;
    USE SIGNAL ;
    PORT
      LAYER M4 ;
        RECT  0 41.952 0.084 41.976 ;
    END
  END x_qd[174]
  PIN x_qd[175]
    DIRECTION INPUT ;
    USE SIGNAL ;
    PORT
      LAYER M4 ;
        RECT  0 42.144 0.084 42.168 ;
    END
  END x_qd[175]
  PIN x_qd[176]
    DIRECTION INPUT ;
    USE SIGNAL ;
    PORT
      LAYER M4 ;
        RECT  0 42.336 0.084 42.36 ;
    END
  END x_qd[176]
  PIN x_qd[177]
    DIRECTION INPUT ;
    USE SIGNAL ;
    PORT
      LAYER M4 ;
        RECT  0 42.528 0.084 42.552 ;
    END
  END x_qd[177]
  PIN x_qd[178]
    DIRECTION INPUT ;
    USE SIGNAL ;
    PORT
      LAYER M4 ;
        RECT  0 42.72 0.084 42.744 ;
    END
  END x_qd[178]
  PIN x_qd[179]
    DIRECTION INPUT ;
    USE SIGNAL ;
    PORT
      LAYER M4 ;
        RECT  0 42.912 0.084 42.936 ;
    END
  END x_qd[179]
  PIN x_qd[17]
    DIRECTION INPUT ;
    USE SIGNAL ;
    PORT
      LAYER M4 ;
        RECT  0 10.272 0.084 10.296 ;
    END
  END x_qd[17]
  PIN x_qd[180]
    DIRECTION INPUT ;
    USE SIGNAL ;
    PORT
      LAYER M4 ;
        RECT  0 43.104 0.084 43.128 ;
    END
  END x_qd[180]
  PIN x_qd[181]
    DIRECTION INPUT ;
    USE SIGNAL ;
    PORT
      LAYER M4 ;
        RECT  0 43.296 0.084 43.32 ;
    END
  END x_qd[181]
  PIN x_qd[182]
    DIRECTION INPUT ;
    USE SIGNAL ;
    PORT
      LAYER M4 ;
        RECT  0 43.488 0.084 43.512 ;
    END
  END x_qd[182]
  PIN x_qd[183]
    DIRECTION INPUT ;
    USE SIGNAL ;
    PORT
      LAYER M4 ;
        RECT  0 43.776 0.084 43.8 ;
    END
  END x_qd[183]
  PIN x_qd[184]
    DIRECTION INPUT ;
    USE SIGNAL ;
    PORT
      LAYER M4 ;
        RECT  0 43.968 0.084 43.992 ;
    END
  END x_qd[184]
  PIN x_qd[185]
    DIRECTION INPUT ;
    USE SIGNAL ;
    PORT
      LAYER M4 ;
        RECT  0 44.16 0.084 44.184 ;
    END
  END x_qd[185]
  PIN x_qd[186]
    DIRECTION INPUT ;
    USE SIGNAL ;
    PORT
      LAYER M4 ;
        RECT  0 44.352 0.084 44.376 ;
    END
  END x_qd[186]
  PIN x_qd[187]
    DIRECTION INPUT ;
    USE SIGNAL ;
    PORT
      LAYER M4 ;
        RECT  0 44.544 0.084 44.568 ;
    END
  END x_qd[187]
  PIN x_qd[188]
    DIRECTION INPUT ;
    USE SIGNAL ;
    PORT
      LAYER M4 ;
        RECT  0 44.736 0.084 44.76 ;
    END
  END x_qd[188]
  PIN x_qd[189]
    DIRECTION INPUT ;
    USE SIGNAL ;
    PORT
      LAYER M4 ;
        RECT  0 44.928 0.084 44.952 ;
    END
  END x_qd[189]
  PIN x_qd[18]
    DIRECTION INPUT ;
    USE SIGNAL ;
    PORT
      LAYER M4 ;
        RECT  0 10.464 0.084 10.488 ;
    END
  END x_qd[18]
  PIN x_qd[190]
    DIRECTION INPUT ;
    USE SIGNAL ;
    PORT
      LAYER M4 ;
        RECT  0 45.12 0.084 45.144 ;
    END
  END x_qd[190]
  PIN x_qd[191]
    DIRECTION INPUT ;
    USE SIGNAL ;
    PORT
      LAYER M4 ;
        RECT  0 45.312 0.084 45.336 ;
    END
  END x_qd[191]
  PIN x_qd[192]
    DIRECTION INPUT ;
    USE SIGNAL ;
    PORT
      LAYER M4 ;
        RECT  0 45.504 0.084 45.528 ;
    END
  END x_qd[192]
  PIN x_qd[193]
    DIRECTION INPUT ;
    USE SIGNAL ;
    PORT
      LAYER M4 ;
        RECT  0 45.792 0.084 45.816 ;
    END
  END x_qd[193]
  PIN x_qd[194]
    DIRECTION INPUT ;
    USE SIGNAL ;
    PORT
      LAYER M4 ;
        RECT  0 45.984 0.084 46.008 ;
    END
  END x_qd[194]
  PIN x_qd[195]
    DIRECTION INPUT ;
    USE SIGNAL ;
    PORT
      LAYER M4 ;
        RECT  0 46.176 0.084 46.2 ;
    END
  END x_qd[195]
  PIN x_qd[196]
    DIRECTION INPUT ;
    USE SIGNAL ;
    PORT
      LAYER M4 ;
        RECT  0 46.368 0.084 46.392 ;
    END
  END x_qd[196]
  PIN x_qd[197]
    DIRECTION INPUT ;
    USE SIGNAL ;
    PORT
      LAYER M4 ;
        RECT  0 46.56 0.084 46.584 ;
    END
  END x_qd[197]
  PIN x_qd[198]
    DIRECTION INPUT ;
    USE SIGNAL ;
    PORT
      LAYER M4 ;
        RECT  0 46.752 0.084 46.776 ;
    END
  END x_qd[198]
  PIN x_qd[199]
    DIRECTION INPUT ;
    USE SIGNAL ;
    PORT
      LAYER M4 ;
        RECT  0 46.944 0.084 46.968 ;
    END
  END x_qd[199]
  PIN x_qd[19]
    DIRECTION INPUT ;
    USE SIGNAL ;
    PORT
      LAYER M4 ;
        RECT  0 10.656 0.084 10.68 ;
    END
  END x_qd[19]
  PIN x_qd[1]
    DIRECTION INPUT ;
    USE SIGNAL ;
    PORT
      LAYER M4 ;
        RECT  0 7.008 0.084 7.032 ;
    END
  END x_qd[1]
  PIN x_qd[200]
    DIRECTION INPUT ;
    USE SIGNAL ;
    PORT
      LAYER M4 ;
        RECT  0 47.136 0.084 47.16 ;
    END
  END x_qd[200]
  PIN x_qd[201]
    DIRECTION INPUT ;
    USE SIGNAL ;
    PORT
      LAYER M4 ;
        RECT  0 47.328 0.084 47.352 ;
    END
  END x_qd[201]
  PIN x_qd[202]
    DIRECTION INPUT ;
    USE SIGNAL ;
    PORT
      LAYER M4 ;
        RECT  0 47.52 0.084 47.544 ;
    END
  END x_qd[202]
  PIN x_qd[203]
    DIRECTION INPUT ;
    USE SIGNAL ;
    PORT
      LAYER M4 ;
        RECT  0 47.808 0.084 47.832 ;
    END
  END x_qd[203]
  PIN x_qd[204]
    DIRECTION INPUT ;
    USE SIGNAL ;
    PORT
      LAYER M4 ;
        RECT  0 48 0.084 48.024 ;
    END
  END x_qd[204]
  PIN x_qd[205]
    DIRECTION INPUT ;
    USE SIGNAL ;
    PORT
      LAYER M4 ;
        RECT  0 48.192 0.084 48.216 ;
    END
  END x_qd[205]
  PIN x_qd[206]
    DIRECTION INPUT ;
    USE SIGNAL ;
    PORT
      LAYER M4 ;
        RECT  0 48.384 0.084 48.408 ;
    END
  END x_qd[206]
  PIN x_qd[207]
    DIRECTION INPUT ;
    USE SIGNAL ;
    PORT
      LAYER M4 ;
        RECT  0 48.576 0.084 48.6 ;
    END
  END x_qd[207]
  PIN x_qd[208]
    DIRECTION INPUT ;
    USE SIGNAL ;
    PORT
      LAYER M4 ;
        RECT  0 48.768 0.084 48.792 ;
    END
  END x_qd[208]
  PIN x_qd[209]
    DIRECTION INPUT ;
    USE SIGNAL ;
    PORT
      LAYER M4 ;
        RECT  0 48.96 0.084 48.984 ;
    END
  END x_qd[209]
  PIN x_qd[20]
    DIRECTION INPUT ;
    USE SIGNAL ;
    PORT
      LAYER M4 ;
        RECT  0 10.848 0.084 10.872 ;
    END
  END x_qd[20]
  PIN x_qd[210]
    DIRECTION INPUT ;
    USE SIGNAL ;
    PORT
      LAYER M4 ;
        RECT  0 49.152 0.084 49.176 ;
    END
  END x_qd[210]
  PIN x_qd[211]
    DIRECTION INPUT ;
    USE SIGNAL ;
    PORT
      LAYER M4 ;
        RECT  0 49.344 0.084 49.368 ;
    END
  END x_qd[211]
  PIN x_qd[212]
    DIRECTION INPUT ;
    USE SIGNAL ;
    PORT
      LAYER M4 ;
        RECT  0 49.536 0.084 49.56 ;
    END
  END x_qd[212]
  PIN x_qd[213]
    DIRECTION INPUT ;
    USE SIGNAL ;
    PORT
      LAYER M4 ;
        RECT  0 49.824 0.084 49.848 ;
    END
  END x_qd[213]
  PIN x_qd[214]
    DIRECTION INPUT ;
    USE SIGNAL ;
    PORT
      LAYER M4 ;
        RECT  0 50.016 0.084 50.04 ;
    END
  END x_qd[214]
  PIN x_qd[215]
    DIRECTION INPUT ;
    USE SIGNAL ;
    PORT
      LAYER M4 ;
        RECT  0 50.208 0.084 50.232 ;
    END
  END x_qd[215]
  PIN x_qd[216]
    DIRECTION INPUT ;
    USE SIGNAL ;
    PORT
      LAYER M4 ;
        RECT  0 50.4 0.084 50.424 ;
    END
  END x_qd[216]
  PIN x_qd[217]
    DIRECTION INPUT ;
    USE SIGNAL ;
    PORT
      LAYER M4 ;
        RECT  0 50.592 0.084 50.616 ;
    END
  END x_qd[217]
  PIN x_qd[218]
    DIRECTION INPUT ;
    USE SIGNAL ;
    PORT
      LAYER M4 ;
        RECT  0 50.784 0.084 50.808 ;
    END
  END x_qd[218]
  PIN x_qd[219]
    DIRECTION INPUT ;
    USE SIGNAL ;
    PORT
      LAYER M4 ;
        RECT  0 50.976 0.084 51 ;
    END
  END x_qd[219]
  PIN x_qd[21]
    DIRECTION INPUT ;
    USE SIGNAL ;
    PORT
      LAYER M4 ;
        RECT  0 11.04 0.084 11.064 ;
    END
  END x_qd[21]
  PIN x_qd[220]
    DIRECTION INPUT ;
    USE SIGNAL ;
    PORT
      LAYER M4 ;
        RECT  0 51.168 0.084 51.192 ;
    END
  END x_qd[220]
  PIN x_qd[221]
    DIRECTION INPUT ;
    USE SIGNAL ;
    PORT
      LAYER M4 ;
        RECT  0 51.36 0.084 51.384 ;
    END
  END x_qd[221]
  PIN x_qd[222]
    DIRECTION INPUT ;
    USE SIGNAL ;
    PORT
      LAYER M4 ;
        RECT  0 51.552 0.084 51.576 ;
    END
  END x_qd[222]
  PIN x_qd[223]
    DIRECTION INPUT ;
    USE SIGNAL ;
    PORT
      LAYER M4 ;
        RECT  0 51.84 0.084 51.864 ;
    END
  END x_qd[223]
  PIN x_qd[224]
    DIRECTION INPUT ;
    USE SIGNAL ;
    PORT
      LAYER M4 ;
        RECT  0 52.032 0.084 52.056 ;
    END
  END x_qd[224]
  PIN x_qd[225]
    DIRECTION INPUT ;
    USE SIGNAL ;
    PORT
      LAYER M4 ;
        RECT  0 52.224 0.084 52.248 ;
    END
  END x_qd[225]
  PIN x_qd[226]
    DIRECTION INPUT ;
    USE SIGNAL ;
    PORT
      LAYER M4 ;
        RECT  0 52.416 0.084 52.44 ;
    END
  END x_qd[226]
  PIN x_qd[227]
    DIRECTION INPUT ;
    USE SIGNAL ;
    PORT
      LAYER M4 ;
        RECT  0 52.608 0.084 52.632 ;
    END
  END x_qd[227]
  PIN x_qd[228]
    DIRECTION INPUT ;
    USE SIGNAL ;
    PORT
      LAYER M4 ;
        RECT  0 52.8 0.084 52.824 ;
    END
  END x_qd[228]
  PIN x_qd[229]
    DIRECTION INPUT ;
    USE SIGNAL ;
    PORT
      LAYER M4 ;
        RECT  0 52.992 0.084 53.016 ;
    END
  END x_qd[229]
  PIN x_qd[22]
    DIRECTION INPUT ;
    USE SIGNAL ;
    PORT
      LAYER M4 ;
        RECT  0 11.232 0.084 11.256 ;
    END
  END x_qd[22]
  PIN x_qd[230]
    DIRECTION INPUT ;
    USE SIGNAL ;
    PORT
      LAYER M4 ;
        RECT  0 53.184 0.084 53.208 ;
    END
  END x_qd[230]
  PIN x_qd[231]
    DIRECTION INPUT ;
    USE SIGNAL ;
    PORT
      LAYER M4 ;
        RECT  0 53.376 0.084 53.4 ;
    END
  END x_qd[231]
  PIN x_qd[232]
    DIRECTION INPUT ;
    USE SIGNAL ;
    PORT
      LAYER M4 ;
        RECT  0 53.664 0.084 53.688 ;
    END
  END x_qd[232]
  PIN x_qd[233]
    DIRECTION INPUT ;
    USE SIGNAL ;
    PORT
      LAYER M4 ;
        RECT  0 53.856 0.084 53.88 ;
    END
  END x_qd[233]
  PIN x_qd[234]
    DIRECTION INPUT ;
    USE SIGNAL ;
    PORT
      LAYER M4 ;
        RECT  0 54.048 0.084 54.072 ;
    END
  END x_qd[234]
  PIN x_qd[235]
    DIRECTION INPUT ;
    USE SIGNAL ;
    PORT
      LAYER M4 ;
        RECT  0 54.24 0.084 54.264 ;
    END
  END x_qd[235]
  PIN x_qd[236]
    DIRECTION INPUT ;
    USE SIGNAL ;
    PORT
      LAYER M4 ;
        RECT  0 54.432 0.084 54.456 ;
    END
  END x_qd[236]
  PIN x_qd[237]
    DIRECTION INPUT ;
    USE SIGNAL ;
    PORT
      LAYER M4 ;
        RECT  0 54.624 0.084 54.648 ;
    END
  END x_qd[237]
  PIN x_qd[238]
    DIRECTION INPUT ;
    USE SIGNAL ;
    PORT
      LAYER M4 ;
        RECT  0 54.816 0.084 54.84 ;
    END
  END x_qd[238]
  PIN x_qd[239]
    DIRECTION INPUT ;
    USE SIGNAL ;
    PORT
      LAYER M4 ;
        RECT  0 55.008 0.084 55.032 ;
    END
  END x_qd[239]
  PIN x_qd[23]
    DIRECTION INPUT ;
    USE SIGNAL ;
    PORT
      LAYER M4 ;
        RECT  0 11.424 0.084 11.448 ;
    END
  END x_qd[23]
  PIN x_qd[240]
    DIRECTION INPUT ;
    USE SIGNAL ;
    PORT
      LAYER M4 ;
        RECT  0 55.2 0.084 55.224 ;
    END
  END x_qd[240]
  PIN x_qd[241]
    DIRECTION INPUT ;
    USE SIGNAL ;
    PORT
      LAYER M4 ;
        RECT  0 55.392 0.084 55.416 ;
    END
  END x_qd[241]
  PIN x_qd[242]
    DIRECTION INPUT ;
    USE SIGNAL ;
    PORT
      LAYER M4 ;
        RECT  0 55.68 0.084 55.704 ;
    END
  END x_qd[242]
  PIN x_qd[243]
    DIRECTION INPUT ;
    USE SIGNAL ;
    PORT
      LAYER M4 ;
        RECT  0 55.872 0.084 55.896 ;
    END
  END x_qd[243]
  PIN x_qd[244]
    DIRECTION INPUT ;
    USE SIGNAL ;
    PORT
      LAYER M4 ;
        RECT  0 56.064 0.084 56.088 ;
    END
  END x_qd[244]
  PIN x_qd[245]
    DIRECTION INPUT ;
    USE SIGNAL ;
    PORT
      LAYER M4 ;
        RECT  0 56.256 0.084 56.28 ;
    END
  END x_qd[245]
  PIN x_qd[246]
    DIRECTION INPUT ;
    USE SIGNAL ;
    PORT
      LAYER M4 ;
        RECT  0 56.448 0.084 56.472 ;
    END
  END x_qd[246]
  PIN x_qd[247]
    DIRECTION INPUT ;
    USE SIGNAL ;
    PORT
      LAYER M4 ;
        RECT  0 56.64 0.084 56.664 ;
    END
  END x_qd[247]
  PIN x_qd[248]
    DIRECTION INPUT ;
    USE SIGNAL ;
    PORT
      LAYER M4 ;
        RECT  0 56.832 0.084 56.856 ;
    END
  END x_qd[248]
  PIN x_qd[249]
    DIRECTION INPUT ;
    USE SIGNAL ;
    PORT
      LAYER M4 ;
        RECT  0 57.024 0.084 57.048 ;
    END
  END x_qd[249]
  PIN x_qd[24]
    DIRECTION INPUT ;
    USE SIGNAL ;
    PORT
      LAYER M4 ;
        RECT  0 11.712 0.084 11.736 ;
    END
  END x_qd[24]
  PIN x_qd[250]
    DIRECTION INPUT ;
    USE SIGNAL ;
    PORT
      LAYER M4 ;
        RECT  0 57.216 0.084 57.24 ;
    END
  END x_qd[250]
  PIN x_qd[251]
    DIRECTION INPUT ;
    USE SIGNAL ;
    PORT
      LAYER M4 ;
        RECT  0 57.408 0.084 57.432 ;
    END
  END x_qd[251]
  PIN x_qd[252]
    DIRECTION INPUT ;
    USE SIGNAL ;
    PORT
      LAYER M4 ;
        RECT  0 57.696 0.084 57.72 ;
    END
  END x_qd[252]
  PIN x_qd[253]
    DIRECTION INPUT ;
    USE SIGNAL ;
    PORT
      LAYER M4 ;
        RECT  0 57.888 0.084 57.912 ;
    END
  END x_qd[253]
  PIN x_qd[254]
    DIRECTION INPUT ;
    USE SIGNAL ;
    PORT
      LAYER M4 ;
        RECT  0 58.08 0.084 58.104 ;
    END
  END x_qd[254]
  PIN x_qd[255]
    DIRECTION INPUT ;
    USE SIGNAL ;
    PORT
      LAYER M4 ;
        RECT  0 58.272 0.084 58.296 ;
    END
  END x_qd[255]
  PIN x_qd[25]
    DIRECTION INPUT ;
    USE SIGNAL ;
    PORT
      LAYER M4 ;
        RECT  0 11.904 0.084 11.928 ;
    END
  END x_qd[25]
  PIN x_qd[26]
    DIRECTION INPUT ;
    USE SIGNAL ;
    PORT
      LAYER M4 ;
        RECT  0 12.096 0.084 12.12 ;
    END
  END x_qd[26]
  PIN x_qd[27]
    DIRECTION INPUT ;
    USE SIGNAL ;
    PORT
      LAYER M4 ;
        RECT  0 12.288 0.084 12.312 ;
    END
  END x_qd[27]
  PIN x_qd[28]
    DIRECTION INPUT ;
    USE SIGNAL ;
    PORT
      LAYER M4 ;
        RECT  0 12.48 0.084 12.504 ;
    END
  END x_qd[28]
  PIN x_qd[29]
    DIRECTION INPUT ;
    USE SIGNAL ;
    PORT
      LAYER M4 ;
        RECT  0 12.672 0.084 12.696 ;
    END
  END x_qd[29]
  PIN x_qd[2]
    DIRECTION INPUT ;
    USE SIGNAL ;
    PORT
      LAYER M4 ;
        RECT  0 7.2 0.084 7.224 ;
    END
  END x_qd[2]
  PIN x_qd[30]
    DIRECTION INPUT ;
    USE SIGNAL ;
    PORT
      LAYER M4 ;
        RECT  0 12.864 0.084 12.888 ;
    END
  END x_qd[30]
  PIN x_qd[31]
    DIRECTION INPUT ;
    USE SIGNAL ;
    PORT
      LAYER M4 ;
        RECT  0 13.056 0.084 13.08 ;
    END
  END x_qd[31]
  PIN x_qd[32]
    DIRECTION INPUT ;
    USE SIGNAL ;
    PORT
      LAYER M4 ;
        RECT  0 13.248 0.084 13.272 ;
    END
  END x_qd[32]
  PIN x_qd[33]
    DIRECTION INPUT ;
    USE SIGNAL ;
    PORT
      LAYER M4 ;
        RECT  0 13.44 0.084 13.464 ;
    END
  END x_qd[33]
  PIN x_qd[34]
    DIRECTION INPUT ;
    USE SIGNAL ;
    PORT
      LAYER M4 ;
        RECT  0 13.728 0.084 13.752 ;
    END
  END x_qd[34]
  PIN x_qd[35]
    DIRECTION INPUT ;
    USE SIGNAL ;
    PORT
      LAYER M4 ;
        RECT  0 13.92 0.084 13.944 ;
    END
  END x_qd[35]
  PIN x_qd[36]
    DIRECTION INPUT ;
    USE SIGNAL ;
    PORT
      LAYER M4 ;
        RECT  0 14.112 0.084 14.136 ;
    END
  END x_qd[36]
  PIN x_qd[37]
    DIRECTION INPUT ;
    USE SIGNAL ;
    PORT
      LAYER M4 ;
        RECT  0 14.304 0.084 14.328 ;
    END
  END x_qd[37]
  PIN x_qd[38]
    DIRECTION INPUT ;
    USE SIGNAL ;
    PORT
      LAYER M4 ;
        RECT  0 14.496 0.084 14.52 ;
    END
  END x_qd[38]
  PIN x_qd[39]
    DIRECTION INPUT ;
    USE SIGNAL ;
    PORT
      LAYER M4 ;
        RECT  0 14.688 0.084 14.712 ;
    END
  END x_qd[39]
  PIN x_qd[3]
    DIRECTION INPUT ;
    USE SIGNAL ;
    PORT
      LAYER M4 ;
        RECT  0 7.392 0.084 7.416 ;
    END
  END x_qd[3]
  PIN x_qd[40]
    DIRECTION INPUT ;
    USE SIGNAL ;
    PORT
      LAYER M4 ;
        RECT  0 14.88 0.084 14.904 ;
    END
  END x_qd[40]
  PIN x_qd[41]
    DIRECTION INPUT ;
    USE SIGNAL ;
    PORT
      LAYER M4 ;
        RECT  0 15.072 0.084 15.096 ;
    END
  END x_qd[41]
  PIN x_qd[42]
    DIRECTION INPUT ;
    USE SIGNAL ;
    PORT
      LAYER M4 ;
        RECT  0 15.264 0.084 15.288 ;
    END
  END x_qd[42]
  PIN x_qd[43]
    DIRECTION INPUT ;
    USE SIGNAL ;
    PORT
      LAYER M4 ;
        RECT  0 15.456 0.084 15.48 ;
    END
  END x_qd[43]
  PIN x_qd[44]
    DIRECTION INPUT ;
    USE SIGNAL ;
    PORT
      LAYER M4 ;
        RECT  0 15.744 0.084 15.768 ;
    END
  END x_qd[44]
  PIN x_qd[45]
    DIRECTION INPUT ;
    USE SIGNAL ;
    PORT
      LAYER M4 ;
        RECT  0 15.936 0.084 15.96 ;
    END
  END x_qd[45]
  PIN x_qd[46]
    DIRECTION INPUT ;
    USE SIGNAL ;
    PORT
      LAYER M4 ;
        RECT  0 16.128 0.084 16.152 ;
    END
  END x_qd[46]
  PIN x_qd[47]
    DIRECTION INPUT ;
    USE SIGNAL ;
    PORT
      LAYER M4 ;
        RECT  0 16.32 0.084 16.344 ;
    END
  END x_qd[47]
  PIN x_qd[48]
    DIRECTION INPUT ;
    USE SIGNAL ;
    PORT
      LAYER M4 ;
        RECT  0 16.512 0.084 16.536 ;
    END
  END x_qd[48]
  PIN x_qd[49]
    DIRECTION INPUT ;
    USE SIGNAL ;
    PORT
      LAYER M4 ;
        RECT  0 16.704 0.084 16.728 ;
    END
  END x_qd[49]
  PIN x_qd[4]
    DIRECTION INPUT ;
    USE SIGNAL ;
    PORT
      LAYER M4 ;
        RECT  0 7.68 0.084 7.704 ;
    END
  END x_qd[4]
  PIN x_qd[50]
    DIRECTION INPUT ;
    USE SIGNAL ;
    PORT
      LAYER M4 ;
        RECT  0 16.896 0.084 16.92 ;
    END
  END x_qd[50]
  PIN x_qd[51]
    DIRECTION INPUT ;
    USE SIGNAL ;
    PORT
      LAYER M4 ;
        RECT  0 17.088 0.084 17.112 ;
    END
  END x_qd[51]
  PIN x_qd[52]
    DIRECTION INPUT ;
    USE SIGNAL ;
    PORT
      LAYER M4 ;
        RECT  0 17.28 0.084 17.304 ;
    END
  END x_qd[52]
  PIN x_qd[53]
    DIRECTION INPUT ;
    USE SIGNAL ;
    PORT
      LAYER M4 ;
        RECT  0 17.472 0.084 17.496 ;
    END
  END x_qd[53]
  PIN x_qd[54]
    DIRECTION INPUT ;
    USE SIGNAL ;
    PORT
      LAYER M4 ;
        RECT  0 17.76 0.084 17.784 ;
    END
  END x_qd[54]
  PIN x_qd[55]
    DIRECTION INPUT ;
    USE SIGNAL ;
    PORT
      LAYER M4 ;
        RECT  0 17.952 0.084 17.976 ;
    END
  END x_qd[55]
  PIN x_qd[56]
    DIRECTION INPUT ;
    USE SIGNAL ;
    PORT
      LAYER M4 ;
        RECT  0 18.144 0.084 18.168 ;
    END
  END x_qd[56]
  PIN x_qd[57]
    DIRECTION INPUT ;
    USE SIGNAL ;
    PORT
      LAYER M4 ;
        RECT  0 18.336 0.084 18.36 ;
    END
  END x_qd[57]
  PIN x_qd[58]
    DIRECTION INPUT ;
    USE SIGNAL ;
    PORT
      LAYER M4 ;
        RECT  0 18.528 0.084 18.552 ;
    END
  END x_qd[58]
  PIN x_qd[59]
    DIRECTION INPUT ;
    USE SIGNAL ;
    PORT
      LAYER M4 ;
        RECT  0 18.72 0.084 18.744 ;
    END
  END x_qd[59]
  PIN x_qd[5]
    DIRECTION INPUT ;
    USE SIGNAL ;
    PORT
      LAYER M4 ;
        RECT  0 7.872 0.084 7.896 ;
    END
  END x_qd[5]
  PIN x_qd[60]
    DIRECTION INPUT ;
    USE SIGNAL ;
    PORT
      LAYER M4 ;
        RECT  0 18.912 0.084 18.936 ;
    END
  END x_qd[60]
  PIN x_qd[61]
    DIRECTION INPUT ;
    USE SIGNAL ;
    PORT
      LAYER M4 ;
        RECT  0 19.104 0.084 19.128 ;
    END
  END x_qd[61]
  PIN x_qd[62]
    DIRECTION INPUT ;
    USE SIGNAL ;
    PORT
      LAYER M4 ;
        RECT  0 19.296 0.084 19.32 ;
    END
  END x_qd[62]
  PIN x_qd[63]
    DIRECTION INPUT ;
    USE SIGNAL ;
    PORT
      LAYER M4 ;
        RECT  0 19.488 0.084 19.512 ;
    END
  END x_qd[63]
  PIN x_qd[64]
    DIRECTION INPUT ;
    USE SIGNAL ;
    PORT
      LAYER M4 ;
        RECT  0 19.776 0.084 19.8 ;
    END
  END x_qd[64]
  PIN x_qd[65]
    DIRECTION INPUT ;
    USE SIGNAL ;
    PORT
      LAYER M4 ;
        RECT  0 19.968 0.084 19.992 ;
    END
  END x_qd[65]
  PIN x_qd[66]
    DIRECTION INPUT ;
    USE SIGNAL ;
    PORT
      LAYER M4 ;
        RECT  0 20.16 0.084 20.184 ;
    END
  END x_qd[66]
  PIN x_qd[67]
    DIRECTION INPUT ;
    USE SIGNAL ;
    PORT
      LAYER M4 ;
        RECT  0 20.352 0.084 20.376 ;
    END
  END x_qd[67]
  PIN x_qd[68]
    DIRECTION INPUT ;
    USE SIGNAL ;
    PORT
      LAYER M4 ;
        RECT  0 20.544 0.084 20.568 ;
    END
  END x_qd[68]
  PIN x_qd[69]
    DIRECTION INPUT ;
    USE SIGNAL ;
    PORT
      LAYER M4 ;
        RECT  0 20.736 0.084 20.76 ;
    END
  END x_qd[69]
  PIN x_qd[6]
    DIRECTION INPUT ;
    USE SIGNAL ;
    PORT
      LAYER M4 ;
        RECT  0 8.064 0.084 8.088 ;
    END
  END x_qd[6]
  PIN x_qd[70]
    DIRECTION INPUT ;
    USE SIGNAL ;
    PORT
      LAYER M4 ;
        RECT  0 20.928 0.084 20.952 ;
    END
  END x_qd[70]
  PIN x_qd[71]
    DIRECTION INPUT ;
    USE SIGNAL ;
    PORT
      LAYER M4 ;
        RECT  0 21.12 0.084 21.144 ;
    END
  END x_qd[71]
  PIN x_qd[72]
    DIRECTION INPUT ;
    USE SIGNAL ;
    PORT
      LAYER M4 ;
        RECT  0 21.312 0.084 21.336 ;
    END
  END x_qd[72]
  PIN x_qd[73]
    DIRECTION INPUT ;
    USE SIGNAL ;
    PORT
      LAYER M4 ;
        RECT  0 21.504 0.084 21.528 ;
    END
  END x_qd[73]
  PIN x_qd[74]
    DIRECTION INPUT ;
    USE SIGNAL ;
    PORT
      LAYER M4 ;
        RECT  0 21.792 0.084 21.816 ;
    END
  END x_qd[74]
  PIN x_qd[75]
    DIRECTION INPUT ;
    USE SIGNAL ;
    PORT
      LAYER M4 ;
        RECT  0 21.984 0.084 22.008 ;
    END
  END x_qd[75]
  PIN x_qd[76]
    DIRECTION INPUT ;
    USE SIGNAL ;
    PORT
      LAYER M4 ;
        RECT  0 22.176 0.084 22.2 ;
    END
  END x_qd[76]
  PIN x_qd[77]
    DIRECTION INPUT ;
    USE SIGNAL ;
    PORT
      LAYER M4 ;
        RECT  0 22.368 0.084 22.392 ;
    END
  END x_qd[77]
  PIN x_qd[78]
    DIRECTION INPUT ;
    USE SIGNAL ;
    PORT
      LAYER M4 ;
        RECT  0 22.56 0.084 22.584 ;
    END
  END x_qd[78]
  PIN x_qd[79]
    DIRECTION INPUT ;
    USE SIGNAL ;
    PORT
      LAYER M4 ;
        RECT  0 22.752 0.084 22.776 ;
    END
  END x_qd[79]
  PIN x_qd[7]
    DIRECTION INPUT ;
    USE SIGNAL ;
    PORT
      LAYER M4 ;
        RECT  0 8.256 0.084 8.28 ;
    END
  END x_qd[7]
  PIN x_qd[80]
    DIRECTION INPUT ;
    USE SIGNAL ;
    PORT
      LAYER M4 ;
        RECT  0 22.944 0.084 22.968 ;
    END
  END x_qd[80]
  PIN x_qd[81]
    DIRECTION INPUT ;
    USE SIGNAL ;
    PORT
      LAYER M4 ;
        RECT  0 23.136 0.084 23.16 ;
    END
  END x_qd[81]
  PIN x_qd[82]
    DIRECTION INPUT ;
    USE SIGNAL ;
    PORT
      LAYER M4 ;
        RECT  0 23.328 0.084 23.352 ;
    END
  END x_qd[82]
  PIN x_qd[83]
    DIRECTION INPUT ;
    USE SIGNAL ;
    PORT
      LAYER M4 ;
        RECT  0 23.52 0.084 23.544 ;
    END
  END x_qd[83]
  PIN x_qd[84]
    DIRECTION INPUT ;
    USE SIGNAL ;
    PORT
      LAYER M4 ;
        RECT  0 23.808 0.084 23.832 ;
    END
  END x_qd[84]
  PIN x_qd[85]
    DIRECTION INPUT ;
    USE SIGNAL ;
    PORT
      LAYER M4 ;
        RECT  0 24 0.084 24.024 ;
    END
  END x_qd[85]
  PIN x_qd[86]
    DIRECTION INPUT ;
    USE SIGNAL ;
    PORT
      LAYER M4 ;
        RECT  0 24.192 0.084 24.216 ;
    END
  END x_qd[86]
  PIN x_qd[87]
    DIRECTION INPUT ;
    USE SIGNAL ;
    PORT
      LAYER M4 ;
        RECT  0 24.384 0.084 24.408 ;
    END
  END x_qd[87]
  PIN x_qd[88]
    DIRECTION INPUT ;
    USE SIGNAL ;
    PORT
      LAYER M4 ;
        RECT  0 24.576 0.084 24.6 ;
    END
  END x_qd[88]
  PIN x_qd[89]
    DIRECTION INPUT ;
    USE SIGNAL ;
    PORT
      LAYER M4 ;
        RECT  0 24.768 0.084 24.792 ;
    END
  END x_qd[89]
  PIN x_qd[8]
    DIRECTION INPUT ;
    USE SIGNAL ;
    PORT
      LAYER M4 ;
        RECT  0 8.448 0.084 8.472 ;
    END
  END x_qd[8]
  PIN x_qd[90]
    DIRECTION INPUT ;
    USE SIGNAL ;
    PORT
      LAYER M4 ;
        RECT  0 24.96 0.084 24.984 ;
    END
  END x_qd[90]
  PIN x_qd[91]
    DIRECTION INPUT ;
    USE SIGNAL ;
    PORT
      LAYER M4 ;
        RECT  0 25.152 0.084 25.176 ;
    END
  END x_qd[91]
  PIN x_qd[92]
    DIRECTION INPUT ;
    USE SIGNAL ;
    PORT
      LAYER M4 ;
        RECT  0 25.344 0.084 25.368 ;
    END
  END x_qd[92]
  PIN x_qd[93]
    DIRECTION INPUT ;
    USE SIGNAL ;
    PORT
      LAYER M4 ;
        RECT  0 25.632 0.084 25.656 ;
    END
  END x_qd[93]
  PIN x_qd[94]
    DIRECTION INPUT ;
    USE SIGNAL ;
    PORT
      LAYER M4 ;
        RECT  0 25.824 0.084 25.848 ;
    END
  END x_qd[94]
  PIN x_qd[95]
    DIRECTION INPUT ;
    USE SIGNAL ;
    PORT
      LAYER M4 ;
        RECT  0 26.016 0.084 26.04 ;
    END
  END x_qd[95]
  PIN x_qd[96]
    DIRECTION INPUT ;
    USE SIGNAL ;
    PORT
      LAYER M4 ;
        RECT  0 26.208 0.084 26.232 ;
    END
  END x_qd[96]
  PIN x_qd[97]
    DIRECTION INPUT ;
    USE SIGNAL ;
    PORT
      LAYER M4 ;
        RECT  0 26.4 0.084 26.424 ;
    END
  END x_qd[97]
  PIN x_qd[98]
    DIRECTION INPUT ;
    USE SIGNAL ;
    PORT
      LAYER M4 ;
        RECT  0 26.592 0.084 26.616 ;
    END
  END x_qd[98]
  PIN x_qd[99]
    DIRECTION INPUT ;
    USE SIGNAL ;
    PORT
      LAYER M4 ;
        RECT  0 26.784 0.084 26.808 ;
    END
  END x_qd[99]
  PIN x_qd[9]
    DIRECTION INPUT ;
    USE SIGNAL ;
    PORT
      LAYER M4 ;
        RECT  0 8.64 0.084 8.664 ;
    END
  END x_qd[9]
  PIN x_qv
    DIRECTION INPUT ;
    USE SIGNAL ;
    PORT
      LAYER M4 ;
        RECT  0 6.624 0.084 6.648 ;
    END
  END x_qv
  PIN x_ra[0]
    DIRECTION OUTPUT ;
    USE SIGNAL ;
    PORT
      LAYER M4 ;
        RECT  0 4.608 0.084 4.632 ;
    END
  END x_ra[0]
  PIN x_ra[1]
    DIRECTION OUTPUT ;
    USE SIGNAL ;
    PORT
      LAYER M4 ;
        RECT  0 4.8 0.084 4.824 ;
    END
  END x_ra[1]
  PIN x_ra[2]
    DIRECTION OUTPUT ;
    USE SIGNAL ;
    PORT
      LAYER M4 ;
        RECT  0 4.992 0.084 5.016 ;
    END
  END x_ra[2]
  PIN x_ra[3]
    DIRECTION OUTPUT ;
    USE SIGNAL ;
    PORT
      LAYER M4 ;
        RECT  0 5.184 0.084 5.208 ;
    END
  END x_ra[3]
  PIN x_ra[4]
    DIRECTION OUTPUT ;
    USE SIGNAL ;
    PORT
      LAYER M4 ;
        RECT  0 5.376 0.084 5.4 ;
    END
  END x_ra[4]
  PIN x_ra[5]
    DIRECTION OUTPUT ;
    USE SIGNAL ;
    PORT
      LAYER M4 ;
        RECT  0 5.664 0.084 5.688 ;
    END
  END x_ra[5]
  PIN x_ra[6]
    DIRECTION OUTPUT ;
    USE SIGNAL ;
    PORT
      LAYER M4 ;
        RECT  0 5.856 0.084 5.88 ;
    END
  END x_ra[6]
  PIN x_ra[7]
    DIRECTION OUTPUT ;
    USE SIGNAL ;
    PORT
      LAYER M4 ;
        RECT  0 6.048 0.084 6.072 ;
    END
  END x_ra[7]
  PIN x_ra[8]
    DIRECTION OUTPUT ;
    USE SIGNAL ;
    PORT
      LAYER M4 ;
        RECT  0 6.24 0.084 6.264 ;
    END
  END x_ra[8]
  PIN x_ra[9]
    DIRECTION OUTPUT ;
    USE SIGNAL ;
    PORT
      LAYER M4 ;
        RECT  0 6.432 0.084 6.456 ;
    END
  END x_ra[9]
  PIN x_rv
    DIRECTION OUTPUT ;
    USE SIGNAL ;
    PORT
      LAYER M4 ;
        RECT  0 4.416 0.084 4.44 ;
    END
  END x_rv
  PIN x_wa[0]
    DIRECTION OUTPUT ;
    USE SIGNAL ;
    PORT
      LAYER M4 ;
        RECT  0 58.656 0.084 58.68 ;
    END
  END x_wa[0]
  PIN x_wa[1]
    DIRECTION OUTPUT ;
    USE SIGNAL ;
    PORT
      LAYER M4 ;
        RECT  0 58.848 0.084 58.872 ;
    END
  END x_wa[1]
  PIN x_wa[2]
    DIRECTION OUTPUT ;
    USE SIGNAL ;
    PORT
      LAYER M4 ;
        RECT  0 59.04 0.084 59.064 ;
    END
  END x_wa[2]
  PIN x_wa[3]
    DIRECTION OUTPUT ;
    USE SIGNAL ;
    PORT
      LAYER M4 ;
        RECT  0 59.232 0.084 59.256 ;
    END
  END x_wa[3]
  PIN x_wa[4]
    DIRECTION OUTPUT ;
    USE SIGNAL ;
    PORT
      LAYER M4 ;
        RECT  0 59.424 0.084 59.448 ;
    END
  END x_wa[4]
  PIN x_wa[5]
    DIRECTION OUTPUT ;
    USE SIGNAL ;
    PORT
      LAYER M4 ;
        RECT  0 59.712 0.084 59.736 ;
    END
  END x_wa[5]
  PIN x_wa[6]
    DIRECTION OUTPUT ;
    USE SIGNAL ;
    PORT
      LAYER M4 ;
        RECT  0 59.904 0.084 59.928 ;
    END
  END x_wa[6]
  PIN x_wa[7]
    DIRECTION OUTPUT ;
    USE SIGNAL ;
    PORT
      LAYER M4 ;
        RECT  0 60.096 0.084 60.12 ;
    END
  END x_wa[7]
  PIN x_wa[8]
    DIRECTION OUTPUT ;
    USE SIGNAL ;
    PORT
      LAYER M4 ;
        RECT  0 60.288 0.084 60.312 ;
    END
  END x_wa[8]
  PIN x_wa[9]
    DIRECTION OUTPUT ;
    USE SIGNAL ;
    PORT
      LAYER M4 ;
        RECT  0 60.48 0.084 60.504 ;
    END
  END x_wa[9]
  PIN x_wd[0]
    DIRECTION OUTPUT ;
    USE SIGNAL ;
    PORT
      LAYER M4 ;
        RECT  0 62.304 0.084 62.328 ;
    END
  END x_wd[0]
  PIN x_wd[100]
    DIRECTION OUTPUT ;
    USE SIGNAL ;
    PORT
      LAYER M4 ;
        RECT  0 82.464 0.084 82.488 ;
    END
  END x_wd[100]
  PIN x_wd[101]
    DIRECTION OUTPUT ;
    USE SIGNAL ;
    PORT
      LAYER M4 ;
        RECT  0 82.656 0.084 82.68 ;
    END
  END x_wd[101]
  PIN x_wd[102]
    DIRECTION OUTPUT ;
    USE SIGNAL ;
    PORT
      LAYER M4 ;
        RECT  0 82.848 0.084 82.872 ;
    END
  END x_wd[102]
  PIN x_wd[103]
    DIRECTION OUTPUT ;
    USE SIGNAL ;
    PORT
      LAYER M4 ;
        RECT  0 83.04 0.084 83.064 ;
    END
  END x_wd[103]
  PIN x_wd[104]
    DIRECTION OUTPUT ;
    USE SIGNAL ;
    PORT
      LAYER M4 ;
        RECT  0 83.232 0.084 83.256 ;
    END
  END x_wd[104]
  PIN x_wd[105]
    DIRECTION OUTPUT ;
    USE SIGNAL ;
    PORT
      LAYER M4 ;
        RECT  0 83.424 0.084 83.448 ;
    END
  END x_wd[105]
  PIN x_wd[106]
    DIRECTION OUTPUT ;
    USE SIGNAL ;
    PORT
      LAYER M4 ;
        RECT  0 83.712 0.084 83.736 ;
    END
  END x_wd[106]
  PIN x_wd[107]
    DIRECTION OUTPUT ;
    USE SIGNAL ;
    PORT
      LAYER M4 ;
        RECT  0 83.904 0.084 83.928 ;
    END
  END x_wd[107]
  PIN x_wd[108]
    DIRECTION OUTPUT ;
    USE SIGNAL ;
    PORT
      LAYER M4 ;
        RECT  0 84.096 0.084 84.12 ;
    END
  END x_wd[108]
  PIN x_wd[109]
    DIRECTION OUTPUT ;
    USE SIGNAL ;
    PORT
      LAYER M4 ;
        RECT  0 84.288 0.084 84.312 ;
    END
  END x_wd[109]
  PIN x_wd[10]
    DIRECTION OUTPUT ;
    USE SIGNAL ;
    PORT
      LAYER M4 ;
        RECT  0 64.32 0.084 64.344 ;
    END
  END x_wd[10]
  PIN x_wd[110]
    DIRECTION OUTPUT ;
    USE SIGNAL ;
    PORT
      LAYER M4 ;
        RECT  0 84.48 0.084 84.504 ;
    END
  END x_wd[110]
  PIN x_wd[111]
    DIRECTION OUTPUT ;
    USE SIGNAL ;
    PORT
      LAYER M4 ;
        RECT  0 84.672 0.084 84.696 ;
    END
  END x_wd[111]
  PIN x_wd[112]
    DIRECTION OUTPUT ;
    USE SIGNAL ;
    PORT
      LAYER M4 ;
        RECT  0 84.864 0.084 84.888 ;
    END
  END x_wd[112]
  PIN x_wd[113]
    DIRECTION OUTPUT ;
    USE SIGNAL ;
    PORT
      LAYER M4 ;
        RECT  0 85.056 0.084 85.08 ;
    END
  END x_wd[113]
  PIN x_wd[114]
    DIRECTION OUTPUT ;
    USE SIGNAL ;
    PORT
      LAYER M4 ;
        RECT  0 85.248 0.084 85.272 ;
    END
  END x_wd[114]
  PIN x_wd[115]
    DIRECTION OUTPUT ;
    USE SIGNAL ;
    PORT
      LAYER M4 ;
        RECT  0 85.44 0.084 85.464 ;
    END
  END x_wd[115]
  PIN x_wd[116]
    DIRECTION OUTPUT ;
    USE SIGNAL ;
    PORT
      LAYER M4 ;
        RECT  0 85.728 0.084 85.752 ;
    END
  END x_wd[116]
  PIN x_wd[117]
    DIRECTION OUTPUT ;
    USE SIGNAL ;
    PORT
      LAYER M4 ;
        RECT  0 85.92 0.084 85.944 ;
    END
  END x_wd[117]
  PIN x_wd[118]
    DIRECTION OUTPUT ;
    USE SIGNAL ;
    PORT
      LAYER M4 ;
        RECT  0 86.112 0.084 86.136 ;
    END
  END x_wd[118]
  PIN x_wd[119]
    DIRECTION OUTPUT ;
    USE SIGNAL ;
    PORT
      LAYER M4 ;
        RECT  0 86.304 0.084 86.328 ;
    END
  END x_wd[119]
  PIN x_wd[11]
    DIRECTION OUTPUT ;
    USE SIGNAL ;
    PORT
      LAYER M4 ;
        RECT  0 64.512 0.084 64.536 ;
    END
  END x_wd[11]
  PIN x_wd[120]
    DIRECTION OUTPUT ;
    USE SIGNAL ;
    PORT
      LAYER M4 ;
        RECT  0 86.496 0.084 86.52 ;
    END
  END x_wd[120]
  PIN x_wd[121]
    DIRECTION OUTPUT ;
    USE SIGNAL ;
    PORT
      LAYER M4 ;
        RECT  0 86.688 0.084 86.712 ;
    END
  END x_wd[121]
  PIN x_wd[122]
    DIRECTION OUTPUT ;
    USE SIGNAL ;
    PORT
      LAYER M4 ;
        RECT  0 86.88 0.084 86.904 ;
    END
  END x_wd[122]
  PIN x_wd[123]
    DIRECTION OUTPUT ;
    USE SIGNAL ;
    PORT
      LAYER M4 ;
        RECT  0 87.072 0.084 87.096 ;
    END
  END x_wd[123]
  PIN x_wd[124]
    DIRECTION OUTPUT ;
    USE SIGNAL ;
    PORT
      LAYER M4 ;
        RECT  0 87.264 0.084 87.288 ;
    END
  END x_wd[124]
  PIN x_wd[125]
    DIRECTION OUTPUT ;
    USE SIGNAL ;
    PORT
      LAYER M4 ;
        RECT  0 87.456 0.084 87.48 ;
    END
  END x_wd[125]
  PIN x_wd[126]
    DIRECTION OUTPUT ;
    USE SIGNAL ;
    PORT
      LAYER M4 ;
        RECT  0 87.744 0.084 87.768 ;
    END
  END x_wd[126]
  PIN x_wd[127]
    DIRECTION OUTPUT ;
    USE SIGNAL ;
    PORT
      LAYER M4 ;
        RECT  0 87.936 0.084 87.96 ;
    END
  END x_wd[127]
  PIN x_wd[128]
    DIRECTION OUTPUT ;
    USE SIGNAL ;
    PORT
      LAYER M4 ;
        RECT  0 88.128 0.084 88.152 ;
    END
  END x_wd[128]
  PIN x_wd[129]
    DIRECTION OUTPUT ;
    USE SIGNAL ;
    PORT
      LAYER M4 ;
        RECT  0 88.32 0.084 88.344 ;
    END
  END x_wd[129]
  PIN x_wd[12]
    DIRECTION OUTPUT ;
    USE SIGNAL ;
    PORT
      LAYER M4 ;
        RECT  0 64.704 0.084 64.728 ;
    END
  END x_wd[12]
  PIN x_wd[130]
    DIRECTION OUTPUT ;
    USE SIGNAL ;
    PORT
      LAYER M4 ;
        RECT  0 88.512 0.084 88.536 ;
    END
  END x_wd[130]
  PIN x_wd[131]
    DIRECTION OUTPUT ;
    USE SIGNAL ;
    PORT
      LAYER M4 ;
        RECT  0 88.704 0.084 88.728 ;
    END
  END x_wd[131]
  PIN x_wd[132]
    DIRECTION OUTPUT ;
    USE SIGNAL ;
    PORT
      LAYER M4 ;
        RECT  0 88.896 0.084 88.92 ;
    END
  END x_wd[132]
  PIN x_wd[133]
    DIRECTION OUTPUT ;
    USE SIGNAL ;
    PORT
      LAYER M4 ;
        RECT  0 89.088 0.084 89.112 ;
    END
  END x_wd[133]
  PIN x_wd[134]
    DIRECTION OUTPUT ;
    USE SIGNAL ;
    PORT
      LAYER M4 ;
        RECT  0 89.28 0.084 89.304 ;
    END
  END x_wd[134]
  PIN x_wd[135]
    DIRECTION OUTPUT ;
    USE SIGNAL ;
    PORT
      LAYER M4 ;
        RECT  0 89.472 0.084 89.496 ;
    END
  END x_wd[135]
  PIN x_wd[136]
    DIRECTION OUTPUT ;
    USE SIGNAL ;
    PORT
      LAYER M4 ;
        RECT  0 89.76 0.084 89.784 ;
    END
  END x_wd[136]
  PIN x_wd[137]
    DIRECTION OUTPUT ;
    USE SIGNAL ;
    PORT
      LAYER M4 ;
        RECT  0 89.952 0.084 89.976 ;
    END
  END x_wd[137]
  PIN x_wd[138]
    DIRECTION OUTPUT ;
    USE SIGNAL ;
    PORT
      LAYER M4 ;
        RECT  0 90.144 0.084 90.168 ;
    END
  END x_wd[138]
  PIN x_wd[139]
    DIRECTION OUTPUT ;
    USE SIGNAL ;
    PORT
      LAYER M4 ;
        RECT  0 90.336 0.084 90.36 ;
    END
  END x_wd[139]
  PIN x_wd[13]
    DIRECTION OUTPUT ;
    USE SIGNAL ;
    PORT
      LAYER M4 ;
        RECT  0 64.896 0.084 64.92 ;
    END
  END x_wd[13]
  PIN x_wd[140]
    DIRECTION OUTPUT ;
    USE SIGNAL ;
    PORT
      LAYER M4 ;
        RECT  0 90.528 0.084 90.552 ;
    END
  END x_wd[140]
  PIN x_wd[141]
    DIRECTION OUTPUT ;
    USE SIGNAL ;
    PORT
      LAYER M4 ;
        RECT  0 90.72 0.084 90.744 ;
    END
  END x_wd[141]
  PIN x_wd[142]
    DIRECTION OUTPUT ;
    USE SIGNAL ;
    PORT
      LAYER M4 ;
        RECT  0 90.912 0.084 90.936 ;
    END
  END x_wd[142]
  PIN x_wd[143]
    DIRECTION OUTPUT ;
    USE SIGNAL ;
    PORT
      LAYER M4 ;
        RECT  0 91.104 0.084 91.128 ;
    END
  END x_wd[143]
  PIN x_wd[144]
    DIRECTION OUTPUT ;
    USE SIGNAL ;
    PORT
      LAYER M4 ;
        RECT  0 91.296 0.084 91.32 ;
    END
  END x_wd[144]
  PIN x_wd[145]
    DIRECTION OUTPUT ;
    USE SIGNAL ;
    PORT
      LAYER M4 ;
        RECT  0 91.488 0.084 91.512 ;
    END
  END x_wd[145]
  PIN x_wd[146]
    DIRECTION OUTPUT ;
    USE SIGNAL ;
    PORT
      LAYER M4 ;
        RECT  0 91.776 0.084 91.8 ;
    END
  END x_wd[146]
  PIN x_wd[147]
    DIRECTION OUTPUT ;
    USE SIGNAL ;
    PORT
      LAYER M4 ;
        RECT  0 91.968 0.084 91.992 ;
    END
  END x_wd[147]
  PIN x_wd[148]
    DIRECTION OUTPUT ;
    USE SIGNAL ;
    PORT
      LAYER M4 ;
        RECT  0 92.16 0.084 92.184 ;
    END
  END x_wd[148]
  PIN x_wd[149]
    DIRECTION OUTPUT ;
    USE SIGNAL ;
    PORT
      LAYER M4 ;
        RECT  0 92.352 0.084 92.376 ;
    END
  END x_wd[149]
  PIN x_wd[14]
    DIRECTION OUTPUT ;
    USE SIGNAL ;
    PORT
      LAYER M4 ;
        RECT  0 65.088 0.084 65.112 ;
    END
  END x_wd[14]
  PIN x_wd[150]
    DIRECTION OUTPUT ;
    USE SIGNAL ;
    PORT
      LAYER M4 ;
        RECT  0 92.544 0.084 92.568 ;
    END
  END x_wd[150]
  PIN x_wd[151]
    DIRECTION OUTPUT ;
    USE SIGNAL ;
    PORT
      LAYER M4 ;
        RECT  0 92.736 0.084 92.76 ;
    END
  END x_wd[151]
  PIN x_wd[152]
    DIRECTION OUTPUT ;
    USE SIGNAL ;
    PORT
      LAYER M4 ;
        RECT  0 92.928 0.084 92.952 ;
    END
  END x_wd[152]
  PIN x_wd[153]
    DIRECTION OUTPUT ;
    USE SIGNAL ;
    PORT
      LAYER M4 ;
        RECT  0 93.12 0.084 93.144 ;
    END
  END x_wd[153]
  PIN x_wd[154]
    DIRECTION OUTPUT ;
    USE SIGNAL ;
    PORT
      LAYER M4 ;
        RECT  0 93.312 0.084 93.336 ;
    END
  END x_wd[154]
  PIN x_wd[155]
    DIRECTION OUTPUT ;
    USE SIGNAL ;
    PORT
      LAYER M4 ;
        RECT  0 93.504 0.084 93.528 ;
    END
  END x_wd[155]
  PIN x_wd[156]
    DIRECTION OUTPUT ;
    USE SIGNAL ;
    PORT
      LAYER M4 ;
        RECT  0 93.792 0.084 93.816 ;
    END
  END x_wd[156]
  PIN x_wd[157]
    DIRECTION OUTPUT ;
    USE SIGNAL ;
    PORT
      LAYER M4 ;
        RECT  0 93.984 0.084 94.008 ;
    END
  END x_wd[157]
  PIN x_wd[158]
    DIRECTION OUTPUT ;
    USE SIGNAL ;
    PORT
      LAYER M4 ;
        RECT  0 94.176 0.084 94.2 ;
    END
  END x_wd[158]
  PIN x_wd[159]
    DIRECTION OUTPUT ;
    USE SIGNAL ;
    PORT
      LAYER M4 ;
        RECT  0 94.368 0.084 94.392 ;
    END
  END x_wd[159]
  PIN x_wd[15]
    DIRECTION OUTPUT ;
    USE SIGNAL ;
    PORT
      LAYER M4 ;
        RECT  0 65.28 0.084 65.304 ;
    END
  END x_wd[15]
  PIN x_wd[160]
    DIRECTION OUTPUT ;
    USE SIGNAL ;
    PORT
      LAYER M4 ;
        RECT  0 94.56 0.084 94.584 ;
    END
  END x_wd[160]
  PIN x_wd[161]
    DIRECTION OUTPUT ;
    USE SIGNAL ;
    PORT
      LAYER M4 ;
        RECT  0 94.752 0.084 94.776 ;
    END
  END x_wd[161]
  PIN x_wd[162]
    DIRECTION OUTPUT ;
    USE SIGNAL ;
    PORT
      LAYER M4 ;
        RECT  0 94.944 0.084 94.968 ;
    END
  END x_wd[162]
  PIN x_wd[163]
    DIRECTION OUTPUT ;
    USE SIGNAL ;
    PORT
      LAYER M4 ;
        RECT  0 95.136 0.084 95.16 ;
    END
  END x_wd[163]
  PIN x_wd[164]
    DIRECTION OUTPUT ;
    USE SIGNAL ;
    PORT
      LAYER M4 ;
        RECT  0 95.328 0.084 95.352 ;
    END
  END x_wd[164]
  PIN x_wd[165]
    DIRECTION OUTPUT ;
    USE SIGNAL ;
    PORT
      LAYER M4 ;
        RECT  0 95.52 0.084 95.544 ;
    END
  END x_wd[165]
  PIN x_wd[166]
    DIRECTION OUTPUT ;
    USE SIGNAL ;
    PORT
      LAYER M4 ;
        RECT  0 95.808 0.084 95.832 ;
    END
  END x_wd[166]
  PIN x_wd[167]
    DIRECTION OUTPUT ;
    USE SIGNAL ;
    PORT
      LAYER M4 ;
        RECT  0 96 0.084 96.024 ;
    END
  END x_wd[167]
  PIN x_wd[168]
    DIRECTION OUTPUT ;
    USE SIGNAL ;
    PORT
      LAYER M4 ;
        RECT  0 96.192 0.084 96.216 ;
    END
  END x_wd[168]
  PIN x_wd[169]
    DIRECTION OUTPUT ;
    USE SIGNAL ;
    PORT
      LAYER M4 ;
        RECT  0 96.384 0.084 96.408 ;
    END
  END x_wd[169]
  PIN x_wd[16]
    DIRECTION OUTPUT ;
    USE SIGNAL ;
    PORT
      LAYER M4 ;
        RECT  0 65.472 0.084 65.496 ;
    END
  END x_wd[16]
  PIN x_wd[170]
    DIRECTION OUTPUT ;
    USE SIGNAL ;
    PORT
      LAYER M4 ;
        RECT  0 96.576 0.084 96.6 ;
    END
  END x_wd[170]
  PIN x_wd[171]
    DIRECTION OUTPUT ;
    USE SIGNAL ;
    PORT
      LAYER M4 ;
        RECT  0 96.768 0.084 96.792 ;
    END
  END x_wd[171]
  PIN x_wd[172]
    DIRECTION OUTPUT ;
    USE SIGNAL ;
    PORT
      LAYER M4 ;
        RECT  0 96.96 0.084 96.984 ;
    END
  END x_wd[172]
  PIN x_wd[173]
    DIRECTION OUTPUT ;
    USE SIGNAL ;
    PORT
      LAYER M4 ;
        RECT  0 97.152 0.084 97.176 ;
    END
  END x_wd[173]
  PIN x_wd[174]
    DIRECTION OUTPUT ;
    USE SIGNAL ;
    PORT
      LAYER M4 ;
        RECT  0 97.344 0.084 97.368 ;
    END
  END x_wd[174]
  PIN x_wd[175]
    DIRECTION OUTPUT ;
    USE SIGNAL ;
    PORT
      LAYER M4 ;
        RECT  0 97.536 0.084 97.56 ;
    END
  END x_wd[175]
  PIN x_wd[176]
    DIRECTION OUTPUT ;
    USE SIGNAL ;
    PORT
      LAYER M4 ;
        RECT  0 97.824 0.084 97.848 ;
    END
  END x_wd[176]
  PIN x_wd[177]
    DIRECTION OUTPUT ;
    USE SIGNAL ;
    PORT
      LAYER M4 ;
        RECT  0 98.016 0.084 98.04 ;
    END
  END x_wd[177]
  PIN x_wd[178]
    DIRECTION OUTPUT ;
    USE SIGNAL ;
    PORT
      LAYER M4 ;
        RECT  0 98.208 0.084 98.232 ;
    END
  END x_wd[178]
  PIN x_wd[179]
    DIRECTION OUTPUT ;
    USE SIGNAL ;
    PORT
      LAYER M4 ;
        RECT  0 98.4 0.084 98.424 ;
    END
  END x_wd[179]
  PIN x_wd[17]
    DIRECTION OUTPUT ;
    USE SIGNAL ;
    PORT
      LAYER M4 ;
        RECT  0 65.76 0.084 65.784 ;
    END
  END x_wd[17]
  PIN x_wd[180]
    DIRECTION OUTPUT ;
    USE SIGNAL ;
    PORT
      LAYER M4 ;
        RECT  0 98.592 0.084 98.616 ;
    END
  END x_wd[180]
  PIN x_wd[181]
    DIRECTION OUTPUT ;
    USE SIGNAL ;
    PORT
      LAYER M4 ;
        RECT  0 98.784 0.084 98.808 ;
    END
  END x_wd[181]
  PIN x_wd[182]
    DIRECTION OUTPUT ;
    USE SIGNAL ;
    PORT
      LAYER M4 ;
        RECT  0 98.976 0.084 99 ;
    END
  END x_wd[182]
  PIN x_wd[183]
    DIRECTION OUTPUT ;
    USE SIGNAL ;
    PORT
      LAYER M4 ;
        RECT  0 99.168 0.084 99.192 ;
    END
  END x_wd[183]
  PIN x_wd[184]
    DIRECTION OUTPUT ;
    USE SIGNAL ;
    PORT
      LAYER M4 ;
        RECT  0 99.36 0.084 99.384 ;
    END
  END x_wd[184]
  PIN x_wd[185]
    DIRECTION OUTPUT ;
    USE SIGNAL ;
    PORT
      LAYER M4 ;
        RECT  0 99.552 0.084 99.576 ;
    END
  END x_wd[185]
  PIN x_wd[186]
    DIRECTION OUTPUT ;
    USE SIGNAL ;
    PORT
      LAYER M4 ;
        RECT  0 99.84 0.084 99.864 ;
    END
  END x_wd[186]
  PIN x_wd[187]
    DIRECTION OUTPUT ;
    USE SIGNAL ;
    PORT
      LAYER M4 ;
        RECT  0 100.032 0.084 100.056 ;
    END
  END x_wd[187]
  PIN x_wd[188]
    DIRECTION OUTPUT ;
    USE SIGNAL ;
    PORT
      LAYER M4 ;
        RECT  0 100.224 0.084 100.248 ;
    END
  END x_wd[188]
  PIN x_wd[189]
    DIRECTION OUTPUT ;
    USE SIGNAL ;
    PORT
      LAYER M4 ;
        RECT  0 100.416 0.084 100.44 ;
    END
  END x_wd[189]
  PIN x_wd[18]
    DIRECTION OUTPUT ;
    USE SIGNAL ;
    PORT
      LAYER M4 ;
        RECT  0 65.952 0.084 65.976 ;
    END
  END x_wd[18]
  PIN x_wd[190]
    DIRECTION OUTPUT ;
    USE SIGNAL ;
    PORT
      LAYER M4 ;
        RECT  0 100.608 0.084 100.632 ;
    END
  END x_wd[190]
  PIN x_wd[191]
    DIRECTION OUTPUT ;
    USE SIGNAL ;
    PORT
      LAYER M4 ;
        RECT  0 100.8 0.084 100.824 ;
    END
  END x_wd[191]
  PIN x_wd[192]
    DIRECTION OUTPUT ;
    USE SIGNAL ;
    PORT
      LAYER M4 ;
        RECT  0 100.992 0.084 101.016 ;
    END
  END x_wd[192]
  PIN x_wd[193]
    DIRECTION OUTPUT ;
    USE SIGNAL ;
    PORT
      LAYER M4 ;
        RECT  0 101.184 0.084 101.208 ;
    END
  END x_wd[193]
  PIN x_wd[194]
    DIRECTION OUTPUT ;
    USE SIGNAL ;
    PORT
      LAYER M4 ;
        RECT  0 101.376 0.084 101.4 ;
    END
  END x_wd[194]
  PIN x_wd[195]
    DIRECTION OUTPUT ;
    USE SIGNAL ;
    PORT
      LAYER M4 ;
        RECT  0 101.568 0.084 101.592 ;
    END
  END x_wd[195]
  PIN x_wd[196]
    DIRECTION OUTPUT ;
    USE SIGNAL ;
    PORT
      LAYER M4 ;
        RECT  0 101.856 0.084 101.88 ;
    END
  END x_wd[196]
  PIN x_wd[197]
    DIRECTION OUTPUT ;
    USE SIGNAL ;
    PORT
      LAYER M4 ;
        RECT  0 102.048 0.084 102.072 ;
    END
  END x_wd[197]
  PIN x_wd[198]
    DIRECTION OUTPUT ;
    USE SIGNAL ;
    PORT
      LAYER M4 ;
        RECT  0 102.24 0.084 102.264 ;
    END
  END x_wd[198]
  PIN x_wd[199]
    DIRECTION OUTPUT ;
    USE SIGNAL ;
    PORT
      LAYER M4 ;
        RECT  0 102.432 0.084 102.456 ;
    END
  END x_wd[199]
  PIN x_wd[19]
    DIRECTION OUTPUT ;
    USE SIGNAL ;
    PORT
      LAYER M4 ;
        RECT  0 66.144 0.084 66.168 ;
    END
  END x_wd[19]
  PIN x_wd[1]
    DIRECTION OUTPUT ;
    USE SIGNAL ;
    PORT
      LAYER M4 ;
        RECT  0 62.496 0.084 62.52 ;
    END
  END x_wd[1]
  PIN x_wd[200]
    DIRECTION OUTPUT ;
    USE SIGNAL ;
    PORT
      LAYER M4 ;
        RECT  0 102.624 0.084 102.648 ;
    END
  END x_wd[200]
  PIN x_wd[201]
    DIRECTION OUTPUT ;
    USE SIGNAL ;
    PORT
      LAYER M4 ;
        RECT  0 102.816 0.084 102.84 ;
    END
  END x_wd[201]
  PIN x_wd[202]
    DIRECTION OUTPUT ;
    USE SIGNAL ;
    PORT
      LAYER M4 ;
        RECT  0 103.008 0.084 103.032 ;
    END
  END x_wd[202]
  PIN x_wd[203]
    DIRECTION OUTPUT ;
    USE SIGNAL ;
    PORT
      LAYER M4 ;
        RECT  0 103.2 0.084 103.224 ;
    END
  END x_wd[203]
  PIN x_wd[204]
    DIRECTION OUTPUT ;
    USE SIGNAL ;
    PORT
      LAYER M4 ;
        RECT  0 103.392 0.084 103.416 ;
    END
  END x_wd[204]
  PIN x_wd[205]
    DIRECTION OUTPUT ;
    USE SIGNAL ;
    PORT
      LAYER M4 ;
        RECT  0 103.584 0.084 103.608 ;
    END
  END x_wd[205]
  PIN x_wd[206]
    DIRECTION OUTPUT ;
    USE SIGNAL ;
    PORT
      LAYER M4 ;
        RECT  0 103.872 0.084 103.896 ;
    END
  END x_wd[206]
  PIN x_wd[207]
    DIRECTION OUTPUT ;
    USE SIGNAL ;
    PORT
      LAYER M4 ;
        RECT  0 104.064 0.084 104.088 ;
    END
  END x_wd[207]
  PIN x_wd[208]
    DIRECTION OUTPUT ;
    USE SIGNAL ;
    PORT
      LAYER M4 ;
        RECT  0 104.256 0.084 104.28 ;
    END
  END x_wd[208]
  PIN x_wd[209]
    DIRECTION OUTPUT ;
    USE SIGNAL ;
    PORT
      LAYER M4 ;
        RECT  0 104.448 0.084 104.472 ;
    END
  END x_wd[209]
  PIN x_wd[20]
    DIRECTION OUTPUT ;
    USE SIGNAL ;
    PORT
      LAYER M4 ;
        RECT  0 66.336 0.084 66.36 ;
    END
  END x_wd[20]
  PIN x_wd[210]
    DIRECTION OUTPUT ;
    USE SIGNAL ;
    PORT
      LAYER M4 ;
        RECT  0 104.64 0.084 104.664 ;
    END
  END x_wd[210]
  PIN x_wd[211]
    DIRECTION OUTPUT ;
    USE SIGNAL ;
    PORT
      LAYER M4 ;
        RECT  0 104.832 0.084 104.856 ;
    END
  END x_wd[211]
  PIN x_wd[212]
    DIRECTION OUTPUT ;
    USE SIGNAL ;
    PORT
      LAYER M4 ;
        RECT  0 105.024 0.084 105.048 ;
    END
  END x_wd[212]
  PIN x_wd[213]
    DIRECTION OUTPUT ;
    USE SIGNAL ;
    PORT
      LAYER M4 ;
        RECT  0 105.216 0.084 105.24 ;
    END
  END x_wd[213]
  PIN x_wd[214]
    DIRECTION OUTPUT ;
    USE SIGNAL ;
    PORT
      LAYER M4 ;
        RECT  0 105.408 0.084 105.432 ;
    END
  END x_wd[214]
  PIN x_wd[215]
    DIRECTION OUTPUT ;
    USE SIGNAL ;
    PORT
      LAYER M4 ;
        RECT  0 105.6 0.084 105.624 ;
    END
  END x_wd[215]
  PIN x_wd[216]
    DIRECTION OUTPUT ;
    USE SIGNAL ;
    PORT
      LAYER M4 ;
        RECT  0 105.888 0.084 105.912 ;
    END
  END x_wd[216]
  PIN x_wd[217]
    DIRECTION OUTPUT ;
    USE SIGNAL ;
    PORT
      LAYER M4 ;
        RECT  0 106.08 0.084 106.104 ;
    END
  END x_wd[217]
  PIN x_wd[218]
    DIRECTION OUTPUT ;
    USE SIGNAL ;
    PORT
      LAYER M4 ;
        RECT  0 106.272 0.084 106.296 ;
    END
  END x_wd[218]
  PIN x_wd[219]
    DIRECTION OUTPUT ;
    USE SIGNAL ;
    PORT
      LAYER M4 ;
        RECT  0 106.464 0.084 106.488 ;
    END
  END x_wd[219]
  PIN x_wd[21]
    DIRECTION OUTPUT ;
    USE SIGNAL ;
    PORT
      LAYER M4 ;
        RECT  0 66.528 0.084 66.552 ;
    END
  END x_wd[21]
  PIN x_wd[220]
    DIRECTION OUTPUT ;
    USE SIGNAL ;
    PORT
      LAYER M4 ;
        RECT  0 106.656 0.084 106.68 ;
    END
  END x_wd[220]
  PIN x_wd[221]
    DIRECTION OUTPUT ;
    USE SIGNAL ;
    PORT
      LAYER M4 ;
        RECT  0 106.848 0.084 106.872 ;
    END
  END x_wd[221]
  PIN x_wd[222]
    DIRECTION OUTPUT ;
    USE SIGNAL ;
    PORT
      LAYER M4 ;
        RECT  0 107.04 0.084 107.064 ;
    END
  END x_wd[222]
  PIN x_wd[223]
    DIRECTION OUTPUT ;
    USE SIGNAL ;
    PORT
      LAYER M4 ;
        RECT  0 107.232 0.084 107.256 ;
    END
  END x_wd[223]
  PIN x_wd[224]
    DIRECTION OUTPUT ;
    USE SIGNAL ;
    PORT
      LAYER M4 ;
        RECT  0 107.424 0.084 107.448 ;
    END
  END x_wd[224]
  PIN x_wd[225]
    DIRECTION OUTPUT ;
    USE SIGNAL ;
    PORT
      LAYER M4 ;
        RECT  0 107.712 0.084 107.736 ;
    END
  END x_wd[225]
  PIN x_wd[226]
    DIRECTION OUTPUT ;
    USE SIGNAL ;
    PORT
      LAYER M4 ;
        RECT  0 107.904 0.084 107.928 ;
    END
  END x_wd[226]
  PIN x_wd[227]
    DIRECTION OUTPUT ;
    USE SIGNAL ;
    PORT
      LAYER M4 ;
        RECT  0 108.096 0.084 108.12 ;
    END
  END x_wd[227]
  PIN x_wd[228]
    DIRECTION OUTPUT ;
    USE SIGNAL ;
    PORT
      LAYER M4 ;
        RECT  0 108.288 0.084 108.312 ;
    END
  END x_wd[228]
  PIN x_wd[229]
    DIRECTION OUTPUT ;
    USE SIGNAL ;
    PORT
      LAYER M4 ;
        RECT  0 108.48 0.084 108.504 ;
    END
  END x_wd[229]
  PIN x_wd[22]
    DIRECTION OUTPUT ;
    USE SIGNAL ;
    PORT
      LAYER M4 ;
        RECT  0 66.72 0.084 66.744 ;
    END
  END x_wd[22]
  PIN x_wd[230]
    DIRECTION OUTPUT ;
    USE SIGNAL ;
    PORT
      LAYER M4 ;
        RECT  0 108.672 0.084 108.696 ;
    END
  END x_wd[230]
  PIN x_wd[231]
    DIRECTION OUTPUT ;
    USE SIGNAL ;
    PORT
      LAYER M4 ;
        RECT  0 108.864 0.084 108.888 ;
    END
  END x_wd[231]
  PIN x_wd[232]
    DIRECTION OUTPUT ;
    USE SIGNAL ;
    PORT
      LAYER M4 ;
        RECT  0 109.056 0.084 109.08 ;
    END
  END x_wd[232]
  PIN x_wd[233]
    DIRECTION OUTPUT ;
    USE SIGNAL ;
    PORT
      LAYER M4 ;
        RECT  0 109.248 0.084 109.272 ;
    END
  END x_wd[233]
  PIN x_wd[234]
    DIRECTION OUTPUT ;
    USE SIGNAL ;
    PORT
      LAYER M4 ;
        RECT  0 109.44 0.084 109.464 ;
    END
  END x_wd[234]
  PIN x_wd[235]
    DIRECTION OUTPUT ;
    USE SIGNAL ;
    PORT
      LAYER M4 ;
        RECT  0 109.728 0.084 109.752 ;
    END
  END x_wd[235]
  PIN x_wd[236]
    DIRECTION OUTPUT ;
    USE SIGNAL ;
    PORT
      LAYER M4 ;
        RECT  0 109.92 0.084 109.944 ;
    END
  END x_wd[236]
  PIN x_wd[237]
    DIRECTION OUTPUT ;
    USE SIGNAL ;
    PORT
      LAYER M4 ;
        RECT  0 110.112 0.084 110.136 ;
    END
  END x_wd[237]
  PIN x_wd[238]
    DIRECTION OUTPUT ;
    USE SIGNAL ;
    PORT
      LAYER M4 ;
        RECT  0 110.304 0.084 110.328 ;
    END
  END x_wd[238]
  PIN x_wd[239]
    DIRECTION OUTPUT ;
    USE SIGNAL ;
    PORT
      LAYER M4 ;
        RECT  0 110.496 0.084 110.52 ;
    END
  END x_wd[239]
  PIN x_wd[23]
    DIRECTION OUTPUT ;
    USE SIGNAL ;
    PORT
      LAYER M4 ;
        RECT  0 66.912 0.084 66.936 ;
    END
  END x_wd[23]
  PIN x_wd[240]
    DIRECTION OUTPUT ;
    USE SIGNAL ;
    PORT
      LAYER M4 ;
        RECT  0 110.688 0.084 110.712 ;
    END
  END x_wd[240]
  PIN x_wd[241]
    DIRECTION OUTPUT ;
    USE SIGNAL ;
    PORT
      LAYER M4 ;
        RECT  0 110.88 0.084 110.904 ;
    END
  END x_wd[241]
  PIN x_wd[242]
    DIRECTION OUTPUT ;
    USE SIGNAL ;
    PORT
      LAYER M4 ;
        RECT  0 111.072 0.084 111.096 ;
    END
  END x_wd[242]
  PIN x_wd[243]
    DIRECTION OUTPUT ;
    USE SIGNAL ;
    PORT
      LAYER M4 ;
        RECT  0 111.264 0.084 111.288 ;
    END
  END x_wd[243]
  PIN x_wd[244]
    DIRECTION OUTPUT ;
    USE SIGNAL ;
    PORT
      LAYER M4 ;
        RECT  0 111.456 0.084 111.48 ;
    END
  END x_wd[244]
  PIN x_wd[245]
    DIRECTION OUTPUT ;
    USE SIGNAL ;
    PORT
      LAYER M4 ;
        RECT  0 111.744 0.084 111.768 ;
    END
  END x_wd[245]
  PIN x_wd[246]
    DIRECTION OUTPUT ;
    USE SIGNAL ;
    PORT
      LAYER M4 ;
        RECT  0 111.936 0.084 111.96 ;
    END
  END x_wd[246]
  PIN x_wd[247]
    DIRECTION OUTPUT ;
    USE SIGNAL ;
    PORT
      LAYER M4 ;
        RECT  0 112.128 0.084 112.152 ;
    END
  END x_wd[247]
  PIN x_wd[248]
    DIRECTION OUTPUT ;
    USE SIGNAL ;
    PORT
      LAYER M4 ;
        RECT  0 112.32 0.084 112.344 ;
    END
  END x_wd[248]
  PIN x_wd[249]
    DIRECTION OUTPUT ;
    USE SIGNAL ;
    PORT
      LAYER M4 ;
        RECT  0 112.512 0.084 112.536 ;
    END
  END x_wd[249]
  PIN x_wd[24]
    DIRECTION OUTPUT ;
    USE SIGNAL ;
    PORT
      LAYER M4 ;
        RECT  0 67.104 0.084 67.128 ;
    END
  END x_wd[24]
  PIN x_wd[250]
    DIRECTION OUTPUT ;
    USE SIGNAL ;
    PORT
      LAYER M4 ;
        RECT  0 112.704 0.084 112.728 ;
    END
  END x_wd[250]
  PIN x_wd[251]
    DIRECTION OUTPUT ;
    USE SIGNAL ;
    PORT
      LAYER M4 ;
        RECT  0 112.896 0.084 112.92 ;
    END
  END x_wd[251]
  PIN x_wd[252]
    DIRECTION OUTPUT ;
    USE SIGNAL ;
    PORT
      LAYER M4 ;
        RECT  0 113.088 0.084 113.112 ;
    END
  END x_wd[252]
  PIN x_wd[253]
    DIRECTION OUTPUT ;
    USE SIGNAL ;
    PORT
      LAYER M4 ;
        RECT  0 113.28 0.084 113.304 ;
    END
  END x_wd[253]
  PIN x_wd[254]
    DIRECTION OUTPUT ;
    USE SIGNAL ;
    PORT
      LAYER M4 ;
        RECT  0 113.472 0.084 113.496 ;
    END
  END x_wd[254]
  PIN x_wd[255]
    DIRECTION OUTPUT ;
    USE SIGNAL ;
    PORT
      LAYER M4 ;
        RECT  0 113.76 0.084 113.784 ;
    END
  END x_wd[255]
  PIN x_wd[25]
    DIRECTION OUTPUT ;
    USE SIGNAL ;
    PORT
      LAYER M4 ;
        RECT  0 67.296 0.084 67.32 ;
    END
  END x_wd[25]
  PIN x_wd[26]
    DIRECTION OUTPUT ;
    USE SIGNAL ;
    PORT
      LAYER M4 ;
        RECT  0 67.488 0.084 67.512 ;
    END
  END x_wd[26]
  PIN x_wd[27]
    DIRECTION OUTPUT ;
    USE SIGNAL ;
    PORT
      LAYER M4 ;
        RECT  0 67.776 0.084 67.8 ;
    END
  END x_wd[27]
  PIN x_wd[28]
    DIRECTION OUTPUT ;
    USE SIGNAL ;
    PORT
      LAYER M4 ;
        RECT  0 67.968 0.084 67.992 ;
    END
  END x_wd[28]
  PIN x_wd[29]
    DIRECTION OUTPUT ;
    USE SIGNAL ;
    PORT
      LAYER M4 ;
        RECT  0 68.16 0.084 68.184 ;
    END
  END x_wd[29]
  PIN x_wd[2]
    DIRECTION OUTPUT ;
    USE SIGNAL ;
    PORT
      LAYER M4 ;
        RECT  0 62.688 0.084 62.712 ;
    END
  END x_wd[2]
  PIN x_wd[30]
    DIRECTION OUTPUT ;
    USE SIGNAL ;
    PORT
      LAYER M4 ;
        RECT  0 68.352 0.084 68.376 ;
    END
  END x_wd[30]
  PIN x_wd[31]
    DIRECTION OUTPUT ;
    USE SIGNAL ;
    PORT
      LAYER M4 ;
        RECT  0 68.544 0.084 68.568 ;
    END
  END x_wd[31]
  PIN x_wd[32]
    DIRECTION OUTPUT ;
    USE SIGNAL ;
    PORT
      LAYER M4 ;
        RECT  0 68.736 0.084 68.76 ;
    END
  END x_wd[32]
  PIN x_wd[33]
    DIRECTION OUTPUT ;
    USE SIGNAL ;
    PORT
      LAYER M4 ;
        RECT  0 68.928 0.084 68.952 ;
    END
  END x_wd[33]
  PIN x_wd[34]
    DIRECTION OUTPUT ;
    USE SIGNAL ;
    PORT
      LAYER M4 ;
        RECT  0 69.12 0.084 69.144 ;
    END
  END x_wd[34]
  PIN x_wd[35]
    DIRECTION OUTPUT ;
    USE SIGNAL ;
    PORT
      LAYER M4 ;
        RECT  0 69.312 0.084 69.336 ;
    END
  END x_wd[35]
  PIN x_wd[36]
    DIRECTION OUTPUT ;
    USE SIGNAL ;
    PORT
      LAYER M4 ;
        RECT  0 69.504 0.084 69.528 ;
    END
  END x_wd[36]
  PIN x_wd[37]
    DIRECTION OUTPUT ;
    USE SIGNAL ;
    PORT
      LAYER M4 ;
        RECT  0 69.792 0.084 69.816 ;
    END
  END x_wd[37]
  PIN x_wd[38]
    DIRECTION OUTPUT ;
    USE SIGNAL ;
    PORT
      LAYER M4 ;
        RECT  0 69.984 0.084 70.008 ;
    END
  END x_wd[38]
  PIN x_wd[39]
    DIRECTION OUTPUT ;
    USE SIGNAL ;
    PORT
      LAYER M4 ;
        RECT  0 70.176 0.084 70.2 ;
    END
  END x_wd[39]
  PIN x_wd[3]
    DIRECTION OUTPUT ;
    USE SIGNAL ;
    PORT
      LAYER M4 ;
        RECT  0 62.88 0.084 62.904 ;
    END
  END x_wd[3]
  PIN x_wd[40]
    DIRECTION OUTPUT ;
    USE SIGNAL ;
    PORT
      LAYER M4 ;
        RECT  0 70.368 0.084 70.392 ;
    END
  END x_wd[40]
  PIN x_wd[41]
    DIRECTION OUTPUT ;
    USE SIGNAL ;
    PORT
      LAYER M4 ;
        RECT  0 70.56 0.084 70.584 ;
    END
  END x_wd[41]
  PIN x_wd[42]
    DIRECTION OUTPUT ;
    USE SIGNAL ;
    PORT
      LAYER M4 ;
        RECT  0 70.752 0.084 70.776 ;
    END
  END x_wd[42]
  PIN x_wd[43]
    DIRECTION OUTPUT ;
    USE SIGNAL ;
    PORT
      LAYER M4 ;
        RECT  0 70.944 0.084 70.968 ;
    END
  END x_wd[43]
  PIN x_wd[44]
    DIRECTION OUTPUT ;
    USE SIGNAL ;
    PORT
      LAYER M4 ;
        RECT  0 71.136 0.084 71.16 ;
    END
  END x_wd[44]
  PIN x_wd[45]
    DIRECTION OUTPUT ;
    USE SIGNAL ;
    PORT
      LAYER M4 ;
        RECT  0 71.328 0.084 71.352 ;
    END
  END x_wd[45]
  PIN x_wd[46]
    DIRECTION OUTPUT ;
    USE SIGNAL ;
    PORT
      LAYER M4 ;
        RECT  0 71.52 0.084 71.544 ;
    END
  END x_wd[46]
  PIN x_wd[47]
    DIRECTION OUTPUT ;
    USE SIGNAL ;
    PORT
      LAYER M4 ;
        RECT  0 71.808 0.084 71.832 ;
    END
  END x_wd[47]
  PIN x_wd[48]
    DIRECTION OUTPUT ;
    USE SIGNAL ;
    PORT
      LAYER M4 ;
        RECT  0 72 0.084 72.024 ;
    END
  END x_wd[48]
  PIN x_wd[49]
    DIRECTION OUTPUT ;
    USE SIGNAL ;
    PORT
      LAYER M4 ;
        RECT  0 72.192 0.084 72.216 ;
    END
  END x_wd[49]
  PIN x_wd[4]
    DIRECTION OUTPUT ;
    USE SIGNAL ;
    PORT
      LAYER M4 ;
        RECT  0 63.072 0.084 63.096 ;
    END
  END x_wd[4]
  PIN x_wd[50]
    DIRECTION OUTPUT ;
    USE SIGNAL ;
    PORT
      LAYER M4 ;
        RECT  0 72.384 0.084 72.408 ;
    END
  END x_wd[50]
  PIN x_wd[51]
    DIRECTION OUTPUT ;
    USE SIGNAL ;
    PORT
      LAYER M4 ;
        RECT  0 72.576 0.084 72.6 ;
    END
  END x_wd[51]
  PIN x_wd[52]
    DIRECTION OUTPUT ;
    USE SIGNAL ;
    PORT
      LAYER M4 ;
        RECT  0 72.768 0.084 72.792 ;
    END
  END x_wd[52]
  PIN x_wd[53]
    DIRECTION OUTPUT ;
    USE SIGNAL ;
    PORT
      LAYER M4 ;
        RECT  0 72.96 0.084 72.984 ;
    END
  END x_wd[53]
  PIN x_wd[54]
    DIRECTION OUTPUT ;
    USE SIGNAL ;
    PORT
      LAYER M4 ;
        RECT  0 73.152 0.084 73.176 ;
    END
  END x_wd[54]
  PIN x_wd[55]
    DIRECTION OUTPUT ;
    USE SIGNAL ;
    PORT
      LAYER M4 ;
        RECT  0 73.344 0.084 73.368 ;
    END
  END x_wd[55]
  PIN x_wd[56]
    DIRECTION OUTPUT ;
    USE SIGNAL ;
    PORT
      LAYER M4 ;
        RECT  0 73.536 0.084 73.56 ;
    END
  END x_wd[56]
  PIN x_wd[57]
    DIRECTION OUTPUT ;
    USE SIGNAL ;
    PORT
      LAYER M4 ;
        RECT  0 73.824 0.084 73.848 ;
    END
  END x_wd[57]
  PIN x_wd[58]
    DIRECTION OUTPUT ;
    USE SIGNAL ;
    PORT
      LAYER M4 ;
        RECT  0 74.016 0.084 74.04 ;
    END
  END x_wd[58]
  PIN x_wd[59]
    DIRECTION OUTPUT ;
    USE SIGNAL ;
    PORT
      LAYER M4 ;
        RECT  0 74.208 0.084 74.232 ;
    END
  END x_wd[59]
  PIN x_wd[5]
    DIRECTION OUTPUT ;
    USE SIGNAL ;
    PORT
      LAYER M4 ;
        RECT  0 63.264 0.084 63.288 ;
    END
  END x_wd[5]
  PIN x_wd[60]
    DIRECTION OUTPUT ;
    USE SIGNAL ;
    PORT
      LAYER M4 ;
        RECT  0 74.4 0.084 74.424 ;
    END
  END x_wd[60]
  PIN x_wd[61]
    DIRECTION OUTPUT ;
    USE SIGNAL ;
    PORT
      LAYER M4 ;
        RECT  0 74.592 0.084 74.616 ;
    END
  END x_wd[61]
  PIN x_wd[62]
    DIRECTION OUTPUT ;
    USE SIGNAL ;
    PORT
      LAYER M4 ;
        RECT  0 74.784 0.084 74.808 ;
    END
  END x_wd[62]
  PIN x_wd[63]
    DIRECTION OUTPUT ;
    USE SIGNAL ;
    PORT
      LAYER M4 ;
        RECT  0 74.976 0.084 75 ;
    END
  END x_wd[63]
  PIN x_wd[64]
    DIRECTION OUTPUT ;
    USE SIGNAL ;
    PORT
      LAYER M4 ;
        RECT  0 75.168 0.084 75.192 ;
    END
  END x_wd[64]
  PIN x_wd[65]
    DIRECTION OUTPUT ;
    USE SIGNAL ;
    PORT
      LAYER M4 ;
        RECT  0 75.36 0.084 75.384 ;
    END
  END x_wd[65]
  PIN x_wd[66]
    DIRECTION OUTPUT ;
    USE SIGNAL ;
    PORT
      LAYER M4 ;
        RECT  0 75.552 0.084 75.576 ;
    END
  END x_wd[66]
  PIN x_wd[67]
    DIRECTION OUTPUT ;
    USE SIGNAL ;
    PORT
      LAYER M4 ;
        RECT  0 75.84 0.084 75.864 ;
    END
  END x_wd[67]
  PIN x_wd[68]
    DIRECTION OUTPUT ;
    USE SIGNAL ;
    PORT
      LAYER M4 ;
        RECT  0 76.032 0.084 76.056 ;
    END
  END x_wd[68]
  PIN x_wd[69]
    DIRECTION OUTPUT ;
    USE SIGNAL ;
    PORT
      LAYER M4 ;
        RECT  0 76.224 0.084 76.248 ;
    END
  END x_wd[69]
  PIN x_wd[6]
    DIRECTION OUTPUT ;
    USE SIGNAL ;
    PORT
      LAYER M4 ;
        RECT  0 63.456 0.084 63.48 ;
    END
  END x_wd[6]
  PIN x_wd[70]
    DIRECTION OUTPUT ;
    USE SIGNAL ;
    PORT
      LAYER M4 ;
        RECT  0 76.416 0.084 76.44 ;
    END
  END x_wd[70]
  PIN x_wd[71]
    DIRECTION OUTPUT ;
    USE SIGNAL ;
    PORT
      LAYER M4 ;
        RECT  0 76.608 0.084 76.632 ;
    END
  END x_wd[71]
  PIN x_wd[72]
    DIRECTION OUTPUT ;
    USE SIGNAL ;
    PORT
      LAYER M4 ;
        RECT  0 76.8 0.084 76.824 ;
    END
  END x_wd[72]
  PIN x_wd[73]
    DIRECTION OUTPUT ;
    USE SIGNAL ;
    PORT
      LAYER M4 ;
        RECT  0 76.992 0.084 77.016 ;
    END
  END x_wd[73]
  PIN x_wd[74]
    DIRECTION OUTPUT ;
    USE SIGNAL ;
    PORT
      LAYER M4 ;
        RECT  0 77.184 0.084 77.208 ;
    END
  END x_wd[74]
  PIN x_wd[75]
    DIRECTION OUTPUT ;
    USE SIGNAL ;
    PORT
      LAYER M4 ;
        RECT  0 77.376 0.084 77.4 ;
    END
  END x_wd[75]
  PIN x_wd[76]
    DIRECTION OUTPUT ;
    USE SIGNAL ;
    PORT
      LAYER M4 ;
        RECT  0 77.568 0.084 77.592 ;
    END
  END x_wd[76]
  PIN x_wd[77]
    DIRECTION OUTPUT ;
    USE SIGNAL ;
    PORT
      LAYER M4 ;
        RECT  0 77.856 0.084 77.88 ;
    END
  END x_wd[77]
  PIN x_wd[78]
    DIRECTION OUTPUT ;
    USE SIGNAL ;
    PORT
      LAYER M4 ;
        RECT  0 78.048 0.084 78.072 ;
    END
  END x_wd[78]
  PIN x_wd[79]
    DIRECTION OUTPUT ;
    USE SIGNAL ;
    PORT
      LAYER M4 ;
        RECT  0 78.24 0.084 78.264 ;
    END
  END x_wd[79]
  PIN x_wd[7]
    DIRECTION OUTPUT ;
    USE SIGNAL ;
    PORT
      LAYER M4 ;
        RECT  0 63.744 0.084 63.768 ;
    END
  END x_wd[7]
  PIN x_wd[80]
    DIRECTION OUTPUT ;
    USE SIGNAL ;
    PORT
      LAYER M4 ;
        RECT  0 78.432 0.084 78.456 ;
    END
  END x_wd[80]
  PIN x_wd[81]
    DIRECTION OUTPUT ;
    USE SIGNAL ;
    PORT
      LAYER M4 ;
        RECT  0 78.624 0.084 78.648 ;
    END
  END x_wd[81]
  PIN x_wd[82]
    DIRECTION OUTPUT ;
    USE SIGNAL ;
    PORT
      LAYER M4 ;
        RECT  0 78.816 0.084 78.84 ;
    END
  END x_wd[82]
  PIN x_wd[83]
    DIRECTION OUTPUT ;
    USE SIGNAL ;
    PORT
      LAYER M4 ;
        RECT  0 79.008 0.084 79.032 ;
    END
  END x_wd[83]
  PIN x_wd[84]
    DIRECTION OUTPUT ;
    USE SIGNAL ;
    PORT
      LAYER M4 ;
        RECT  0 79.2 0.084 79.224 ;
    END
  END x_wd[84]
  PIN x_wd[85]
    DIRECTION OUTPUT ;
    USE SIGNAL ;
    PORT
      LAYER M4 ;
        RECT  0 79.392 0.084 79.416 ;
    END
  END x_wd[85]
  PIN x_wd[86]
    DIRECTION OUTPUT ;
    USE SIGNAL ;
    PORT
      LAYER M4 ;
        RECT  0 79.68 0.084 79.704 ;
    END
  END x_wd[86]
  PIN x_wd[87]
    DIRECTION OUTPUT ;
    USE SIGNAL ;
    PORT
      LAYER M4 ;
        RECT  0 79.872 0.084 79.896 ;
    END
  END x_wd[87]
  PIN x_wd[88]
    DIRECTION OUTPUT ;
    USE SIGNAL ;
    PORT
      LAYER M4 ;
        RECT  0 80.064 0.084 80.088 ;
    END
  END x_wd[88]
  PIN x_wd[89]
    DIRECTION OUTPUT ;
    USE SIGNAL ;
    PORT
      LAYER M4 ;
        RECT  0 80.256 0.084 80.28 ;
    END
  END x_wd[89]
  PIN x_wd[8]
    DIRECTION OUTPUT ;
    USE SIGNAL ;
    PORT
      LAYER M4 ;
        RECT  0 63.936 0.084 63.96 ;
    END
  END x_wd[8]
  PIN x_wd[90]
    DIRECTION OUTPUT ;
    USE SIGNAL ;
    PORT
      LAYER M4 ;
        RECT  0 80.448 0.084 80.472 ;
    END
  END x_wd[90]
  PIN x_wd[91]
    DIRECTION OUTPUT ;
    USE SIGNAL ;
    PORT
      LAYER M4 ;
        RECT  0 80.64 0.084 80.664 ;
    END
  END x_wd[91]
  PIN x_wd[92]
    DIRECTION OUTPUT ;
    USE SIGNAL ;
    PORT
      LAYER M4 ;
        RECT  0 80.832 0.084 80.856 ;
    END
  END x_wd[92]
  PIN x_wd[93]
    DIRECTION OUTPUT ;
    USE SIGNAL ;
    PORT
      LAYER M4 ;
        RECT  0 81.024 0.084 81.048 ;
    END
  END x_wd[93]
  PIN x_wd[94]
    DIRECTION OUTPUT ;
    USE SIGNAL ;
    PORT
      LAYER M4 ;
        RECT  0 81.216 0.084 81.24 ;
    END
  END x_wd[94]
  PIN x_wd[95]
    DIRECTION OUTPUT ;
    USE SIGNAL ;
    PORT
      LAYER M4 ;
        RECT  0 81.408 0.084 81.432 ;
    END
  END x_wd[95]
  PIN x_wd[96]
    DIRECTION OUTPUT ;
    USE SIGNAL ;
    PORT
      LAYER M4 ;
        RECT  0 81.696 0.084 81.72 ;
    END
  END x_wd[96]
  PIN x_wd[97]
    DIRECTION OUTPUT ;
    USE SIGNAL ;
    PORT
      LAYER M4 ;
        RECT  0 81.888 0.084 81.912 ;
    END
  END x_wd[97]
  PIN x_wd[98]
    DIRECTION OUTPUT ;
    USE SIGNAL ;
    PORT
      LAYER M4 ;
        RECT  0 82.08 0.084 82.104 ;
    END
  END x_wd[98]
  PIN x_wd[99]
    DIRECTION OUTPUT ;
    USE SIGNAL ;
    PORT
      LAYER M4 ;
        RECT  0 82.272 0.084 82.296 ;
    END
  END x_wd[99]
  PIN x_wd[9]
    DIRECTION OUTPUT ;
    USE SIGNAL ;
    PORT
      LAYER M4 ;
        RECT  0 64.128 0.084 64.152 ;
    END
  END x_wd[9]
  PIN x_wm[0]
    DIRECTION OUTPUT ;
    USE SIGNAL ;
    PORT
      LAYER M4 ;
        RECT  0 60.672 0.084 60.696 ;
    END
  END x_wm[0]
  PIN x_wm[1]
    DIRECTION OUTPUT ;
    USE SIGNAL ;
    PORT
      LAYER M4 ;
        RECT  0 60.864 0.084 60.888 ;
    END
  END x_wm[1]
  PIN x_wm[2]
    DIRECTION OUTPUT ;
    USE SIGNAL ;
    PORT
      LAYER M4 ;
        RECT  0 61.056 0.084 61.08 ;
    END
  END x_wm[2]
  PIN x_wm[3]
    DIRECTION OUTPUT ;
    USE SIGNAL ;
    PORT
      LAYER M4 ;
        RECT  0 61.248 0.084 61.272 ;
    END
  END x_wm[3]
  PIN x_wm[4]
    DIRECTION OUTPUT ;
    USE SIGNAL ;
    PORT
      LAYER M4 ;
        RECT  0 61.44 0.084 61.464 ;
    END
  END x_wm[4]
  PIN x_wm[5]
    DIRECTION OUTPUT ;
    USE SIGNAL ;
    PORT
      LAYER M4 ;
        RECT  0 61.728 0.084 61.752 ;
    END
  END x_wm[5]
  PIN x_wm[6]
    DIRECTION OUTPUT ;
    USE SIGNAL ;
    PORT
      LAYER M4 ;
        RECT  0 61.92 0.084 61.944 ;
    END
  END x_wm[6]
  PIN x_wm[7]
    DIRECTION OUTPUT ;
    USE SIGNAL ;
    PORT
      LAYER M4 ;
        RECT  0 62.112 0.084 62.136 ;
    END
  END x_wm[7]
  PIN x_wv
    DIRECTION OUTPUT ;
    USE SIGNAL ;
    PORT
      LAYER M4 ;
        RECT  0 58.464 0.084 58.488 ;
    END
  END x_wv
  PIN VDD
    DIRECTION INOUT ;
    USE POWER ;
    PORT
      LAYER M5 ;
        RECT  166.356 4.311 166.476 168.489 ;
        RECT  162.036 4.311 162.156 168.489 ;
        RECT  157.716 4.311 157.836 168.489 ;
        RECT  153.396 4.311 153.516 168.489 ;
        RECT  149.076 4.311 149.196 168.489 ;
        RECT  144.756 4.311 144.876 168.489 ;
        RECT  140.436 4.311 140.556 168.489 ;
        RECT  136.116 4.311 136.236 168.489 ;
        RECT  131.796 4.311 131.916 168.489 ;
        RECT  127.476 4.311 127.596 168.489 ;
        RECT  123.156 4.311 123.276 168.489 ;
        RECT  118.836 4.311 118.956 168.489 ;
        RECT  114.516 4.311 114.636 168.489 ;
        RECT  110.196 4.311 110.316 168.489 ;
        RECT  105.876 4.311 105.996 168.489 ;
        RECT  101.556 4.311 101.676 168.489 ;
        RECT  97.236 4.311 97.356 168.489 ;
        RECT  92.916 4.311 93.036 168.489 ;
        RECT  88.596 4.311 88.716 168.489 ;
        RECT  84.276 4.311 84.396 168.489 ;
        RECT  79.956 4.311 80.076 168.489 ;
        RECT  75.636 4.311 75.756 168.489 ;
        RECT  71.316 4.311 71.436 168.489 ;
        RECT  66.996 4.311 67.116 168.489 ;
        RECT  62.676 4.311 62.796 168.489 ;
        RECT  58.356 4.311 58.476 168.489 ;
        RECT  54.036 4.311 54.156 168.489 ;
        RECT  49.716 4.311 49.836 168.489 ;
        RECT  45.396 4.311 45.516 168.489 ;
        RECT  41.076 4.311 41.196 168.489 ;
        RECT  36.756 4.311 36.876 168.489 ;
        RECT  32.436 4.311 32.556 168.489 ;
        RECT  28.116 4.311 28.236 168.489 ;
        RECT  23.796 4.311 23.916 168.489 ;
        RECT  19.476 4.311 19.596 168.489 ;
        RECT  15.156 4.311 15.276 168.489 ;
        RECT  10.836 4.311 10.956 168.489 ;
        RECT  6.516 4.311 6.636 168.489 ;
    END
  END VDD
  PIN VSS
    DIRECTION INOUT ;
    USE GROUND ;
    PORT
      LAYER M5 ;
        RECT  166.164 4.297 166.284 168.503 ;
        RECT  161.844 4.297 161.964 168.503 ;
        RECT  157.524 4.297 157.644 168.503 ;
        RECT  153.204 4.297 153.324 168.503 ;
        RECT  148.884 4.297 149.004 168.503 ;
        RECT  144.564 4.297 144.684 168.503 ;
        RECT  140.244 4.297 140.364 168.503 ;
        RECT  135.924 4.297 136.044 168.503 ;
        RECT  131.604 4.297 131.724 168.503 ;
        RECT  127.284 4.297 127.404 168.503 ;
        RECT  122.964 4.297 123.084 168.503 ;
        RECT  118.644 4.297 118.764 168.503 ;
        RECT  114.324 4.297 114.444 168.503 ;
        RECT  110.004 4.297 110.124 168.503 ;
        RECT  105.684 4.297 105.804 168.503 ;
        RECT  101.364 4.297 101.484 168.503 ;
        RECT  97.044 4.297 97.164 168.503 ;
        RECT  92.724 4.297 92.844 168.503 ;
        RECT  88.404 4.297 88.524 168.503 ;
        RECT  84.084 4.297 84.204 168.503 ;
        RECT  79.764 4.297 79.884 168.503 ;
        RECT  75.444 4.297 75.564 168.503 ;
        RECT  71.124 4.297 71.244 168.503 ;
        RECT  66.804 4.297 66.924 168.503 ;
        RECT  62.484 4.297 62.604 168.503 ;
        RECT  58.164 4.297 58.284 168.503 ;
        RECT  53.844 4.297 53.964 168.503 ;
        RECT  49.524 4.297 49.644 168.503 ;
        RECT  45.204 4.297 45.324 168.503 ;
        RECT  40.884 4.297 41.004 168.503 ;
        RECT  36.564 4.297 36.684 168.503 ;
        RECT  32.244 4.297 32.364 168.503 ;
        RECT  27.924 4.297 28.044 168.503 ;
        RECT  23.604 4.297 23.724 168.503 ;
        RECT  19.284 4.297 19.404 168.503 ;
        RECT  14.964 4.297 15.084 168.503 ;
        RECT  10.644 4.297 10.764 168.503 ;
        RECT  6.324 4.297 6.444 168.503 ;
    END
  END VSS
  OBS
    LAYER RVTN ;
     RECT  0 0 172.8 172.8 ;
    LAYER RVTP ;
     RECT  0 0 172.8 172.8 ;
    LAYER M1 ;
     RECT  0 0 172.8 172.8 ;
    LAYER M2 ;
     RECT  0 0 172.8 172.8 ;
    LAYER M3 ;
     RECT  0 0 172.8 172.8 ;
    LAYER M4 ;
     RECT  0 0 172.8 172.8 ;
    LAYER M5 ;
     RECT  0 0 172.8 172.8 ;
  END
END ot_s81sl_vs
END LIBRARY
